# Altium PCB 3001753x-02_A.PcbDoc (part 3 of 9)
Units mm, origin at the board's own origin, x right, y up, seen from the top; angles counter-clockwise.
Board outline 210 x 130 mm, 8 copper layers (1-TOP, 2-GND, 3-INTOP, 4-PWR, 5-PWR, 6-INBOT, 7-GND, 8-BOTTOM), stack 1.646 mm thick; 651 components, 607 nets, 2780 pads, 1706 vias.

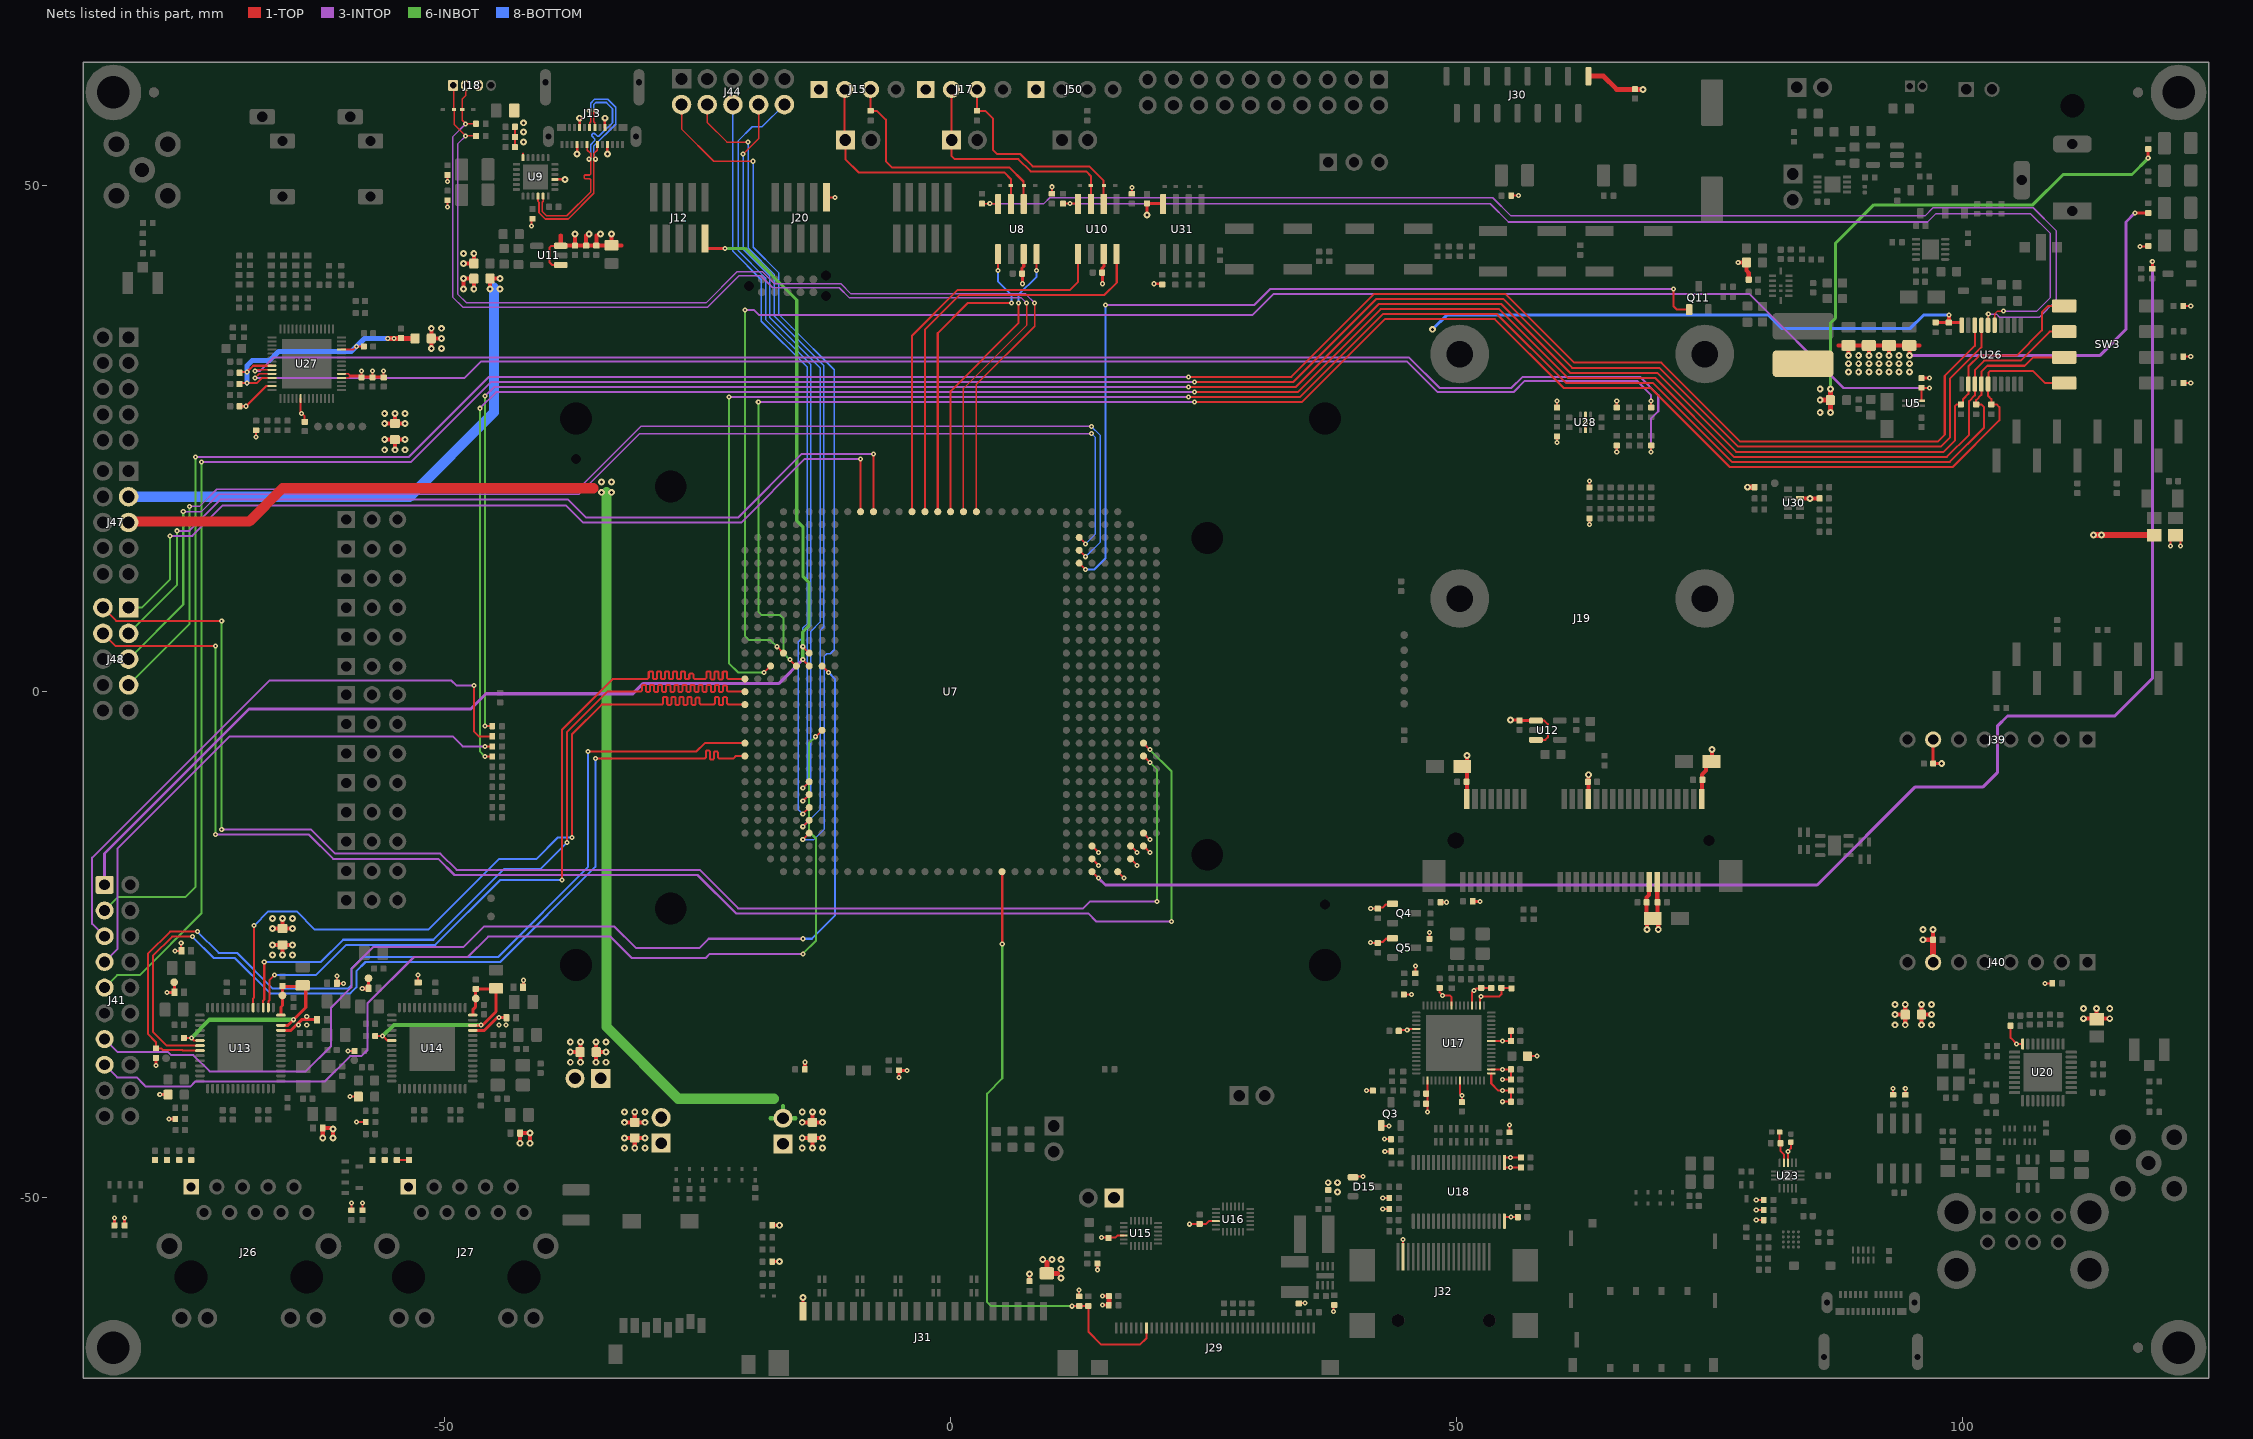
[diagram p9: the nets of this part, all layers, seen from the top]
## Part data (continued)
L17 L22 L23 L24 L25 L28 L38 L39: library part 1001174, "FERRITE BEAD 220 OHM 2.0A 0805", Manufacturer="Wurth Electronics Inc", Manufacturer_Part_Number=742792022, Package_Type=0805
L26 L27: library part 1001173, "CHOKE COM MODE 120 OHM .37A", Manufacturer="Wurth Electronics Inc", Package_Type=SMT
L32 L33 L34 L35 L36 L37: library part 1002041, "FERRITE BEAD 1.8 KOHM 0402 1LN", Manufacturer=Murata, Manufacturer_Part_Number=BLM15HD182SN1D, Package_Type=0402
L42: library part 1002050, "FIXED IND 22UH 590MA 432 MOHM", Manufacturer="Taiyo Yuden", Manufacturer_Part_Number=NR4018T220M, Package_Type=SMT
Q1 Q3 Q4 Q5 Q6: library part 1002855, "MOSFET N-CH 20V 3.4A SOT23-3", Manufacturer="Diodes, Inc.", Manufacturer_Part_Number=ZXMN2A14F, Package_Type=SOT23
Q2 Q11: library part 1000306, "MOSFET N-CH 30V 500MA SOT-23", Manufacturer="On Semiconductor", Package_Type=SOT23
Q7 Q8 Q9 Q10 Q12: library part 1000715, "MOSFET N-CH 60V 115MA SOT-523F", Manufacturer="Fairchild Semiconductor", Package_Type=SOT523F
R1 R127 R144 R146 R147 R148 R149: library part 1001155, "RES 47.0K OHM 1/16W 1% 0402 SMD", Manufacturer="Vishay Dale", Manufacturer_Part_Number=CRCW040247K0FKED, Package_Type=0402, Tolerance=1%
R2 R4 R5 R6 R9 R11 R13 R18 R26 R36 R37 R39 R40 R41 R42 R45 R46 R47 R48 R49 R52 R53 R54 R55 R56 R57 R58 R59 R60 R61 R62 R63 R64 R65 R68 R69 R75 R81 R84 R85 R87 R88 R94 R95 R96 R104 R113 R119 R121 R125 R132 R135 R138 R161 R162 R163 R164 R166 R167 R168 R169 R176 R177 R178 R179 R182 R183 R184 R185 R186 R187 R188 R189 R190 R191 R193 R194 R196 R197 R200 R212 R213 R216 R219 R220 R221 R222 R223 R226 R227 R228 R230 R231 R233 R234 R235: library part 1000076, "RES 0.0 OHM 1/10W 0402 SMD", Manufacturer="Panasonic - ECG", Manufacturer_Part_Number=ERJ-2GE0R00X, Package_Type=0402, Power=10
R3 R8 R14 R25 R29 R30 R82 R91 R157 R158 R159 R202 R203 R204: library part 1000480, "RES 100K OHM 1/10W 1% 0402 SMD", Manufacturer="Panasonic - ECG", Manufacturer_Part_Number=ERJ-2RKF1003X, Package_Type=0402, Power=100, Tolerance=1%
R7 R10 R50 R51 R72 R80 R90 R92 R115 R117 R118 R122 R139 R140 R143 R151 R160 R192 R198 R214 R215 R218 R224 R225 R229 R232: library part 1000537, "RES 10.0K OHM 1/10W 1% 0402 SMD", Manufacturer="Panasonic - ECG", Manufacturer_Part_Number=ERJ-2RKF1002X, Package_Type=0402, Power=100, Tolerance=1%
R12 R15 R154 R195: library part 1001154, "RES 220 OHM 1/16W 1% 0402 SMD", Manufacturer=Yageo, Manufacturer_Part_Number=RC0402FR-07220RL, Package_Type=0402, Tolerance=1%
R16 R17 R23 R24 R33 R34 R35 R38 R43 R44 R73 R74 R101 R102 R105 R110 R111 R116 R141 R170 R171 R205: library part 1000208, "RES 0.0 OHM 1/10W 0603", Manufacturer="Panasonic - ECG", Manufacturer_Part_Number=ERJ-3GEY0R00V, Package_Type=0603, Voltage=75V
R19 R32 R76 R145: library part 1001200, "RES 12.0K OHM 1/10W 1% 0603 SMD", Manufacturer=Yageo, Manufacturer_Part_Number=RC0603FR-0712KL, Package_Type=0603, Power=100, Tolerance=1
R20 R131 R134 R137 R165 R173 R175 R180 R181: library part 1001156, "RES 2.20K OHM 1/16W 1% 0402 SMD", Manufacturer=Yageo, Manufacturer_Part_Number=RC0402FR-072K2L, Package_Type=0402, Tolerance=1%
R21 R79 R83: library part 1000142, "RES 20K OHM 1/10W 5% 0603 SMD", Manufacturer="Panasonic - ECG", Manufacturer_Part_Number=ERJ-3GEYJ203V, Package_Type=0603, Power=100, Tolerance=5
R22: library part 1000980, "RES 2.2M OHM 1/20W 5% 0201 SMD", Manufacturer=Rohm, Manufacturer_Alt_1="Panasonic - ECG", Manufacturer_Alt_1_Part_Number=ERJ-1GEJ225C, Manufacturer_Part_Number=MCR006YZPJ225, Package_Type=0201, Power=50, Tolerance=5
R27 R31: library part 1000701, "RES 470K OHM 1/10W 1% 0402 SMD", Manufacturer="Panasonic - ECG", Manufacturer_Part_Number=ERJ-2RKF4703X, Package_Type=0402, Power=100, Tolerance=1%
R28: library part 1001518, "RES 53.6K OHM 1/10W 1% 0603 SMD", Manufacturer="Panasonic - ECG", Manufacturer_Part_Number=ERJ-3EKF5362V, Package_Type=0603
R66 R70 R71 R77 R97 R98 R107 R108 R206 R207 R208 R209 R236: library part 1001158, "RES 120 OHM 1/16W 1% 0402 SMD", Manufacturer=Yageo, Manufacturer_Part_Number=RC0402FR-07120RL, Package_Type=0402, Tolerance=1%
R67 R78 R130 R133 R136 R172 R174 R199: library part 1000079, "RES 1.00K OHM 1/10W 1% 0402 SMD", Manufacturer="Panasonic - ECG", Manufacturer_Part_Number=ERJ-2RKF1001X, Package_Type=0402, Power=10
R86 R89 R93: library part 1000601, "RES 22.0 OHM 1/10W 1% 0402 SMD", Manufacturer="Panasonic - ECG", Manufacturer_Part_Number=ERJ-2RKF22R0X, Package_Type=0402, Power=100, Tolerance=1%
R99 R106 R109 R114: library part 1000474, "RES 4.99K OHM 1/10W 1% 0402 SMD", Manufacturer="Panasonic - ECG", Manufacturer_Part_Number=ERJ-2RKF4991X, Package_Type=0402, Power=100, Tolerance=1%
R100: library part 1000229, "RES 0.0 OHM 1/2W 1210 SMD", Manufacturer="Vishay Dale", Manufacturer_Part_Number=CRCW12100000Z0EA, Package_Type=1210
R103 R112: library part 1000537, "RES 10.0K OHM 1/10W 1% 0402 SMD"
R120: library part 1001153, "RES 27.0K OHM 1/16W 1% 0402 SMD", Manufacturer=Yageo, Manufacturer_Part_Number=RC0402FR-0727KL, Package_Type=0402, Tolerance=1%
R123 R142: library part 1000971, "RES 1.00M OHM 1/16W 1% 0402 SMD", Manufacturer=Yageo, Manufacturer_Part_Number=RC0402FR-071ML, Package_Type=0402, Power=63, Tolerance=1
R124: library part 1002748, "RES 5.97K OHM 0.1% 1/10W 0402", Manufacturer="Vishay Dale", Manufacturer_Part_Number=TNPW04025K97BEED, Package_Type=0402
R126: library part 1000174, "RES 15.0K OHM 1/10W 1% 0402 SMD", Manufacturer="Panasonic - ECG", Manufacturer_Part_Number=ERJ-2RKF1502X, Package_Type=0402, Power=10, Tolerance=1%
R128 R129 R153 R155 R156: library part 1000038, "RES 4.7K OHM 1/10W 5% 0402 SMD", Manufacturer="Panasonic - ECG", Manufacturer_Part_Number=ERJ-2GEJ472X, Package_Type=0402, Power=100, Tolerance=5
R150: library part 1000170, "RES 52.3K OHM 1/10W 1% 0402 SMD", Manufacturer="Panasonic - ECG", Manufacturer_Part_Number=ERJ-2RKF5232X, Package_Type=0402, Power=10, Tolerance=1%
R152: library part 1001150, "RES 316K OHM 1/10W 1% 0603 SMD", Manufacturer=Yageo, Manufacturer_Part_Number=RC0603FR-07316KL, Package_Type=0603, Power=100, Tolerance=1%
R201: library part 1001149, "RES 22.1K OHM 1/16W 1% 0402 SMD", Manufacturer="Vishay Dale", Manufacturer_Part_Number=CRCW040222K1FKED, Package_Type=0402, Power=0,063, Tolerance=±100ppm/°C
R217: library part 1000711, "RES 10.0 OHM 1/10W 1% 0402 SMD", Manufacturer="Panasonic - ECG", Manufacturer_Part_Number=ERJ-2RKF10R0X, Package_Type=0402, Power=100, Tolerance=1%
SW1 SW2 SW4 SW5: library part 1001124, "SWITCH TACTILE SPST-NO 0.05A 32V", Manufacturer=ITT, Package_Type=SMT
SW3: library part 1002122, "SWITCH SLIDE DIP SPST 100MA 20V", Manufacturer=CTS, Package_Type=SOIC
SWD1: library part CAD0066, "CBL PLUG-OF-NAILS 10-PIN", Package_Type=SMT
TP1 TP2 TP3 TP4 TP5 TP7 TP8 TP9 TP10 TP11 TP12 TP13 TP14 TP15 TP16 TP17 TP18 TP19 TP20: library part CAD0011, "TEST POINT 30MIL PAD SMT", Package_Type=TP
TP6: library part CAD0011, "TEST POINT 30mil PAD SMT", Package_Type=TP
U1: library part 1002744, "IC ELECTRONIC FUSE 10VFDFPN", Manufacturer=STMicroelectronics, Package_Type=SON
U2: library part 1001163, "MOSFET P-CH 20V 3.7A SOT23-3", Manufacturer="Vishay Siliconix", Package_Type=SMT
U3 U11 U12: library part 1001979, "IC REG LDO ADJ 0.15A SOT25", Manufacturer="Diodes, Inc.", Manufacturer_Part_Number=AP2202K-ADJTRG1, Package_Type=SOT23-5
U4: library part 1000217, "IC OPAMP DUAL 1.6V 9KHZ 8TDFN", Manufacturer=Microchip, Package_Type=DFN
U5: library part 1001857, "IC SW W/CTRL SLEW RATE 4TDFN", Manufacturer="Vishay Siliconix", Manufacturer_Part_Number=SIP32401ADNP-T1GE4, Package_Type=SON
U6: library part 1001907, "IC REG BUCK ADJ 3A SYNC", Manufacturer="Linear Technology", Manufacturer_Part_Number=MP2316GD, Package_Type=QFN
U7: library part 1002856, "ConnectCore for i.MX93 module", Manufacturer=DIGI, Manufacturer_Part_Number=55002169-01, Package_Type=LGA
U8 U10: library part 1002681, "IC CAN TRANSEIVER HS 8SOIC", Manufacturer="Texas Instruments", Package_Type=SOIC
U9: library part 1002827, "IC USB TO SERIAL BRIDGE 24QFN", Manufacturer="Cypress Semiconductor", Package_Type=QFN
U13 U14: library part 1002844, "IC TXRX FULL/HALF 4/4 56QFN", Manufacturer=Marvell, Package_Type=QFN
U15 U16: library part 1002697, "IC SWITCH TPDT DIFF XQFN24", Manufacturer="NXP Semiconductors", Manufacturer_Part_Number=NX3DV642GU, Package_Type=QFN
U17: library part 1002722, "MIPI DSI BRIDGE TO LVDS/HDMI SINGLE CHANNEL", Manufacturer="Lontium Semiconductor", Package_Type=QFN
U18: library part 1001125, "IC HDMI XMITTER PORT P/I 38TSSOP", Manufacturer="On Semiconductor", Package_Type=SOP
U19: library part 1001143, "IC SW DISTRIBUTION 2CHAN 8SOIC", Manufacturer=Micrel, Manufacturer_Part_Number=MIC2026-1YM, Package_Type=SOIC
U20: library part 1001114, "4-PORT USB 2.0 HUB CTRLR 36VQFN", Manufacturer=SMSC, Package_Type=QFN
U21 U22: library part 1002838, "SMIC, COMMON MODE USB2.0/MIPI + ESD, QFN6, -40/+125°C"
U23: library part 1002585, "IC USB PD TCPC PHY HX2QFN16", Manufacturer="NXP Semiconductors", Package_Type=QFN
U24 U25: library part 1001265, "TVS DIODE 5.5VWM 6SON", Manufacturer="Texas Instruments", Package_Type=SMT
U26: library part 1001368, "IC SWITCH BUS 8BIT FET 20-TSSOP", Manufacturer="Texas Instruments", Package_Type=TSSOP
U27: library part 1002001, "IC CODEC AUDIO FLEXSOUND 56TQFN", Manufacturer=Maxim, Manufacturer_Part_Number=MAX98089ETN+T, Package_Type=QFN
U28: library part 1002493, "MOSFET 2N-CH 30V 0.1A ES6", Manufacturer="Diodes, Inc.", Package_Type=SOT523F
U29: library part 1002036, "LED Driver IC 1 Output DC DC Regulator Step-Up (Boost) PWM Dimming 500mA (Switch) 8-DFN (3x2)", Manufacturer="Linear Technology", Manufacturer_Part_Number=LT3591EDDB#TRMPBF, Package_Type=DFN
U30: library part 1002829, "SMIC, RTC, I2C, RV-3028-C7, 45n@3V, DFN-8, -40/+85°C", Manufacturer="Micro Commercial Co", Manufacturer_Name="Micro Crystal AG", Manufacturer_Part_Number="RV-3028-C7 32.768kHz 1ppm TA QC", Package_Type=DFN
U31: library part 1001420, "IC TRANSCEIVER RS485 8-SOIC", Manufacturer="Linear Technology", Package_Type=SOIC
U32: library part 1002586, "IC USB POWER SWITCH 16WLCSP", Manufacturer="NXP Semiconductors", Package_Type=BGA
X1 X2 X3: library part 1001497, "SMCRY,25MHZ 50PPM 20PF RH100 EXT", Manufacturer=Raltron, Package_Type=SMT
X4: library part 1001134, "CRYSTAL 24MHZ 18PF SMD", Manufacturer=Aker, Manufacturer_Part_Number=C3E-24.000-18-3030-X-R, Package_Type=SMT

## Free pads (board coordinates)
  round 0 / inner round 0 / far side round 6 hole 3.15 unplated: MH-1(-27.65,-21.4) MH-2(25.35,-16.1) MH-3(25.35,15.2) MH-4(-27.65,20.275)
  round 5.5 hole 3.2: TOOL1(-82.7,59.2) TOOL2(-82.7,-64.8) TOOL3(121.3,-64.8) TOOL4(121.3,59.2)

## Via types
v1: diameter 0.5, hole 0.2, 1-TOP to 8-BOTTOM, 1453 vias
v2: diameter 0.68, hole 0.3, 1-TOP to 8-BOTTOM, 253 vias

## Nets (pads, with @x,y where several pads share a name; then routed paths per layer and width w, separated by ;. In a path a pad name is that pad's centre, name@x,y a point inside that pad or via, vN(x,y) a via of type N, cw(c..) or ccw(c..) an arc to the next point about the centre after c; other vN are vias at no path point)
1V0_PHY_1: C77.2 C78.2 C79.2 TP9.1 U13.6 U13.40 U13.42 | length 23.1
  1-TOP w0.2: C77.2@-75.74,-34.2 v1(-75,-34.2) -74.75,-34.45 U13.6@-74.15,-34.45 ; C79.2@-64,-29 -63.9,-29.1 C79.2@-63.75,-29.25
  1-TOP w0.3: U13.40@-66.15,-32.95 -65.45,-32.95 v1(-64.9,-32.4) -63.7,-31.2 -63.7,-29.3 C79.2@-63.75,-29.25 ; U13.42@-66.15,-31.95 -66.15,-31.15 -66,-31 TP9.1@-66,-30 C78.2@-66,-29.1 ; C78.2@-66,-29.06 C78.2@-66,-29.1 ; C79.2@-63.9,-29.1 C78.2@-66,-29.1
  6-INBOT w0.4: v1(-75,-34.2) -73.2,-32.4 v1(-64.9,-32.4)
1V0_PHY_2: C104.2 C105.2 C106.2 TP12.1 U14.6 U14.40 U14.42 | length 21.7
  1-TOP w0.2: C104.2@-56.84,-34 v1(-56.1,-34) -55.65,-34.45 U14.6@-55.2,-34.45
  1-TOP w0.3: U14.40@-47.2,-32.95 v1@-46.4,-32.95 ; U14.42@-47.2,-31.95 -47.2,-31.4 -46.91,-31.11 C105.2@-46.91,-29.36 ; C105.2@-46.9,-29.36 -44.96,-29.36 C106.2@-44.9,-29.3 -44.9,-31.6 v1@-46.25,-32.95
  6-INBOT w0.4: v1(-56.1,-34) -55,-32.9 v1(-46.4,-32.9)
1V8: J8.2 J47.5 R44.1 R45.1 R203.1 U7.AH1 U7.AH2 U7.AH3 | length 287.1
  1-TOP w0.2: U7.AH1@13.97,-17.78 v1(14.605,-18.415) ; U7.AH2@13.97,-16.51 v1(14.605,-17.145) ; U7.AH3@13.97,-15.24 v1(14.605,-15.875)
  1-TOP w0.3: R203.1@118.7,41.78 v1(118.7,42.5)
  1-TOP w0.4: v2(-14.654,-42.53) R44.1@-13.654,-42.53 ; R45.1@-14.4,-37.3 v1(-14.4,-36.6) ; v2(-13.654,-41.53) R44.1@-13.654,-42.53 ; v2(-12.654,-42.53) R44.1@-13.654,-42.53
  1-TOP w1: J47.5@-81.2,16.72 -81.12,16.8 -69.29,16.8 -65.99,20.1 -35.3,20.1
  3-INTOP w0.3: v1(14.605,-18.415) 15.29,-19.1 85.6,-19.1 95.3,-9.4 102,-9.4 103.4,-8 103.4,-3.4 104.4,-2.4 115,-2.4 118.7,1.3 v1(118.7,42.5)
  6-INBOT w0.4: -17.8,-42.13 J8.2@-16.554,-42.13 J8.2@-16.543,-42.13 ; J8.2@-16.543,-42.134 J8.2@-16.543,-42.13 ; -16.543,-40.9 J8.2@-16.543,-42.13 ; -15.308,-42.13 J8.2@-16.543,-42.13
  6-INBOT w1: -34,19.7 -34,-33.1 -26.9,-40.2 -17.47,-40.2
  other v2: -14.654,-41.53 -12.654,-41.53 -34.5,19.7 -33.5,19.7 -34.5,20.7 -33.5,20.7
1V8_CODEC: C175.2 C176.1 C177.1 C178.1 R171.2 U27.25 U27.50 U27.53 | length 29.2
  1-TOP w0.2: C178.1@-70.2,30.5 -68.5,30.5 -68,31 U27.53@-67.03,31 ; C177.1@-70.2,31.6 v1(-69.5,31.6) -68.9,32.2 U27.50@-67.03,32.2 ; U27.25@-60.17,33.8 -59,33.8 v1(-58.7,34.1) C176.1@-57.96,34.1
  1-TOP w0.5: v1(-55.6,34.9) v1(-55,34.9) -54.34,34.9 C175.2@-54.3,34.94 ; C175.2@-54.3,34.9 R171.2@-52.9,34.9
  8-BOTTOM w0.5: v1(-69.5,30.5) v1(-69.5,31.6) -69.5,32.2 -69,32.7 -67.3,32.7 -66.4,33.6 -59.2,33.6 v1(-58.7,34.1) -57.9,34.9 v1(-55.6,34.9) v1(-55,34.9)
1V8_PHY_1: L4.2 L5.2 L6.2 R99.1 R101.1 R103.2 TP8.1 U13.39 | length 9.3
  1-TOP w0.2: v1(-76.62,-25.6) L4.2@-75.98,-25.6 -76,-25.58 v1(-76,-24.8)
  1-TOP w0.3: v1(-78.5,-36.9) R99.1@-78.5,-36.18 ; v1(-78.12,-39.8) R101.1@-77.4,-39.8 ; v1(-77.4,-29.7) -76.8,-29.7 -76.74,-29.76 L6.2@-76.68,-29.7 -76.68,-28.72 TP8.1@-76.7,-28.7 ; v1(-77.2,-42.2) R103.2@-76.58,-42.2 ; U13.39@-66.15,-33.45 -65.15,-33.45 -64.1,-32.4 L5.2@-62.58,-32.4
  other v1: -64.4,-32.9 -63.6,-32.9 -63.6,-32.1
1V8_PHY_2: L9.2 L10.2 L11.2 R109.1 R110.1 R112.2 TP11.1 U14.39 | length 8.4
  1-TOP w0.2: v1(-59.54,-35.5) R109.1@-58.9,-35.5 ; v1(-59.34,-40) R110.1@-58.7,-40 ; v1(-58.7,-42.5) R112.2@-57.78,-42.5 ; L9.2@-52.6,-28.72 v1(-52.6,-27.98)
  1-TOP w0.3: TP11.1@-57.5,-28.3 -57.48,-28.32 L11.2@-57.48,-29.3 ; U14.39@-47.2,-33.45 -46.05,-33.45 -44.8,-32.2 v1(-44.6,-32.2) L10.2@-43.88,-32.2
  1-TOP w0.4: v1(-58.12,-29.3) L11.2@-57.48,-29.3
  other v1: -44.6,-32.9 -43.9,-32.9
1V8_SOM_EXT: C117.2 C120.2 C121.2 C122.2 C123.2 C125.2 C126.2 C127.2 C128.2 C129.2 C130.2 C131.2 C132.2 C133.2 C134.2 C135.2 C136.2 J8.1 J20.1 Q3.G Q4.G Q5.G R44.2 R119.2 R122.1 R127.1 R130.2 R133.2 R136.2 R171.1 R172.2 R174.2 U17.5 U17.18 U17.26 U17.33 U17.34 U17.41 U17.50 U17.52 U17.57 U28.2 U28.5 | length 48.9
  1-TOP w0.15: R136.2@42.18,-24.8 R136.2@42.2,-24.82
  1-TOP w0.2: J20.1@-12.26,47.796 J20.1@-12.26,47.94 ; J20.1@-12.26,48.832 -12.228,48.8 v1(-11.4,48.8) ; v1(41.48,-24.78) 41.5,-24.8 R136.2@42.18,-24.8 ; v1(41.5,-21.4) 42.18,-21.4 R133.2@42.2,-21.42 ; R136.2@42.305,-24.72 42.685,-24.72 43.005,-24.4 Q5.G@43.605,-24.4 ; R133.2@42.305,-21.32 42.685,-21.32 43.005,-21 Q4.G@43.605,-21 ; Q3.G@42.5,-43.1 42.7,-42.9 v1(43.3,-42.9) ; v1(42.865,-44.2) R130.2@43.5,-44.2 ; v1(42.885,-45.4) R127.1@43.52,-45.4 ; C126.2@44.465,-33.5 44.565,-33.4 v1(45.105,-33.4) 45.205,-33.3 U17.5@45.995,-33.3 ; C125.2@44.765,-29.9 v1(45.505,-29.9) ; R122.1@45.9,-27.82 v1(45.9,-27.1) ; v1(47.1,-41.5) U17.18@47.1,-38.405 ; C123.2@48.305,-29.26 48.305,-29.7 v1(48.605,-30) 49.305,-30 49.5,-30.195 U17.57@49.5,-30.995 ; U17.26@50.3,-38.405 50.3,-39.695 v1(50.505,-39.9) C128.2@50.505,-40.54 ; U17.52@51.5,-30.995 51.5,-29.705 v1(51.703,-29.502) 51.905,-29.3 52.405,-29.3 52.445,-29.26 C135.2@53.405,-29.26 ; U17.50@52.3,-30.995 52.3,-30.205 v1(52.405,-30.1) 54.205,-30.1 54.405,-29.9 C134.2@54.405,-29.26 55.365,-29.26 C133.2@55.405,-29.3 ; U17.33@53.405,-37.7 53.405,-38.7 54.105,-39.4 v1(54.505,-39.4) C127.2@55.345,-39.4 C122.2@55.345,-40.5 ; U17.34@53.405,-37.3 C130.2@55.345,-37.3 C129.2@55.345,-38.3 v1(54.505,-38.3) ; U17.41@53.405,-34.5 C131.2@55.345,-34.5 C132.2@55.345,-33.5 ; v1(54.505,-40.5) C122.2@55.405,-40.5 ; R119.2@55.2,-43.52 v1(55.2,-42.8) ; C117.2@57.058,-36 v1(57.905,-36) ; U28.2@62.7,25.82 U28.5@62.7,27.38 ; v1(65.8,23.7) R172.2@65.8,24.32 ; R174.2@65.8,28.08 v1(65.8,28.7)
  1-TOP w0.4: v2(-51.3,33.9) R171.1@-51.3,34.9 ; v2(-51.3,35.9) R171.1@-51.3,34.9 ; v2(-50.3,34.9) R171.1@-51.3,34.9 ; v2(-14.654,-44.07) R44.2@-13.654,-44.07 ; v2(-13.654,-45.07) R44.2@-13.654,-44.07 ; v2(-12.654,-44.07) R44.2@-13.654,-44.07
  other v1: 54.505,-37.3 54.505,-34.5 62.7,26.6
  other v2: -14.654,-45.07 -12.654,-45.07 -50.3,33.9 -50.3,35.9
3V3: C157.2 J7.2 J18.3 J47.3 R40.1 R43.1 R73.1 R151.2 U7.AK1 U7.AL2 U7.AL3 U7.AM3 U7.AM4 U26.20 | length 118.9
  1-TOP w0.2: R40.1@-5,-37.38 R40.1@-4.98,-37.4 ; U7.AK1@16.51,-17.78 v1(17.145,-18.415) ; U7.AL2@17.78,-16.51 v1(18.415,-17.145) ; U7.AL3@17.78,-15.24 v1(18.415,-15.875) ; U7.AM3@19.05,-15.24 v1(19.685,-15.875) ; U7.AM4@19.05,-13.97 v1(19.685,-14.605)
  1-TOP w0.3: v1(-5.1,-38.1) -5.1,-37.48 R40.1@-5,-37.38 ; R40.1@-4.98,-37.4 v1(-4.3,-37.4) ; R151.2@97.3,36.48 98.6,36.48 U26.20@99.9,36.48
  1-TOP w0.4: v2(-45.5,39.8) R73.1@-45.5,40.8 v2(-44.5,40.8) ; v2(-32.2,-42.53) R43.1@-31.2,-42.53 ; v2(-31.2,-41.53) R43.1@-31.2,-42.53 ; v2(-30.2,-42.53) R43.1@-31.2,-42.53 ; C157.2@98.6,36.46 98.6,36.48 v1(98.6,37.2)
  8-BOTTOM w0.3: v2(47.6,35.8) 49,37.2 80.8,37.2 82.1,35.9 94.8,35.9 96.1,37.2 v1(98.6,37.2)
  8-BOTTOM w1: J47.3@-81.2,19.26 -69.84,19.26 -53.44,19.26 -45.1,27.6 -45.1,39.943
  other v2: -32.2,-41.53 -30.2,-41.53 -44.5,39.8
3V3_BOARD: C17.2 C18.2 C19.2 C20.2 C23.2 C39.1 C40.1 C41.1 C42.1 C43.2 C44.2 C45.2 C46.2 C47.2 J19.2 J19.24 J19.39 J19.41 J19.52 L1.2 L39.1 R15.2 R28.2 R80.2 U12.1 U12.3 | length 86.3
  1-TOP w0.2: U12.3@57.82,-4.75 58.75,-4.75 59,-4.5 59,-3.2 58.65,-2.85 U12.1@57.82,-2.85
  1-TOP w0.3: R80.2@51.58,-20.7 v1(52.3,-20.7) ; v2(55.3,-2.8) 56.16,-2.8 C39.1@56.2,-2.84 ; C39.1@56.2,-2.85 U12.1@57.82,-2.85 ; v1(117,47.3) R15.2@118.3,47.3
  1-TOP w0.4: J19.2@51,-10.6 v2(51,-6.3) ; J19.24@63,-10.6 v2(63,-8.2) ; v2(68.8,-23.5) C42.1@68.8,-22.95 ; J19.39@69,-18.8 69,-20.1 68.76,-20.34 C46.2@68.76,-20.8 68.76,-21.81 C42.1@69.35,-22.4 ; C43.2@69.8,-20.96 J19.41@69.8,-18.8 ; C43.2@69.84,-20.8 69.84,-21.91 C42.1@69.35,-22.4 ; v2(69.9,-23.5) 69.9,-22.95 C42.1@69.35,-22.4 ; J19.52@74.2,-10.6 74.2,-8.2 74.6,-7.8 C41.1@74.6,-7.1 ; C41.1@75.2,-6.4 v2(75.2,-5.7) ; v1(77.8,42.4) R28.2@78.6,42.4 78.6,41.6 78.84,41.36 C23.2@78.84,40.7 ; 87.7,34.2 C20.2@88.7,34.2 ; v2(88.7,33.2) C20.2@88.7,34.2 ; v2(90.7,33.2) C19.2@90.7,34.2 91.7,34.2 ; v2(92.7,33.2) C18.2@92.7,34.2 ; v2(94.7,33.2) C17.2@94.7,34.2 95.7,34.2 ; C17.2@94.8,34.2 C18.2@92.7,34.2 ; L39.1@118.95,15.5 L39.1@119,15.45 ; C20.2@88.7,34.2 C18.2@92.7,34.2
  1-TOP w0.6: v2(113.7,15.5) v2(112.9,15.5) L39.1@118.95,15.5
  3-INTOP w0.3: v2(94.7,33.2) 113.5,33.2 116.1,35.8 116.1,46.4 v1(117,47.3)
  other v2: 88.7,31.6 89.7,31.6 90.7,31.6 91.7,31.6 92.7,31.6 93.7,31.6 94.7,31.6 88.7,32.4 89.7,32.4 90.7,32.4 91.7,32.4 92.7,32.4 93.7,32.4 94.7,32.4 89.7,33.2 91.7,33.2 93.7,33.2
3V3_BOARD_EN: Q11.G U7.AG25 | length 88.5
  1-TOP w0.2: U7.AG25@12.7,12.7 v1(13.335,12.065) ; v1(71.4,39.8) 71.4,38.1 71.75,37.75 Q11.G@72.95,37.75
  3-INTOP w0.2: v1(15.3,38.2) 30,38.2 31.6,39.8 v1(71.4,39.8)
  8-BOTTOM w0.2: v1(13.335,12.065) 14.165,12.065 15.3,13.2 v1(15.3,38.2)
3V3_CODEC: C171.2 C173.2 C182.2 C183.1 C184.1 R170.2 U27.6 U27.18 U27.19 U27.55 | length 16.6
  1-TOP w0.15: U27.18@-60.17,31 -59.5,31 -59.3,31.2 -59.5,31.4 U27.19@-60.17,31.4
  1-TOP w0.2: C173.2@-70.24,28.2 v1(-69.6,28.2) -67.6,30.2 U27.55@-67.03,30.2 ; U27.6@-64.2,28.97 -64.2,27.6 v1(-64.1,27.5) -63.8,27.2 C171.2@-63.8,26.66 ; C184.1@-58.2,31.06 -58.2,31.1 v1(-58.2,31.7) ; C183.1@-57.1,31.06 -57.1,31.1 v1(-57.1,31.7) ; C182.2@-56,31.06 -56,31.1 v1(-56,31.7)
  1-TOP w0.3: -59.3,31.2 C184.1@-58.2,31.2 ; C184.1@-58.2,31.1 -57.1,31.1 C182.2@-56,31.1
  1-TOP w0.4: v2(-55.9,26.5) R170.2@-54.9,26.5 ; v2(-54.9,27.5) R170.2@-54.9,26.5 ; v2(-53.9,26.5) R170.2@-54.9,26.5
  other v2: -55.9,27.5 -53.9,27.5
3V3_DBG: C30.2 C35.2 C36.2 C37.2 R70.1 R71.1 R72.2 R73.2 R74.2 U9.24 | length 9.5
  1-TOP w0.2: v1(-49.7,47.9) R71.1@-49.7,48.54 ; v1(-49.7,50.4) R70.1@-49.7,51.04 ; C30.2@-43.04,53.8 C37.2@-43.04,54.8 C36.2@-43.04,55.9 ; U9.24@-42.25,52.75 -42.25,53.15 ; v1(-41.4,46) -41.4,46.62 R72.2@-41.3,46.72
  1-TOP w0.4: v2(-48.1,39.8) v2(-48.1,40.8) R73.2@-47.1,40.8 v2(-47.1,39.8) ; v2(-48.1,42.3) R74.2@-47.1,42.3 v2(-47.1,43.3)
  other v2: -48.1,43.3 -42.2,54.3 -42.2,55.3 -42.2,56.2
3V3_ETH1: L2.2 L3.2 R97.1 R98.1 R105.2 | length 8.7
  1-TOP w0.2: L2.2@-60.62,-28.8 v1(-59.98,-28.8) ; L2.2@-60.6,-28.7 v1(-60.6,-28.06)
  1-TOP w0.3: R97.1@-82.6,-52.72 v1(-82.6,-52) ; R98.1@-81.6,-52.72 v1(-81.6,-52)
  1-TOP w0.4: v2(-67,-25) R105.2@-66,-25 ; v2(-66,-26) R105.2@-66,-25 ; v2(-65,-25) R105.2@-66,-25 ; v2(-62.02,-44.1) L3.2@-62.02,-43.1 -61.1,-43.1 v2(-61,-43.2) -61,-44.08 v2(-61.02,-44.1)
  other v2: -67,-26 -65,-26
3V3_ETH2: J34.2 L7.2 L8.2 R107.1 R108.1 R205.2 | length 8.1
  1-TOP w0.2: R107.1@-59.2,-51.22 v1(-59.2,-50.5) ; R108.1@-58.1,-51.22 v1(-58.1,-50.5)
  1-TOP w0.3: L7.2@-42.22,-29.2 -42.2,-29.18 v1(-42.2,-28.5)
  1-TOP w0.4: v2(-42.54,-44.6) -42.54,-43.6 v2(-41.54,-43.6) v2(-41.54,-44.6) ; v2(-37.57,-35.6) R205.2@-36.57,-35.6 ; v2(-36.57,-36.6) R205.2@-36.57,-35.6 ; v2(-36.57,-34.6) R205.2@-36.57,-35.6
  other v2: -37.57,-36.6 -37.57,-34.6
3V3_RF: J12.2 J41.1 U7.F17 U7.F18 | length 130.2
  1-TOP w0.2: v1(-14.605,3.175) U7.F17@-13.97,2.54 ; v1(-14.605,4.445) U7.F18@-13.97,3.81
  1-TOP w0.3: J12.2@-24.26,44.768 -24.26,43.8 v1(-22.3,43.8)
  3-INTOP w0.3: J41.1@-83.57,-19.07 -83.57,-15.97 -69.3,-1.7 -47.4,-1.7 -45.9,-0.2 -31.4,-0.2 -30.4,0.8 -16.98,0.8 v1(-14.605,3.175)
  6-INBOT w0.3: v1(-22.3,43.8) -20.3,43.8 -15.2,38.7 -15.2,16.9 -14.6,16.3 -14.6,11.4 -14,10.8 -14,6.5 -14.605,5.895 v1(-14.605,4.445) v1(-14.605,3.175)
3V3_SOM_EXT: C108.1 C109.1 C110.2 C145.2 C191.2 C193.2 C194.2 C195.2 D15.A J7.1 J28.1 J30.1 J31.1 J34.1 J39.7 J50.1 L38.1 R12.2 R29.2 R43.2 R50.2 R51.1 R65.2 R75.2 R87.2 R88.2 R105.1 R115.1 R118.1 R131.2 R134.2 R137.2 R141.1 R149.1 R153.2 R155.2 R156.2 R160.1 R170.1 R173.2 R175.2 R180.2 R181.2 R192.1 R205.1 R207.2 R213.2 R214.1 R215.1 R219.2 R224.2 R232.2 U15.10 U16.10 U23.3 U30.7 U31.8 | length 61.1
  1-TOP w0.2: v1(-68.6,25.18) R160.1@-68.6,25.82 ; R65.2@10,49.18 v1(10,49.88) ; R214.1@12.7,-59.72 v1(12.7,-59.1) ; v1(14.9,-53.9) 16.3,-53.9 16.5,-53.7 U15.10@17.105,-53.7 ; R219.2@15.62,-60.6 R219.2@15.64,-60.58 ; R75.2@17.9,49.18 v1(17.9,49.8) ; v1(20.1,40.3) 20.82,40.3 R232.2@20.9,40.22 ; U31.8@20.915,48.24 U31.8@20.985,48.17 ; v1(23.6,-52.6) 25.2,-52.6 25.5,-52.3 U16.10@26.205,-52.3 ; R213.2@34.4,-60.42 34.42,-60.4 v1(35,-60.4) ; R215.1@37.78,-60.7 37.8,-60.72 v1(37.8,-61.2) ; D15.A@40.1,-47.9 v1(40.735,-47.9) ; v1(41.085,-39.4) R131.2@41.72,-39.4 ; v1(47.3,-23.8) 47.3,-24.415 R137.2@47.305,-24.42 ; R134.2@48.385,-20.795 v1(49,-20.795) ; R207.2@55.393,49 v1(56.1,49) ; v1(59.9,24.6) R175.2@59.9,25.22 ; R173.2@59.9,28.08 v1(59.9,28.7) ; v1(63.1,16.5) R181.2@63.1,17.12 ; R180.2@63.1,20.18 v1(63.1,20.8) ; v1(79.58,-52.2) R149.1@80.32,-52.2 ; v1(79.58,-51.2) R192.1@80.32,-51.2 ; v1(79.58,-50.2) R51.1@80.32,-50.2 ; U23.3@82.7,-46.55 v1(82.7,-45.4) 83,-45.1 C195.2@83,-44.5 ; v1(108.1,-28.8) R50.2@108.82,-28.8 ; v1(117.5,44) 118.28,44 R12.2@118.3,44.02 ; v1(120.5,14.4) L38.1@120.5,14.9 ; v1(121.5,14.4) L38.1@121.5,14.9 ; R155.2@121.76,33.1 v1(122.5,33.1) ; R153.2@121.76,38.1 v1(122.5,38.1) ; R156.2@121.78,30.5 v1(122.5,30.5)
  1-TOP w0.3: R88.2@-17.62,-56.3 v2(-16.9,-56.3) ; R87.2@-17.62,-52.7 v2(-16.9,-52.7) ; J31.1@-14.575,-61.2 v2(-14.575,-59.85) ; R118.1@7.8,-58.22 v2(7.8,-57.5) ; v1(14.5,-57.1) R115.1@14.5,-56.48 ; v1(15,-60.6) R219.2@15.62,-60.6 ; v1(15,-59.7) C191.2@15.64,-59.7 ; v2(19.4,47.1) C194.2@19.4,48.24 U31.8@20.915,48.24 ; R29.2@95.8,31 v1(96.7,31) ; J39.7@97.06,-4.725 C145.2@97.06,-7.1 v2(97.9,-7.1)
  1-TOP w0.4: v2(-67,-23.4) R105.1@-66,-23.4 ; v2(-66,-22.4) R105.1@-66,-23.4 ; v2(-65,-23.4) R105.1@-66,-23.4 ; v2(-55.9,24.9) R170.1@-54.9,24.9 ; v2(-54.9,23.9) R170.1@-54.9,24.9 ; v2(-53.9,24.9) R170.1@-54.9,24.9 ; v2(-35.03,-36.6) R205.1@-35.03,-35.6 ; v2(-35.03,-34.6) R205.1@-35.03,-35.6 ; v2(-34.03,-35.6) R205.1@-35,-35.6 R205.1@-35.03,-35.6 ; v2(-32.2,-44.07) R43.2@-31.2,-44.07 ; v2(-31.2,-45.07) R43.2@-31.2,-44.07 ; v2(-30.2,-44.07) R43.2@-31.2,-44.07 ; U30.7@83.9,19.1 C193.2@85.84,19.1 ; v2(93.3,-31.9) R141.1@94.3,-31.9 ; v2(94.3,-32.9) R141.1@94.3,-31.9 ; v2(94.3,-30.9) R141.1@94.3,-31.9
  1-TOP w0.5: R219.2@15.64,-60.58 C191.2@15.64,-59.7 ; J30.1@63,60.8 64.5,60.8 65.8,59.5 v2(68.4,59.5) ; v2(78.7,20.2) R224.2@79.42,20.2
  other v2: -32.2,-45.07 -30.2,-45.07 -34.03,-36.6 -34.03,-34.6 93.3,-32.9 93.3,-30.9 -67,-22.4 -65,-22.4 84.9,19.1 -55.9,23.9 -53.9,23.9
3V3_USB: L28.2 R139.2 R140.2 R141.2 R143.2 U20.27 | length 10.3
  1-TOP w0.2: R140.2@93.1,-39.82 v1(93.1,-39.2) ; R139.2@94.3,-39.82 v1(94.3,-39.2) ; R143.2@104.7,-33.1 104.7,-34.2 v1(105.3,-34.8) U20.27@105.9,-34.8
  1-TOP w0.4: v2(95.9,-32.9) R141.2@95.9,-31.9 ; v2(95.9,-30.9) R141.2@95.9,-31.9 ; v2(96.9,-31.9) R141.2@95.9,-31.9 ; v2(111.9,-32.3) L28.2@113.15,-32.3 ; L28.2@113.2,-32.35 v2(113.2,-31.3) ; L28.2@113.25,-32.3 v2(114.5,-32.3)
  other v2: 96.9,-32.9 111.9,-31.3 114.5,-31.3 96.9,-30.9
5V: C29.1 C32.1 C111.2 C112.2 C146.1 J15.1 J17.1 J40.7 L17.1 R24.2 R195.2 R216.1 U8.3 U10.3 U18.1 | length 69.7
  1-TOP w0.2: 10.55,-57.45 10.6,-57.4 ; v2@10.65,-56.1 v2(10.9,-56.1) ; C111.2@56.1,-46 v1(55.3,-46) 54.7,-46 U18.1@54.7,-46.5 54.7,-47 v1(55.3,-47) C112.2@56.14,-47
  1-TOP w0.3: v1(7.1,40.3) 7.1,41.26 C29.1@7.06,41.3 7.06,41.86 7.225,42.025 U8.3@7.225,43.23 ; v1(15,40.3) 15,41.215 15.015,41.23 14.975,41.27 14.975,41.83 15.14,41.995 U10.3@15.14,43.2 ; v1(118.3,52.7) R195.2@118.3,53.62
  1-TOP w0.4: v2(96.04,-24.5) C146.1@97.04,-24.5 v2(97.04,-23.5)
  1-TOP w0.5: 9.5,-56.4 L17.1@9.5,-57.45 10.55,-57.45 ; v2(85.9,28.8) R24.2@86.9,28.8 ; v2(86.9,27.6) R24.2@86.9,28.8 ; v2(86.9,29.9) R24.2@86.9,28.8
  1-TOP w0.6: C146.1@97.04,-24.5 97.04,-26.705 J40.7@97.06,-26.725
  6-INBOT w0.3: v2(86.9,29.9) 86.9,36.4 87.4,36.9 87.4,44.3 91.2,48.1 106.9,48.1 109.9,51.1 116.7,51.1 v1(118.3,52.7)
  other v2: 10.9,-57.9 10.9,-57 9.1,-56.1 10,-56.1 38.2,-49.4 37.3,-48.5 38.2,-48.5 96.04,-23.5 85.9,27.6 85.9,29.9
5V_DBG: C26.2 C27.2 C28.2 C34.1 J13.A4 J13.A9 J13.B4 J13.B9 U9.15 U11.1 U11.3 | length 19.5
  1-TOP w0.2: U11.1@-38.52,42.15 -39.35,42.15 -39.6,42.4 -39.6,43.9 -39.45,44.05 U11.3@-38.52,44.05 U11.3@-38.51,44.06 ; C26.2@-33.54,44.06 C26.2@-33.5,44.1
  1-TOP w0.25: U9.15@-39.1,50.6 v2(-38.1,50.6) ; v2(-36.9,53.12) J13.A9@-36.9,54.035 ; J13.B4@-36.65,55.735 v2(-36.65,56.65) ; J13.B9@-34.15,55.735 v2(-34.15,56.65) ; v2(-33.9,53.12) J13.A4@-33.9,54.035
  1-TOP w0.4: -38.51,45.06 -38.51,44.06 C34.1@-37.1,44.06 ; v2@-37.1,45.06 C34.1@-37.1,44.06 ; v2@-36,45.06 C27.2@-36,44.06 ; -35,45.06 C28.2@-35,44.06 ; C26.2@-33.54,44.06 C28.2@-35,44.06 ; C26.2@-33.5,44 C26.2@-33.5,44.1 ; v2@-33.5,45 C26.2@-33.5,44.1 ; -32.5,44.1 C26.2@-33.5,44.1 ; C34.1@-37.1,44.06 C27.2@-36,44.06 ; C27.2@-36,44.06 C28.2@-35,44.06
  other v2: -37.1,45.2 -35.7,45.2 -34.6,45.2 -33.5,45.2
5V_DVK_PWR_ON: R29.1 U5.4 U7.D18 | length 160.7
  1-TOP w0.2: v1(-17.145,4.445) U7.D18@-16.51,3.81 ; R29.1@95.9,30 R29.1@95.91,30 ; R29.1@95.9,30.02 R29.1@95.91,30.01 ; U5.4@95.91,28.75 R29.1@95.91,30 ; v1(96.7,30) R29.1@95.92,30 ; R29.1@95.91,30 R29.1@95.92,30 ; R29.1@95.91,30 R29.1@95.91,30.01 ; R29.1@95.91,30.01 R29.1@95.92,30
  3-INTOP w0.2: v1(-20.3,37.7) -19.4,37.7 -18.9,37.2 29.8,37.2 31.9,39.3 78.9,39.3 88.2,30 v1(96.7,30)
  6-INBOT w0.2: v1(-20.3,37.7) -20.3,5.5 -19.9,5.1 -17.8,5.1 v1(-17.145,4.445)
5V_OUT_HDMI: C124.2 J32.18 R128.1 R129.1 U18.38 | length 4.3
  1-TOP w0.2: v1(42.685,-51.1) R129.1@43.32,-51.1 ; v1(42.685,-50) R128.1@43.32,-50 ; J32.18@44.7,-55.8 v1(44.7,-54.1) ; U18.38@54.7,-51.9 C124.2@56.04,-51.9
  other v1: 55.37,-51.9
15.4_SPI_CLK: J44.10 U7.F8 | length 74.2
  1-TOP w0.2: v1(-14.605,-9.525) U7.F8@-13.97,-8.89
  8-BOTTOM w0.15: J44.10@-16.42,58 -18.62,55.8 -19.6,55.8 -21,54.4 -21,43.6 -18.276,40.876 -18.276,36.776 -13.8,32.3 -13.8,6.575 -14.15,6.225 -14.15,-9.07 v1(-14.605,-9.525)
15.4_SPI_FRM: J44.2 U7.F4 | length 84.1
  1-TOP w0.15: J44.2@-26.58,58 -26.58,55.58 -23.4,52.4 v1(-19.5,52.4)
  1-TOP w0.2: v1(-14.605,-14.605) U7.F4@-13.97,-13.97
  8-BOTTOM w0.15: v1@-19.5,52.38 -19.5,43.904 -17,41.404 -17,37.3 -15.728,36.028 -11.5,31.8 -11.5,4.15 -11.9,3.75 -12.225,3.75 -12.5,3.475 -12.5,-13.6 -13.505,-14.605 v1(-14.605,-14.605)
15.4_SPI_INT: J44.4 U7.F5 | length 79.1
  1-TOP w0.15: J44.4@-24.04,58 -24.04,56.24 -22.1,54.3 v1(-20,54.3)
  1-TOP w0.2: v1(-14.605,-13.335) U7.F5@-13.97,-12.7
  8-BOTTOM w0.15: v1(-20,54.3) -20,43.8 -17.427,41.227 -17.427,37.127 -12.525,32.225 -12.525,6.425 -12.9,6.05 -12.9,-11.63 v1(-14.605,-13.335)
15.4_SPI_RXD: J44.6 U7.F6 | length 74.6
  1-TOP w0.2: v1(-14.605,-12.065) U7.F6@-13.97,-11.43
  8-BOTTOM w0.15: J44.6@-21.5,58 -21.5,43.5 -18.7,40.7 -18.7,36.6 -14.15,32.05 -14.15,6.75 -14.6,6.3 -14.6,5.35 -15.05,4.9 -15.05,-11.62 v1(-14.605,-12.065)
15.4_SPI_TXD: J44.8 U7.F7 | length 74.2
  1-TOP w0.15: v1@-20.499,53.101 -18.96,54.64 J44.8@-18.96,58
  1-TOP w0.2: v1(-14.605,-10.795) U7.F7@-13.97,-10.16
  8-BOTTOM w0.15: v1(-20.5,53.1) -20.5,43.7 -17.851,41.051 -17.851,36.951 -12.9,32 -12.9,6.875 -13.8,5.975 -13.8,-9.99 v1(-14.605,-10.795)
ADC_IN0: J48.1 U7.K29 | length 87.5
  1-TOP w0.2: v1(-8.9,23) -8.9,17.79 U7.K29@-8.89,17.78
  3-INTOP w0.2: v1(-77.1,15.4) -74.9,15.4 -71.9,18.4 -38,18.4 -36.3,16.7 -20.7,16.7 -14.4,23 v1(-8.9,23)
  6-INBOT w0.2: J48.1@-81.2,8.3 -79.9,8.3 -77.1,11.1 v1(-77.1,15.4)
ADC_IN1: J48.3 U7.L29 | length 91.3
  1-TOP w0.2: U7.L29@-7.62,17.78 -7.6,17.8 v1(-7.6,23.5)
  3-INTOP w0.2: v1(-76.4,15.9) -75.2,15.9 -72.1,19 -38.107,19 -37.8,19 -36,17.2 -21,17.2 -14.7,23.5 v1(-7.6,23.5)
  6-INBOT w0.2: J48.3@-81.2,5.76 -76.4,10.56 v1(-76.4,15.9)
ADC_IN2: J48.5 U7.AG27 | length 122.1
  1-TOP w0.2: U7.AG27@12.7,15.24 v1(13.335,14.605)
  3-INTOP w0.15: v1(-75.8,17.8) -74,17.8 -72.3,19.5 -50.8,19.5 -36.7,19.5 -30.7,25.5 -15,25.5 v1(13.9,25.5)
  6-INBOT w0.2: J48.5@-81.2,3.22 -75.8,8.62 v1(-75.8,17.8)
  8-BOTTOM w0.15: v1(13.335,14.605) 14.3,15.57 14.3,25.1 v1(13.9,25.5)
ADC_IN3: J48.7 U7.AG26 | length 127.2
  1-TOP w0.2: U7.AG26@12.7,13.97 v1(13.335,13.335)
  3-INTOP w0.15: v1(-75.2,18.3) -74.2,18.3 -72.5,20 -36.8,20 -30.6,26.2 v1(13.9,26.2)
  6-INBOT w0.2: J48.7@-81.2,0.68 -75.2,6.68 v1(-75.2,18.3)
  8-BOTTOM w0.15: v1(13.335,13.335) 14.8,14.8 14.8,25.3 v1(13.9,26.2)
AUD_I2C_SCL: R179.2 U27.51 | length 149.8
  1-TOP w0.15: v1(-68.7,31.7) -68.6,31.8 U27.51@-67.03,31.8
  1-TOP w0.2: v1(69.2,23.7) R179.2@69.2,24.32
  3-INTOP w0.2: v1(-68.7,31.7) -68.2,31.7 -66.9,33 -46.7,33 45.3,33 48.3,30 55.4,30 56.5,31.1 68.1,31.1 69.9,29.3 69.9,27.7 69.2,27 v1(69.2,23.7)
AUD_I2C_SDA: R183.2 U27.52 | length 143.9
  1-TOP w0.15: v1(-68.7,31) -68.3,31.4 U27.52@-67.03,31.4
  1-TOP w0.2: R183.2@69.2,28.08 v1(69.2,28.7)
  3-INTOP w0.2: v1(-68.7,31) -68.334,31 -48,31 -46.4,32.6 45.1,32.6 48.1,29.6 55.6,29.6 56.7,30.7 67.8,30.7 69.2,29.3 v1(69.2,28.7)
BT_DEV_WAKE: J41.15 U7.G12 | length 103.2
  1-TOP w0.2: v1(-13.335,-4.445) U7.G12@-12.7,-3.81
  3-INTOP w0.2: J41.15@-83.57,-36.85 -82.32,-38.1 -80.4,-38.1 -79.7,-38.8 -79.5,-39 -75.1,-39 -74.6,-38.5 -61.807,-38.5 -59.307,-36 -58.207,-36 -57.6,-35.393 -57.6,-30.793 -53.007,-26.2 -47.693,-26.2 -45.693,-24.2 -33.6,-24.2 -31.5,-26.3 -24.2,-26.3 -23.8,-25.9 v1(-14.6,-25.9)
  6-INBOT w0.2: v1(-14.6,-25.9) -13.3,-24.6 -13.3,-14.5 -14,-13.8 -14,-5.11 v1(-13.335,-4.445)
BT_HOST_WAKE: J41.13 U7.G17 | length 110.1
  1-TOP w0.2: U7.G17@-12.7,2.54 v1(-12.065,1.905)
  3-INTOP w0.2: J41.13@-83.57,-34.31 -82.28,-35.6 -77.3,-35.6 -77,-35.9 -74.8,-35.9 -73.2,-37.5 -63.707,-37.5 -61.2,-34.993 -61.2,-31.193 -59.2,-29.193 -59.2,-27.393 -57.007,-25.2 -48.107,-25.2 -46.107,-23.2 -33.2,-23.2 -31.1,-25.3 -24.8,-25.3 -23.9,-24.4 v1(-14.6,-24.4)
  8-BOTTOM w0.2: v1(-14.6,-24.4) -13.7,-24.4 -11.4,-22.1 -11.4,1.24 v1(-12.065,1.905)
BT_UART1_CTS: J41.7 R63.2 | length 53.7
  1-TOP w0.2: v1(-46,-5.4) R63.2@-45.28,-5.4
  3-INTOP w0.2: J41.7@-83.57,-26.69 -82.3,-25.42 -82.3,-15.5 -71.2,-4.4 -49.2,-4.4 -48.2,-5.4 v1(-46,-5.4)
BT_UART1_RTS: R64.2 SW3.2 U26.3 | length 210.5
  1-TOP w0.2: v1(-46,-6.4) R64.2@-45.28,-6.4 ; v1(24.1,29.6) 34.286,29.6 42.486,37.8 54.179,37.8 60.979,31 69.579,31 77.379,23.2 98.4,23.2 100.6,25.4 100.6,28.7 101.175,29.275 U26.3@101.175,30.4 101.175,31.775 102.1,32.7 105.7,32.7 108.57,35.57 SW3.2@110,35.57
  3-INTOP w0.2: v1(-46.5,28) -44.9,29.6 v1(24.1,29.6)
  6-INBOT w0.2: v1(-46.5,28) -46.5,-5.9 v1(-46,-6.4)
BT_UART1_RTS_PROT: J41.9 U26.17 | length 255.4
  1-TOP w0.2: v1(24.1,30.6) 33.872,30.6 42.072,38.8 54.593,38.8 61.393,32 69.993,32 77.793,24.2 97.8,24.2 98.7,25.1 98.7,30.9 101.825,34.025 U26.17@101.825,36.2
  3-INTOP w0.2: v1(-74,22.7) -53.293,22.7 -45.393,30.6 -29.2,30.6 v1(24.1,30.6)
  6-INBOT w0.2: J41.9@-83.57,-29.23 -82.34,-28 -80.1,-28 -74,-21.9 v1(-74,22.7)
BT_UART1_RX: J41.5 R62.2 | length 59.9
  1-TOP w0.2: v1(-47.1,0.6) -47.1,-3.9 -46.6,-4.4 R62.2@-45.28,-4.4
  3-INTOP w0.2: J41.5@-83.57,-24.15 -84.8,-22.92 -84.8,-16.4 -67.3,1.1 -49.3,1.1 -48.8,0.6 v1(-47.1,0.6)
BT_UART1_TX: R61.2 R159.2 SW3.1 U26.2 | length 209.8
  1-TOP w0.2: v1(-46,-3.4) R61.2@-45.28,-3.4 ; v1(23.5,30.1) 34.079,30.1 42.279,38.3 54.386,38.3 61.186,31.5 69.786,31.5 77.586,23.7 98.1,23.7 99.2,24.8 99.2,28.2 99.38,28.38 R159.2@99.8,28.38 ; R159.2@100,28.4 100,28.9 100.525,29.425 U26.2@100.525,30.4 100.525,32.125 101.6,33.2 105.3,33.2 107.8,35.7 107.8,37.5 108.41,38.11 SW3.1@110,38.11
  3-INTOP w0.2: v1(-46,29.2) -45.1,30.1 -29.4,30.1 v1(23.5,30.1)
  6-INBOT w0.2: v1(-46,-3.4) v1(-46,29.2)
BT_UART1_TX_PROT: J41.3 U26.18 | length 250.3
  1-TOP w0.2: v1(23.5,31.1) 33.664,31.1 41.864,39.3 54.8,39.3 61.6,32.5 70.2,32.5 78,24.7 97.5,24.7 98.2,25.4 98.2,31.2 101.175,34.175 U26.18@101.175,36.2
  3-INTOP w0.2: v1(-74.6,23.2) -53.5,23.2 -45.6,31.1 -29,31.1 v1(23.5,31.1)
  6-INBOT w0.2: J41.3@-83.57,-21.61 -82.26,-20.3 -75.6,-20.3 -74.6,-19.3 v1(-74.6,23.2)
BYPASS: C196.2 R193.2 U23.4 | length 3.2
  1-TOP w0.2: C196.2@81.9,-43.5 81.9,-44.52 R193.2@81.98,-44.6 81.98,-45.38 82.3,-45.7 U23.4@82.3,-46.55
CAN1_H: D4.2 J14.1 J15.2 U8.7 | length 27.3
  1-TOP w0.2: J14.1@-10.46,53.76 J15.2@-10.46,59.5 ; J14.1@-10.4,54.56 -10.4,52.6 -9.1,51.3 5.3,51.3 5.955,50.645 5.955,50 U8.7@5.955,48.17
CAN1_L: D3.2 J15.3 R66.1 U8.6 | length 24.8
  1-TOP w0.2: J15.3@-7.92,59.5 -7.9,59.48 R66.1@-7.9,57.38 -7.28,57.38 -6.4,56.5 -6.4,52.4 -5.8,51.8 5.8,51.8 7.2,50.4 7.2,48.195 U8.6@7.225,48.17
CAN1_RX: U7.U29 U8.4 | length 29
  1-TOP w0.2: U7.U29@0,17.78 0,29.7 6.7,36.4 v1(6.7,38.4) ; v1(8.495,41.615) U8.4@8.495,43.23
  8-BOTTOM w0.2: v1(6.7,38.4) 6.7,39.2 8.495,40.995 v1(8.495,41.615)
CAN1_STB: R158.2 SW3.3 U7.C17 U26.4 | length 181
  1-TOP w0.2: v1(-18.415,1.905) U7.C17@-17.78,2.54 ; v1(23.5,29.1) 34.493,29.1 42.693,37.3 53.972,37.3 60.772,30.5 69.372,30.5 77.172,22.7 98.7,22.7 102.1,26.1 102.1,28.1 101.82,28.38 R158.2@101.3,28.38 101.3,28.8 101.825,29.325 U26.4@101.825,30.4 101.825,31.625 102.4,32.2 106.1,32.2 106.93,33.03 SW3.3@110,33.03
  3-INTOP w0.2: v1(-21.9,29.1) v1(23.5,29.1)
  6-INBOT w0.2: v1(-21.9,29.1) -21.9,2.8 -21.005,1.905 v1(-18.415,1.905)
CAN1_STB_PROT: R67.2 U8.8 U26.16 | length 124.7
  1-TOP w0.15: R67.2@3.1,48.22 v1(3.868,48.22) 4.635,48.22 U8.8@4.685,48.17 ; U26.16@102.475,36.2 102.5,36.225 v1(102.5,37.3)
  3-INTOP w0.15: v1(3.868,48.22) 9.22,48.22 9.8,48.8 53.549,48.8 55.349,47 96.251,47 97.051,47.8 106.949,47.8 109.2,45.549 109.2,38.651 107.549,37 103.6,37 103.3,37.3 v1(102.5,37.3)
CAN1_TX: U7.T29 U8.1 | length 31.5
  1-TOP w0.2: U7.T29@-1.27,17.78 -1.27,35.43 1.7,38.4 v1(6,38.4) ; U8.1@4.685,43.23 4.7,43.215 v1(4.7,41.6)
  8-BOTTOM w0.2: v1(4.7,41.6) 4.7,40.5 6,39.2 v1(6,38.4)
CAN2_H: D8.2 J16.1 J17.2 U10.7 | length 24
  1-TOP w0.2: J17.2@0.08,59.5 0.1,59.48 0.1,54.2 0.1,52.9 0.4,52.6 6.7,52.6 7.9,51.4 13.4,51.4 13.87,50.93 13.87,50 U10.7@13.87,48.14
CAN2_L: D7.2 J17.3 R77.1 U10.6 | length 21.6
  1-TOP w0.2: R77.1@2.6,57.38 3.42,57.38 4.2,56.6 4.2,53.5 4.6,53.1 6.9,53.1 8.1,51.9 13.7,51.9 15.125,50.475 U10.6@15.125,48.17 ; R77.1@2.6,57.4 2.6,59.48 J17.3@2.62,59.5
CAN2_RX: U7.R29 U10.4 | length 41.6
  1-TOP w0.2: U7.R29@-2.54,17.78 -2.54,35.76 0.9,39.2 15.2,39.2 16.41,40.41 U10.4@16.41,43.2
CAN2_STB: R157.2 SW3.4 U7.E17 U26.5 | length 176.2
  1-TOP w0.2: v1(-15.875,3.175) U7.E17@-15.24,2.54 ; v1(24.1,28.6) 34.7,28.6 42.9,36.8 53.764,36.8 60.564,30 69.164,30 76.964,22.2 99,22.2 103.6,26.8 103.6,28.1 103.32,28.38 R157.2@102.8,28.38 102.8,28.9 102.475,29.225 U26.5@102.475,30.4 102.5,30.425 102.5,31.5 102.7,31.7 106.9,31.7 108.11,30.49 SW3.4@110,30.49
  3-INTOP w0.2: v1(-19,28.6) v1(24.1,28.6)
  6-INBOT w0.2: v1(-19,28.6) -19,7.9 -18.7,7.6 -16.9,7.6 -16.5,7.2 -16.5,3.8 v1(-15.875,3.175)
CAN2_STB_PROT: R78.2 U10.8 U26.15 | length 113.9
  1-TOP w0.15: U26.15@103.125,36.2 103.125,37.325 103.4,37.6 v1(104,37.6)
  1-TOP w0.2: R78.2@11.08,48.2 R78.2@11.1,48.22 v1(11.81,48.22) 12.52,48.22 U10.8@12.6,48.14
  3-INTOP w0.15: v1@11.81,48.2 53.3,48.2 55.1,46.4 96.5,46.4 97.3,47.2 106.7,47.2 108.6,45.3 108.6,38.9 107.3,37.6 v1(104,37.6)
CAN2_TX: U7.P29 U10.1 | length 38.7
  1-TOP w0.2: U7.P29@-3.81,17.78 -3.81,35.19 0.7,39.7 11.8,39.7 12.6,40.5 U10.1@12.6,43.2
CLKIN1: J48.2 U7.AM10 | length 143.7
  1-TOP w0.2: J48.2@-83.74,8.32 -82.42,7 v1(-72,7) ; U7.AM10@19.05,-6.35 v1(19.685,-6.985)
  3-INTOP w0.2: v1(-72,-13.6) -63.193,-13.6 -60.793,-16 -50.4,-16 -48.8,-17.6 -24.793,-17.6 -20.993,-21.4 13.1,-21.4 13.8,-20.7 v1(20.4,-20.7)
  6-INBOT w0.2: v1(-72,-13.6) v1(-72,7) ; v1(19.685,-6.985) 20.4,-7.7 v1(20.4,-20.7)
CLKIN2: J48.4 U7.AM11 | length 147
  1-TOP w0.2: J48.4@-83.74,5.78 -82.46,4.5 v1(-72.6,4.5) ; U7.AM11@19.05,-5.08 v1(19.685,-5.715)
  3-INTOP w0.2: v1(-72.6,-14.1) -63.4,-14.1 -61,-16.5 -50.607,-16.5 -49.007,-18.1 -25,-18.1 -21.2,-21.9 13.6,-21.9 14.4,-22.7 v1(21.8,-22.7)
  6-INBOT w0.2: v1(-72.6,-14.1) v1(-72.6,4.5) ; v1(19.685,-5.715) 21.8,-7.83 v1(21.8,-22.7)
CONSOLE_RX: D9.2 J18.2 R68.1 U7.V29 | length 105.5
  1-TOP w0.15: v1@-48,56.1 v1(-47.9,56.1) R68.1@-46.88,56.1 ; v1@-47.95,56.15 -48.25,56.45 D9.2@-48.25,57.5 -48.25,58.55 -47.9,58.9 J18.2@-47.9,59.9 ; U7.V29@1.27,17.78 1.27,29.955 7.5,36.185 v1(7.5,38.4)
  3-INTOP w0.15: v1(-47.9,56.1) -49.2,54.8 -49.2,39 -48.2,38 -24,38 -20.9,41.1 -18.766,41.1 -17.566,39.9 -11,39.9 -10,38.9 7,38.9 v1(7.5,38.4)
CONSOLE_TX: D10.2 J18.1 R69.1 U7.W29 | length 105.4
  1-TOP w0.15: J18.1@-49.15,59.9 -49.1,59.85 -49.1,57.55 D10.2@-49.05,57.5 -49.05,56.05 v1(-47.9,54.9) R69.1@-46.88,54.9 ; U7.W29@2.54,17.78 2.54,30.34 8.3,36.1 v1(8.3,38.4)
  3-INTOP w0.15: v1(-47.9,54.9) -48.7,54.1 -48.7,39.3 -47.8,38.4 -24.166,38.4 -21.066,41.5 -18.6,41.5 -17.4,40.3 -10.834,40.3 -9.834,39.3 7.4,39.3 v1(8.3,38.4)
CONSOLE_USB_N: J13.A7 J13.B7 U9.11 | length 25
  1-TOP w0.168: U9.11@-40.25,48.95 -40.25,48.45 -40.341,48.359 -40.341,47.441 -39.918,47.018 -37.907,47.018 -35.559,49.366 -35.559,50.175 -35.559,50.583 -35.657,50.682 -36.111,50.682 -36.184,50.755 -36.184,50.976 -36.111,51.05 -35.657,51.05 -35.559,51.148 -35.559,51.6 -35.559,52.459 v1(-35.7,52.6) -35.559,52.741 -35.559,53.159 -35.9,53.5 J13.A7@-35.9,54.035 ; J13.B7@-35.15,55.735 -35.15,56.209 -35.241,56.3 -35.241,57.259 v1(-35.1,57.4)
  8-BOTTOM w0.168: v1(-35.7,52.6) -35.559,52.741 -35.559,54.041 -35.2,54.4 -35.141,54.459 -35.141,54.599 -35.462,54.92 -35.462,55.024 -35.306,55.18 -35.202,55.18 -34.88,54.859 -34.741,54.859 -34.247,55.353 -33.4,56.2 -33.4,57.6 -34,58.2 -35.041,58.2 -35.241,58 -35.241,57.541 v1(-35.1,57.4)
CONSOLE_USB_P: J13.A6 J13.B6 U9.10 | length 25.1
  1-TOP w0.168: U9.10@-40.75,48.95 -40.75,48.45 -40.659,48.359 -40.659,47.309 -40.05,46.7 -37.775,46.7 -35.241,49.234 -35.241,52.459 v1(-35.1,52.6) -35.241,52.741 -35.241,53.159 -34.9,53.5 J13.A6@-34.9,54.035 ; v1(-35.7,57.4) -35.559,57.259 -35.559,56.3 -35.65,56.209 J13.B6@-35.65,55.735
  8-BOTTOM w0.168: v1(-35.7,57.4) -35.559,57.541 -35.559,58.132 -35.173,58.518 -33.868,58.518 -33.082,57.732 -33.082,56.068 -35.241,53.909 -35.241,52.741 v1(-35.1,52.6)
CT1: C54.2 C55.2 C56.2 C57.2 J26.1
CT2: C81.2 C82.2 C83.2 C84.2 J27.1 | length 1.1
  1-TOP w0.2: C82.2@-54.7,-46.26 C81.2@-53.6,-46.26
DISP_RESET: J29.7 R214.2 R218.1 U7.AA1 | length 63.5
  1-TOP w0.2: U7.AA1@5.08,-17.78 5.1,-17.8 v1(5.1,-24.9) ; v1(12,-60.7) 12.68,-60.7 R214.2@12.7,-60.68 12.99,-60.68 13.01,-60.7 13.58,-60.7 R218.1@13.6,-60.68 13.6,-63.2 14.9,-64.5 18.7,-64.5 19.35,-63.85 J29.7@19.35,-62.737
  6-INBOT w0.2: v1(5.1,-24.9) 5.1,-38.2 3.6,-39.7 3.6,-60.3 4,-60.7 v1(12,-60.7)
ENET1_MDC: U7.A10 U13.7 | length 93.9
  1-TOP w0.2: v1@-74.9,-24.195 -76.895,-24.195 -78.8,-26.1 -78.8,-33.6 -77.45,-34.95 U13.7@-74.15,-34.95 ; v1(-35.1,-6.6) -24.4,-6.6 -24.3,-6.6 -24.183,-6.483 -24.183,-5.894 -24.103,-5.814 -23.863,-5.814 -23.783,-5.894 -23.783,-6.612 -23.703,-6.692 -23.463,-6.692 -23.383,-6.612 -23.383,-5.987 -23.303,-5.907 -23.063,-5.907 -22.983,-5.987 -22.983,-6.483 -22.866,-6.6 -22.1,-6.6 -21.475,-6.6 -21.225,-6.35 U7.A10@-20.32,-6.35
  8-BOTTOM w0.2: v1(-74.9,-24.2) -72.8,-26.3 -70.7,-26.3 -67.2,-29.8 -59.293,-29.8 -58.7,-29.207 -58.7,-27.6 -57.8,-26.7 -44.493,-26.7 -35.1,-17.307 v1(-35.1,-6.6)
ENET1_MDIO: R99.2 U7.A11 U13.8 | length 94
  1-TOP w0.2: v1(-74.4,-23.7) -77.1,-23.7 -79.295,-25.895 -79.295,-33.805 -78.5,-34.6 R99.2@-78.5,-35.22 -77.98,-35.22 -77.8,-35.4 -75.9,-35.4 -75.85,-35.45 U13.8@-74.15,-35.45 ; v1(-35.8,-5.9) -25.1,-5.9 -24.28,-5.08 U7.A11@-20.32,-5.08
  8-BOTTOM w0.2: v1(-74.4,-23.7) -72.3,-25.8 -70.493,-25.8 -66.993,-29.3 -59.5,-29.3 -59.2,-29 -59.2,-27.393 -58.007,-26.2 -44.7,-26.2 -35.8,-17.3 v1(-35.8,-5.9)
ENET1_RD0: U7.A16 U13.44 | length 82.4
  1-TOP w0.2: U13.44@-67.4,-31.2 -67.4,-30.6 -67.3,-30.5 -67.3,-28.5 v1(-66.8,-28) ; v1(-38.4,-18.6) -38.4,-3.779 -33.351,1.27 -30.036,1.27 -29.936,1.27 -29.819,1.387 -29.819,1.927 -29.739,2.007 -29.499,2.007 -29.419,1.927 -29.419,1.315 -29.339,1.235 -29.099,1.235 -29.019,1.315 -29.019,1.927 -28.939,2.007 -28.699,2.007 -28.619,1.927 -28.619,1.315 -28.539,1.235 -28.299,1.235 -28.219,1.315 -28.219,1.927 -28.139,2.007 -27.899,2.007 -27.819,1.927 -27.819,1.315 -27.739,1.235 -27.499,1.235 -27.419,1.315 -27.419,1.927 -27.339,2.007 -27.099,2.007 -27.019,1.927 -27.019,1.315 -26.939,1.235 -26.699,1.235 -26.619,1.315 -26.619,1.927 -26.539,2.007 -26.299,2.007 -26.219,1.927 -26.219,1.315 -26.139,1.235 -25.899,1.235 -25.819,1.315 -25.819,1.711 -25.739,1.791 -25.499,1.791 -25.419,1.711 -25.419,1.387 -25.301,1.27 -24.8,1.27 -24.325,1.27 -24.225,1.27 -24.108,1.387 -24.108,1.937 -24.028,2.017 -23.788,2.017 -23.708,1.937 -23.708,1.301 -23.628,1.221 -23.388,1.221 -23.308,1.301 -23.308,1.937 -23.228,2.017 -22.988,2.017 -22.908,1.937 -22.908,1.301 -22.828,1.221 -22.588,1.221 -22.508,1.301 -22.508,1.937 -22.428,2.017 -22.188,2.017 -22.108,1.937 -22.108,1.387 -21.991,1.27 -21.375,1.27 U7.A16@-20.32,1.27
  8-BOTTOM w0.2: v1(-66.8,-28) -62.7,-28 -59.7,-25 -50.9,-25 -44.5,-18.6 v1(-38.4,-18.6)
ENET1_RD1: U7.A15 U13.45 | length 82.4
  1-TOP w0.2: U13.45@-67.9,-31.2 -67.9,-30.5 -67.8,-30.4 v1(-67.8,-26.7) ; v1(-37.9,-14.9) -37.9,-3.986 -33.914,0 -30.708,0 -30.608,0 -30.491,0.117 -30.491,0.588 -30.411,0.668 -30.171,0.668 -30.091,0.588 -30.091,0.057 -30.011,-0.023 -29.771,-0.023 -29.691,0.057 -29.691,0.588 -29.611,0.668 -29.371,0.668 -29.291,0.588 -29.291,0.057 -29.211,-0.023 -28.971,-0.023 -28.891,0.057 -28.891,0.588 -28.811,0.668 -28.571,0.668 -28.491,0.588 -28.491,0.057 -28.411,-0.023 -28.171,-0.023 -28.091,0.057 -28.091,0.588 -28.011,0.668 -27.771,0.668 -27.691,0.588 -27.691,0.057 -27.611,-0.023 -27.371,-0.023 -27.291,0.057 -27.291,0.588 -27.211,0.668 -26.971,0.668 -26.891,0.588 -26.891,0.057 -26.811,-0.023 -26.571,-0.023 -26.491,0.057 -26.491,0.588 -26.411,0.668 -26.171,0.668 -26.091,0.588 -26.091,0.057 -26.011,-0.023 -25.771,-0.023 -25.691,0.057 -25.691,0.588 -25.611,0.668 -25.371,0.668 -25.291,0.588 -25.291,0.057 -25.211,-0.023 -24.971,-0.023 -24.891,0.057 -24.891,0.588 -24.811,0.668 -24.571,0.668 -24.491,0.588 -24.491,0.057 -24.411,-0.023 -24.171,-0.023 -24.091,0.057 -24.091,0.588 -24.011,0.668 -23.771,0.668 -23.691,0.588 -23.691,0.057 -23.611,-0.023 -23.371,-0.023 -23.291,0.057 -23.291,0.588 -23.211,0.668 -22.971,0.668 -22.891,0.588 -22.891,0.057 -22.811,-0.023 -22.571,-0.023 -22.491,0.057 -22.491,0.527 -22.411,0.607 -22.171,0.607 -22.091,0.527 -22.091,0.117 -21.974,0 -21.638,0 U7.A15@-20.32,0
  8-BOTTOM w0.2: v1(-67.8,-26.7) -62.2,-26.7 -60,-24.5 -51.1,-24.5 -44.1,-17.5 -40.5,-17.5 v1(-37.9,-14.9)
ENET1_RD2: U7.A14 U13.47 | length 82.4
  1-TOP w0.2: U13.47@-68.9,-31.2 -68.9,-30.3 -68.8,-30.2 v1(-68.8,-23.1) ; v1(-37.4,-14.4) -37.4,-4.193 -34.477,-1.27 -28.609,-1.27 -28.509,-1.27 -28.392,-1.153 -28.392,-0.59 -28.312,-0.51 -28.072,-0.51 -27.992,-0.59 -27.992,-1.212 -27.912,-1.292 -27.672,-1.292 -27.592,-1.212 -27.592,-0.59 -27.512,-0.51 -27.272,-0.51 -27.192,-0.59 -27.192,-1.212 -27.112,-1.292 -26.872,-1.292 -26.792,-1.212 -26.792,-0.59 -26.712,-0.51 -26.472,-0.51 -26.392,-0.59 -26.392,-1.212 -26.312,-1.292 -26.072,-1.292 -25.992,-1.212 -25.992,-0.59 -25.912,-0.51 -25.672,-0.51 -25.592,-0.59 -25.592,-1.212 -25.512,-1.292 -25.272,-1.292 -25.192,-1.212 -25.192,-0.67 -25.112,-0.59 -24.872,-0.59 -24.792,-0.67 -24.792,-1.153 -24.674,-1.27 -24.176,-1.27 -23.506,-1.27 -23.406,-1.27 -23.289,-1.153 -23.289,-0.612 -23.209,-0.532 -22.969,-0.532 -22.889,-0.612 -22.889,-1.238 -22.809,-1.318 -22.569,-1.318 -22.489,-1.238 -22.489,-0.612 -22.409,-0.532 -22.169,-0.532 -22.089,-0.612 -22.089,-1.153 -21.971,-1.27 -21.325,-1.27 U7.A14@-20.32,-1.27
  8-BOTTOM w0.2: v1(-68.8,-23.1) -67.4,-21.7 -64.6,-21.7 -62.8,-23.5 -51.6,-23.5 -44.6,-16.5 -40.9,-16.5 -38.8,-14.4 v1(-37.4,-14.4)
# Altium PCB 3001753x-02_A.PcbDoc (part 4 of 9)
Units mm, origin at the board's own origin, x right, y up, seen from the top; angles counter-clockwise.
Board outline 210 x 130 mm, 8 copper layers (1-TOP, 2-GND, 3-INTOP, 4-PWR, 5-PWR, 6-INBOT, 7-GND, 8-BOTTOM), stack 1.646 mm thick; 651 components, 607 nets, 2780 pads, 1706 vias.

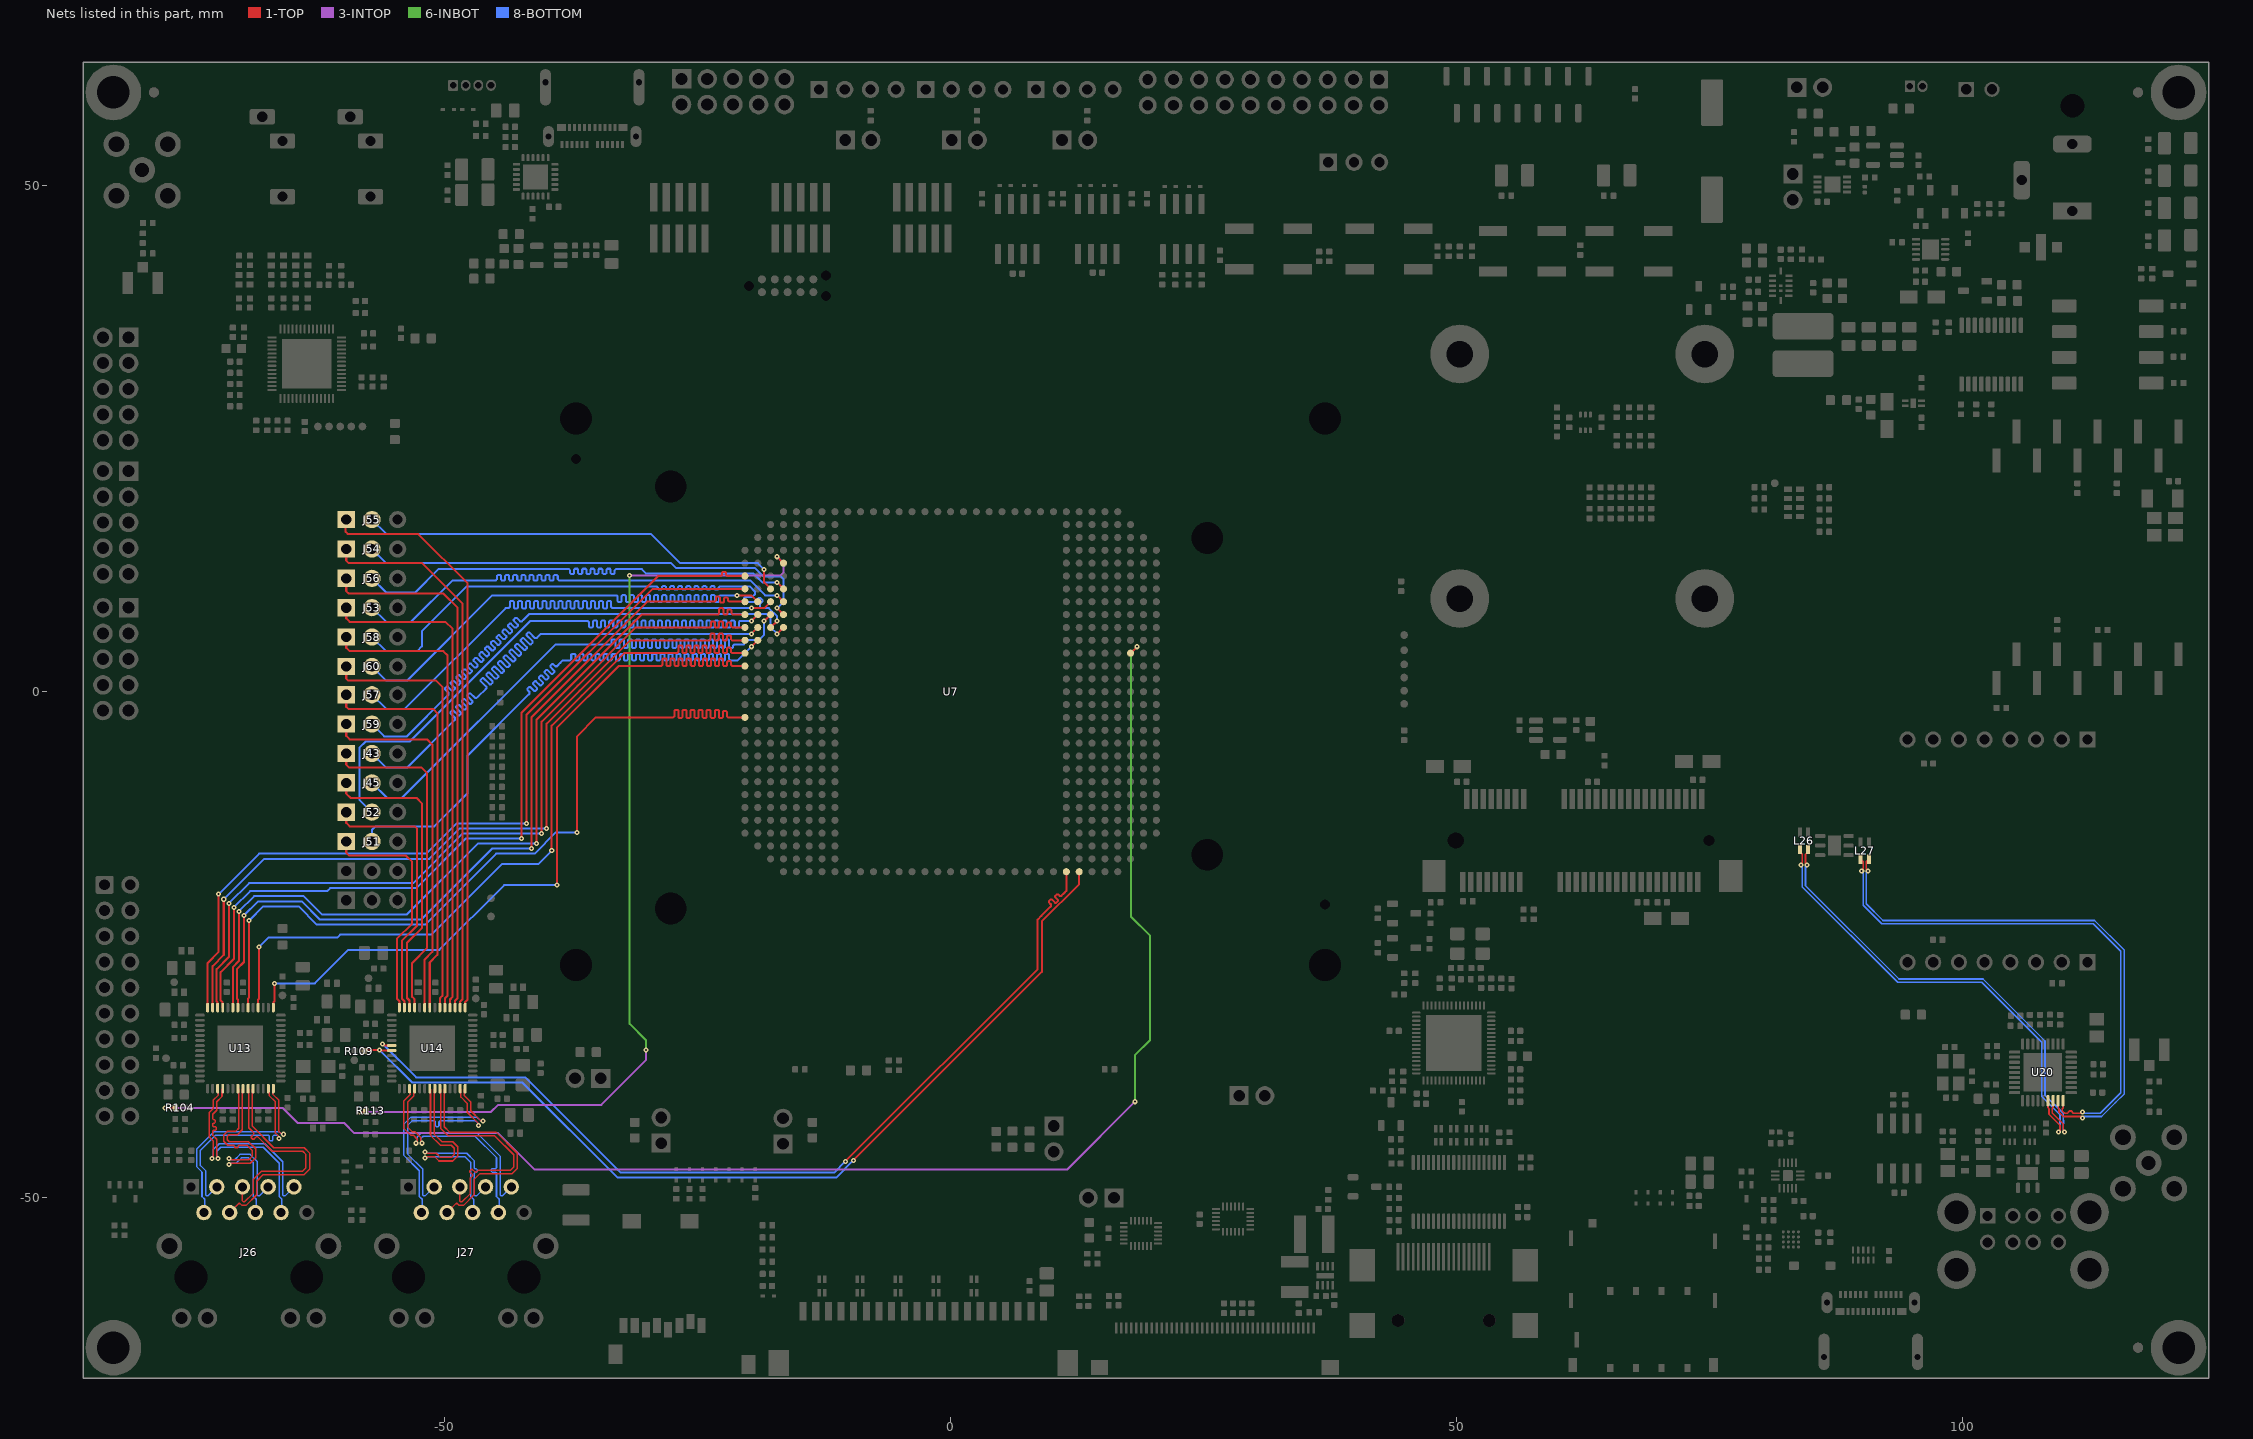
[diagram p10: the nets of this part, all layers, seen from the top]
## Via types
v1: diameter 0.5, hole 0.2, 1-TOP to 8-BOTTOM, 1453 vias
v2: diameter 0.68, hole 0.3, 1-TOP to 8-BOTTOM, 253 vias

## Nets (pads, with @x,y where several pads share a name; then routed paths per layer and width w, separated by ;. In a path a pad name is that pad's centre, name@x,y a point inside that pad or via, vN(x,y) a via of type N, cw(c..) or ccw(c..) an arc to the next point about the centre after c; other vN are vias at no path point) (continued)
ENET1_RD3: U7.A13 U13.48 | length 82.4
  1-TOP w0.2: U13.48@-69.4,-31.2 -69.4,-30.3 -69.3,-30.2 v1(-69.3,-22.6) ; v1(-36.9,-13.9) -36.9,-4.4 -35.04,-2.54 -27.513,-2.54 -27.413,-2.54 -27.296,-2.423 -27.296,-1.868 -27.216,-1.788 -26.976,-1.788 -26.896,-1.868 -26.896,-2.501 -26.816,-2.581 -26.576,-2.581 -26.496,-2.501 -26.496,-1.868 -26.416,-1.788 -26.176,-1.788 -26.096,-1.868 -26.096,-2.501 -26.016,-2.581 -25.776,-2.581 -25.696,-2.501 -25.696,-1.868 -25.616,-1.788 -25.376,-1.788 -25.296,-1.868 -25.296,-2.501 -25.216,-2.581 -24.976,-2.581 -24.896,-2.501 -24.896,-1.868 -24.816,-1.788 -24.576,-1.788 -24.496,-1.868 -24.496,-2.501 -24.416,-2.581 -24.176,-2.581 -24.096,-2.501 -24.096,-1.868 -24.016,-1.788 -23.776,-1.788 -23.696,-1.868 -23.696,-2.501 -23.616,-2.581 -23.376,-2.581 -23.296,-2.501 -23.296,-1.868 -23.216,-1.788 -22.976,-1.788 -22.896,-1.868 -22.896,-2.501 -22.816,-2.581 -22.576,-2.581 -22.496,-2.501 -22.496,-1.998 -22.416,-1.918 -22.176,-1.918 -22.096,-1.998 -22.096,-2.423 -21.979,-2.54 -21.55,-2.54 U7.A13@-20.32,-2.54
  8-BOTTOM w0.2: v1(-69.3,-22.6) -67.9,-21.2 -64.4,-21.2 -62.6,-23 -51.9,-23 -44.9,-16 -41.1,-16 -39,-13.9 v1(-36.9,-13.9)
ENET1_RST: R104.1 U7.AL18 | length 149.6
  1-TOP w0.2: v1(-77.6,-41.1) R104.1@-76.58,-41.1 ; U7.AL18@17.78,3.81 v1(18.415,4.445)
  3-INTOP w0.2: v1(-77.6,-41.1) -66,-41.1 -64.5,-42.6 -59.9,-42.6 -58.9,-43.6 -44.7,-43.6 -41.1,-47.2 11.5,-47.2 v1(18.2,-40.5)
  6-INBOT w0.2: v1(18.2,-40.5) 18.2,-35.9 19.7,-34.4 19.7,-24.1 17.8,-22.2 17.8,3.83 v1(18.415,4.445)
ENET1_RX_CTL: U7.A17 U13.43 | length 82.4
  1-TOP w0.2: U13.43@-66.9,-31.2 -66.9,-30.7 -66.8,-30.6 v1(-66.8,-28.8) ; v1(-38.9,-19.1) -38.9,-3.572 -32.788,2.54 -28.688,2.54 -28.588,2.54 -28.47,2.657 -28.47,3.217 -28.39,3.297 -28.15,3.297 -28.07,3.217 -28.07,2.617 -27.99,2.537 -27.75,2.537 -27.67,2.617 -27.67,3.217 -27.59,3.297 -27.35,3.297 -27.27,3.217 -27.27,2.617 -27.19,2.537 -26.95,2.537 -26.87,2.617 -26.87,3.217 -26.79,3.297 -26.55,3.297 -26.47,3.217 -26.47,2.617 -26.39,2.537 -26.15,2.537 -26.07,2.617 -26.07,3.217 -25.99,3.297 -25.75,3.297 -25.67,3.217 -25.67,2.617 -25.59,2.537 -25.35,2.537 -25.27,2.617 -25.27,3.217 -25.19,3.297 -24.95,3.297 -24.87,3.217 -24.87,2.617 -24.79,2.537 -24.55,2.537 -24.47,2.617 -24.47,3.217 -24.39,3.297 -24.15,3.297 -24.07,3.217 -24.07,2.617 -23.99,2.537 -23.75,2.537 -23.67,2.617 -23.67,3.217 -23.59,3.297 -23.35,3.297 -23.27,3.217 -23.27,2.617 -23.19,2.537 -22.95,2.537 -22.87,2.617 -22.87,3.217 -22.79,3.297 -22.55,3.297 -22.47,3.217 -22.47,2.617 -22.39,2.537 -22.15,2.537 -22.07,2.617 -22.07,2.94 -21.99,3.02 -21.75,3.02 -21.67,2.94 -21.67,2.657 -21.553,2.54 -20.972,2.54 U7.A17@-20.32,2.54
  8-BOTTOM w0.2: v1(-66.8,-28.8) -62.8,-28.8 -59.5,-25.5 -50.5,-25.5 -44.1,-19.1 v1(-38.9,-19.1)
ENET1_RXC: U7.A18 U13.46 | length 82.4
  1-TOP w0.2: U13.46@-68.4,-31.2 -68.4,-30.4 -68.3,-30.3 v1(-68.3,-25.2) ; v1@-39.41,-15.7 -39.41,-3.36 -36.44,-0.39 -32.24,3.81 -27.117,3.81 -27.017,3.81 -26.9,3.927 -26.9,4.504 -26.82,4.584 -26.58,4.584 -26.5,4.504 -26.5,3.885 -26.42,3.805 -26.18,3.805 -26.1,3.885 -26.1,4.504 -26.02,4.584 -25.78,4.584 -25.7,4.504 -25.7,3.885 -25.62,3.805 -25.38,3.805 -25.3,3.885 -25.3,4.504 -25.22,4.584 -24.98,4.584 -24.9,4.504 -24.9,3.885 -24.82,3.805 -24.58,3.805 -24.5,3.885 -24.5,4.504 -24.42,4.584 -24.18,4.584 -24.1,4.504 -24.1,3.885 -24.02,3.805 -23.78,3.805 -23.7,3.885 -23.7,4.504 -23.62,4.584 -23.38,4.584 -23.3,4.504 -23.3,3.885 -23.22,3.805 -22.98,3.805 -22.9,3.885 -22.9,4.504 -22.82,4.584 -22.58,4.584 -22.5,4.504 -22.5,3.885 -22.42,3.805 -22.18,3.805 -22.1,3.885 -22.1,4.287 -22.02,4.367 -21.78,4.367 -21.7,4.287 -21.7,3.927 -21.583,3.81 -21.2,3.81 -21.1,3.81 U7.A18@-20.32,3.81
  8-BOTTOM w0.2: v1(-68.3,-25.2) -67.4,-24.3 -60.6,-24.3 -60.3,-24 -51.3,-24 -44.3,-17 -40.7,-17 v1(-39.4,-15.7)
ENET1_TD0: U7.A22 U13.50 | length 82.4
  1-TOP w0.2: U13.50@-70.4,-31.2 -70.4,-30.4 -70.5,-30.3 -70.5,-27.4 -69.8,-26.7 v1(-69.8,-22.1) ; v1(-41.4,-15.5) -41.4,-2.536 -29.974,8.89 -23.406,8.89 -23.306,8.89 -23.189,9.007 -23.189,9.31 -23.109,9.39 -22.869,9.39 -22.789,9.31 -22.789,8.878 -22.709,8.798 -22.469,8.798 -22.389,8.878 -22.389,9.209 -22.309,9.289 -22.069,9.289 -21.989,9.209 -21.989,9.007 -21.871,8.89 -21.7,8.89 U7.A22@-20.32,8.89
  8-BOTTOM w0.2: v1(-69.8,-22.1) -68.4,-20.7 -64.1,-20.7 -62.3,-22.5 -52.3,-22.5 -45.3,-15.5 v1(-41.4,-15.5)
ENET1_TD1: U7.A21 U13.51 | length 82.4
  1-TOP w0.2: U13.51@-70.9,-31.2 -70.9,-27.2 -70.3,-26.6 v1(-70.3,-21.7) ; v1(-40.9,-15) -40.9,-2.743 -37.057,1.1 -30.537,7.62 -23.075,7.62 -22.975,7.62 -22.858,7.737 -22.858,8.173 -22.778,8.253 -22.538,8.253 -22.458,8.173 -22.458,7.69 -22.378,7.61 -22.138,7.61 -22.058,7.69 -22.058,8.032 -21.978,8.112 -21.738,8.112 -21.658,8.032 -21.658,7.737 -21.541,7.62 -21.375,7.62 U7.A21@-20.32,7.62
  8-BOTTOM w0.2: v1(-70.3,-21.7) -68.8,-20.2 -63.9,-20.2 -62.1,-22 -53.7,-22 -46.7,-15 v1(-40.9,-15)
ENET1_TD2: U7.A20 U13.54 | length 82.4
  1-TOP w0.2: U13.54@-72.4,-31.2 -72.4,-30.7 -72.5,-30.6 -72.5,-27.4 -71.3,-26.2 v1(-71.3,-20.9) ; v1(-40.4,-14) -40.4,-2.95 -36.85,0.6 -31.1,6.35 -23.888,6.35 -23.788,6.35 -23.671,6.467 -23.671,6.862 -23.591,6.942 -23.351,6.942 -23.271,6.862 -23.271,6.407 -23.191,6.327 -22.951,6.327 -22.871,6.407 -22.871,6.862 -22.791,6.942 -22.551,6.942 -22.471,6.862 -22.471,6.407 -22.391,6.327 -22.151,6.327 -22.071,6.407 -22.071,6.752 -21.991,6.832 -21.751,6.832 -21.671,6.752 -21.671,6.467 -21.554,6.35 -21.375,6.35 U7.A20@-20.32,6.35
  8-BOTTOM w0.2: v1(-71.3,-20.9) -69.3,-18.9 -53.1,-18.9 -48.2,-14 v1(-40.4,-14)
ENET1_TD3: U7.A19 U13.55 | length 82.4
  1-TOP w0.2: U13.55@-72.9,-31.2 -72.9,-30.6 -72.9,-27.1 -71.8,-26 v1(-71.8,-20.5) ; v1(-39.9,-13.5) -39.9,-3.157 -36.643,0.1 -31.663,5.08 -23.921,5.08 -23.821,5.08 -23.704,5.197 -23.704,5.668 -23.624,5.748 -23.384,5.748 -23.304,5.668 -23.304,5.141 -23.224,5.061 -22.984,5.061 -22.904,5.141 -22.904,5.668 -22.824,5.748 -22.584,5.748 -22.504,5.668 -22.504,5.141 -22.424,5.061 -22.184,5.061 -22.104,5.141 -22.104,5.482 -22.024,5.562 -21.784,5.562 -21.704,5.482 -21.704,5.197 -21.587,5.08 -21.293,5.08 U7.A19@-20.32,5.08
  8-BOTTOM w0.2: v1(-71.8,-20.5) -67.8,-16.5 -51.5,-16.5 -48.5,-13.5 v1(-39.9,-13.5)
ENET1_TX_CTL: U7.A23 U13.56 | length 82.4
  1-TOP w0.2: U13.56@-73.4,-31.2 -73.4,-26.8 -72.3,-25.7 v1(-72.3,-20) ; v1(-41.9,-13) -41.9,-2.3 -29.44,10.16 U7.A23@-20.32,10.16
  8-BOTTOM w0.2: v1(-72.3,-20) -68.3,-16 -51.8,-16 -48.8,-13 v1(-41.9,-13)
ENET1_TXC: U7.A24 U13.53 | length 82.4
  1-TOP w0.2: U13.53@-71.9,-31.2 -71.9,-30.7 -72.1,-30.5 -72.1,-27.7 -70.8,-26.4 v1(-70.8,-21.3) ; v1(-42.4,-14.5) -42.4,-2.1 -28.87,11.43 -22.8,11.43 -22.7,11.43 -22.583,11.547 -22.583,11.752 -22.503,11.832 -22.263,11.832 -22.183,11.752 -22.183,11.547 -22.066,11.43 -21.559,11.43 -20.809,11.43 U7.A24@-20.32,11.43
  8-BOTTOM w0.2: v1(-70.8,-21.3) -69.2,-19.7 -61.6,-19.7 -61.3,-19.4 -52.8,-19.4 -47.9,-14.5 v1(-42.4,-14.5)
ENET2_MDC: U7.AF1 U14.7 | length 91.7
  1-TOP w0.2: v1(-56.1,-34.8) -55.95,-34.95 U14.7@-55.2,-34.95 ; v1(-10.4,-46.4) 8.595,-27.405 8.595,-25.1 8.595,-22.505 8.964,-22.136 9.849,-21.251 9.919,-21.181 9.919,-21.015 9.705,-20.801 9.705,-20.688 9.875,-20.518 9.988,-20.518 10.316,-20.846 10.429,-20.846 10.599,-20.677 10.599,-20.563 10.331,-20.295 10.331,-20.182 10.501,-20.012 10.614,-20.012 10.768,-20.166 10.934,-20.166 11.2,-19.9 11.43,-19.67 U7.AF1@11.43,-17.78
  8-BOTTOM w0.2: v1(-56.1,-34.8) -52.8,-38.1 -42,-38.1 -32.6,-47.5 -11.5,-47.5 v1(-10.4,-46.4)
ENET2_MDIO: R109.2 U7.AG1 U14.8 | length 93.3
  1-TOP w0.2: R109.2@-57.92,-35.5 -57.82,-35.4 v1(-56.4,-35.4) -56.35,-35.45 U14.8@-55.2,-35.45 ; v1(-9.6,-46.3) 9.019,-27.681 9.019,-22.681 12.7,-19 U7.AG1@12.7,-17.78
  8-BOTTOM w0.2: v1(-56.4,-35.4) -53.2,-38.6 -42.3,-38.6 -32.9,-48 -11.3,-48 v1(-9.6,-46.3)
ENET2_RD0: J54.1 U14.44 | length 54.4
  1-TOP w0.2: J54.1@-59.7,14.1 -59.7,12.94 -59.46,12.7 -52.2,12.7 -48.2,8.7 -48.2,-30.35 -48.45,-30.6 U14.44@-48.45,-31.2
ENET2_RD0/UART4_RX: J54.2 U7.D21 | length 45.9
  1-TOP w0.2: v1(-17.145,8.255) U7.D21@-16.51,7.62
  8-BOTTOM w0.2: J54.2@-57.16,14.1 -55.76,12.7 -52.875,12.7 -27.6,12.7 -27.1,12.2 -19.3,12.2 -18.5,11.4 -16.8,11.4 -16.5,11.1 -16.5,8.9 v1(-17.145,8.255)
ENET2_RD1: J56.1 U14.45 | length 52.5
  1-TOP w0.2: J56.1@-59.7,11.2 -59.7,9.94 -59.46,9.7 -50.1,9.7 -48.7,8.3 -48.7,-30.25 -48.95,-30.5 U14.45@-48.95,-31.2
ENET2_RD1/GPIO4_IO25: J56.2 U7.D23 | length 47.8
  1-TOP w0.2: v1(-17.145,10.795) U7.D23@-16.51,10.16
  8-BOTTOM w0.2: J56.2@-57.16,11.2 -55.76,9.8 -52.9,9.8 -50.6,12.1 -38.205,12.1 -37.705,12.1 -37.588,11.983 -37.588,11.721 -37.508,11.641 -37.268,11.641 -37.188,11.721 -37.188,12.067 -37.108,12.147 -36.868,12.147 -36.788,12.067 -36.788,11.721 -36.708,11.641 -36.468,11.641 -36.388,11.721 -36.388,12.067 -36.308,12.147 -36.068,12.147 -35.988,12.067 -35.988,11.721 -35.908,11.641 -35.668,11.641 -35.588,11.721 -35.588,12.067 -35.508,12.147 -35.268,12.147 -35.188,12.067 -35.188,11.721 -35.108,11.641 -34.868,11.641 -34.788,11.721 -34.788,12.067 -34.708,12.147 -34.468,12.147 -34.388,12.067 -34.388,11.721 -34.308,11.641 -34.068,11.641 -33.988,11.721 -33.988,12.067 -33.908,12.147 -33.668,12.147 -33.588,12.067 -33.588,11.721 -33.508,11.641 -33.268,11.641 -33.188,11.721 -33.188,11.983 -33.071,12.1 -32.449,12.1 -30.5,12.1 -30.1,11.7 -19.5,11.7 -18.595,10.795 v1(-17.145,10.795)
ENET2_RD2: J58.1 U14.47 | length 46.3
  1-TOP w0.2: J58.1@-59.7,5.4 -59.7,4.34 -59.36,4 -50.1,4 -49.7,3.6 -49.7,-30.05 -49.95,-30.3 U14.47@-49.95,-31.2
ENET2_RD2/UART4_CTS: J58.2 U7.C20 | length 54.1
  1-TOP w0.2: U7.C20@-17.78,6.35 v1(-17.145,6.985)
  8-BOTTOM w0.2: J58.2@-57.16,5.4 -55.76,4 -52.7,4 -52.225,4.475 -52.225,5.975 -47.8,10.4 -29.53,10.4 -29.03,10.4 -28.913,10.283 -28.913,10.172 -28.833,10.092 -28.593,10.092 -28.513,10.172 -28.513,10.35 -28.433,10.43 -28.193,10.43 -28.113,10.35 -28.113,10.172 -28.033,10.092 -27.793,10.092 -27.713,10.172 -27.713,10.35 -27.633,10.43 -27.393,10.43 -27.313,10.35 -27.313,10.172 -27.233,10.092 -26.993,10.092 -26.913,10.172 -26.913,10.35 -26.833,10.43 -26.593,10.43 -26.513,10.35 -26.513,10.172 -26.433,10.092 -26.193,10.092 -26.113,10.172 -26.113,10.35 -26.033,10.43 -25.793,10.43 -25.713,10.35 -25.713,10.172 -25.633,10.092 -25.393,10.092 -25.313,10.172 -25.313,10.35 -25.233,10.43 -24.993,10.43 -24.913,10.35 -24.913,10.172 -24.833,10.092 -24.593,10.092 -24.513,10.172 -24.513,10.35 -24.433,10.43 -24.193,10.43 -24.113,10.35 -24.113,10.172 -24.033,10.092 -23.793,10.092 -23.713,10.172 -23.713,10.35 -23.633,10.43 -23.393,10.43 -23.313,10.35 -23.313,10.172 -23.233,10.092 -22.993,10.092 -22.913,10.172 -22.913,10.283 -22.796,10.4 -21.975,10.4 -19.85,10.4 -19.325,9.875 -19.325,9.625 -19.575,9.375 -20.3,9.375 -20.425,9.25 -20.425,9.025 -20.275,8.875 -19.375,8.875 -19,9.25 -18.775,9.25 -18.6,9.075 -18.6,8.9 -18.85,8.65 -18.85,8.375 -18.725,8.25 -17.95,8.25 -17.145,7.445 v1(-17.145,6.985)
ENET2_RD3: J60.1 U14.48 | length 42.8
  1-TOP w0.2: J60.1@-59.7,2.5 -59.7,1.3 -59.5,1.1 -50.825,1.1 -50.2,0.475 -50.2,-30.05 -50.45,-30.3 U14.48@-50.45,-31.2
ENET2_RD3/GPIO4_IO27: J60.2 U7.B22 | length 57.5
  1-TOP w0.2: v1(-21.1,9.525) -19.685,9.525 U7.B22@-19.05,8.89
  8-BOTTOM w0.2: J60.2@-57.16,2.5 -55.76,1.1 -53.7,1.1 -45.275,9.525 -33.504,9.525 -33.004,9.525 -32.887,9.408 -32.887,8.94 -32.807,8.86 -32.567,8.86 -32.487,8.94 -32.487,9.456 -32.407,9.536 -32.167,9.536 -32.087,9.456 -32.087,8.94 -32.007,8.86 -31.767,8.86 -31.687,8.94 -31.687,9.456 -31.607,9.536 -31.367,9.536 -31.287,9.456 -31.287,8.94 -31.207,8.86 -30.967,8.86 -30.887,8.94 -30.887,9.456 -30.807,9.536 -30.567,9.536 -30.487,9.456 -30.487,8.94 -30.407,8.86 -30.167,8.86 -30.087,8.94 -30.087,9.456 -30.007,9.536 -29.767,9.536 -29.687,9.456 -29.687,8.94 -29.607,8.86 -29.367,8.86 -29.287,8.94 -29.287,9.456 -29.207,9.536 -28.967,9.536 -28.887,9.456 -28.887,8.94 -28.807,8.86 -28.567,8.86 -28.487,8.94 -28.487,9.456 -28.407,9.536 -28.167,9.536 -28.087,9.456 -28.087,8.94 -28.007,8.86 -27.767,8.86 -27.687,8.94 -27.687,9.456 -27.607,9.536 -27.367,9.536 -27.287,9.456 -27.287,8.94 -27.207,8.86 -26.967,8.86 -26.887,8.94 -26.887,9.456 -26.807,9.536 -26.567,9.536 -26.487,9.456 -26.487,8.94 -26.407,8.86 -26.167,8.86 -26.087,8.94 -26.087,9.456 -26.007,9.536 -25.767,9.536 -25.687,9.456 -25.687,8.94 -25.607,8.86 -25.367,8.86 -25.287,8.94 -25.287,9.456 -25.207,9.536 -24.967,9.536 -24.887,9.456 -24.887,8.94 -24.807,8.86 -24.567,8.86 -24.487,8.94 -24.487,9.456 -24.407,9.536 -24.167,9.536 -24.087,9.456 -24.087,8.94 -24.007,8.86 -23.767,8.86 -23.687,8.94 -23.687,9.456 -23.607,9.536 -23.367,9.536 -23.287,9.456 -23.287,8.94 -23.207,8.86 -22.967,8.86 -22.887,8.94 -22.887,9.408 -22.77,9.525 -22.364,9.525 v1(-21.1,9.525)
ENET2_RST: R113.1 U7.D25 | length 97.7
  1-TOP w0.2: v1(-58.4,-41.5) -57.88,-41.5 R113.1@-57.78,-41.4 ; v1(-17.145,13.335) U7.D25@-16.51,12.7
  3-INTOP w0.2: v1(-58.4,-41.5) -45.4,-41.5 -44.7,-40.8 -34.5,-40.8 -30.1,-36.4 v1(-30.1,-35.4) ; v1(-31.7,11.5) -16.8,11.5 -16.5,11.8 -16.5,12.69 v1(-17.145,13.335)
  6-INBOT w0.2: v1(-31.7,11.5) -31.7,-32.8 -30.1,-34.4 v1(-30.1,-35.4)
ENET2_RX_CTL: J55.1 U14.43 | length 57.4
  1-TOP w0.2: J55.1@-59.7,17 -59.76,16.94 -59.76,15.8 -59.56,15.6 -52.6,15.6 ; -52.568,15.568 -47.7,10.7 -47.7,-30.4 -47.95,-30.65 U14.43@-47.95,-31.2
ENET2_RX_CTL/GPIO4_IO22: J55.2 U7.C23 | length 43
  1-TOP w0.2: v1(-18.415,12.065) -18.415,10.795 U7.C23@-17.78,10.16
  8-BOTTOM w0.2: J55.2@-57.16,17 -55.76,15.6 -29.6,15.6 -26.7,12.7 -19.05,12.7 v1(-18.415,12.065)
ENET2_RXC: J53.1 U14.46 | length 49.5
  1-TOP w0.2: J53.1@-59.7,8.3 -59.7,7.24 -59.36,6.9 -49.9,6.9 -49.2,6.2 -49.2,-30.15 -49.45,-30.4 U14.46@-49.45,-31.2
ENET2_RXC/GPIO4_IO23: J53.2 U7.D22 | length 50.8
  1-TOP w0.2: v1(-17.145,9.525) U7.D22@-16.51,8.89
  8-BOTTOM w0.2: J53.2@-57.16,8.3 -55.76,6.9 -53.3,6.9 -49.2,11 -45.025,11 -44.925,11 -44.808,11.117 -44.808,11.444 -44.728,11.524 -44.488,11.524 -44.408,11.444 -44.408,11.066 -44.328,10.986 -44.088,10.986 -44.008,11.066 -44.008,11.444 -43.928,11.524 -43.688,11.524 -43.608,11.444 -43.608,11.066 -43.528,10.986 -43.288,10.986 -43.208,11.066 -43.208,11.444 -43.128,11.524 -42.888,11.524 -42.808,11.444 -42.808,11.066 -42.728,10.986 -42.488,10.986 -42.408,11.066 -42.408,11.444 -42.328,11.524 -42.088,11.524 -42.008,11.444 -42.008,11.066 -41.928,10.986 -41.688,10.986 -41.608,11.066 -41.608,11.444 -41.528,11.524 -41.288,11.524 -41.208,11.444 -41.208,11.066 -41.128,10.986 -40.888,10.986 -40.808,11.066 -40.808,11.444 -40.728,11.524 -40.488,11.524 -40.408,11.444 -40.408,11.066 -40.328,10.986 -40.088,10.986 -40.008,11.066 -40.008,11.444 -39.928,11.524 -39.688,11.524 -39.608,11.444 -39.608,11.066 -39.528,10.986 -39.288,10.986 -39.208,11.066 -39.208,11.444 -39.128,11.524 -38.888,11.524 -38.808,11.444 -38.808,11.117 -38.691,11 -38.05,11 -19.8,11 -18.325,9.525 v1(-17.145,9.525)
ENET2_TD0: J57.1 U14.50 | length 39.8
  1-TOP w0.2: J57.1@-59.7,-0.3 -59.7,-1.5 -59.5,-1.7 -51.125,-1.7 -50.7,-2.125 -50.7,-26 -51.45,-26.75 U14.50@-51.45,-31.2
ENET2_TD0/UART4_TX: J57.2 U7.C22 | length 60.5
  1-TOP w0.2: v1(-19.685,8.255) -18.415,8.255 U7.C22@-17.78,8.89
  8-BOTTOM w0.2: J57.2@-57.16,-0.3 -55.76,-1.7 -53.9,-1.7 -43.945,8.255 -43.753,8.255 -43.653,8.255 -43.535,8.372 -43.535,8.869 -43.455,8.949 -43.215,8.949 -43.135,8.869 -43.135,8.311 -43.055,8.231 -42.815,8.231 -42.735,8.311 -42.735,8.869 -42.655,8.949 -42.415,8.949 -42.335,8.869 -42.335,8.311 -42.255,8.231 -42.015,8.231 -41.935,8.311 -41.935,8.869 -41.855,8.949 -41.615,8.949 -41.535,8.869 -41.535,8.311 -41.455,8.231 -41.215,8.231 -41.135,8.311 -41.135,8.869 -41.055,8.949 -40.815,8.949 -40.735,8.869 -40.735,8.311 -40.655,8.231 -40.415,8.231 -40.335,8.311 -40.335,8.869 -40.255,8.949 -40.015,8.949 -39.935,8.869 -39.935,8.311 -39.855,8.231 -39.615,8.231 -39.535,8.311 -39.535,8.869 -39.455,8.949 -39.215,8.949 -39.135,8.869 -39.135,8.311 -39.055,8.231 -38.815,8.231 -38.735,8.311 -38.735,8.869 -38.655,8.949 -38.415,8.949 -38.335,8.869 -38.335,8.311 -38.255,8.231 -38.015,8.231 -37.935,8.311 -37.935,8.869 -37.855,8.949 -37.615,8.949 -37.535,8.869 -37.535,8.311 -37.455,8.231 -37.215,8.231 -37.135,8.311 -37.135,8.869 -37.055,8.949 -36.815,8.949 -36.735,8.869 -36.735,8.311 -36.655,8.231 -36.415,8.231 -36.335,8.311 -36.335,8.869 -36.255,8.949 -36.015,8.949 -35.935,8.869 -35.935,8.311 -35.855,8.231 -35.615,8.231 -35.535,8.311 -35.535,8.869 -35.455,8.949 -35.215,8.949 -35.135,8.869 -35.135,8.311 -35.055,8.231 -34.815,8.231 -34.735,8.311 -34.735,8.869 -34.655,8.949 -34.415,8.949 -34.335,8.869 -34.335,8.311 -34.255,8.231 -34.015,8.231 -33.935,8.311 -33.935,8.869 -33.855,8.949 -33.615,8.949 -33.535,8.869 -33.535,8.372 -33.418,8.255 -33.099,8.255 v1(-19.685,8.255)
ENET2_TD1: J59.1 U14.51 | length 36.3
  1-TOP w0.2: J59.1@-59.7,-3.2 -59.7,-4.36 -59.36,-4.7 -51.725,-4.7 -51.2,-5.225 -51.2,-25.7 -51.95,-26.45 U14.51@-51.95,-31.2
ENET2_TD1/UART4_RTS: J59.2 U7.D20 | length 64
  1-TOP w0.2: v1(-17.145,5.715) U7.D20@-16.51,6.35
  8-BOTTOM w0.2: J59.2@-57.16,-3.2 -55.96,-4.4 -53.7,-4.4 -49.662,-0.362 -49.592,-0.292 -49.592,-0.126 -49.942,0.224 -49.942,0.338 -49.773,0.507 -49.66,0.507 -49.262,0.11 -49.149,0.11 -48.979,0.28 -48.979,0.393 -49.377,0.79 -49.377,0.903 -49.207,1.073 -49.094,1.073 -48.696,0.676 -48.583,0.676 -48.414,0.845 -48.414,0.958 -48.811,1.356 -48.811,1.469 -48.641,1.639 -48.528,1.639 -48.131,1.241 -48.018,1.241 -47.848,1.411 -47.848,1.524 -48.245,1.922 -48.245,2.035 -48.076,2.204 -47.962,2.204 -47.565,1.807 -47.452,1.807 -47.282,1.977 -47.282,2.09 -47.68,2.487 -47.68,2.6 -47.51,2.77 -47.397,2.77 -46.999,2.373 -46.886,2.373 -46.716,2.542 -46.716,2.655 -47.114,3.053 -47.114,3.166 -46.944,3.336 -46.831,3.336 -46.434,2.938 -46.32,2.938 -46.151,3.108 -46.151,3.221 -46.548,3.619 -46.548,3.732 -46.379,3.901 -46.265,3.901 -45.868,3.504 -45.755,3.504 -45.585,3.674 -45.585,3.787 -45.983,4.184 -45.983,4.297 -45.813,4.467 -45.7,4.467 -45.302,4.07 -45.189,4.07 -45.019,4.239 -45.019,4.352 -45.417,4.75 -45.417,4.863 -45.247,5.033 -45.134,5.033 -44.737,4.635 -44.623,4.635 -44.454,4.805 -44.454,4.918 -44.851,5.316 -44.851,5.429 -44.682,5.598 -44.568,5.598 -44.171,5.201 -44.058,5.201 -43.888,5.371 -43.888,5.484 -44.286,5.881 -44.286,5.994 -44.116,6.164 -44.003,6.164 -43.605,5.767 -43.492,5.767 -43.322,5.936 -43.322,6.05 -43.72,6.447 -43.72,6.56 -43.55,6.73 -43.437,6.73 -43.04,6.332 -42.926,6.332 -42.757,6.502 -42.757,6.615 -43.154,7.013 -43.154,7.126 -42.984,7.296 -42.871,7.296 -42.521,6.945 -42.355,6.945 -42.163,7.137 -41.6,7.7 -18.2,7.7 -17.8,7.3 -17.8,6.37 v1(-17.145,5.715)
ENET2_TD2: J45.1 U14.54 | length 29.8
  1-TOP w0.2: J45.1@-59.7,-9 -59.7,-10.06 -59.26,-10.5 -52.75,-10.5 -52.2,-11.05 -52.2,-23.3 -53.7,-24.8 -53.7,-30.25 -53.45,-30.5 U14.54@-53.45,-31.2
ENET2_TD2/GPIO4_IO14: J45.2 U7.C21 | length 70.5
  1-TOP w0.2: v1(-18.415,6.985) U7.C21@-17.78,7.62
  8-BOTTOM w0.2: J45.2@-57.16,-9 -55.66,-10.5 -54.2,-10.5 -39.025,4.675 -33.703,4.675 -33.602,4.675 -33.485,4.792 -33.485,5.095 -33.405,5.175 -33.165,5.175 -33.085,5.095 -33.085,4.417 -33.005,4.337 -32.765,4.337 -32.685,4.417 -32.685,5.095 -32.605,5.175 -32.365,5.175 -32.285,5.095 -32.285,4.417 -32.205,4.337 -31.965,4.337 -31.885,4.417 -31.885,5.095 -31.805,5.175 -31.565,5.175 -31.485,5.095 -31.485,4.417 -31.405,4.337 -31.165,4.337 -31.085,4.417 -31.085,5.095 -31.005,5.175 -30.765,5.175 -30.685,5.095 -30.685,4.417 -30.605,4.337 -30.365,4.337 -30.285,4.417 -30.285,5.095 -30.205,5.175 -29.965,5.175 -29.885,5.095 -29.885,4.417 -29.805,4.337 -29.565,4.337 -29.485,4.417 -29.485,5.095 -29.405,5.175 -29.165,5.175 -29.085,5.095 -29.085,4.417 -29.005,4.337 -28.765,4.337 -28.685,4.417 -28.685,5.095 -28.605,5.175 -28.365,5.175 -28.285,5.095 -28.285,4.417 -28.205,4.337 -27.965,4.337 -27.885,4.417 -27.885,5.095 -27.805,5.175 -27.565,5.175 -27.485,5.095 -27.485,4.417 -27.405,4.337 -27.165,4.337 -27.085,4.417 -27.085,5.095 -27.005,5.175 -26.765,5.175 -26.685,5.095 -26.685,4.417 -26.605,4.337 -26.365,4.337 -26.285,4.417 -26.285,5.095 -26.205,5.175 -25.965,5.175 -25.885,5.095 -25.885,4.417 -25.805,4.337 -25.565,4.337 -25.485,4.417 -25.485,5.095 -25.405,5.175 -25.165,5.175 -25.085,5.095 -25.085,4.417 -25.005,4.337 -24.765,4.337 -24.685,4.417 -24.685,5.095 -24.605,5.175 -24.365,5.175 -24.285,5.095 -24.285,4.417 -24.205,4.337 -23.965,4.337 -23.885,4.417 -23.885,5.095 -23.805,5.175 -23.565,5.175 -23.485,5.095 -23.485,4.417 -23.405,4.337 -23.165,4.337 -23.085,4.417 -23.085,5.095 -23.005,5.175 -22.765,5.175 -22.685,5.095 -22.685,4.417 -22.605,4.337 -22.365,4.337 -22.285,4.417 -22.285,5.095 -22.205,5.175 -21.965,5.175 -21.885,5.095 -21.885,4.417 -21.805,4.337 -21.565,4.337 -21.485,4.417 -21.485,4.558 -21.368,4.675 -21.068,4.675 -20.425,4.675 -20,5.1 -18.95,5.1 -18.415,5.635 v1(-18.415,6.985)
ENET2_TD3: J52.1 U14.55 | length 26.7
  1-TOP w0.2: J52.1@-59.7,-11.9 -59.7,-12.96 -59.36,-13.3 -54.2,-13.3 -52.925,-13.3 -52.7,-13.525 -52.7,-23.093 -54.2,-24.593 -54.2,-30.3 -53.95,-30.55 U14.55@-53.95,-31.2
ENET2_TD3/GPIO4_IO16: J52.2 U7.B21 | length 73.6
  1-TOP w0.2: v1(-19.685,6.985) U7.B21@-19.05,7.62
  8-BOTTOM w0.2: J52.2@-57.16,-11.9 -58.4,-10.66 -58.4,-5.55 -57.75,-4.9 -53.4,-4.9 -41.515,6.985 -36.341,6.985 -35.841,6.985 -35.724,6.868 -35.724,6.428 -35.644,6.348 -35.404,6.348 -35.324,6.428 -35.324,6.944 -35.244,7.024 -35.004,7.024 -34.924,6.944 -34.924,6.428 -34.844,6.348 -34.604,6.348 -34.524,6.428 -34.524,6.944 -34.444,7.024 -34.204,7.024 -34.124,6.944 -34.124,6.428 -34.044,6.348 -33.804,6.348 -33.724,6.428 -33.724,6.944 -33.644,7.024 -33.404,7.024 -33.324,6.944 -33.324,6.428 -33.244,6.348 -33.004,6.348 -32.924,6.428 -32.924,6.944 -32.844,7.024 -32.604,7.024 -32.524,6.944 -32.524,6.428 -32.444,6.348 -32.204,6.348 -32.124,6.428 -32.124,6.944 -32.044,7.024 -31.804,7.024 -31.724,6.944 -31.724,6.428 -31.644,6.348 -31.404,6.348 -31.324,6.428 -31.324,6.944 -31.244,7.024 -31.004,7.024 -30.924,6.944 -30.924,6.428 -30.844,6.348 -30.604,6.348 -30.524,6.428 -30.524,6.944 -30.444,7.024 -30.204,7.024 -30.124,6.944 -30.124,6.428 -30.044,6.348 -29.804,6.348 -29.724,6.428 -29.724,6.944 -29.644,7.024 -29.404,7.024 -29.324,6.944 -29.324,6.428 -29.244,6.348 -29.004,6.348 -28.924,6.428 -28.924,6.944 -28.844,7.024 -28.604,7.024 -28.524,6.944 -28.524,6.428 -28.444,6.348 -28.204,6.348 -28.124,6.428 -28.124,6.944 -28.044,7.024 -27.804,7.024 -27.724,6.944 -27.724,6.428 -27.644,6.348 -27.404,6.348 -27.324,6.428 -27.324,6.944 -27.244,7.024 -27.004,7.024 -26.924,6.944 -26.924,6.428 -26.844,6.348 -26.604,6.348 -26.524,6.428 -26.524,6.944 -26.444,7.024 -26.204,7.024 -26.124,6.944 -26.124,6.428 -26.044,6.348 -25.804,6.348 -25.724,6.428 -25.724,6.944 -25.644,7.024 -25.404,7.024 -25.324,6.944 -25.324,6.428 -25.244,6.348 -25.004,6.348 -24.924,6.428 -24.924,6.944 -24.844,7.024 -24.604,7.024 -24.524,6.944 -24.524,6.428 -24.444,6.348 -24.204,6.348 -24.124,6.428 -24.124,6.944 -24.044,7.024 -23.804,7.024 -23.724,6.944 -23.724,6.428 -23.644,6.348 -23.404,6.348 -23.324,6.428 -23.324,6.944 -23.244,7.024 -23.004,7.024 -22.924,6.944 -22.924,6.428 -22.844,6.348 -22.604,6.348 -22.524,6.428 -22.524,6.944 -22.444,7.024 -22.204,7.024 -22.124,6.944 -22.124,6.428 -22.044,6.348 -21.804,6.348 -21.724,6.428 -21.724,6.944 -21.644,7.024 -21.404,7.024 -21.324,6.944 -21.324,6.428 -21.244,6.348 -21.004,6.348 -20.924,6.428 -20.924,6.868 -20.807,6.985 -20.4,6.985 v1(-19.685,6.985)
ENET2_TX_CTL: J51.1 U14.56 | length 23.1
  1-TOP w0.2: J51.1@-59.7,-14.8 -59.7,-15.9 -59.4,-16.2 -53.8,-16.2 -53.2,-16.8 -53.2,-22.9 -54.7,-24.4 -54.7,-30.3 -54.45,-30.55 U14.56@-54.45,-31.2
ENET2_TX_CTL/GPIO4_IO20: J51.2 U7.B19 | length 77.2
  1-TOP w0.2: v1(-19.685,4.445) U7.B19@-19.05,5.08
  8-BOTTOM w0.2: J51.2@-57.16,-14.8 -57.16,-13.66 -56.8,-13.3 -51,-13.3 -47.7,-10 -47.7,-6.3 -41.665,-0.265 -41.594,-0.194 -41.594,-0.029 -41.808,0.186 -41.808,0.299 -41.639,0.468 -41.526,0.468 -41.126,0.069 -41.013,0.069 -40.843,0.239 -40.843,0.352 -41.243,0.751 -41.243,0.864 -41.073,1.034 -40.96,1.034 -40.56,0.635 -40.447,0.635 -40.277,0.804 -40.277,0.917 -40.677,1.317 -40.677,1.43 -40.507,1.6 -40.394,1.6 -39.995,1.2 -39.881,1.2 -39.712,1.37 -39.712,1.483 -40.111,1.883 -40.111,1.996 -39.942,2.166 -39.828,2.166 -39.429,1.766 -39.316,1.766 -39.146,1.936 -39.146,2.049 -39.546,2.448 -39.546,2.561 -39.376,2.731 -39.263,2.731 -39.049,2.517 -38.883,2.517 -38.55,2.85 -38.3,3.1 -37.69,3.1 -37.59,3.1 -37.473,3.217 -37.473,3.665 -37.393,3.745 -37.153,3.745 -37.073,3.665 -37.073,3.174 -36.993,3.094 -36.753,3.094 -36.673,3.174 -36.673,3.665 -36.593,3.745 -36.353,3.745 -36.273,3.665 -36.273,3.174 -36.193,3.094 -35.953,3.094 -35.873,3.174 -35.873,3.665 -35.793,3.745 -35.553,3.745 -35.473,3.665 -35.473,3.174 -35.393,3.094 -35.153,3.094 -35.073,3.174 -35.073,3.665 -34.993,3.745 -34.753,3.745 -34.673,3.665 -34.673,3.174 -34.593,3.094 -34.353,3.094 -34.273,3.174 -34.273,3.665 -34.193,3.745 -33.953,3.745 -33.873,3.665 -33.873,3.174 -33.793,3.094 -33.553,3.094 -33.473,3.174 -33.473,3.665 -33.393,3.745 -33.153,3.745 -33.073,3.665 -33.073,3.174 -32.993,3.094 -32.753,3.094 -32.673,3.174 -32.673,3.665 -32.593,3.745 -32.353,3.745 -32.273,3.665 -32.273,3.174 -32.193,3.094 -31.953,3.094 -31.873,3.174 -31.873,3.665 -31.793,3.745 -31.553,3.745 -31.473,3.665 -31.473,3.174 -31.393,3.094 -31.153,3.094 -31.073,3.174 -31.073,3.665 -30.993,3.745 -30.753,3.745 -30.673,3.665 -30.673,3.174 -30.593,3.094 -30.353,3.094 -30.273,3.174 -30.273,3.665 -30.193,3.745 -29.953,3.745 -29.873,3.665 -29.873,3.174 -29.793,3.094 -29.553,3.094 -29.473,3.174 -29.473,3.665 -29.393,3.745 -29.153,3.745 -29.073,3.665 -29.073,3.174 -28.993,3.094 -28.753,3.094 -28.673,3.174 -28.673,3.665 -28.593,3.745 -28.353,3.745 -28.273,3.665 -28.273,3.174 -28.193,3.094 -27.953,3.094 -27.873,3.174 -27.873,3.665 -27.793,3.745 -27.553,3.745 -27.473,3.665 -27.473,3.174 -27.393,3.094 -27.153,3.094 -27.073,3.174 -27.073,3.665 -26.993,3.745 -26.753,3.745 -26.673,3.665 -26.673,3.174 -26.593,3.094 -26.353,3.094 -26.273,3.174 -26.273,3.665 -26.193,3.745 -25.953,3.745 -25.873,3.665 -25.873,3.174 -25.793,3.094 -25.553,3.094 -25.473,3.174 -25.473,3.665 -25.393,3.745 -25.153,3.745 -25.073,3.665 -25.073,3.174 -24.993,3.094 -24.753,3.094 -24.673,3.174 -24.673,3.665 -24.593,3.745 -24.353,3.745 -24.273,3.665 -24.273,3.174 -24.193,3.094 -23.953,3.094 -23.873,3.174 -23.873,3.665 -23.793,3.745 -23.553,3.745 -23.473,3.665 -23.473,3.174 -23.393,3.094 -23.153,3.094 -23.073,3.174 -23.073,3.665 -22.993,3.745 -22.753,3.745 -22.673,3.665 -22.673,3.174 -22.593,3.094 -22.353,3.094 -22.273,3.174 -22.273,3.665 -22.193,3.745 -21.953,3.745 -21.873,3.665 -21.873,3.217 -21.756,3.1 -21.65,3.1 -21.03,3.1 v1(-19.685,4.445)
ENET2_TXC: J43.1 U14.53 | length 33.3
  1-TOP w0.2: J43.1@-59.7,-6.1 -59.7,-7.2 -59.4,-7.5 -52.25,-7.5 -51.7,-8.05 -51.7,-25.3 -53.2,-26.8 -53.2,-30.15 -52.95,-30.4 U14.53@-52.95,-31.2
ENET2_TXC/GPIO4_IO21: J43.2 U7.B20 | length 67
  1-TOP w0.2: v1(-19.685,5.715) U7.B20@-19.05,6.35
  8-BOTTOM w0.2: J43.2@-57.16,-6.1 -55.76,-7.5 -53.7,-7.5 -49.029,-2.829 -48.959,-2.759 -48.959,-2.593 -49.412,-2.14 -49.412,-2.027 -49.242,-1.857 -49.129,-1.857 -48.644,-2.342 -48.531,-2.342 -48.361,-2.172 -48.361,-2.059 -48.846,-1.574 -48.846,-1.461 -48.676,-1.291 -48.563,-1.291 -48.079,-1.776 -47.965,-1.776 -47.796,-1.606 -47.796,-1.493 -48.28,-1.009 -48.28,-0.895 -48.111,-0.726 -47.997,-0.726 -47.513,-1.21 -47.4,-1.21 -47.23,-1.04 -47.23,-0.927 -47.715,-0.443 -47.715,-0.33 -47.545,-0.16 -47.432,-0.16 -46.979,-0.613 -46.813,-0.613 -46.657,-0.457 -45.938,0.262 -45.867,0.333 -45.867,0.499 -46.422,1.054 -46.422,1.167 -46.253,1.337 -46.139,1.337 -45.528,0.726 -45.415,0.726 -45.245,0.895 -45.245,1.008 -45.857,1.62 -45.857,1.733 -45.687,1.902 -45.574,1.902 -44.963,1.291 -44.849,1.291 -44.68,1.461 -44.68,1.574 -45.291,2.185 -45.291,2.298 -45.121,2.468 -45.008,2.468 -44.397,1.857 -44.284,1.857 -44.114,2.027 -44.114,2.14 -44.725,2.751 -44.725,2.864 -44.556,3.034 -44.442,3.034 -43.831,2.423 -43.718,2.423 -43.548,2.592 -43.548,2.705 -44.16,3.317 -44.16,3.43 -43.99,3.599 -43.877,3.599 -43.265,2.988 -43.152,2.988 -42.983,3.158 -42.983,3.271 -43.594,3.882 -43.594,3.995 -43.424,4.165 -43.311,4.165 -42.7,3.554 -42.587,3.554 -42.417,3.724 -42.417,3.837 -43.028,4.448 -43.028,4.561 -42.858,4.731 -42.745,4.731 -42.134,4.12 -42.021,4.12 -41.851,4.289 -41.851,4.402 -42.462,5.014 -42.462,5.127 -42.293,5.297 -42.18,5.297 -41.568,4.685 -41.455,4.685 -41.286,4.855 -41.286,4.968 -41.897,5.579 -41.897,5.693 -41.727,5.862 -41.614,5.862 -41.059,5.307 -40.893,5.307 -40.621,5.579 -40.485,5.715 v1(-19.685,5.715)
ETH1_TXRXA_N: J26.3 U13.27 | length 21.1
  1-TOP w0.15: U13.27@-67.4,-39.2 -67.327,-39.273 -67.327,-39.874 -66.7,-40.501 -66.7,-43.6 -66.3,-44 -66.3,-44.1 v1(-66.337,-44.137)
  8-BOTTOM w0.15: J26.3@-72.49,-48.91 -73.382,-49.802 -73.506,-49.802 -73.594,-49.714 -73.594,-47.305 -74.1,-46.799 -74.1,-45.301 -72.599,-43.8 -67.8,-43.8 -67.375,-43.8 -67.287,-43.888 -67.287,-44.289 -67.217,-44.359 -67.007,-44.359 -66.937,-44.289 -66.937,-43.888 -66.849,-43.8 -66.6,-43.8 -66.5,-43.8 -66.337,-43.963 v1(-66.337,-44.137)
ETH1_TXRXA_P: J26.2 U13.28 | length 21
  1-TOP w0.15: U13.28@-66.9,-39.2 -66.973,-39.273 -66.973,-39.727 -66.346,-40.354 -66.346,-43.453 -66.05,-43.75 -65.95,-43.75 v1(-65.913,-43.713)
  8-BOTTOM w0.15: J26.2@-73.671,-51.361 -73.671,-50.138 -73.948,-49.861 -73.948,-47.452 -74.454,-46.946 -74.454,-45.154 -72.746,-43.446 -67.447,-43.446 -66.353,-43.446 -66.087,-43.713 v1(-65.913,-43.713)
ETH1_TXRXB_N: J26.5 U13.23 | length 22.7
  1-TOP w0.15: J26.5@-69.95,-48.91 -69.95,-50.302 -69.862,-50.39 -69.738,-50.39 -68.9,-49.552 -68.9,-48.199 -68.047,-47.346 -63.997,-47.346 -63.679,-47.028 -63.679,-45.715 -63.994,-45.4 -67.001,-45.4 -67.975,-44.425 -68.453,-43.948 -68.577,-43.948 -68.84,-44.211 -68.939,-44.211 -69.088,-44.062 -69.088,-43.963 -68.825,-43.7 -68.825,-43.576 -69.125,-43.275 -69.327,-43.074 -69.327,-39.273 U13.23@-69.4,-39.2
ETH1_TXRXB_P: J26.4 U13.24 | length 22.7
  1-TOP w0.15: J26.4@-71.22,-51.45 -70.323,-50.553 -70.199,-50.553 -70.009,-50.744 -69.591,-50.744 -68.546,-49.698 -68.546,-48.346 -67.9,-47.7 -63.85,-47.7 -63.325,-47.175 -63.325,-45.568 -63.847,-45.046 -66.854,-45.046 -68.973,-42.927 -68.973,-39.273 U13.24@-68.9,-39.2
ETH1_TXRXC_N: J26.7 U13.21 | length 21.1
  1-TOP w0.15: v1(-71.3,-46.1) -71.177,-46.223 -69.323,-46.223 -69,-45.9 -69,-45.3 -69.5,-44.8 -70.219,-44.8 -70.294,-44.8 -70.382,-44.888 -70.382,-44.996 -70.452,-45.066 -70.662,-45.066 -70.732,-44.996 -70.732,-44.888 -70.82,-44.8 -71.1,-44.8 -71.4,-44.8 -71.8,-44.4 -71.8,-43.799 -71.401,-43.4 -70.6,-43.4 -70.327,-43.127 -70.327,-39.273 U13.21@-70.4,-39.2
  8-BOTTOM w0.15: v1(-71.3,-46.1) -71.177,-46.223 -70.724,-46.223 -70.201,-45.7 -69.199,-45.7 -68.514,-46.385 -68.514,-47.815 -68.514,-49.714 -68.426,-49.802 -68.302,-49.802 J26.7@-67.41,-48.91
ETH1_TXRXC_P: J26.6 U13.22 | length 21.1
  1-TOP w0.15: v1(-71.3,-46.7) -71.177,-46.577 -70.33,-46.577 ; -70.477,-46.577 -69.176,-46.577 -68.646,-46.047 -68.646,-45.153 -69.353,-44.446 -71.253,-44.446 -71.446,-44.253 -71.446,-43.946 -71.254,-43.754 -70.453,-43.754 -69.973,-43.274 -69.973,-39.273 U13.22@-69.9,-39.2
  8-BOTTOM w0.15: v1(-71.3,-46.7) -71.177,-46.577 -70.577,-46.577 -70.054,-46.054 -69.346,-46.054 -68.868,-46.532 -68.868,-47.668 -68.868,-49.861 -68.591,-50.138 J26.6@-68.591,-51.361
ETH1_TXRXD_N: J26.9 U13.17 | length 21.1
  1-TOP w0.15: v1(-72.977,-46.1) -72.854,-45.977 -72.854,-44.346 -73.25,-43.95 -73.25,-41.599 -72.854,-41.203 -72.854,-40.353 -72.327,-39.826 -72.327,-39.273 U13.17@-72.4,-39.2
  8-BOTTOM w0.15: v1(-72.977,-46.1) -72.854,-45.977 -72.854,-45.253 -72.247,-44.646 -67.754,-44.646 -65.974,-46.426 -65.974,-49.714 -65.886,-49.802 -65.762,-49.802 J26.9@-64.87,-48.91
ETH1_TXRXD_P: J26.8 U13.18 | length 21
  1-TOP w0.15: v1(-72.377,-46.1) -72.5,-45.977 -72.5,-44.2 -72.871,-43.828 -72.896,-43.803 -72.896,-43.403 -72.808,-43.315 -72.621,-43.315 -72.551,-43.245 -72.551,-43.035 -72.621,-42.965 -72.826,-42.965 -72.896,-42.895 -72.896,-42.685 -72.826,-42.615 -72.724,-42.615 -72.654,-42.545 -72.654,-42.335 -72.724,-42.265 -72.808,-42.265 -72.896,-42.178 -72.896,-41.857 -72.896,-41.746 -72.5,-41.35 -72.5,-40.5 -71.973,-39.973 -71.973,-39.273 U13.18@-71.9,-39.2
  8-BOTTOM w0.15: v1(-72.377,-46.1) -72.5,-45.977 -72.5,-45.4 -72.1,-45 -67.901,-45 -66.328,-46.573 -66.328,-49.861 -66.051,-50.138 J26.8@-66.051,-51.361
ETH2_TXRXA_N: J27.3 U14.27 | length 21.8
  1-TOP w0.15: U14.27@-48.45,-39.2 -48.377,-39.273 -48.377,-40.047 -47.754,-40.67 -47.754,-41.546 -46.637,-42.663 v1(-46.637,-42.837)
  8-BOTTOM w0.15: J27.3@-51.02,-48.91 -51.912,-49.802 -52.036,-49.802 -52.124,-49.714 -52.124,-47.175 -53.646,-45.653 -53.646,-42.847 -53.199,-42.4 -51.4,-42.4 -50.975,-42.4 -50.887,-42.488 -50.887,-42.88 -50.817,-42.95 -50.607,-42.95 -50.537,-42.88 -50.537,-42.488 -50.449,-42.4 -50.1,-42.4 -47.4,-42.4 -46.9,-42.4 -46.637,-42.663 v1(-46.637,-42.837)
ETH2_TXRXA_P: J27.2 U14.28 | length 21.7
  1-TOP w0.15: U14.28@-47.95,-39.2 -48.023,-39.273 -48.023,-39.9 -47.4,-40.523 -47.4,-41.399 -46.45,-42.35 -46.387,-42.413 v1(-46.213,-42.413)
  8-BOTTOM w0.15: J27.2@-52.201,-51.361 -52.201,-50.138 -52.478,-49.861 -52.478,-47.322 -54,-45.8 -54,-42.7 -53.346,-42.046 -46.753,-42.046 -46.387,-42.413 v1(-46.213,-42.413)
ETH2_TXRXB_N: J27.5 U14.23 | length 23.4
  1-TOP w0.15: U14.23@-50.45,-39.2 -50.377,-39.273 -50.377,-43.123 -49.646,-43.854 -45.047,-43.854 -43.154,-45.747 -43.154,-46.953 -43.447,-47.246 -46.285,-47.246 -46.647,-47.246 -46.854,-47.454 -46.979,-47.454 -47.242,-47.19 -47.341,-47.19 -47.49,-47.339 -47.49,-47.438 -47.226,-47.701 -47.226,-47.825 -47.325,-47.924 -47.43,-48.029 -47.43,-49.552 -48.268,-50.39 -48.392,-50.39 -48.48,-50.302 J27.5@-48.48,-48.91
ETH2_TXRXB_P: J27.4 U14.24 | length 23.4
  1-TOP w0.15: U14.24@-49.95,-39.2 -50.023,-39.273 -50.023,-42.976 -49.499,-43.5 -44.9,-43.5 -42.8,-45.6 -42.8,-47.1 -43.3,-47.6 -46.5,-47.6 -47.076,-48.176 -47.076,-49.698 -48.121,-50.744 -48.539,-50.744 -48.729,-50.553 -48.853,-50.553 J27.4@-49.75,-51.45
ETH2_TXRXC_N: J27.7 U14.21 | length 21.8
  1-TOP w0.15: v1(-51.9,-45.477) -51.777,-45.6 -50.9,-45.6 -50.799,-45.6 -50.399,-46 -49.327,-46 -49.029,-45.702 -49.029,-45.102 -49.331,-44.8 -50.4,-44.8 -51.377,-43.823 -51.377,-39.273 U14.21@-51.45,-39.2
  8-BOTTOM w0.15: v1(-51.9,-45.477) -51.9,-45.5 -51.8,-45.6 -47.8,-45.6 -47.044,-46.356 -47.044,-46.675 -47.044,-47.047 -46.956,-47.135 -46.847,-47.135 -46.777,-47.205 -46.777,-47.415 -46.847,-47.485 -46.956,-47.485 -47.044,-47.573 -47.044,-47.998 -47.044,-49.714 -46.956,-49.802 -46.832,-49.802 J27.7@-45.94,-48.91
ETH2_TXRXC_P: J27.6 U14.22 | length 21.7
  1-TOP w0.15: v1(-51.9,-46.077) -51.777,-45.954 -50.946,-45.954 -50.546,-46.354 -49.18,-46.354 -48.675,-45.849 -48.675,-44.955 -49.184,-44.446 -50.253,-44.446 -51.023,-43.676 -51.023,-39.273 U14.22@-50.95,-39.2
  8-BOTTOM w0.15: v1(-51.9,-46.077) -51.9,-46.054 -51.8,-45.954 -47.947,-45.954 -47.398,-46.503 -47.398,-49.861 -47.121,-50.138 J27.6@-47.121,-51.361
ETH2_TXRXD_N: J27.9 U14.17 | length 21.8
  1-TOP w0.15: U14.17@-53.45,-39.2 -53.377,-39.273 -53.377,-39.777 -54,-40.4 -54,-43.147 -53.347,-43.8 -53.077,-43.8 -52.677,-44.2 -52.677,-44.477 v1(-52.8,-44.6)
  8-BOTTOM w0.15: v1(-52.8,-44.6) -52.677,-44.477 -52.677,-43.976 -52.247,-43.546 -46.829,-43.546 -44.504,-45.871 -44.504,-49.714 -44.416,-49.802 -44.292,-49.802 J27.9@-43.4,-48.91
ETH2_TXRXD_P: J27.8 U14.18 | length 21.7
  1-TOP w0.15: U14.18@-52.95,-39.2 -53.023,-39.273 -53.023,-39.924 -53.646,-40.547 -53.646,-43 -53.2,-43.446 -52.93,-43.446 -52.323,-44.053 -52.323,-44.477 v1(-52.2,-44.6)
  8-BOTTOM w0.15: v1(-52.2,-44.6) -52.323,-44.477 -52.323,-44.123 -52.1,-43.9 -46.976,-43.9 -44.858,-46.018 -44.858,-46.588 -44.858,-47.013 -44.946,-47.101 -45.294,-47.101 -45.364,-47.171 -45.364,-47.381 -45.294,-47.451 -44.946,-47.451 -44.858,-47.539 -44.858,-47.713 -44.858,-49.861 -44.581,-50.138 J27.8@-44.581,-51.361
FAA_N: L27.1 U20.8 | length 55
  1-TOP w0.168: v1(90.6,-17.7) 90.459,-17.559 90.459,-16.791 L27.1@90.7,-16.55 ; U20.8@109.4,-40.4 109.4,-41.1 109.491,-41.191 109.491,-41.541 109.775,-41.825 109.909,-41.959 111.659,-41.959 v1(111.8,-42.1)
  8-BOTTOM w0.168: v1(90.6,-17.7) 90.459,-17.841 90.459,-20.959 92.1,-22.6 113,-22.6 115.918,-25.518 115.918,-39.732 115.073,-40.576 113.691,-41.959 111.941,-41.959 v1(111.8,-42.1)
FAA_P: L27.4 U20.9 | length 54.2
  1-TOP w0.168: L27.4@89.9,-16.55 90.141,-16.791 90.141,-17.559 v1(90,-17.7) ; U20.9@109.9,-40.4 109.9,-41.1 109.809,-41.191 109.809,-41.409 110.041,-41.641 110.333,-41.641 110.432,-41.543 110.432,-41.483 110.505,-41.41 110.726,-41.41 110.8,-41.483 110.8,-41.543 110.898,-41.641 111.659,-41.641 v1(111.8,-41.5)
  8-BOTTOM w0.168: v1(90,-17.7) 90.141,-17.841 90.141,-21.091 91.968,-22.918 112.868,-22.918 115.6,-25.65 115.6,-39.6 113.559,-41.641 111.941,-41.641 v1(111.8,-41.5)
G_N: L26.4 U20.6 | length 47
  1-TOP w0.168: L26.4@83.892,-15.84 84.008,-15.956 84.035,-15.956 84.133,-16.054 84.133,-16.467 84.133,-16.959 v1(83.992,-17.1) ; U20.6@108.4,-40.4 108.4,-41.1 108.491,-41.191 108.491,-41.741 109.582,-42.832 109.582,-43.359 v1(109.441,-43.5)
  8-BOTTOM w0.168: v1(83.992,-17.1) 84.133,-17.241 84.133,-18.202 84.133,-18.333 84.133,-19.283 93.55,-28.7 101.85,-28.7 107.782,-34.632 107.782,-39.982 109.582,-41.782 109.582,-43.359 v1(109.441,-43.5)
G_P: L26.1 U20.7 | length 47
  1-TOP w0.168: v1(84.592,-17.1) 84.451,-16.959 84.451,-16.9 84.451,-16.054 84.55,-15.956 84.576,-15.956 L26.1@84.692,-15.84 ; U20.7@108.9,-40.4 108.9,-41.1 108.809,-41.191 108.809,-41.609 109.9,-42.7 109.9,-43.359 v1(110.041,-43.5)
  8-BOTTOM w0.168: v1(84.592,-17.1) 84.451,-17.241 84.451,-19.151 93.682,-28.382 101.982,-28.382 108.1,-34.5 108.1,-34.8 108.1,-35.9 108.1,-39.85 109.9,-41.65 109.9,-42.325 109.925,-42.35 109.925,-42.675 109.9,-42.7 109.9,-43.359 v1(110.041,-43.5)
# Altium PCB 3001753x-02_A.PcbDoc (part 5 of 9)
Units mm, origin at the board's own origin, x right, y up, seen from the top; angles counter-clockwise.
Board outline 210 x 130 mm, 8 copper layers (1-TOP, 2-GND, 3-INTOP, 4-PWR, 5-PWR, 6-INBOT, 7-GND, 8-BOTTOM), stack 1.646 mm thick; 651 components, 607 nets, 2780 pads, 1706 vias.

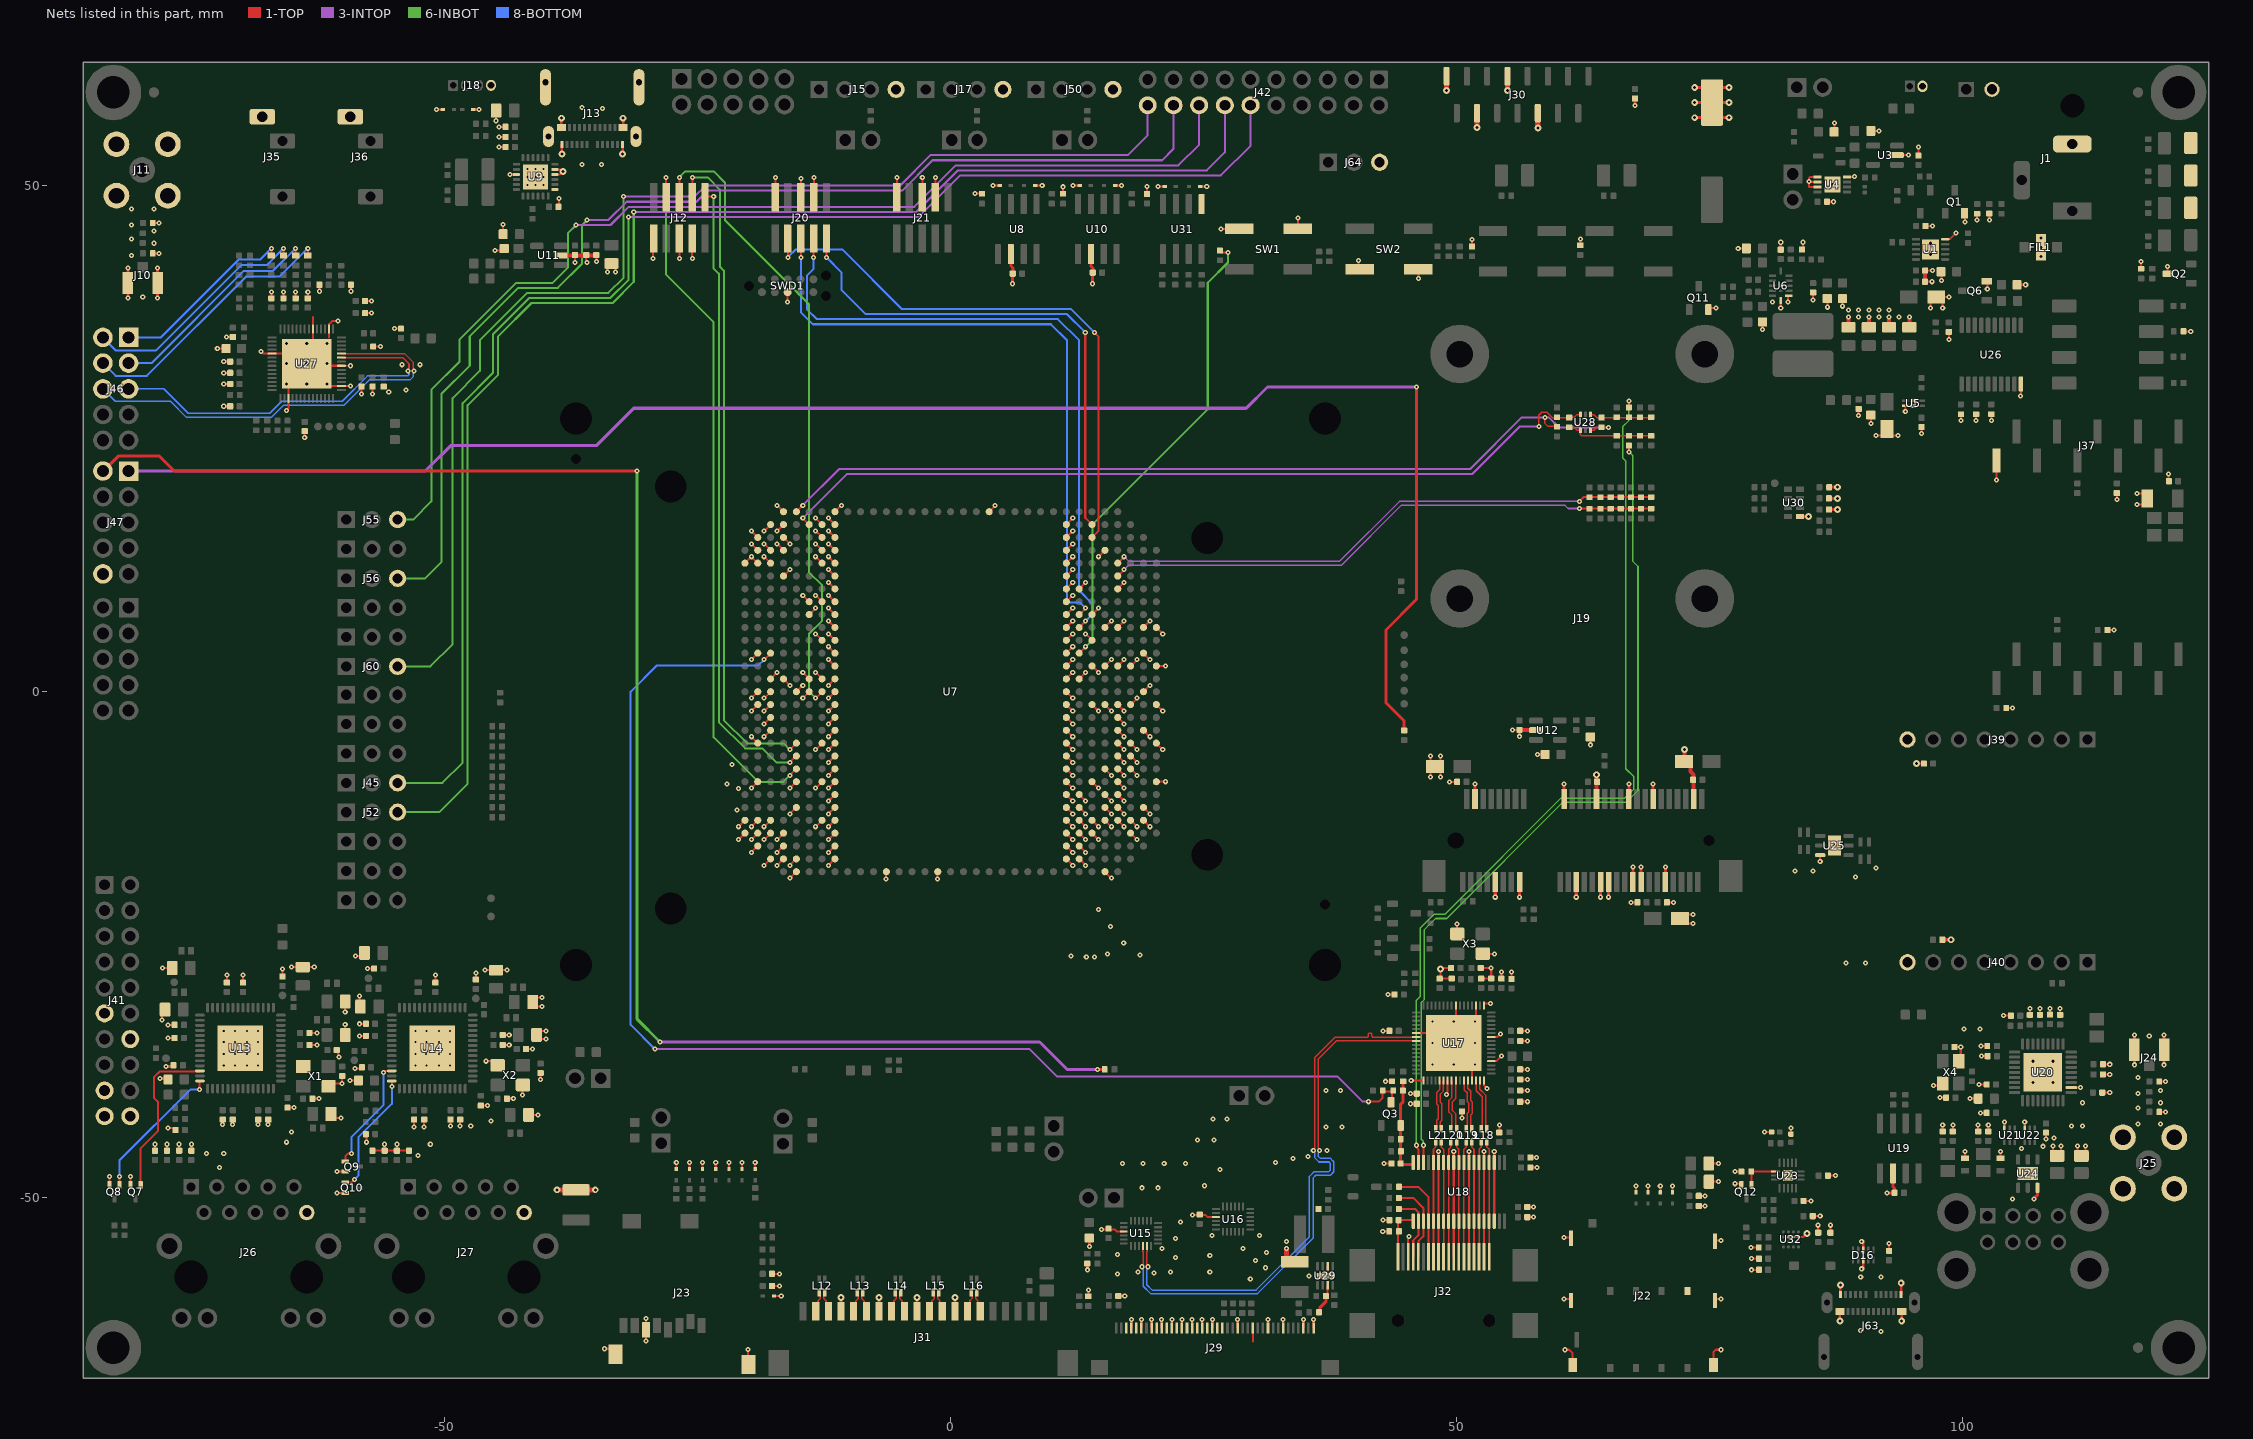
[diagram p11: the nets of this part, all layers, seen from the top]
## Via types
v1: diameter 0.5, hole 0.2, 1-TOP to 8-BOTTOM, 1453 vias
v2: diameter 0.68, hole 0.3, 1-TOP to 8-BOTTOM, 253 vias

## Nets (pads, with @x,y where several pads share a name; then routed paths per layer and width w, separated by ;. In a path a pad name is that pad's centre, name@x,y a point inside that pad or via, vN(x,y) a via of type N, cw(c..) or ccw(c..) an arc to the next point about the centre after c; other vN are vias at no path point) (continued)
GND: C1.1 C2.2 C3.1 C4.1 C5.1 C6.2 C7.1 C8.1 C9.2 C10.2 C12.1 C13.1 C14.1 C15.1 C16.2 C17.1 C18.1 C19.1 C20.1 C21.1 C22.1 C24.1 C25.1 C26.1 C27.1 C28.1 C29.2 C30.1 C31.2 C32.2 C33.1 C34.2 C35.1 C36.1 C37.1 C38.1 C39.2 C40.2 C41.2 C42.2 C43.1 C44.1 C45.1 C46.1 C47.1 C48.1 C49.1 C50.1 C51.1 C52.1 C53.1 C54.1 C55.1 C56.1 C57.1 C58.1 C59.1 C60.1 C61.1 C62.1 C63.1 C64.1 C65.1 C66.1 C67.2 C68.1 C69.1 C70.1 C71.1 C72.1 C73.1 C74.1 C75.1 C76.1 C77.1 C78.1 C79.1 C81.1 C82.1 C83.1 C84.1 C85.1 C86.1 C87.1 C88.1 C89.1 C90.1 C91.1 C92.1 C93.1 C94.2 C95.1 C96.1 C97.1 C98.1 C99.1 C100.1 C101.1 C102.1 C103.1 C104.1 C105.1 C106.1 C108.2 C109.2 C110.1 C111.1 C112.1 C113.1 C114.1 C115.1 C116.1 C118.1 C119.1 C120.1 C121.1 C122.1 C123.1 C124.1 C125.1 C126.1 C127.1 C128.1 C129.1 C130.1 C131.1 C132.1 C133.1 C134.1 C135.1 C136.1 C137.2 C138.2 C139.2 C140.1 C141.1 C142.1 C143.1 C144.1 C145.1 C146.2 C147.1 C148.1 C149.1 C150.1 C151.1 C152.1 C153.1 C154.1 C155.1 C156.1 C157.1 C158.2 C161.2 C164.2 C165.2 C166.2 C168.2 C170.2 C171.1 C173.1 C174.1 C175.1 C176.2 C177.2 C178.2 C179.1 C180.1 C181.1 C182.1 C183.2 C184.2 C185.1 C186.1 C187.1 C188.1 C189.1 C190.1 C191.1 C192.1 C193.1 C194.1 C195.1 C196.1 C197.1 C198.1 C199.1 C200.1 C201.1 D1.2 D3.1 D4.1 D7.1 D8.1 D9.1 D10.1 D11.1 D12.1 D13.1 D14.1 D16.3 D16.8 D19.1 D20.1 D22.1 D23.1 D24.2 D25.2 D26.2 D27.2 D28.2 D29.2 D30.2 D32.K D33.K D34.K FIL1.2 J1.2 J2.2 J4.2 J10.2 J10.3 J11.2 J11.3 J11.4 J11.5 J12.4 J12.6 J12.10 J13.A1 J13.A12 J13.B1 J13.B12 J13.MT1 J13.MT2 J13.MT3 J13.MT4 J15.4 J17.4 J18.4 J19.4 J19.9 J19.15 J19.18 J19.21 J19.26 J19.27 J19.29 J19.34 J19.35 J19.37 J19.40 J19.43 J19.50 J20.3 J20.5 J20.9 J21.3 J21.5 J21.9 J22.5 J22.11 J22.12 J22.13 J22.14 J22.15 J22.16 J23.6 J23.11 J23.12 J24.2 J24.3 J25.2 J25.3 J25.4 J25.5 J26.10 J27.10 J29.3 J29.4 J29.5 J29.6 J29.8 J29.9 J29.10 J29.11 J29.12 J29.13 J29.14 J29.15 J29.16 J29.17 J29.18 J29.19 J29.20 J29.21 J29.22 J29.25 J29.28 J29.31 J29.34 J29.38 J29.40 J30.6 J30.9 J30.12 J30.15 J31.4 J31.7 J31.10 J31.13 J32.2 J32.5 J32.8 J32.11 J32.17 J35.1 J36.1 J37.10 J39.8 J40.8 J41.11 J41.14 J41.17 J41.19 J41.20 J47.10 J50.4 J63.A1 J63.A12 J63.B1 J63.B12 J64.3 L24.1 L25.1 Q1.S Q2.D Q6.S Q7.S Q8.S Q9.S Q10.S Q11.S Q12.S R11.2 R14.2 R21.1 R31.1 R32.1 R59.1 R60.1 R67.1 R78.1 R79.1 R83.1 R95.1 R96.1 R100.1 R102.1 R106.1 R111.1 R114.1 R116.1 R117.2 R124.2 R125.1 R126.1 R144.2 R145.1 R146.1 R147.1 R148.1 R150.1 R157.1 R158.1 R159.1 R194.1 R198.1 R200.2 R202.1 R204.2 R208.1 R209.1 R218.2 R229.1 SW1.1 SW1.2 SW2.1 SW2.2 SWD1.3 U1.5 U1.11 U3.2 U4.4 U4.5 U4.6 U4.7 U4.9 U5.2 U5.5 U6.1 U6.12 U7.A4 U7.A5 U7.A25 U7.AF2 U7.AF3 U7.AF4 U7.AF5 U7.AF6 U7.AF7 U7.AF8 U7.AF9 U7.AF10 U7.AF11 U7.AF12 U7.AF13 U7.AF14 U7.AF15 U7.AF16 U7.AF17 U7.AF18 U7.AF19 U7.AF20 U7.AF21 U7.AF22 U7.AF23 U7.AF24 U7.AF25 U7.AF26 U7.AF27 U7.AF28 U7.AG2 U7.AG3 U7.AG4 U7.AG5 U7.AG6 U7.AG7 U7.AG16 U7.AG23 U7.AH4 U7.AH5 U7.AH8 U7.AH14 U7.AH17 U7.AH19 U7.AH21 U7.AJ1 U7.AJ5 U7.AJ6 U7.AJ7 U7.AJ9 U7.AJ14 U7.AJ17 U7.AJ20 U7.AJ26 U7.AK5 U7.AK6 U7.AK7 U7.AK8 U7.AK9 U7.AK10 U7.AK11 U7.AK12 U7.AK13 U7.AK14 U7.AK17 U7.AK20 U7.AK23 U7.AL4 U7.AL5 U7.AL9 U7.AL10 U7.AL11 U7.AL14 U7.AL17 U7.AM5 U7.AM6 U7.AM12 U7.AM15 U7.AM18 U7.AM20 U7.AN8 U7.AN11 U7.AN14 U7.AN17 U7.AN20 U7.B3 U7.B4 U7.B5 U7.B8 U7.B11 U7.B14 U7.B15 U7.B18 U7.B25 U7.B26 U7.B27 U7.C2 U7.C4 U7.C5 U7.C12 U7.C13 U7.C14 U7.C15 U7.C16 U7.C25 U7.C26 U7.C28 U7.D2 U7.D3 U7.D4 U7.D16 U7.D24 U7.D26 U7.D27 U7.D28 U7.D29 U7.E1 U7.E2 U7.E6 U7.E8 U7.E15 U7.F15 U7.F16 U7.F21 U7.F22 U7.G5 U7.G8 U7.G11 U7.G16 U7.G19 U7.G22 U7.G25 U7.G26 U7.G27 U7.G28 U7.H2 U7.H3 U7.H4 U7.H5 U7.H6 U7.H7 U7.H8 U7.H9 U7.H10 U7.H11 U7.H12 U7.H13 U7.H14 U7.H15 U7.H16 U7.H17 U7.H18 U7.H19 U7.H20 U7.H21 U7.H22 U7.H23 U7.H24 U7.H25 U7.H26 U7.H27 U7.H28 U7.H29 U7.M1 U7.T1 U7.Y29 U8.2 U9.3 U9.13 U9.16 U9.17 U9.25 U10.2 U11.2 U12.2 U13.57 U14.57 U15.9 U16.9 U17.6 U17.17 U17.23 U17.29 U17.32 U17.36 U17.42 U17.49 U17.51 U17.56 U17.65 U18.3 U18.5 U18.8 U18.11 U18.14 U18.25 U18.28 U18.31 U18.34 U18.36 U19.6 U20.11 U20.37 U21.3 U22.3 U23.17 U24.3 U24.7 U25.3 U25.7 U26.10 U27.3 U27.16 U27.21 U27.30 U27.34 U27.47 U27.57 U29.2 U29.9 U30.5 U31.5 U32.B3 U32.C3 U32.D3 X1.2 X1.4 X2.2 X2.4 X3.2 X3.4 X4.2 X4.4 | length 595.8
  1-TOP w0.15: U27.16@-60.17,30.2 v1(-59.3,30.2) ; U27.21@-60.17,32.2 v1(-59.3,32.2)
  1-TOP w0.168: U21.3@104.1,-43.15 v1(104.1,-42.5) ; U22.3@106.1,-43.15 v1(106.1,-42.5)
  1-TOP w0.2: Q8.S@-83.1,-48.71 v1(-83.1,-47.9) ; Q7.S@-81,-48.71 v1(-81,-47.9) ; R59.1@-78.82,43.3 v1(-78.2,43.3) ; R60.1@-78.82,46.3 v1(-78.2,46.3) ; C57.1@-78.6,-45.34 v1(-78.6,-44.7) ; v1(-77.9,-32.44) C76.1@-77.9,-31.8 ; v1(-77.84,-27.3) C66.1@-77.2,-27.3 ; C56.1@-77.4,-45.34 v1(-77.4,-44.7) ; v1(-77.3,-43.1) -76.76,-43.1 C67.2@-76.56,-43.3 ; v1(-77.3,-34.2) C77.1@-76.66,-34.2 ; v1(-77.3,-32.9) C72.1@-76.66,-32.9 ; C55.1@-76.2,-45.34 v1(-76.2,-44.7) ; C54.1@-75,-45.34 v1(-75,-44.7) ; v1(-72.44,33.9) C180.1@-71.8,33.9 ; v1(-71.92,-42.74) -71.9,-42.72 C73.1@-71.9,-42.26 ; v1(-71.8,28.2) C173.1@-71.16,28.2 ; v1(-71.8,30.4) C178.2@-71.16,30.4 ; v1(-71.8,31.5) C177.2@-71.16,31.5 ; v1(-71.8,32.6) C181.1@-71.16,32.6 ; v1(-71.54,35.04) C158.2@-70.9,35.04 ; C65.1@-71.5,-28.74 v1(-71.5,-28) ; U13.57@-71.4,-36.45 U13.57@-70.15,-35.2 ; v1(-70.92,-42.74) -70.9,-42.72 C61.1@-70.9,-42.26 ; C64.1@-69.9,-28.74 v1(-69.9,-28) ; v1(-68.42,-42.74) -68.4,-42.72 C60.1@-68.4,-42.26 ; v1(-68.1,33.6) -67.9,33.4 U27.47@-67.03,33.4 -66.1,33.4 ; v1(-67.42,-42.74) -67.4,-42.72 C74.1@-67.4,-42.26 ; C161.2@-67.1,38.86 v1(-67.1,39.5) ; C78.1@-66,-28.14 v1(-66,-27.4) ; C165.2@-65.9,38.86 v1(-65.9,39.5) ; v1(-65.6,27.8) -65.4,28 U27.3@-65.4,28.97 -65.4,29.9 ; R106.1@-65.5,-41.08 v1(-64.86,-41.08) ; v1(-65.1,-27.2) -64.3,-27.2 C79.1@-64,-26.9 ; C166.2@-64.7,38.86 v1(-64.7,39.5) ; v1(-63.8,25.1) C171.1@-63.8,25.74 ; C79.1@-63.6,-27.2 v1(-62.86,-27.2) ; v2(-63.6,32.4) -61.4,30.2 U27.16@-60.17,30.2 ; C170.2@-63.5,38.86 v1(-63.5,39.5) ; C58.1@-63.34,-34.9 v1(-62.6,-34.9) ; C75.1@-63.34,-33.7 v1(-62.6,-33.7) ; C71.1@-63.04,-40.2 v1(-62.4,-40.2) ; -63,34.9 U27.34@-63,35.83 -63,37 ; v1(-62.36,39.56) C164.2@-62.36,40.2 ; X1.4@-61.45,-38.975 -61.175,-38.7 v1(-60.1,-38.7) C68.1@-60.1,-37.96 ; -61.4,35 U27.30@-61.4,35.83 -61.4,36.3 -61.1,36.6 v1(-60.5,36.6) ; C62.1@-61.2,-41.7 -61.2,-42.1 v1(-60.2,-42.1) ; -61.1,32.2 U27.21@-60.17,32.2 ; C69.1@-60.64,-35.4 -60.5,-35.54 -60.5,-36 v1(-60.4,-36.1) ; v1(-60.6,-49.5) Q10.S@-59.79,-49.5 ; v1(-60.6,-47.4) Q9.S@-59.79,-47.4 ; C70.1@-59.8,-33.5 v1(-59.8,-32.86) ; v1(-59.8,-31.64) C59.1@-59.8,-31 ; v1(-59.34,-38.4) R111.1@-58.7,-38.4 ; v1(-59.24,39.56) C168.2@-59.24,40.2 ; v1(-58.84,-37.2) C90.1@-58.2,-37.2 ; v1(-58.8,-26.1) -58.2,-26.1 C93.1@-57.9,-25.8 ; v1(-58.4,-34) C104.1@-57.76,-34 C104.1@-57.56,-34 ; v1(-58.4,-32.8) C99.1@-57.76,-32.8 C99.1@-57.56,-32.8 ; C103.1@-58.4,-30.7 v1(-58.4,-30.06) ; v1(-58.2,29.4) C184.2@-58.2,30.14 ; C179.1@-57.84,37.4 v1(-57.2,37.4) ; C174.1@-57.84,38.6 v1(-57.2,38.6) ; C94.2@-57.76,-43.7 -57.7,-43.76 v1(-57.7,-44.5) ; v1(-57.59,-27.35) C91.1@-56.95,-27.35 ; C84.1@-57.1,-45.34 C83.1@-55.9,-45.34 ; v1(-57.1,29.4) C183.2@-57.1,30.14 ; C176.2@-57.04,34.1 v1(-56.3,34.1) ; v1(-55.9,-44.7) C83.1@-55.9,-45.34 ; v1(-55.5,29.6) v1@-55.5,29.64 ; v1(-54.94,35.86) C175.1@-54.3,35.86 ; v1(-54.7,-44.7) C82.1@-54.7,-45.34 ; C81.1@-53.5,-45.34 C82.1@-54.7,-45.34 ; v1(-53,-43) C100.1@-53,-42.26 ; U14.57@-52.45,-36.45 v1(-51.8,-35.8) U14.57@-51.2,-35.2 ; v1(-52,-43) C88.1@-52,-42.26 ; C92.1@-50.9,-28.74 v1(-50.9,-28) ; v1(-50.79,57.5) D10.1@-50.15,57.5 ; v1(-49.4,-42.9) C87.1@-49.4,-42.26 ; v1(-48.45,-42.9) C101.1@-48.45,-42.26 ; D9.1@-47.25,57.5 v1(-46.6,57.5) ; C105.1@-46.9,-28.44 v1(-46.9,-27.8) ; R114.1@-46.4,-40.88 v1(-45.76,-40.88) ; v1(-46,-27.5) -45.1,-27.5 C106.1@-44.9,-27.3 ; v1(-45.9,-36.5) -45.15,-36.5 X2.2@-44.75,-36.9 ; v1(-45,43.6) -44.27,43.6 C33.1@-44.1,43.77 ; v1(-44.9,56.4) C35.1@-44.9,56.9 ; v1(-44.6,53.8) C30.1@-43.96,53.8 ; v1(-44.6,54.8) -44.06,54.8 C37.1@-43.96,54.9 ; v1(-44.6,55.8) C36.1@-43.96,55.8 ; C106.1@-44.4,-27.5 v1(-43.8,-27.5) ; C85.1@-44.24,-34.9 v1(-43.6,-34.9) ; C102.1@-44.24,-33.9 v1(-43.6,-33.9) ; R79.1@-44.2,45.5 v1(-44.2,46.14) ; C98.1@-43.84,-40.2 v1(-43.2,-40.2) ; v1(-43.54,51.1) U9.3@-42.9,51.1 ; v1(-42.3,-39.84) X2.4@-42.3,-39.1 ; C96.1@-41.94,-35.3 v1(-41.3,-35.3) ; C89.1@-41.4,-41.8 v1(-40.76,-41.8) ; C86.1@-41.1,-31.1 v1(-40.36,-31.1) ; C86.1@-41.1,-30.2 v1(-40.36,-30.2) ; C97.1@-40.7,-34.3 v1(-39.96,-34.3) ; C97.1@-40.7,-33.5 v1(-39.96,-33.5) ; v1(-40.5,-38.3) C95.1@-40.5,-37.66 ; U9.16@-39.1,51.1 -38.6,51.1 v2(-38.3,51.4) -38.5,51.6 U9.17@-39.1,51.6 ; C31.2@-38.74,47.9 -38.7,47.94 v1(-38.7,48.7) ; v1(-37.1,42.4) -37.1,43.1 C34.2@-37.1,43.14 ; C27.1@-36,43.14 -36,43.1 -36,42.5 v1(-35.9,42.4) ; C28.1@-35.04,43.1 C28.1@-35,43.14 v1(-35,42.5) ; v1(-34.2,-64.9) -33.65,-64.9 J23.11@-33.1,-65.45 ; v1(-33.9,41.46) C26.1@-33.9,42.1 ; v1(-33.1,41.46) C26.1@-33.1,42.1 ; v1(-30.1,-64.125) J23.6@-30.1,-63.025 v1(-30.1,-61.925) ; v1(-29.4,42.8) -29.4,44.708 J12.10@-29.34,44.768 ; D28.2@-27.1,-47.15 v1(-27.1,-46.5) ; v1(-26.8,42.8) J12.6@-26.8,43.768 ; D24.2@-25.8,-47.15 v1(-25.8,-46.5) ; J12.4@-25.53,43.768 -25.53,42.83 v1(-25.5,42.8) ; D25.2@-24.5,-47.15 v1(-24.5,-46.5) ; D27.2@-23.2,-47.15 v1(-23.2,-46.5) ; D29.2@-21.9,-47.15 v1(-21.9,-46.5) ; v1(-20.955,-14.605) U7.A4@-20.32,-13.97 ; v1(-20.955,-13.335) U7.A5@-20.32,-12.7 ; D26.2@-20.6,-47.15 v1(-20.6,-46.5) ; U7.A25@-20.32,12.7 v1(-19.685,13.335) U7.B25@-19.05,12.7 ; J23.12@-20,-65.7 v1(-20,-64.96) ; v1(-19.685,-15.875) U7.B3@-19.05,-15.24 ; v1(-19.685,-14.605) U7.B4@-19.05,-13.97 ; v1(-19.685,-13.335) U7.B5@-19.05,-12.7 ; v1(-19.685,-9.525) U7.B8@-19.05,-8.89 ; v1(-19.685,-4.445) U7.B11@-19.05,-5.08 ; v1(-19.685,-1.905) U7.B14@-19.05,-1.27 ; v1(-19.685,-0.635) U7.B15@-19.05,0 ; v1(-19.685,3.175) U7.B18@-19.05,3.81 ; v1(-19.685,14.605) U7.B26@-19.05,13.97 ; v1(-19.685,15.875) U7.B27@-19.05,15.24 ; D30.2@-19.3,-47.15 v1(-19.3,-46.5) ; v1(-18.415,-17.145) U7.C2@-17.78,-16.51 ; v1(-18.415,-14.605) U7.C4@-17.78,-13.97 ; v1(-18.415,-13.335) U7.C5@-17.78,-12.7 ; v1(-18.415,-4.445) U7.C12@-17.78,-3.81 ; v1(-18.415,-3.175) U7.C13@-17.78,-2.54 ; v1(-18.415,-1.905) U7.C14@-17.78,-1.27 ; v1(-18.415,-0.635) U7.C15@-17.78,0 ; v1(-18.415,13.335) U7.C25@-17.78,12.7 ; v1(-18.415,14.605) U7.C26@-17.78,13.97 ; v1(-18.415,15.875) U7.C28@-17.78,16.51 ; U7.C16@-17.78,1.27 v1(-17.145,1.905) ; C48.1@-17.64,-58.7 v1(-16.92,-58.7) ; C49.1@-17.64,-57.5 v1(-16.92,-57.5) ; D1.2@-17.45,-59.7 v1(-16.73,-59.7) ; J20.9@-17.34,48.832 -17.3,48.872 v1(-17.3,50.8) ; v1(-17.145,-17.145) U7.D2@-16.51,-16.51 ; v1(-17.145,-15.875) U7.D3@-16.51,-15.24 ; v1(-17.145,-14.605) U7.D4@-16.51,-13.97 ; v1(-17.145,14.605) U7.D26@-16.51,13.97 ; v1(-17.145,15.875) U7.D28@-16.51,16.51 ; v1(-17.145,18.415) U7.D29@-16.51,17.78 ; U7.D16@-16.51,1.27 v1(-15.875,0.635) ; U7.D24@-16.51,11.43 v1(-15.875,12.065) ; U7.D27@-16.51,15.24 v1(-15.875,14.605) ; v1(-16.1,38.5) SWD1.3@-16.1,39.465 ; v1(-15.875,-18.415) U7.E1@-15.24,-17.78 ; v1(-15.875,-17.145) U7.E2@-15.24,-16.51 ; v1(-15.875,-12.065) U7.E6@-15.24,-11.43 ; v1(-15.875,-9.525) U7.E8@-15.24,-8.89 ; U7.E15@-15.24,0 v1(-14.605,0.635) ; J20.5@-14.8,47.796 J20.5@-14.8,48.832 v1(-14.8,50.7) ; v1(-14.605,-0.635) U7.F15@-13.97,0 ; v1(-14.605,1.905) U7.F16@-13.97,1.27 ; v1(-14.605,9.525) U7.F22@-13.97,8.89 ; U7.F21@-13.97,7.62 v1(-13.335,8.255) ; J20.3@-13.53,48.832 -13.5,48.862 v1(-13.5,50.8) ; v1(-13.335,-13.335) U7.G5@-12.7,-12.7 ; v1(-13.335,-9.525) U7.G8@-12.7,-8.89 ; v1(-13.335,-5.715) U7.G11@-12.7,-5.08 ; v1(-13.335,1.905) U7.G16@-12.7,1.27 ; v1(-13.335,5.715) U7.G19@-12.7,5.08 ; v1(-13.335,9.525) U7.G22@-12.7,8.89 ; v1(-13.335,13.335) U7.G25@-12.7,12.7 ; v1(-13.335,14.605) U7.G26@-12.7,13.97 ; v1(-13.335,15.875) U7.G27@-12.7,15.24 ; v1(-13.335,17.145) U7.G28@-12.7,16.51 ; v1(-12.065,-17.145) U7.H2@-11.43,-16.51 ; v1(-12.065,-15.875) U7.H3@-11.43,-15.24 ; v1(-12.065,-14.605) U7.H4@-11.43,-13.97 ; v1(-12.065,-13.335) U7.H5@-11.43,-12.7 ; v1(-12.065,-12.065) U7.H6@-11.43,-11.43 ; v1(-12.065,-10.795) U7.H7@-11.43,-10.16 ; v1(-12.065,-9.525) U7.H8@-11.43,-8.89 ; v1(-12.065,-8.255) U7.H9@-11.43,-7.62 ; v1(-12.065,-6.985) U7.H10@-11.43,-6.35 ; v1(-12.065,-5.715) U7.H11@-11.43,-5.08 ; v1(-12.065,-4.445) U7.H12@-11.43,-3.81 ; v1(-12.065,-3.175) U7.H13@-11.43,-2.54 ; v1(-12.065,-1.905) U7.H14@-11.43,-1.27 ; v1(-12.065,-0.635) U7.H15@-11.43,0 ; v1(-12.065,0.635) U7.H16@-11.43,1.27 ; v1(-12.065,3.175) U7.H17@-11.43,2.54 ; v1(-12.065,4.445) U7.H18@-11.43,3.81 ; v1(-12.065,5.715) U7.H19@-11.43,5.08 ; v1(-12.065,6.985) U7.H20@-11.43,6.35 ; v1(-12.065,8.255) U7.H21@-11.43,7.62 ; v1(-12.065,9.525) U7.H22@-11.43,8.89 ; v1(-12.065,10.795) U7.H23@-11.43,10.16 ; v1(-12.065,12.065) U7.H24@-11.43,11.43 ; v1(-12.065,13.335) U7.H25@-11.43,12.7 ; v1(-12.065,14.605) U7.H26@-11.43,13.97 ; v1(-12.065,15.875) U7.H27@-11.43,15.24 ; v1(-12.065,17.145) U7.H28@-11.43,16.51 ; U7.H29@-11.43,17.78 v1(-10.795,18.415) ; v1(-6.4,-18.5) -6.4,-17.83 U7.M1@-6.35,-17.78 ; J21.9@-5.34,48.832 -5.3,48.872 v1(-5.3,50.8) ; J21.5@-2.8,47.832 J21.5@-2.8,48.832 v1(-2.8,50.8) ; J21.3@-1.53,48.832 -1.5,48.862 v1(-1.5,50.8) ; v1(-1.3,-18.5) -1.3,-17.81 U7.T1@-1.27,-17.78 ; v1(2.4,49.2) R67.1@3.1,49.2 ; U7.Y29@3.81,17.78 4.4,18.37 v1(4.4,18.4) ; v1(4.2,50) D4.1@4.9,50 ; D3.1@8.35,50 v1(9.05,50) ; R78.1@11.1,49.18 v1(11.1,49.88) ; U7.AF2@11.43,-16.51 v1(12.065,-17.145) ; U7.AF3@11.43,-15.24 v1(12.065,-15.875) ; U7.AF4@11.43,-13.97 v1(12.065,-14.605) ; U7.AF5@11.43,-12.7 v1(12.065,-13.335) ; U7.AF6@11.43,-11.43 v1(12.065,-12.065) ; U7.AF7@11.43,-10.16 v1(12.065,-10.795) ; U7.AF8@11.43,-8.89 v1(12.065,-9.525) ; U7.AF9@11.43,-7.62 v1(12.065,-8.255) ; U7.AF10@11.43,-6.35 v1(12.065,-6.985) ; U7.AF11@11.43,-5.08 v1(12.065,-5.715) ; U7.AF12@11.43,-3.81 v1(12.065,-4.445) ; U7.AF13@11.43,-2.54 v1(12.065,-3.175) ; U7.AF14@11.43,-1.27 v1(12.065,-1.905) ; U7.AF15@11.43,0 v1(12.065,-0.635) ; U7.AF16@11.43,1.27 v1(12.065,1.905) ; U7.AF17@11.43,2.54 v1(12.065,3.175) ; U7.AF18@11.43,3.81 v1(12.065,4.445) ; U7.AF19@11.43,5.08 v1(12.065,5.715) ; U7.AF20@11.43,6.35 v1(12.065,6.985) ; U7.AF21@11.43,7.62 v1(12.065,8.255) ; U7.AF22@11.43,8.89 v1(12.065,9.525) ; U7.AF23@11.43,10.16 v1(12.065,10.795) ; U7.AF24@11.43,11.43 v1(12.065,12.065) ; U7.AF25@11.43,12.7 v1(12.065,13.335) ; U7.AF26@11.43,13.97 v1(12.065,14.605) ; U7.AF27@11.43,15.24 v1(12.065,15.875) ; U7.AF28@11.43,16.51 v1(12.065,17.145) ; v1(12.1,50) D8.1@12.786,50 ; U7.AG2@12.7,-16.51 v1(13.335,-17.145) ; U7.AG3@12.7,-15.24 v1(13.335,-15.875) ; U7.AG4@12.7,-13.97 v1(13.335,-14.605) ; U7.AG5@12.7,-12.7 v1(13.335,-13.335) ; U7.AG6@12.7,-11.43 v1(13.335,-12.065) ; U7.AG7@12.7,-10.16 v1(13.335,-10.795) ; U7.AG16@12.7,1.27 v1(13.335,1.905) ; U7.AG23@12.7,10.16 v1(13.335,10.795) ; v1(13.335,5.715) U7.AH19@13.97,5.08 ; R218.2@13.6,-59.72 v1(13.6,-59.1) ; U7.AH4@13.97,-13.97 v1(14.605,-14.605) ; U7.AH5@13.97,-12.7 v1(14.605,-13.335) ; U7.AH8@13.97,-8.89 v1(14.605,-9.525) ; U7.AH14@13.97,-1.27 v1(14.605,-1.905) ; U7.AH17@13.97,2.54 v1(14.605,1.905) ; U7.AH21@13.97,7.62 v1(14.605,8.255) ; v1(14.605,13.335) U7.AJ26@15.24,13.97 ; v1(14.9,-53.1) 16.2,-53.1 16.4,-53.3 U15.9@17.105,-53.3 ; U7.AJ1@15.24,-17.78 v1(15.875,-18.415) ; U7.AJ5@15.24,-12.7 v1(15.875,-13.335) ; U7.AJ6@15.24,-11.43 v1(15.875,-12.065) ; U7.AJ7@15.24,-10.16 v1(15.875,-10.795) ; U7.AJ9@15.24,-7.62 v1(15.875,-8.255) ; U7.AJ14@15.24,-1.27 v1(15.875,-1.905) ; U7.AJ17@15.24,2.54 v1(15.875,3.175) ; U7.AJ20@15.24,6.35 v1(15.875,6.985) ; D7.1@16.173,50 v1(16.9,50) ; U7.AK5@16.51,-12.7 v1(17.145,-13.335) ; U7.AK6@16.51,-11.43 v1(17.145,-12.065) ; U7.AK7@16.51,-10.16 v1(17.145,-10.795) ; U7.AK8@16.51,-8.89 v1(17.145,-9.525) ; U7.AK9@16.51,-7.62 v1(17.145,-8.255) ; U7.AK10@16.51,-6.35 v1(17.145,-6.985) ; U7.AK11@16.51,-5.08 v1(17.145,-5.715) ; U7.AK12@16.51,-3.81 v1(17.145,-4.445) ; U7.AK13@16.51,-2.54 v1(17.145,-3.175) ; U7.AK14@16.51,-1.27 v1(17.145,-1.905) ; U7.AK17@16.51,2.54 v1(17.145,3.175) ; U7.AK20@16.51,6.35 v1(17.145,6.985) ; U7.AK23@16.51,10.16 v1(17.145,10.795) ; U7.AL4@17.78,-13.97 v1(18.415,-14.605) ; U7.AL5@17.78,-12.7 v1(18.415,-13.335) ; U7.AL9@17.78,-7.62 v1(18.415,-8.255) ; U7.AL10@17.78,-6.35 v1(18.415,-6.985) ; U7.AL11@17.78,-5.08 v1(18.415,-5.715) ; U7.AL14@17.78,-1.27 v1(18.415,-0.635) ; U7.AL17@17.78,2.54 v1(18.415,3.175) ; J29.4@17.85,-62.85 v1(17.85,-62) ; J29.6@18.85,-62.85 v1(18.85,-62) ; U7.AM5@19.05,-12.7 v1(19.685,-13.335) ; U7.AM6@19.05,-11.43 v1(19.685,-12.065) ; U7.AM12@19.05,-3.81 v1(19.685,-4.445) ; U7.AM15@19.05,0 v1(19.685,0.635) ; U7.AM18@19.05,3.81 v1(19.685,3.175) ; U7.AM20@19.05,6.35 v1(19.685,6.985) ; C194.1@19.4,49.16 v1(19.4,49.9) ; J29.8@19.85,-62.85 v1(19.85,-62) ; U7.AN8@20.32,-8.89 v1(21.218,-8.89) ; U7.AN11@20.32,-5.08 v1(20.955,-5.715) ; U7.AN14@20.32,-1.27 v1(20.955,-1.905) ; U7.AN17@20.32,2.54 v1(21.218,2.54) ; U7.AN20@20.32,6.35 v1(20.955,5.715) ; v1(20.5,49.9) D20.1@21.05,49.9 ; J29.10@20.85,-62.85 v1(20.85,-62) ; J29.12@21.85,-62.85 v1(21.85,-62) ; J29.14@22.85,-62.85 v1(22.85,-62) ; J29.16@23.85,-62.85 v1(23.85,-62) ; v1(23.9,-51.7) 24.54,-51.7 C109.2@24.6,-51.64 24.66,-51.7 25.2,-51.7 25.4,-51.9 U16.9@26.205,-51.9 ; D19.1@24.75,49.9 v1(25.3,49.9) ; J29.18@24.85,-62.85 v1(24.85,-62) ; J29.20@25.85,-62.85 v1(25.85,-62) ; v1(26.7,45.7) SW1.1@27.4,45.7 ; J29.25@28.35,-62.85 v1(28.35,-62) ; 29.85,-64.2 J29.28@29.85,-62.85 ; J29.31@31.35,-62.85 v1(31.35,-62) ; J29.34@32.85,-62.85 v1(32.85,-62) ; C190.1@33.2,-56.3 C190.1@34,-56.3 ; SW1.2@33.2,45.7 SW1.2@33.7,45.7 ; SW1.2@34.3,45.727 34.427,45.6 34.7,45.6 34.3,46 v1(34.3,46.8) ; J29.38@34.85,-62.85 v1(34.85,-62) ; J29.40@35.85,-62.85 v1(35.85,-62) ; U29.9@37.2,-57.7 37.25,-57.65 U29.2@37.25,-56.765 ; SW2.2@40.3,41.9 v1(40.3,42.6) ; v1(42.685,-53.3) R126.1@43.32,-53.3 ; v1(42.7,-33.5) C126.1@43.345,-33.5 ; v1(42.705,-52.2) C119.1@43.34,-52.2 ; v1(42.8,-46.6) C115.1@43.54,-46.6 ; v1(42.97,-38.48) R124.2@43.605,-38.48 ; v1(43.2,-29.9) C125.1@43.845,-29.9 ; J32.17@45.2,-55.8 v1@45.2,-53.8 ; v1(45.41,-40.7) C120.1@46.045,-40.7 ; v1(45.41,-39.7) C121.1@46.045,-39.7 ; v1(45.5,-38.4) 45.505,-38.405 U17.17@46.7,-38.405 ; U17.6@45.995,-33.7 48.7,-33.7 v1(49.7,-34.7) 49.9,-34.5 U17.56@49.9,-30.995 ; v1(46.2,40.8) SW2.1@46.2,41.709 ; v1(47.4,-8.43) C40.2@47.4,-7.6 ; C40.2@47.4,-7.2 v1(47.4,-6.37) ; J32.11@48.2,-55.8 U18.25@48.2,-52.3 U18.14@48.2,-46.5 v1(48.2,-45.4) ; C123.1@48.305,-28.34 C123.1@48.325,-28.32 ; v1(48.4,-8.43) C40.2@48.4,-7.6 ; C40.2@48.4,-7.2 v1(48.4,-6.37) ; v1(49,-39.8) 49.1,-39.7 U17.23@49.1,-38.405 ; v1(49.3,-8.9) C44.1@50.04,-8.9 ; C116.1@49.445,-27.3 48.5,-27.3 v2(48.4,-27.4) 48.4,-28.245 C123.1@48.325,-28.32 ; R125.1@49.505,-28.32 C123.1@48.325,-28.32 ; J32.8@49.7,-55.8 U18.11@49.7,-46.5 v1(49.7,-45.4) ; X3.2@50,-23.6 v1(50,-22.965) ; v1(50.505,-42.095) C128.1@50.505,-41.46 ; J32.5@51.2,-55.8 U18.8@51.2,-46.5 v1(51.2,-45.4) ; U17.29@51.5,-38.405 51.5,-37.5 ; R209.1@51.5,43.98 v1(51.5,44.68) ; U17.65@51.9,-32.3 U17.51@51.9,-30.995 ; C114.1@52.365,-27.3 v1(53.4,-27.3) 53.405,-27.305 C135.1@53.405,-28.34 C136.1@52.405,-28.34 ; J32.2@52.7,-55.8 U18.5@52.7,-46.5 v1(52.7,-45.4) ; U17.32@52.7,-38.405 52.7,-38.9 v1(53,-39.2) ; U17.49@52.7,-30.8 v1(53.335,-30.8) ; X3.4@53.1,-25.9 v1(53.735,-25.9) ; U17.36@53.405,-36.5 53.9,-36.5 v1(54.4,-36) ; U17.42@53.405,-34.1 54,-34.1 v1(54.3,-33.8) ; U18.36@53.7,-52.3 U18.3@53.7,-46.5 v1(53.7,-45.4) ; C113.1@54.2,-43.54 v1(54.2,-42.8) ; C134.1@54.405,-28.34 v1(54.405,-27.705) ; v1(55.4,-27.7) 55.405,-27.705 C133.1@55.405,-28.38 ; v1(55.5,-3.8) 55.52,-3.78 C39.2@56.2,-3.78 ; v1(56.2,-4.4) C39.2@56.2,-3.78 ; C39.2@56.24,-3.8 C39.2@56.22,-3.78 ; C122.1@56.265,-40.5 v1(56.985,-40.5) ; C127.1@56.265,-39.4 v1(56.985,-39.4) ; C129.1@56.265,-38.3 v1(56.985,-38.3) ; C130.1@56.265,-37.3 v1(56.985,-37.3) ; C131.1@56.265,-34.5 v1(57,-34.5) ; C132.1@56.265,-33.5 56.9,-33.5 v1(57,-33.5) ; C124.1@56.96,-51.9 v1(57.595,-51.9) ; C118.1@56.96,-50.9 v1(57.595,-50.9) ; C111.1@57.26,-46 v1(57.895,-46) ; C112.1@57.266,-46.98 v1(57.901,-46.98) ; v1(57.99,-6.2) R83.1@58.73,-6.2 ; v1(60.6,-60) 61.27,-60 J22.15@61.29,-60.02 ; v1(60.6,-53.9) 61.25,-53.9 J22.14@61.29,-53.86 ; v1(60.7,-65) 61.1,-65 61.45,-65.35 J22.16@61.45,-66.37 ; R208.1@62.2,44.1 v1(62.2,44.7) ; v1(63.2,-5.24) C38.1@63.2,-4.6 ; v1(67.2,-20.8) C46.1@67.84,-20.8 ; D14.1@67.7,-49.45 v1(67.7,-48.815) ; D13.1@68.9,-49.45 v1(68.9,-48.815) ; D11.1@70.1,-49.45 v1(70.1,-48.815) ; C43.1@70.76,-20.8 v1(71.4,-20.8) ; D12.1@71.3,-49.45 v1(71.3,-48.815) ; C42.2@72.7,-22.9 v1(73.335,-22.9) ; C42.2@72.7,-22 v1(73.335,-22) ; C53.1@73.9,-50.8 v1(74.535,-50.8) ; C52.1@73.9,-49.8 v1(74.535,-49.8) ; Q11.S@74.85,37.75 75,37.9 v1(75.6,37.9) ; C51.1@75.2,-48.4 v1(75.835,-48.4) ; C50.1@75.2,-46.6 v1(75.835,-46.6) ; J22.11@75.35,-66.37 75.35,-65.25 75.6,-65 v1(76.1,-65) ; J22.12@75.51,-60 v1(76.1,-60) ; J22.13@75.51,-54.16 75.55,-54.2 76.015,-54.2 76.029,-54.186 76.043,-54.2 v1(76.1,-54.2) ; v1(77.5,-48.6) 77.99,-48.6 Q12.S@78.1,-48.71 ; v1(77.5,-47.4) R202.1@78.12,-47.4 ; v1(77.8,43.8) R32.1@78.6,43.8 ; v1(79.08,-54.9) R150.1@79.82,-54.9 ; v1(79.1,-57.1) C198.1@79.84,-57.1 ; v1(79.1,-56) C197.1@79.84,-56 ; v1(80.2,35.78) C24.1@80.2,36.4 ; v1(80.4,-43.5) C196.1@81.1,-43.5 ; v1(82,37.9) 82,38 U6.12@82,38.65 ; C25.1@82,43.66 v1(82,44.4) ; v1(82.7,38.5) 82.7,39 U6.1@82.8,39.1 ; U32.B3@82.75,-53.85 U32.C3@83.25,-53.85 U32.D3@83.75,-53.85 84.25,-53.85 v2(84.6,-53.5) ; C195.1@83,-43.7 v1(83,-43.08) ; R31.1@84.1,43.68 84.2,43.78 v1(84.2,44.4) ; C187.1@84.26,-50.3 v1(85,-50.3) ; C201.1@85.16,-51.8 v1(85.9,-51.8) ; v1(85.2,38.68) C15.1@85.2,39.3 ; U4.6@85.35,50.35 84.85,50.35 v1(84.8,50.4) ; U4.7@85.65,49.85 84.8,49.85 v1(84.8,50.4) ; U4.5@85.65,50.85 84.9,50.85 84.8,50.75 v1(84.8,50.4) ; C199.1@85.7,-53.44 v1(85.7,-52.7) ; v1(85.9,-16.77) U25.3@85.9,-16.15 ; C10.2@86.56,48.4 v1(87.2,48.4) ; v1(86.6,37.98) C14.1@86.6,38.6 ; C188.1@86.66,-47.8 v1(87.4,-47.8) ; C200.1@86.9,-53.44 v1(86.9,-52.7) ; C7.1@87.27,55.3 87.3,55.33 v1(87.3,56.2) ; v1(88.1,38.08) C13.1@88.1,38.7 ; U4.4@88.55,50.85 89.25,50.85 v1(89.3,50.9) ; v1(89.7,27.3) C22.1@89.7,27.945 ; v1(90,-57) 90.15,-56.85 D16.8@90.15,-56.15 ; v1(90,-54.3) 90.15,-54.45 D16.3@90.15,-55.15 ; v1(90.9,26.5) C21.1@90.9,27.33 ; R21.1@91,55.4 v1(91.7,55.4) ; v1(91.4,25.3) C16.2@92,25.3 ; C147.1@92.7,-55.24 v1(92.7,-54.5) ; C16.2@93,25.3 v1(93.6,25.3) ; U3.2@93.8,53 v1(94.6,53) v1@94.64,52.96 ; U5.2@94.29,28.25 94.3,28.24 v1(94.3,27.7) ; v2(95.4,-7.1) C145.1@96.14,-7.1 ; C8.1@95.6,52.96 v1(95.6,53.8) ; v1(95.9,25.5) C12.1@95.9,26.14 ; C3.1@96.26,40.5 v1(96.96,40.5) ; C4.1@96.26,41.6 v1(97,41.6) ; C5.1@96.3,46 v1(97,46) ; v1(96.8,37.9) C2.2@96.8,38.5 ; v1(97.08,-38.9) X4.4@97.7,-38.9 ; v1(97.72,-40.1) C138.2@98.34,-40.1 ; C2.2@97.9,39 v1(98.6,39) ; v1(97.9,40.6) C1.1@97.9,41.3 ; C143.1@98,-43.44 v1(98,-42.82) ; v1(98,37.9) C2.2@98,38.5 ; U1.5@98.24,44.7 98.7,44.7 v1(99.3,45.3) ; v1(98.6,34.8) C157.1@98.6,35.54 ; C140.1@99,-43.44 v1(99,-42.82) ; C137.2@99.16,-35.1 v1(99.78,-35.1) 99.78,-36.32 X4.2@99.6,-36.5 ; v1(99.8,26.8) R159.1@99.8,27.42 ; D22.1@100.2,-46.076 100.2,-45.7 ; 100.2,-45.7 100.2,-45.6 v1(100.2,-45.4) ; v1(100.2,46.4) Q1.S@100.2,47.1 ; v1(100.68,-40.2) R145.1@101.3,-40.2 ; v1(101.3,26.8) R158.1@101.3,27.42 ; v1(101.4,46.6) R14.2@101.4,47.22 ; C142.1@101.5,-43.44 v1(101.5,-42.82) ; v1(101.6,-38.8) C155.1@102.34,-38.8 ; v1(101.72,-41.6) C148.1@102.34,-41.6 ; v1(101.78,-35) R144.2@102.4,-35 ; v1(101.82,-36) C153.1@102.44,-36 ; v1(102.4,39.8) Q6.S@102.4,40.7 ; C141.1@102.5,-43.44 v1(102.5,-42.82) ; v1(102.6,46.6) C6.2@102.6,47.24 ; v1(102.8,26.8) R157.1@102.8,27.42 ; v1(103.3,20.9) J37.10@103.3,22.85 ; D23.1@103.7,-46 v1(103.7,-45.4) ; v1(104,-32) C144.1@104.74,-32 ; R200.2@104.28,-1.6 v1(104.9,-1.6) ; C156.1@105.3,40.2 C156.1@105.34,40.2 v1(106.2,40.2) ; v1(105.7,29.2) 105.725,29.225 U26.10@105.725,30.4 ; R148.1@106.6,-31.92 v1(106.6,-31.3) ; R147.1@107.6,-31.92 v1(107.6,-31.3) ; v1(108.2,-44.18) C149.1@108.2,-43.56 ; C152.1@108.6,-31.9 v1(108.6,-31.28) ; L24.1@108.9,-45.5 v1(108.9,-44.88) ; R146.1@109.6,-31.92 v1(109.6,-31.3) ; L24.1@109.7,-45.5 v1(109.7,-44.88) ; U20.11@110.7,-39.1 v1(111.6,-39.1) ; L25.1@111.3,-45.5 v1(111.3,-44.88) ; L25.1@112.1,-45.5 v1(112.1,-44.88) ; C150.1@113.76,-39.6 v1(114.5,-39.6) ; C154.1@113.82,-37.8 v1(114.5,-37.8) ; C151.1@113.82,-36.8 v1(114.5,-36.8) ; R198.1@114.28,6.1 v1(114.9,6.1) ; v1(115.2,19) R194.1@115.2,19.62 ; v1(117.2,18.5) 118.2,18.5 C185.1@118.2,19.1 117.7,19.6 v1(117.2,19.6) ; R204.2@117.6,41.78 v1(117.6,42.5) ; R96.1@119.38,-41.5 v1(120,-41.5) ; R95.1@119.38,-38.5 v1(120,-38.5) ; v1(120.2,42) 120.2,41.35 Q2.D@120.25,41.3 ; C186.1@120.3,20.6 v1(120.3,21.5) ; R11.2@121.78,35.6 v1(122.5,35.6) ; C83.1@-55.9,-45.34 C82.1@-54.7,-45.34 ; C39.2@56.2,-3.78 C39.2@56.22,-3.78 ; C39.2@56.2,-3.78 C39.2@56.2,-3.76 C39.2@56.22,-3.78
  1-TOP w0.25: J13.B1@-38.45,55.735 v2(-38.45,56.65) ; v2(-38.4,53.12) J13.A12@-38.4,54.035 ; v2(-32.4,53.12) J13.A1@-32.4,54.035 ; J13.B12@-32.35,55.735 v2(-32.35,56.65) ; v2(87.85,-62.15) J63.B12@87.85,-61.235 ; J63.A1@87.9,-59.535 v2(87.9,-58.62) ; J63.A12@93.9,-59.535 v2(93.9,-58.4) ; v2(93.95,-62.15) J63.B1@93.95,-61.235
  1-TOP w0.3: v1(-81.275,38.9) J10.3@-81.275,40.375 v1(-81.275,41.85) ; v1(-78.325,38.9) J10.2@-78.325,40.375 v1(-78.325,41.85) ; v1(-78.1,-38.2) -77.4,-38.2 R102.1@-77.3,-38.3 ; v1(-77.52,-37) C63.1@-76.8,-37 ; J31.4@-10.825,-61.2 v2(-10.825,-59.85) ; J31.7@-7.075,-61.2 v2(-7.075,-59.85) ; J31.10@-3.325,-61.2 v2(-3.325,-59.85) ; J31.13@0.425,-61.2 v2(0.425,-59.85) ; U8.2@5.955,43.23 5.955,42.045 6.14,41.86 C29.2@6.14,41.3 6.1,41.26 v1@6.1,40.4 ; v1(13.5,-57.1) R117.2@13.5,-56.48 ; R116.1@13.6,-54 13.7,-54.1 v1(13.7,-54.8) ; U10.2@13.87,43.2 13.87,42.015 14.055,41.83 14.055,41.27 14.015,41.23 14.015,40.315 v1(14,40.3) ; C191.1@16.56,-59.7 v1(17.2,-59.7) ; J19.4@51.8,-10.6 v1(51.8,-9.1) ; v1(53.8,-20.3) J19.9@53.8,-18.8 ; v1(56.2,-20.3) J19.15@56.2,-18.8 ; J19.18@60.6,-10.6 v1(60.6,-9.1) ; v1(61.8,-20.3) J19.21@61.8,-18.8 ; v1(64.2,-20.3) J19.27@64.2,-18.8 ; v1(65,-20.3) J19.29@65,-18.8 ; J19.34@67,-10.6 v1(67,-9.1) ; J19.35@67.4,-18.8 v1(67.4,-17.3) ; v1(67.6,57.9) C110.1@67.6,58.6 ; J19.37@68.2,-18.8 v1(68.2,-17.3) ; J19.40@69.4,-10.6 v1(69.4,-9.1) ; J19.43@70.6,-18.8 v1(70.6,-17.3) ; v2(73.5,56.7) v2(76.9,56.7) C9.2@75.2,56.7 ; v2(73.5,58.2) C9.2@75.2,58.2 v2(76.9,58.2) ; v2(73.5,59.7) v2(76.9,59.7) C9.2@75.2,59.7 ; U30.5@83.9,17.3 v2(84.74,17.3) ; C192.1@86.76,18 v2(87.6,18) ; C193.1@86.76,19.1 v2(87.6,19.1) ; R229.1@86.78,20.2 v2(87.62,20.2) ; v1(92.5,-49.5) C139.2@93.24,-49.5 93.24,-49.04 93.075,-48.875 U19.6@93.075,-47.57 ; C146.2@97.96,-24.5 v2(98.8,-24.5) ; v1(107,-50.1) 107.35,-49.75 U24.3@107.35,-49 ; v1(116.925,-36.85) J24.2@116.925,-35.375 v1(116.925,-33.9) ; v1(119.875,-36.85) J24.3@119.875,-35.375 v1(119.875,-33.9)
  1-TOP w0.4: U11.2@-38.52,43.1 -37.1,43.1 -36,43.1 C28.1@-35.04,43.1 ; C39.2@56.24,-3.8 U12.2@57.82,-3.8 ; J19.26@63.8,-10.6 v2(63.8,-8.2) ; C41.2@72.5,-6.4 v2(72.5,-5.7) ; C41.2@73.1,-7.3 73.1,-7.9 73.4,-8.2 J19.50@73.4,-10.6 ; C20.1@88.7,36 v1(88.7,37) ; C19.1@90.7,36 v1(90.7,37) ; C18.1@92.7,36 v1(92.7,37) ; C17.1@94.7,36 v1(94.7,37) ; C3.1@96.26,40.5 C4.1@96.26,41.6
  1-TOP w0.5: v2(-38.9,-49.2) -37.9,-49.2 R100.1@-37.8,-49.3 ; R100.1@-36.2,-49.2 v2(-35.1,-49.2) ; C190.1@33.2,-56.3 v1(33.2,-55) ; v2(49,59.4) J30.15@49,60.8 ; v2(52,55.725) J30.12@52,57.15 ; v2(55,59.4) J30.9@55,60.8 ; J30.6@58,57.15 58,55.725 v2(58.025,55.7)
  other v1: 91.9,-63.2 89.9,-63.1 29.6,-58 89.9,-57.8 91.9,-57.8 35.4,-57.7 36.5,-57.7 37.6,-57.7 16.5,-57.5 20.1,-57.4 18.5,-57.3 21.7,-57.3 25.6,-57.3 31.1,-56.9 30.1,-56.2 22.2,-55.9 25.6,-55.7 16.5,-55.6 31.2,-55.4 20.9,-55 28.9,-55 33.2,-54.3 22.2,-54 45.3,-53.8 25.8,-53.7 30.5,-53.7 22.7,-52.4 104.9,-50.1 18.9,-49 20.5,-49 25.1,-48.8 82.7,-47.8 106.37,-47.64 26.6,-47.2 -72.2,-47 17,-46.6 19,-46.6 21.1,-46.6 23.2,-46.6 32.1,-46.5 33.8,-46.1 35.3,-45.9 -52.6,-45.8 -73.5,-45.6 -71.8,-45.6 37.2,-45.3 105.8,-45.1 107.9,-44.9 -51.4,-44.7 -65.6,-44.5 24.4,-44.3 26,-44.3 108.98,-44.1 -65.1,-43.5 37.1,-43 38.654,-43 -47.4,-42.9 110.7,-42.9 111.8,-42.9 117.3,-42.7 119.5,-42.7 -45.4,-42.4 25.9,-42.2 27.3,-42.2 117.3,-41.1 111.8,-40.6 119.5,-40.6 117.3,-39.7 37.1,-39.4 38.5,-39.4 119.5,-39.4 117.3,-38.1 -71.8,-36.9 -70.7,-36.9 -69.5,-36.9 -68.4,-36.9 -52.85,-36.9 -51.75,-36.9 -50.55,-36.9 -49.45,-36.9 47.595,-36.805 49.7,-36.805 51.805,-36.805 -71.8,-35.8 -70.7,-35.8 -69.5,-35.8 -68.4,-35.8 -52.85,-35.8 -50.55,-35.8 -49.45,-35.8 47.595,-34.7 51.805,-34.7 -71.8,-34.6 -70.7,-34.6 -69.5,-34.6 -68.4,-34.6 -52.85,-34.6 -51.75,-34.6 -50.55,-34.6 -49.45,-34.6 118.4,-34 -71.8,-33.5 -70.7,-33.5 -69.5,-33.5 -68.4,-33.5 -52.85,-33.5 -51.75,-33.5 -50.55,-33.5 -49.45,-33.5 100.1,-33.3 101.7,-33.3 47.595,-32.595 49.7,-32.595 51.805,-32.595 88.459,-26.8 90.359,-26.8 13.4,-26.2 14.2,-26.2 11.9,-26.1 18.7,-26 15.5,-25.9 17.1,-24.8 15.8,-23.2 14.6,-21.5 89.4,-18.3 83.4,-17.7 85.2,-17.7 91.4,-17.4 87.3,-15.2 -21.1,-11.7 -20.95,-9.575 -22.1,-9.1 -21.6,-7.2 95.1,28.5 -53.8,29.8 -54.2,32.3 -52.4,32.3 89.7,37 91.7,37 93.7,37 88.7,37.7 89.7,37.7 90.7,37.7 91.7,37.7 92.7,37.7 81.2,38.5 -79.8,39 6.1,40.3 -80.9,43.1 -78.7,44.3 -80.9,44.7 -78.7,45.5 -80.9,46.1 -80.9,47.7 -78.7,47.7 -41.8,50.05 -41,50.05 -40.2,50.05 -41.8,50.85 -41,50.85 -40.2,50.85 -41.8,51.65 -41,51.65 -40.2,51.65 -36.4,52.1 -34.5,52.1 -34.4,57.6 -36.4,57.7
  other v2: 106.9,-38.6 108.9,-38.6 106.9,-36.5 108.9,-36.5 -65.6,30.4 -63.6,30.4 -61.6,30.4 -65.6,32.4 -61.6,32.4 -65.6,34.4 -63.6,34.4 -61.6,34.4 107.7,43 96.8,43.2 107.7,43.9 96.8,44.3 107.7,44.8 87.1,50.1
GPIO4_IO14: J42.12 J45.3 | length 141
  3-INTOP w0.2: v1@-31.8,46.9 -3.16,46.9 0.94,51 26.7,51 29.63,53.93 J42.12@29.63,57.93
  6-INBOT w0.2: J45.3@-54.62,-9 -50.2,-9 -48.2,-7 -48.2,28.507 -45.2,31.507 -45.2,35.3 -41.6,38.9 -33.6,38.9 -31.8,40.7 v1(-31.8,46.89)
GPIO4_IO16: J42.14 J52.3 | length 141.5
  3-INTOP w0.2: v1(-31.3,47.4) -3.367,47.4 0.733,51.5 25.3,51.5 27.09,53.29 J42.14@27.09,57.93
  6-INBOT w0.2: J52.3@-54.62,-11.9 -50.5,-11.9 -47.7,-9.1 -47.7,28.3 -44.7,31.3 -44.7,35.1 -41.4,38.4 -33.393,38.4 -31.3,40.493 v1(-31.3,47.4)
GPIO4_IO22: J42.16 J55.3 | length 108.1
  3-INTOP w0.2: v1(-37,46.1) -33.6,46.1 -31.8,47.9 -3.574,47.9 0.526,52 22.5,52 24.55,54.05 J42.16@24.55,57.93
  6-INBOT w0.2: J55.3@-54.62,17 -53.1,17 -51.3,18.8 -51.3,29.821 -48.5,32.621 -48.5,34.8 -42.905,40.395 -39.305,40.395 -37.8,41.9 -37.8,45.3 v1(-37,46.1)
GPIO4_IO25: J42.18 J56.3 | length 112.2
  3-INTOP w0.2: v1(-35.9,46.6) -33.807,46.6 -32.007,48.4 -25.1,48.4 -24,49.5 -4.793,49.5 -1.793,52.5 20.9,52.5 22.01,53.61 J42.18@22.01,57.93
  6-INBOT w0.2: J56.3@-54.62,11.2 -51.9,11.2 -50.3,12.8 -50.3,29.407 -47.5,32.207 -47.5,35.1 -42.7,39.9 -38.8,39.9 -36.4,42.3 -36.4,46.1 v1(-35.9,46.6)
GPIO4_IO27: J42.20 J60.3 | length 119.5
  3-INTOP w0.2: v1(-32.3,48.9) -25.307,48.9 -24.207,50 -5,50 -2,53 17.5,53 19.47,54.97 J42.20@19.47,57.93
  6-INBOT w0.2: J60.3@-54.62,2.5 -51.4,2.5 -49.2,4.7 -49.2,29.007 -46.5,31.707 -46.5,34.7 -41.8,39.4 -33.8,39.4 -32.3,40.9 v1(-32.3,48.9)
HDMI_CLK_N: L21.1 U17.21 | length 5
  1-TOP w0.15: L21.1@47.925,-43.15 48.025,-43.05 48.025,-42.328 48.175,-42.178 48.175,-40.875 48.028,-40.728 48.028,-39.577 48.323,-39.282 48.323,-38.428 U17.21@48.3,-38.405
HDMI_CLK_P: L21.4 U17.22 | length 5
  1-TOP w0.15: 48.377,-39.724 48.377,-40.556 48.525,-40.704 48.525,-42.325 48.377,-42.473 48.377,-43.052 L21.4@48.475,-43.15 ; 48.382,-39.724 48.677,-39.429 48.677,-38.428 U17.22@48.7,-38.405
HDMI_D0_N: L20.1 U17.24 | length 5
  1-TOP w0.15: L20.1@49.425,-43.15 49.523,-43.052 49.523,-41.82 49.225,-41.522 49.225,-40.375 49.523,-40.077 U17.24@49.523,-38.433 ; U17.24@49.5,-38.405 U17.24@49.528,-38.433
HDMI_D0_P: L20.4 U17.25 | length 5
  1-TOP w0.15: U17.25@49.877,-38.433 49.877,-40.198 49.575,-40.5 49.575,-41.371 49.877,-41.673 49.877,-43.052 L20.4@49.975,-43.15 ; U17.25@49.882,-38.423 U17.25@49.9,-38.405
HDMI_D1_N: L19.1 U17.27 | length 5
  1-TOP w0.15: U17.27@50.7,-38.405 50.723,-38.428 50.723,-39.318 51.023,-39.618 51.023,-40.476 51.175,-40.628 51.173,-40.63 51.173,-41.527 51.023,-41.677 51.023,-43.052 L19.1@50.925,-43.15
HDMI_D1_P: L19.4 U17.28 | length 5
  1-TOP w0.15: U17.28@51.1,-38.405 51.077,-38.428 51.077,-39.171 51.377,-39.471 51.377,-40.367 51.527,-40.517 51.527,-41.674 51.377,-41.824 51.377,-43.052 L19.4@51.475,-43.15
HDMI_D2_N: L18.1 U17.30 | length 5
  1-TOP w0.15: U17.30@51.9,-38.405 51.923,-38.428 51.923,-38.619 51.923,-39.419 52.523,-40.019 52.523,-43.052 L18.1@52.425,-43.15
HDMI_D2_P: L18.4 U17.31 | length 5
  1-TOP w0.15: U17.31@52.3,-38.405 52.277,-38.428 52.277,-39.272 52.877,-39.872 52.877,-43.052 L18.4@52.975,-43.15
HDMI_FIL_CLK_N: J32.12 L21.2 U18.15 U18.24 | length 11.3
  1-TOP w0.15: J32.12@47.7,-55.8 U18.15@47.7,-46.5 47.7,-45.2 47.925,-44.975 L21.2@47.925,-44.55
HDMI_FIL_CLK_P: J32.10 L21.3 U18.13 U18.26 | length 11.4
  1-TOP w0.15: L21.3@48.475,-44.45 48.475,-44.975 48.7,-45.2 U18.13@48.7,-46.5 J32.10@48.7,-55.8
HDMI_FIL_D0_N: J32.9 L20.2 U18.12 U18.27 | length 11.4
  1-TOP w0.15: J32.9@49.2,-55.8 U18.12@49.2,-46.5 49.2,-45.2 49.425,-44.975 L20.2@49.425,-44.45
HDMI_FIL_D0_P: J32.7 L20.3 U18.10 U18.29 | length 11.4
  1-TOP w0.15: L20.3@49.975,-44.45 49.975,-44.975 50.2,-45.2 U18.10@50.2,-46.5 J32.7@50.2,-55.8
HDMI_FIL_D1_N: J32.6 L19.2 U18.9 U18.30 | length 11.4
  1-TOP w0.15: J32.6@50.7,-55.8 U18.9@50.7,-46.5 50.7,-45.2 50.925,-44.975 L19.2@50.925,-44.45
HDMI_FIL_D1_P: J32.4 L19.3 U18.7 U18.32 | length 11.4
  1-TOP w0.15: L19.3@51.475,-44.45 51.475,-44.975 51.7,-45.2 U18.7@51.7,-46.5 U18.32@51.7,-52.3 J32.4@51.7,-55.8
HDMI_FIL_D2_N: J32.3 L18.2 U18.6 U18.33 | length 11.4
  1-TOP w0.15: J32.3@52.2,-55.8 U18.33@52.2,-52.3 U18.6@52.2,-46.5 52.2,-45.2 52.425,-44.975 L18.2@52.425,-44.45
HDMI_FIL_D2_P: J32.1 L18.3 U18.4 U18.35 | length 11.4
  1-TOP w0.15: L18.3@52.975,-44.45 52.975,-44.975 53.2,-45.2 U18.4@53.2,-46.5 J32.1@53.2,-55.8
HDMI_FIL_SCL: J32.15 R128.2 U18.22 | length 7.8
  1-TOP w0.2: R128.2@44.28,-50 45.7,-50 46.7,-51 U18.22@46.7,-52.3 46.7,-53.8 46.2,-54.3 J32.15@46.2,-55.8
HDMI_FIL_SDA: J32.16 R129.2 U18.21 | length 6.7
  1-TOP w0.2: R129.2@44.28,-51.1 45.9,-51.1 46.2,-51.4 U18.21@46.2,-52.3 46.2,-53.7 45.7,-54.2 J32.16@45.7,-55.8
HDMI_HPD_1V8: C115.2 Q3.S R121.1 R127.2 R130.1 R132.1 U18.19 | length 9.6
  1-TOP w0.3: R132.1@44.68,-39.4 44.7,-39.42 44.7,-40.5 44.46,-40.74 44.46,-42.85 R130.1@44.46,-44.2 C115.2@44.46,-46.6 44.46,-46.7 U18.19@45.7,-46.7 ; R132.1@44.7,-39.4 R121.1@44.7,-38.4
HDMI_HPD_3V3_CPU: Q3.D R131.1 R132.2 U7.C18 | length 128.7
  1-TOP w0.2: v1(-18.415,3.175) U7.C18@-17.78,3.81 ; v1(41.3,-40.5) 42.3,-40.5 42.68,-40.12 R131.1@42.68,-39.5 ; R131.1@42.68,-39.4 R131.1@42.68,-39.5 ; Q3.D@43.5,-40.65 43.62,-40.53 43.62,-39.5 R131.1@42.68,-39.5
  3-INTOP w0.2: v1(-29.2,-35.3) 7.8,-35.3 10.5,-38 38.2,-38 40.7,-40.5 v1(41.3,-40.5)
  8-BOTTOM w0.2: v1(-29.2,-35.3) -31.6,-32.9 -31.6,0 -29,2.6 -18.99,2.6 v1(-18.415,3.175)
HDMI_SCL_1V8: R185.2 U18.17 | length 84.5
  1-TOP w0.2: U18.17@46.7,-46.5 v1(46.7,-44.8) ; v1(67,23.7) R185.2@67,24.32
  6-INBOT w0.15: v1(46.7,-44.8) 46.7,-44.4 46.5,-44.2 46.5,-30.7 46.8,-30.4 46.8,-23.5 47.9,-22.4 49,-22.4 60.5,-10.9 66.766,-10.9 67.9,-9.766 67.9,12.373 67.4,12.873 67.4,23.3 v1(67,23.7)
HDMI_SDA_1V8: R187.2 U18.18 | length 89.8
  1-TOP w0.2: v1(46,-44.8) 46,-45 46.2,-45.2 U18.18@46.2,-46.5 ; R187.2@67,28.08 v1(67,28.7)
  6-INBOT w0.15: v1(46,-44.8) 46,-30.5 46.4,-30.1 46.4,-23.334 47.734,-22 48.8,-22 60.3,-10.5 66.6,-10.5 67.5,-9.6 67.5,-8.4 66.7,-7.6 66.7,22.8 66.4,23.1 66.4,24.3 66.4,26.2 67,26.8 v1(67,28.7)
HDMICEC: J32.13 R120.2 U18.23 | length 9.2
  1-TOP w0.2: R120.2@44.28,-48.9 46.2,-48.9 47.2,-49.9 U18.23@47.2,-52.3 J32.13@47.2,-55.8
HDMIHPD: C119.2 J32.19 R126.2 U18.20 | length 5.1
  1-TOP w0.2: J32.19@44.2,-55.8 44.2,-52.26 C119.2@44.26,-52.2 45.6,-52.2 U18.20@45.7,-52.3
I2C3_SCL: R46.1 R48.1 R178.1 R180.1 R184.1 R188.1 R230.1 U7.AK25 | length 55.8
  1-TOP w0.2: U7.AK25@16.51,12.7 v1(17.145,13.335) ; v1(62.1,18.8) 62.52,19.22 R180.1@63.1,19.22 R184.1@64.2,19.22 R178.1@65.2,19.22 R188.1@66.2,19.22 R46.1@67.2,19.22 R48.1@68.2,19.22 R230.1@69.2,19.22
  3-INTOP w0.15: v1(17.145,13.335) 17.58,12.9 38.434,12.9 44.334,18.8 v1(62.1,18.8)
I2C3_SDA: R47.1 R49.1 R181.1 R182.1 R186.1 R190.1 R231.1 U7.AK24 | length 55.7
  1-TOP w0.2: U7.AK24@16.51,11.43 v1(17.145,12.065) ; v1(62.1,18.1) 62.12,18.08 R181.1@63.1,18.08 R186.1@64.2,18.08 64.22,18.1 65.18,18.1 R182.1@65.2,18.08 65.22,18.1 67.2,18.1 R231.1@69.2,18.1
  3-INTOP w0.15: v1(17.145,12.065) 17.58,12.5 38.6,12.5 44.5,18.4 60.7,18.4 61,18.1 v1(62.1,18.1)
I2C4_SCL: R173.1 R176.2 U7.F28 U28.6 | length 83
  1-TOP w0.15: v1(58.1,26.2) 58.1,27.3 58.4,27.6 58.9,27.6 59.42,27.08 R176.2@61.1,27.08 61.12,27.1 61.6,27.1 61.88,27.38 U28.6@62.2,27.38
  1-TOP w0.2: v1(-14.605,17.145) U7.F28@-13.97,16.51
  3-INTOP w0.2: v1(-14.605,17.145) -10.25,21.5 51.5,21.5 56.2,26.2 v1(58.1,26.2)
I2C4_SCL_1V8: R172.1 R176.1 R179.1 R185.1 R189.1 U28.1 | length 8.7
  1-TOP w0.15: R176.1@61.1,26.12 61.12,26.1 61.6,26.1 61.88,25.82 U28.1@62.2,25.82 62.2,25.4 62.32,25.28 R172.1@65.8,25.28 R185.1@67,25.28 R189.1@68.1,25.28 R179.1@69.2,25.28
I2C4_SDA: R175.1 R177.2 U7.E29 U28.3 | length 88.4
  1-TOP w0.15: v1(58.7,27.1) 58.7,26.5 59,26.2 R175.1@59.9,26.2 ; U28.3@63.2,25.82 63.52,25.82 63.82,26.12 R177.2@64.3,26.12
  1-TOP w0.2: U7.E29@-15.24,17.78 v1(-14.605,18.415) ; R177.2@64.3,26.12 64.32,26.1 v1(65,26.1)
  3-INTOP w0.2: v1(-14.605,18.415) -11.02,22 51.327,22 56.427,27.1 v1(58.7,27.1) 59.1,27.1 60.1,26.1 v1(65,26.1)
I2C4_SDA_1V8: R174.1 R177.1 R183.1 R187.1 R191.1 U28.4 | length 6.1
  1-TOP w0.15: U28.4@63.2,27.38 63.52,27.38 63.82,27.08 R177.1@64.3,27.08 65.8,27.08 67,27.08 68.1,27.08 R183.1@69.2,27.08
ILIM_5V_VBUS: Q12.G R202.2 U23.6 | length 3.7
  1-TOP w0.2: Q12.G@79.1,-48.71 79.1,-47.42 R202.2@79.08,-47.4 U23.6@81.45,-47.4
IMX9_ON_OFF: R4.2 U7.AG18 | length 46.6
  1-TOP w0.2: U7.AG18@12.7,3.81 v1(13.335,4.445) ; R4.2@26.6,43.58 26.78,43.4 v1(27.4,43.4)
  6-INBOT w0.2: v1(13.335,4.445) 14,5.11 14,16.5 25.4,27.9 25.4,40.4 27.4,42.4 v1(27.4,43.4)
IW612_JTAG_TCK: J12.3 U7.E11 | length 66.4
  1-TOP w0.2: J12.3@-25.53,48.832 -25.5,48.862 v1(-25.5,50.8) ; v1(-15.875,-5.715) U7.E11@-15.24,-5.08
  6-INBOT w0.2: v1(-25.5,50.8) -24,50.8 -22.8,49.6 -22.8,42 -22.4,41.6 -22.4,-2.8 -20.1,-5.1 -16.49,-5.1 v1(-15.875,-5.715)
IW612_JTAG_TDI: J12.7 U7.E9 | length 69.8
  1-TOP w0.2: v1(-28.1,50.8) -28.1,48.862 J12.7@-28.07,48.832 ; v1(-15.875,-8.255) U7.E9@-15.24,-7.62
  6-INBOT w0.2: v1@-28.1,50.9 -28.1,41.2 -23.4,36.5 -23.4,-4.5 -19,-8.9 -16.52,-8.9 v1(-15.875,-8.255)
IW612_JTAG_TDO: J12.5 U7.G15 | length 63.8
  1-TOP w0.2: J12.5@-26.8,48.832 v1(-26.8,50.8) ; v1(-13.335,-0.635) U7.G15@-12.7,0
  6-INBOT w0.2: v1(-26.8,50.8) -26.2,51.4 -23.4,51.4 -22.3,50.3 -22.3,46.6 -14,38.3 -14,11.8 -12.7,10.5 -12.7,7 -14,5.7 -14,0.03 v1(-13.335,-0.635)
IW612_JTAG_TMS: J12.1 U7.E10 | length 62.6
  1-TOP w0.2: J12.1@-24.26,48.832 -24.26,48.9 v1(-23.4,48.9) ; v1(-15.875,-6.985) U7.E10@-15.24,-6.35
  6-INBOT w0.2: v1(-23.4,48.9) -23.4,46.6 -23.4,41.8 -22.9,41.3 -22.9,-3 -20.3,-5.6 -18.6,-5.6 -17.215,-6.985 v1(-15.875,-6.985)
JTAG_TCK: J20.4 U7.AG20 | length 64.9
  1-TOP w0.2: v1(-13.53,42.9) J20.4@-13.53,44.768 ; U7.AG20@12.7,6.35 v1(13.335,6.985)
  8-BOTTOM w0.2: v1(-13.53,42.9) -13.53,41.77 -14.2,41.1 -14.2,37.8 -13.2,36.8 10.6,36.8 12.7,34.7 12.7,10 14,8.7 14,7.65 v1(13.335,6.985)
JTAG_TDI: J20.8 U7.AH27 | length 56.6
  1-TOP w0.2: v1(-16.07,42.9) J20.8@-16.07,44.768 ; U7.AH27@13.97,15.24 14.6,15.87 14.6,35.1 v1(14.2,35.5)
  8-BOTTOM w0.2: v1(-16.07,42.9) -15.27,43.7 -10.7,43.7 -4.8,37.8 11.9,37.8 v1(14.2,35.5)
JTAG_TDO: J20.6 U7.AG21 | length 63.4
  1-TOP w0.2: v1(-14.8,42.9) J20.6@-14.8,44.768 ; U7.AG21@12.7,7.62 v1(13.335,8.255)
  8-BOTTOM w0.2: v1(-14.8,42.9) -14.8,41.5 -14.8,37.5 -13.6,36.3 9.9,36.3 11.5,34.7 11.5,9.1 11.8,8.8 12.79,8.8 v1(13.335,8.255)
JTAG_TMS: J20.2 U7.AH28 | length 50.8
  1-TOP w0.2: v1(-12.26,42.9) J20.2@-12.26,44.768 ; v1(13.3,35.5) 13.3,17.18 U7.AH28@13.97,16.51
  8-BOTTOM w0.2: v1(-12.26,42.9) -10.76,41.4 -10.76,39.66 -8.4,37.3 11.5,37.3 v1(13.3,35.5)
L_CLK_N: J31.11 L15.2 | length 2
  1-TOP w0.15: J31.11@-1.85,-61.25 -1.85,-60.15 -1.627,-59.927 -1.627,-59.498 L15.2@-1.725,-59.4
L_CLK_P: J31.12 L15.3 | length 2
  1-TOP w0.15: L15.3@-1.175,-59.4 -1.273,-59.498 -1.273,-59.927 -1.05,-60.15 J31.12@-1.05,-61.25
L_D0_N: J31.2 L12.2 | length 2
  1-TOP w0.15: J31.2@-13.1,-61.25 -13.1,-60.15 -12.877,-59.927 -12.877,-59.498 L12.2@-12.975,-59.4
L_D0_P: J31.3 L12.3 | length 2
  1-TOP w0.15: L12.3@-12.425,-59.4 -12.523,-59.498 -12.523,-59.927 -12.3,-60.15 J31.3@-12.3,-61.25
L_D1_N: J31.5 L13.2 | length 2
  1-TOP w0.15: J31.5@-9.35,-61.25 -9.35,-60.15 -9.127,-59.927 -9.127,-59.498 L13.2@-9.225,-59.4
L_D1_P: J31.6 L13.3 | length 2
  1-TOP w0.15: L13.3@-8.675,-59.4 -8.773,-59.498 -8.773,-59.927 -8.55,-60.15 J31.6@-8.55,-61.25
L_D2_N: J31.8 L14.2 | length 2
  1-TOP w0.15: J31.8@-5.6,-61.25 -5.6,-60.15 -5.377,-59.927 -5.377,-59.498 L14.2@-5.475,-59.4
L_D2_P: J31.9 L14.3 | length 2
  1-TOP w0.15: L14.3@-4.925,-59.4 -5.023,-59.498 -5.023,-59.927 -4.8,-60.15 J31.9@-4.8,-61.25
L_D3_N: J31.14 L16.2 | length 2
  1-TOP w0.15: J31.14@1.9,-61.25 1.9,-60.15 2.123,-59.927 2.123,-59.498 L16.2@2.025,-59.4
L_D3_P: J31.15 L16.3 | length 2
  1-TOP w0.15: L16.3@2.575,-59.4 2.477,-59.498 2.477,-59.927 2.7,-60.15 J31.15@2.7,-61.25
LDO2: J47.1 R36.1 | length 166.4
  1-TOP w0.3: R36.1@44.8,-3.82 44.8,-2.9 43,-1.1 43,6.1 46,9.1 v1(46,30.1)
  3-INTOP w0.3: J47.1@-81.1,21.82 -51.87,21.82 -49.39,24.3 -35,24.3 -31.3,28 29.2,28 31.3,30.1 v1(46,30.1)
LDO3: J47.2 R37.1 | length 156.3
  1-TOP w0.3: J47.2@-83.64,21.82 -82.16,23.3 -78.2,23.3 -76.7,21.8 v1(-31,21.8) ; v1(14.5,-37.3) R37.1@15.22,-37.3
  3-INTOP w0.3: v1(-28.7,-34.6) 8.8,-34.6 11.5,-37.3 v1(14.5,-37.3)
  6-INBOT w0.3: v1(-31,21.8) -31,-32.3 v1(-28.7,-34.6)
LED: R212.2 R217.1 U29.7 | length 3.1
  1-TOP w0.2: R212.2@36.28,-61.4 36.28,-61.32 R212.2@36.5,-61.1 ; R217.1@37.18,-59.7 37.25,-59.63 U29.7@37.25,-58.635
  1-TOP w0.3: R212.2@36.5,-61.1 36.5,-60.8 37.1,-60.2 R217.1@37.1,-59.7
LED_1_1000: Q7.G U13.12 | length 16.3
  1-TOP w0.2: Q7.G@-80,-48.71 -80,-45.1 -78.3,-43.4 -78.3,-40.5 -78.7,-40.1 -78.7,-38.1 -78.1,-37.5 -74.2,-37.5 U13.12@-74.15,-37.45
LED_1_ACT: Q8.G U13.14 | length 14.1
  1-TOP w0.2: Q8.G@-82.1,-48.71 v1(-82.1,-47.9) ; v1(-74.2,-39.3) -74.2,-38.5 U13.14@-74.15,-38.45
  8-BOTTOM w0.2: v1(-82.1,-47.9) -82.1,-46.3 -75.1,-39.3 v1(-74.2,-39.3)
LED_2_1000: Q9.G U14.12 | length 11.4
  1-TOP w0.2: Q9.G@-59.79,-46.4 -59.79,-45.89 -59.5,-45.6 v1(-59.2,-45.6) ; v1(-56,-37.6) -55.85,-37.45 U14.12@-55.2,-37.45
  8-BOTTOM w0.2: v1(-59.2,-45.6) -59.2,-44 -56,-40.8 v1(-56,-37.6)
LED_2_ACT: Q10.G U14.14 | length 12.3
  1-TOP w0.2: Q10.G@-59.79,-48.5 -59.2,-48.5 v1(-58.9,-48.2) ; v1(-55.2,-39) U14.14@-55.2,-38.45
  8-BOTTOM w0.2: v1(-58.9,-48.2) -58.5,-47.8 -58.5,-44 -55.2,-40.7 v1(-55.2,-39)
LINE1_IN_L: J46.2 L35.1 | length 23.3
  1-TOP w0.2: L35.1@-65.9,43.08 v1(-65.9,43.8)
  8-BOTTOM w0.2: J46.2@-83.74,35 -82.44,33.7 -78.5,33.7 -70.069,42.131 -67.569,42.131 v1(-65.9,43.8)
LINE1_IN_R: J46.1 L34.1 | length 18.5
  1-TOP w0.2: L34.1@-67.1,43.08 v1(-67.1,43.8)
  8-BOTTOM w0.2: J46.1@-81.2,35 -78,35 -70.303,42.697 -68.203,42.697 v1(-67.1,43.8)
LINE2_IN_L: J46.4 L37.1 | length 26.7
  1-TOP w0.2: L37.1@-63.5,43.08 v1(-63.5,43.8)
  8-BOTTOM w0.2: J46.4@-83.74,32.46 -82.48,31.2 -79.4,31.2 -69.6,41 -66.3,41 v1(-63.5,43.8)
LINE2_IN_R: J46.3 L36.1 | length 21.9
  1-TOP w0.2: L36.1@-64.7,43.08 v1(-64.7,43.8)
  8-BOTTOM w0.2: J46.3@-81.2,32.46 -78.94,32.46 -69.834,41.566 -66.934,41.566 v1(-64.7,43.8)
LINE_OUT_L: J46.6 U27.24 | length 42.4
  1-TOP w0.15: U27.24@-60.17,33.4 -59,33.4 -53.934,33.4 -53.1,32.566 -53.1,31.8 v1(-53,31.7)
  8-BOTTOM w0.15: J46.6@-83.74,29.92 -82.52,28.7 -77.066,28.7 -75.466,27.1 -67.1,27.1 -65.9,28.3 -59.934,28.3 -57.434,30.8 -53.4,30.8 -53.1,31.1 -53.1,31.6 v1(-53,31.7)
LINE_OUT_R: J46.5 U27.23 | length 38.4
  1-TOP w0.15: U27.23@-60.17,33 -54.1,33 -53.5,32.4 -53.5,31.8 v1(-53.6,31.7)
  8-BOTTOM w0.15: J46.5@-81.2,29.92 -77.72,29.92 -75.3,27.5 -67.266,27.5 -66.066,28.7 -60.1,28.7 -57.6,31.2 -53.6,31.2 -53.5,31.3 -53.5,31.6 v1(-53.6,31.7)
LT8912B_CLK_N: U15.16 U17.8 | length 54.6
  1-TOP w0.15: v1(18.9,-56.8) 19.023,-56.677 19.023,-55.323 19,-55.3 U15.16@19,-54.745 ; v1(36.423,-45.3) 36.3,-45.177 36.3,-36.301 38.124,-34.477 45.972,-34.477 U17.8@45.995,-34.5
  8-BOTTOM w0.15: v1(18.9,-56.8) 19.023,-56.923 19.023,-58.723 19.754,-59.454 ; 19.78,-59.454 30.322,-59.454 35.8,-53.976 35.8,-48.026 36.072,-47.754 37.512,-47.754 37.85,-47.416 37.85,-46.422 37.528,-46.1 36.525,-46.1 36.3,-45.875 36.3,-45.423 v1(36.423,-45.3)
LT8912B_CLK_P: U15.17 U17.7 | length 54.6
  1-TOP w0.15: U15.17@19.4,-54.745 19.4,-55.3 19.377,-55.323 19.377,-56.677 v1(19.5,-56.8) ; v1(35.823,-45.3) 35.946,-45.177 35.946,-36.154 37.977,-34.123 41.1,-34.123 41.175,-34.123 41.263,-34.035 41.263,-33.807 41.333,-33.737 41.543,-33.737 41.613,-33.807 41.613,-34.035 41.701,-34.123 41.8,-34.123 43.6,-34.123 45.972,-34.123 U17.7@45.995,-34.1
  8-BOTTOM w0.15: v1(19.5,-56.8) 19.377,-56.923 19.377,-58.576 19.901,-59.1 ; 19.926,-59.1 30.175,-59.1 35.446,-53.829 35.446,-47.879 35.925,-47.4 37.365,-47.4 37.496,-47.269 37.496,-46.569 37.381,-46.454 36.378,-46.454 35.946,-46.022 35.946,-45.423 v1(35.823,-45.3)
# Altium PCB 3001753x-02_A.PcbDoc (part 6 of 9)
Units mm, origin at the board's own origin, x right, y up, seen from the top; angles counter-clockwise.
Board outline 210 x 130 mm, 8 copper layers (1-TOP, 2-GND, 3-INTOP, 4-PWR, 5-PWR, 6-INBOT, 7-GND, 8-BOTTOM), stack 1.646 mm thick; 651 components, 607 nets, 2780 pads, 1706 vias.

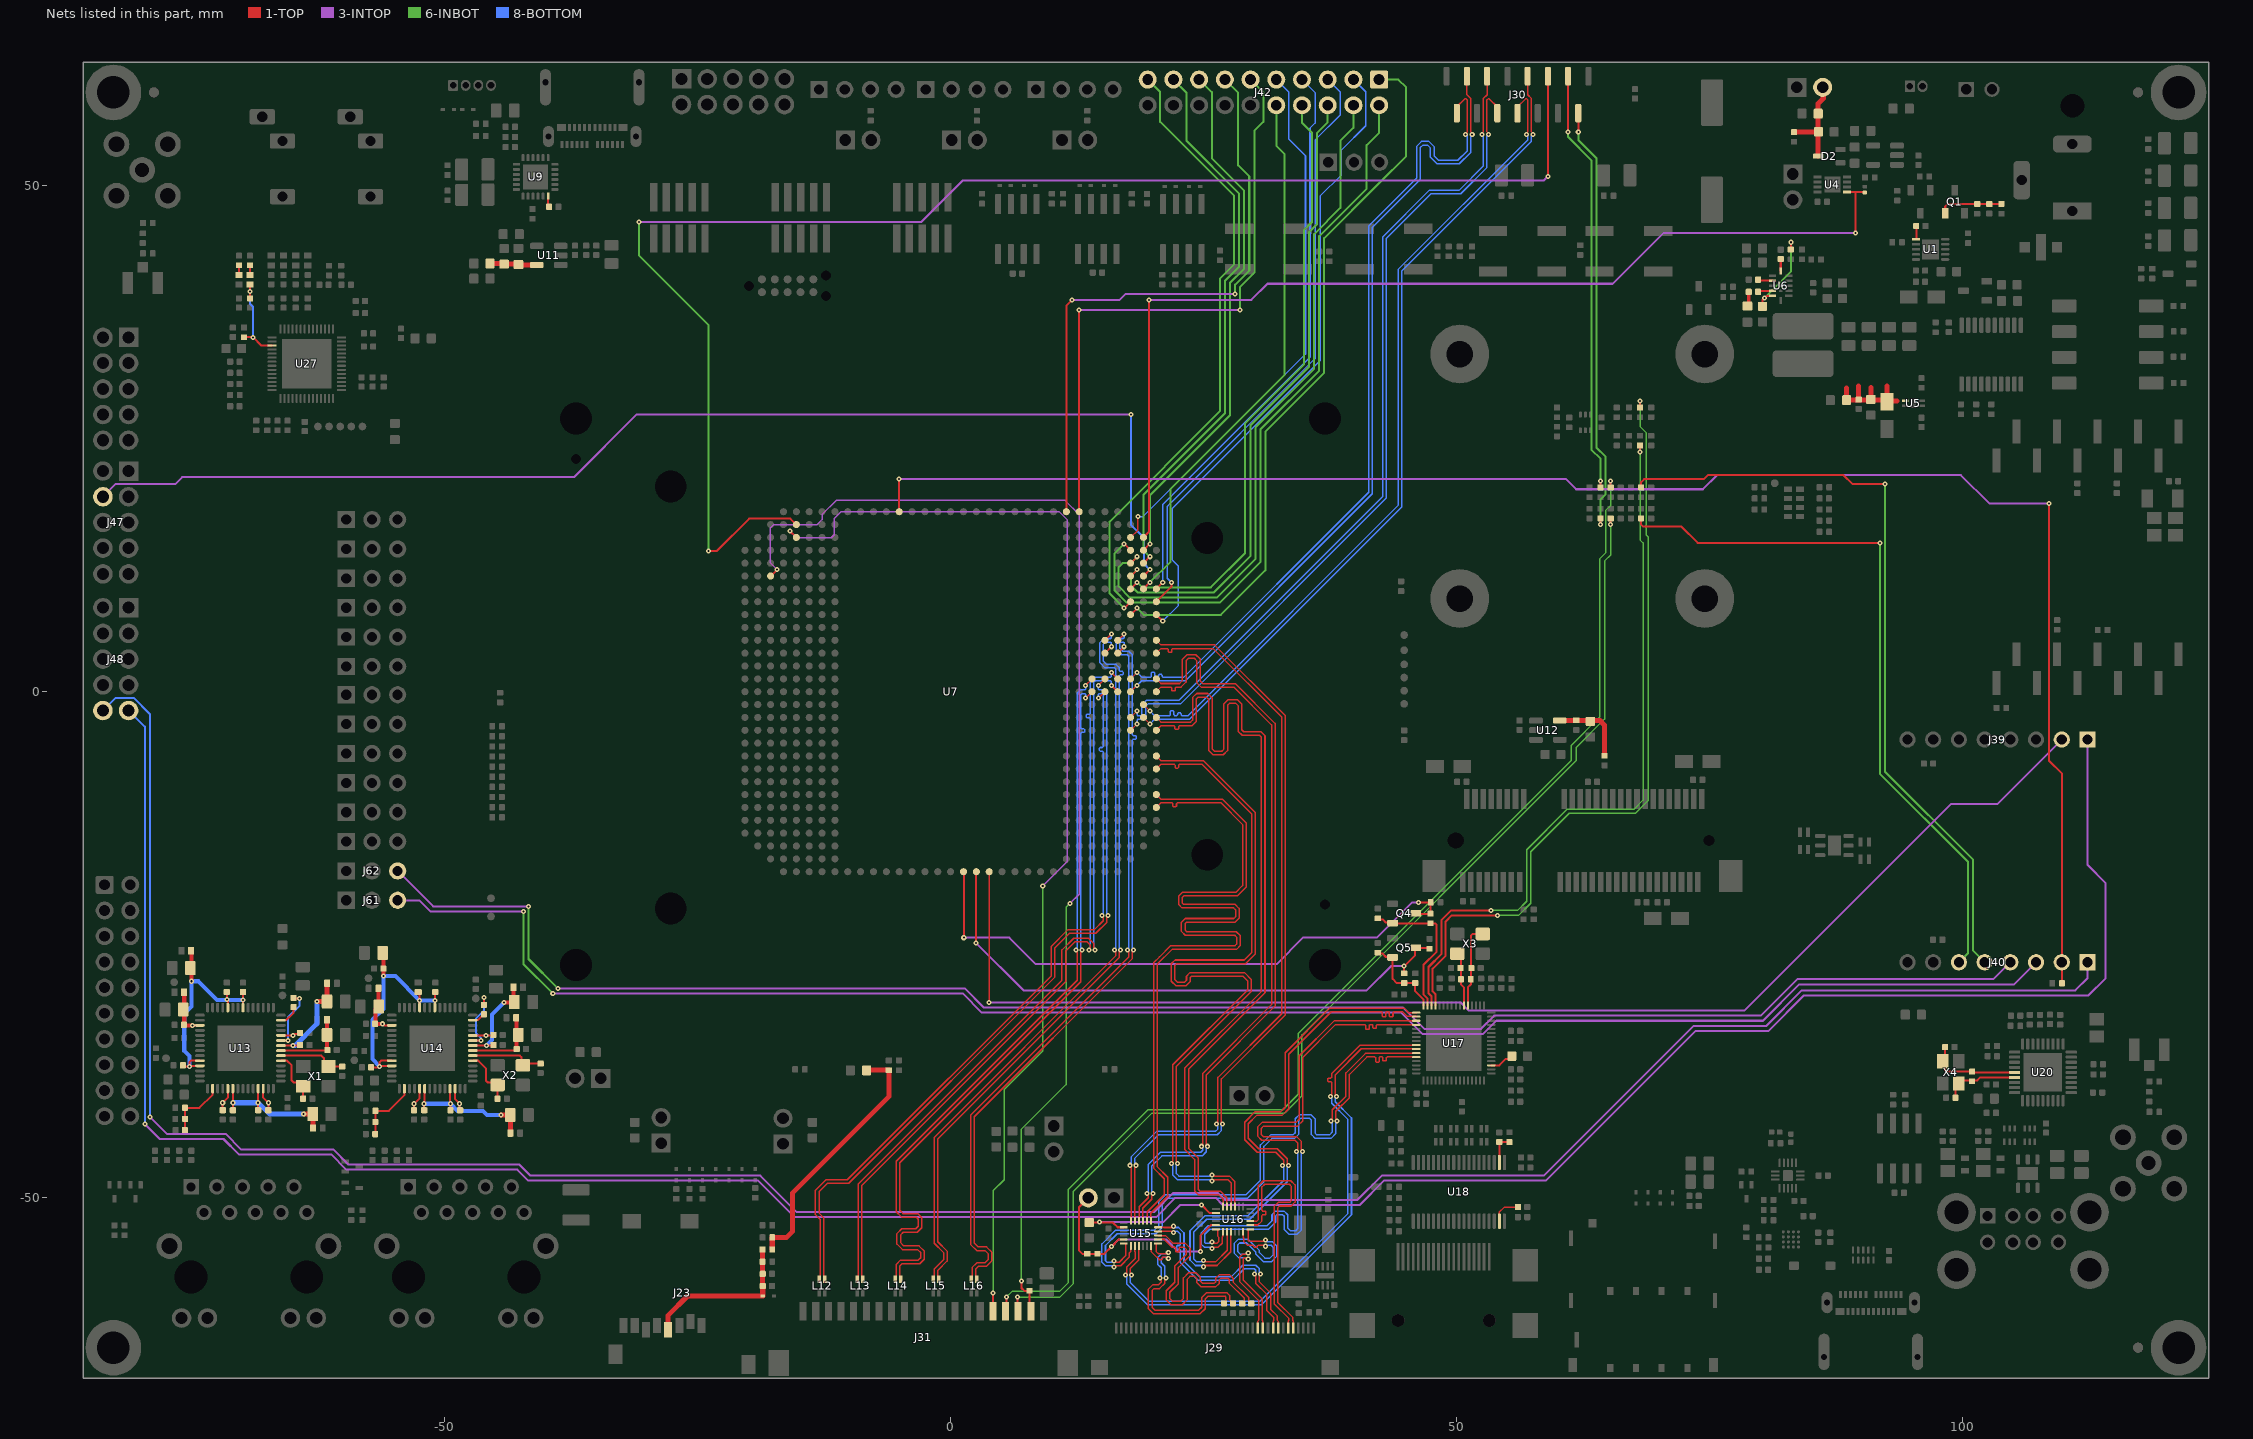
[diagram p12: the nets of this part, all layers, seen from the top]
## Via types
v1: diameter 0.5, hole 0.2, 1-TOP to 8-BOTTOM, 1453 vias
v2: diameter 0.68, hole 0.3, 1-TOP to 8-BOTTOM, 253 vias

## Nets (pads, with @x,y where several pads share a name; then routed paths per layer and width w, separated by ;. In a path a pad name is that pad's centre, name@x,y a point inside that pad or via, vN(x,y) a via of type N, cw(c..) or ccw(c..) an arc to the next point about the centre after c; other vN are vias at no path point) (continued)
LT8912B_D0_N: U16.14 U17.2 | length 54.6
  1-TOP w0.15: v1(25,-56.2) 25.123,-56.323 26.176,-56.323 27.323,-55.176 27.323,-53.827 27.321,-53.825 27.321,-53.366 U16.14@27.3,-53.345 ; v1(33.377,-46.8) 33.254,-46.677 33.254,-46.129 32.271,-45.146 30.446,-45.146 29.4,-44.1 29.4,-42.676 30.222,-41.854 32.746,-41.854 33.4,-41.2 33.4,-35.801 37.597,-31.604 42.136,-31.604 42.561,-31.604 42.649,-31.692 42.649,-32.074 42.701,-32.126 42.946,-32.126 42.999,-32.074 42.999,-31.657 43.051,-31.604 43.296,-31.604 43.349,-31.657 43.349,-32.056 43.401,-32.109 43.646,-32.109 43.699,-32.056 43.699,-31.692 43.787,-31.604 44.25,-31.604 44.63,-31.604 45.103,-32.077 45.972,-32.077 U17.2@45.995,-32.1
  8-BOTTOM w0.15: v1(25,-56.2) 24.877,-56.323 24.323,-56.323 24,-56 24,-53.4 25.3,-52.1 29.55,-52.1 33.254,-48.396 33.254,-46.923 v1(33.377,-46.8)
LT8912B_D0_P: U16.15 U17.1 | length 54.6
  1-TOP w0.15: v1(25,-56.8) 25.123,-56.677 26.323,-56.677 27.677,-55.323 27.677,-53.368 U16.15@27.7,-53.345 ; v1(32.777,-46.8) 32.9,-46.677 32.9,-46.276 32.124,-45.5 30.299,-45.5 29.046,-44.247 29.046,-42.529 30.075,-41.5 32.599,-41.5 33.046,-41.053 33.046,-35.654 37.45,-31.25 44.777,-31.25 45.25,-31.723 45.972,-31.723 U17.1@45.995,-31.7
  8-BOTTOM w0.15: v1(25,-56.8) 24.877,-56.677 24.176,-56.677 23.646,-56.147 23.646,-53.253 25.153,-51.746 29.403,-51.746 32.9,-48.249 32.9,-46.923 v1(32.777,-46.8)
LT8912B_D1_N: U16.12 U17.4 | length 54.5
  1-TOP w0.15: v1(25.8,-54.377) 25.8,-54.4 25.9,-54.5 26.299,-54.5 26.473,-54.326 26.473,-53.873 26.4,-53.8 U16.12@26.4,-53.1 ; v1(34.777,-45.4) 34.654,-45.277 34.654,-44.429 34.171,-43.946 30.878,-43.946 30.675,-43.743 30.675,-43.136 30.911,-42.9 34.275,-42.9 34.8,-42.375 34.8,-36.101 38.024,-32.877 40.5,-32.877 40.925,-32.877 41.013,-32.965 41.013,-33.292 41.065,-33.345 41.31,-33.345 41.363,-33.292 41.363,-32.929 41.415,-32.877 41.66,-32.877 41.713,-32.929 41.713,-33.197 41.765,-33.249 42.01,-33.249 42.063,-33.197 42.063,-32.965 42.151,-32.877 42.25,-32.877 43.8,-32.877 45.972,-32.877 U17.4@45.995,-32.9
  8-BOTTOM w0.15: v1(25.8,-54.377) 25.677,-54.5 25.2,-54.5 25.1,-54.4 25.1,-53.601 25.601,-53.1 29.5,-53.1 31.401,-53.1 32.1,-52.401 32.1,-51.801 32.247,-51.654 32.79,-51.654 32.946,-51.81 32.946,-53.119 33.427,-53.6 34.229,-53.6 34.654,-53.175 34.654,-51.947 34.654,-45.523 v1(34.777,-45.4)
LT8912B_D1_P: U16.13 U17.3 | length 54.6
  1-TOP w0.15: v1(25.8,-54.977) 25.8,-54.954 25.9,-54.854 26.173,-54.854 26.446,-54.854 26.827,-54.473 26.827,-53.873 26.9,-53.8 U16.13@26.9,-53.345 ; v1(34.177,-45.4) 34.3,-45.277 34.3,-44.576 34.024,-44.3 30.731,-44.3 30.321,-43.89 30.321,-42.989 30.764,-42.546 34.128,-42.546 34.446,-42.228 34.446,-35.954 37.877,-32.523 45.972,-32.523 U17.3@45.995,-32.5
  8-BOTTOM w0.15: v1(25.8,-54.977) 25.677,-54.854 25.053,-54.854 24.746,-54.547 24.746,-53.454 25.454,-52.746 31.254,-52.746 31.746,-52.254 31.746,-51.654 32.1,-51.3 32.937,-51.3 33.3,-51.663 33.3,-52.972 33.574,-53.246 34.082,-53.246 34.3,-53.028 34.3,-45.523 v1(34.177,-45.4)
LT8912B_D2_N: U15.14 U17.10 | length 54.6
  1-TOP w0.15: v1(17.277,-57.6) 17.4,-57.477 17.4,-56.823 18.223,-56 18.223,-55.323 18.2,-55.3 U15.14@18.2,-54.745 ; v1(38.123,-40) 38,-39.877 38,-37.85 40.573,-35.277 43.6,-35.277 45.972,-35.277 U17.10@45.995,-35.3
  8-BOTTOM w0.15: v1(17.277,-57.6) 17.4,-57.723 17.4,-58.501 19.453,-60.554 ; 19.479,-60.554 30.721,-60.554 39.6,-51.675 39.6,-42.099 38,-40.499 38,-40.123 v1(38.123,-40)
LT8912B_D2_P: U15.15 U17.9 | length 54.6
  1-TOP w0.15: v1(17.877,-57.6) 17.754,-57.477 17.754,-56.97 18.577,-56.147 18.577,-55.323 18.6,-55.3 U15.15@18.6,-54.745 ; v1(37.523,-40) 37.646,-39.877 37.646,-38.605 37.558,-38.517 37.33,-38.517 37.26,-38.447 37.26,-38.237 37.33,-38.167 37.558,-38.167 37.646,-38.079 37.646,-37.9 37.646,-37.703 40.426,-34.923 45.972,-34.923 U17.9@45.995,-34.9
  8-BOTTOM w0.15: v1(17.877,-57.6) 17.754,-57.723 17.754,-58.354 19.6,-60.2 ; 19.626,-60.2 30.574,-60.2 39.246,-51.528 39.246,-42.246 37.646,-40.646 37.646,-40.123 v1(37.523,-40)
LT8912B_D3_N: U15.12 U17.12 | length 54.5
  1-TOP w0.15: v1(16.154,-56.223) 16.154,-56.246 16.254,-56.346 16.654,-56.346 17.3,-55.7 U15.12@17.3,-54.5 ; v1(38.177,-42.423) 38.054,-42.3 38.054,-41.447 39.4,-40.101 39.4,-37.8 41.123,-36.077 41.475,-36.077 41.8,-36.077 41.9,-36.077 41.988,-36.165 41.988,-36.524 42.04,-36.577 42.285,-36.577 42.338,-36.524 42.338,-36.129 42.39,-36.077 42.635,-36.077 42.688,-36.129 42.688,-36.396 42.74,-36.449 42.985,-36.449 43.038,-36.396 43.038,-36.165 43.126,-36.077 43.175,-36.077 43.25,-36.077 44.022,-36.077 45.972,-36.077 U17.12@45.995,-36.1
  8-BOTTOM w0.15: v1(16.154,-56.223) 16.031,-56.346 15.446,-56.346 15.3,-56.2 15.3,-54.7 16.466,-53.534 20.291,-53.534 20.904,-52.921 20.904,-50.497 21.347,-50.054 29.296,-50.054 30.954,-48.396 30.954,-44.922 31.747,-44.129 33.972,-44.129 34.4,-43.701 34.4,-42.32 34.566,-42.154 35.466,-42.154 35.646,-42.334 35.646,-43.747 36.028,-44.129 37.572,-44.129 38.054,-43.647 38.054,-42.546 v1(38.177,-42.423)
LT8912B_D3_P: U15.13 U17.11 | length 54.6
  1-TOP w0.15: v1(16.154,-56.823) 16.154,-56.8 16.254,-56.7 16.801,-56.7 17.654,-55.847 17.654,-55.446 17.8,-55.3 U15.13@17.8,-54.745 ; v1(37.577,-42.423) 37.7,-42.3 37.7,-41.3 39.046,-39.954 39.046,-37.653 40.976,-35.723 45.972,-35.723 U17.11@45.995,-35.7
  8-BOTTOM w0.15: v1(16.154,-56.823) 16.031,-56.7 15.299,-56.7 14.946,-56.347 14.946,-54.553 16.319,-53.18 20.144,-53.18 20.55,-52.774 20.55,-50.35 21.2,-49.7 29.149,-49.7 30.6,-48.249 30.6,-44.775 31.6,-43.775 33.825,-43.775 34.046,-43.554 34.046,-42.174 34.42,-41.8 35.613,-41.8 36,-42.187 36,-43.6 36.175,-43.775 37.425,-43.775 37.7,-43.5 37.7,-42.546 v1(37.577,-42.423)
LT8912B_INT_1V8: Q4.S R133.1 R135.1 U17.63 | length 14.5
  1-TOP w0.15: Q4.S@43.655,-22.85 Q4.S@43.685,-22.88
  1-TOP w0.2: R133.1@42.305,-22.48 42.685,-22.48 43.005,-22.8 Q4.S@43.605,-22.8 ; Q4.S@43.685,-22.88 R135.1@47.405,-22.88 47.88,-22.88 48,-23 48,-25.7 46.705,-26.995 46.705,-29.9 47.1,-30.295 U17.63@47.1,-30.995
LT8912B_INT_3V3: Q4.D R134.1 R135.2 U7.V1 | length 59.1
  1-TOP w0.2: U7.V1@1.27,-17.78 1.3,-17.81 v1(1.3,-24.3) ; Q4.D@45.735,-21.68 Q4.D@45.955,-21.9 ; Q4.D@46.005,-21.95 R135.2@47.375,-21.95 ; v1(46.2,-20.8) R134.1@47.42,-20.8 R135.2@47.42,-21.905
  1-TOP w0.3: R135.2@47.375,-21.95 R135.2@47.405,-21.92 R135.2@47.42,-21.905
  3-INTOP w0.2: v1(1.3,-24.3) 5.8,-24.3 8.4,-26.9 32.2,-26.9 34.8,-24.3 42.1,-24.3 45.6,-20.8 v1(46.2,-20.8)
LT8912B_RST_1V8: Q5.S R122.2 R136.1 R138.1 U17.64 | length 8.5
  1-TOP w0.2: R136.1@42.305,-25.88 42.685,-25.88 43.005,-26.2 Q5.S@43.605,-26.2 ; Q5.S@43.655,-26.25 43.655,-28.355 44.08,-28.78 R138.1@44.8,-28.78 R122.2@45.9,-28.78 ; R122.2@45.885,-28.8 45.885,-29.58 46.7,-30.395 U17.64@46.7,-30.995
LT8912B_RST_3V3: Q5.D R137.1 R138.2 U7.W1 | length 56.8
  1-TOP w0.2: v1(2.5,-24.8) 2.5,-17.82 U7.W1@2.54,-17.78 ; v1@44.7,-27.2 v1(44.8,-27.1) ; R138.2@44.8,-27.82 v1(44.8,-27.1) ; R137.1@47.305,-25.38 47.225,-25.3 Q5.D@45.955,-25.3 45.885,-25.37 45.885,-26.015 v1(44.8,-27.1)
  3-INTOP w0.2: v1(2.5,-24.8) 7.2,-29.5 41.1,-29.5 43.5,-27.1 v1(44.8,-27.1)
LT8912B_SCL: R189.2 U17.62 | length 72.1
  1-TOP w0.2: U17.62@47.5,-30.995 47.5,-30.095 47.205,-29.8 47.205,-27.195 48.5,-25.9 48.5,-22.534 49.434,-21.6 v1(53.4,-21.6) ; v1(68.1,23.7) R189.2@68.1,24.32
  6-INBOT w0.15: v1(53.4,-21.6) 56,-21.6 56.9,-20.7 56.9,-15.6 60.9,-11.6 67.5,-11.6 68.4,-10.7 68.4,14.7 68.1,15 v1(68.1,23.7)
LT8912B_SDA: R191.2 U17.61 | length 77.3
  1-TOP w0.2: U17.61@47.9,-30.995 47.9,-29.895 47.605,-29.6 47.605,-27.361 48.9,-26.066 48.9,-22.7 49.5,-22.1 v1(54,-22.1) ; R191.2@68.1,28.08 v1(68.1,28.7)
  6-INBOT w0.15: v1(54,-22.1) 56.1,-22.1 57.3,-20.9 57.3,-15.8 61.1,-12 67.666,-12 68.9,-10.766 68.9,12.1 68.9,15.3 68.7,15.5 68.7,25.6 68.1,26.2 v1(68.1,28.7)
LVDS_CLK_N: L15.1 U7.AJ19 | length 75
  1-TOP w0.15: L15.1@-1.725,-58.05 -1.627,-57.952 -1.627,-57.027 -0.7,-56.1 -0.7,-55.4 -1.627,-54.473 -1.627,-44.026 16.3,-26.099 16.3,-25.623 v1(16.177,-25.5) ; U7.AJ19@15.24,5.08 v1(15.875,5.715)
  8-BOTTOM w0.15: v1(15.875,5.715) 15.875,5.332 15.8,5.257 15.153,5.257 14.746,4.85 14.746,2.853 15.253,2.346 16.2,2.346 16.3,2.246 16.3,-25.377 v1(16.177,-25.5)
LVDS_CLK_P: L15.4 U7.AJ18 | length 75
  1-TOP w0.15: L15.4@-1.175,-58.05 -1.273,-57.952 -1.273,-57.174 -0.346,-56.247 -0.346,-55.253 -1.273,-54.326 -1.273,-44.173 16.654,-26.246 16.654,-25.623 v1(16.777,-25.5) ; U7.AJ18@15.24,3.81 v1(15.875,4.445)
  8-BOTTOM w0.15: v1(15.875,4.445) 15.875,4.828 15.8,4.903 15.3,4.903 15.1,4.703 15.1,3 15.4,2.7 16.347,2.7 16.654,2.393 16.654,2.1 16.742,2.012 16.972,2.012 17.042,1.942 17.042,1.732 16.972,1.662 16.742,1.662 16.654,1.574 16.654,-25.377 v1(16.777,-25.5)
LVDS_D0_N: L12.1 U7.AJ15 | length 75
  1-TOP w0.15: L12.1@-12.975,-58.05 -12.877,-57.952 -12.877,-52.123 -13.354,-51.646 -13.354,-49.254 -12.3,-48.2 -10.201,-48.2 9.954,-28.045 9.954,-25.146 11.6,-23.5 14.2,-23.5 15.08,-22.62 15.08,-22.246 v1(14.957,-22.123) ; v1(14.605,-0.635) U7.AJ15@15.24,0
  8-BOTTOM w0.15: v1(14.605,-0.635) 14.605,-0.252 14.68,-0.177 14.957,-0.177 15.08,-0.3 15.08,-5.421 14.992,-5.509 14.764,-5.509 14.694,-5.579 14.694,-5.789 14.764,-5.859 14.992,-5.859 15.08,-5.947 15.08,-22 v1(14.957,-22.123)
LVDS_D0_P: L12.4 U7.AJ16 | length 75
  1-TOP w0.15: L12.4@-12.425,-58.05 -12.523,-57.952 -12.523,-51.976 -13,-51.499 -13,-49.401 -12.153,-48.554 -10.054,-48.554 10.308,-28.192 10.308,-25.293 11.747,-23.854 14.347,-23.854 15.434,-22.767 15.434,-22.246 v1(15.557,-22.123) ; v1(14.605,0.635) U7.AJ16@15.24,1.27
  8-BOTTOM w0.15: v1(14.605,0.635) 14.605,0.252 14.68,0.177 15.104,0.177 15.434,-0.153 15.434,-22 v1(15.557,-22.123)
LVDS_D1_N: L13.1 U7.AK15 | length 74.9
  1-TOP w0.15: L13.1@-9.225,-57.95 -9.127,-57.852 -9.127,-48.626 11,-28.499 11,-25.499 12.153,-24.346 13.618,-24.346 14.125,-24.853 14.125,-25.377 v1(14.248,-25.5) ; v1(15.875,0.635) U7.AK15@16.51,0
  8-BOTTOM w0.15: v1(14.248,-25.5) 14.125,-25.377 14.125,0.925 14.293,1.093 15.8,1.093 15.875,1.018 v1(15.875,0.635)
LVDS_D1_P: L13.4 U7.AK16 | length 74.9
  1-TOP w0.15: L13.4@-8.675,-57.95 -8.773,-57.852 -8.773,-48.773 11.354,-28.646 11.354,-25.646 12.3,-24.7 13.471,-24.7 13.771,-25 13.771,-25.377 v1(13.648,-25.5) ; v1(15.875,1.905) U7.AK16@16.51,1.27
  8-BOTTOM w0.15: v1(13.648,-25.5) 13.771,-25.377 13.771,-2.643 13.701,-2.573 13.465,-2.573 13.395,-2.503 13.395,-2.293 13.465,-2.223 13.701,-2.223 13.771,-2.153 13.771,1.072 14.146,1.447 15.8,1.447 15.875,1.522 v1(15.875,1.905)
LVDS_D2_N: L14.1 U7.AH16 | length 75
  1-TOP w0.15: L14.1@-5.475,-58.05 -5.377,-57.952 -5.377,-56.576 -4.947,-56.146 -3.195,-56.146 -2.954,-55.905 -2.954,-55.405 -3.259,-55.1 -4.766,-55.1 -5.3,-54.566 -5.3,-53.518 -4.828,-53.046 -3.446,-53.046 -3.2,-52.8 -3.2,-52.1 -3.4,-51.9 -4.851,-51.9 -5.377,-51.374 -5.377,-47.477 -5.377,-46.376 12.506,-28.493 12.506,-25.623 v1(12.383,-25.5) ; v1(13.335,0.635) U7.AH16@13.97,1.27
  8-BOTTOM w0.15: v1(12.383,-25.5) 12.506,-25.377 12.506,-0.153 12.836,0.177 13.26,0.177 13.335,0.252 v1(13.335,0.635)
LVDS_D2_P: L14.4 U7.AH15 | length 75
  1-TOP w0.15: L14.4@-4.925,-58.05 -5.023,-57.952 -5.023,-56.723 -4.8,-56.5 -3.048,-56.5 -2.6,-56.052 -2.6,-55.258 -3.112,-54.746 -4.619,-54.746 -4.946,-54.419 -4.946,-53.665 -4.681,-53.4 -3.299,-53.4 -2.846,-52.947 -2.846,-51.953 -3.253,-51.546 -4.704,-51.546 -5.023,-51.227 -5.023,-46.523 12.86,-28.64 12.86,-25.623 v1(12.983,-25.5) ; v1(13.335,-0.635) U7.AH15@13.97,0
  8-BOTTOM w0.15: v1(12.983,-25.5) 12.86,-25.377 12.86,-4.108 12.948,-4.02 13.173,-4.02 13.243,-3.95 13.243,-3.74 13.173,-3.67 12.93,-3.67 12.86,-3.6 12.86,-0.3 12.983,-0.177 13.26,-0.177 13.335,-0.252 v1(13.335,-0.635)
LVDS_D3_N: L16.1 U7.AK19 | length 75
  1-TOP w0.15: L16.1@2.025,-58.05 2.123,-57.952 2.123,-56.876 2.599,-56.4 3.4,-56.4 3.7,-56.1 3.7,-55.5 3.4,-55.2 2.575,-55.2 1.971,-54.596 1.971,-41.828 17.6,-26.199 v1@17.6,-25.623 ; U7.AK19@16.51,5.08 v1(17.145,5.715) ; v1(17.477,-25.5) 17.5,-25.5 v1@17.6,-25.6
  8-BOTTOM w0.15: v1(17.145,5.715) 17.145,5.332 17.07,5.257 16.653,5.257 16.346,4.95 16.346,4.153 16.853,3.646 17.454,3.646 17.6,3.5 17.6,-25.377 v1(17.477,-25.5)
LVDS_D3_P: L16.4 U7.AK18 | length 75
  1-TOP w0.15: L16.4@2.575,-58.05 2.477,-57.952 2.477,-57.023 2.746,-56.754 3.547,-56.754 4.054,-56.247 4.054,-55.353 3.547,-54.846 2.722,-54.846 2.325,-54.449 2.325,-41.975 17.954,-26.346 v1@17.954,-25.623 ; U7.AK18@16.51,3.81 v1(17.145,4.445) ; v1@17.954,-25.6 18.054,-25.5 v1(18.077,-25.5)
  8-BOTTOM w0.15: v1(17.145,4.445) 17.145,4.828 17.07,4.903 16.8,4.903 16.7,4.803 16.7,4.3 17,4 17.601,4 17.954,3.647 17.954,-4.249 18.042,-4.337 18.269,-4.337 18.339,-4.407 18.339,-4.617 18.269,-4.687 18.042,-4.687 17.954,-4.775 17.954,-25.377 v1(18.077,-25.5)
LVDS_I2C_SCL: J31.17 R178.2 | length 117.9
  1-TOP w0.2: J31.17@5.425,-61.2 5.5,-61.125 v1(5.5,-59.8) ; R178.2@65.2,20.18 v1(65.2,20.8)
  6-INBOT w0.15: v1(5.5,-59.8) 6.1,-59.2 10.8,-59.2 11.6,-58.4 11.6,-49.2 19.5,-41.3 32.8,-41.3 34.346,-39.754 34.346,-33.754 61.3,-6.8 61.3,-5.3 64.1,-2.5 64.1,13.107 64.7,13.707 64.7,17.9 65.2,18.4 v1(65.2,20.8)
LVDS_I2C_SDA: J31.18 R182.2 | length 112.8
  1-TOP w0.2: v1(6.6,-59.8) 6.6,-61.125 J31.18@6.675,-61.2 ; v1(65.2,16.5) R182.2@65.2,17.12
  6-INBOT w0.15: v1(6.6,-59.8) 10.8,-59.8 12.1,-58.5 12.1,-49.4 19.846,-41.654 32.946,-41.654 34.7,-39.9 34.7,-33.9 61.8,-6.8 61.8,-5.5 64.6,-2.7 64.6,12.9 65.2,13.5 v1(65.2,16.5)
LVDS_IRQ_N: J31.19 R118.2 U7.C24 | length 119.5
  1-TOP w0.2: U7.C24@-17.78,11.43 v1(-17.145,12.065) ; v1(7,-58.2) 7,-58.9 7.28,-59.18 R118.2@7.8,-59.18 7.8,-61.075 J31.19@7.925,-61.2
  3-INTOP w0.15: v1(-17.145,12.065) -17.8,12.72 -17.8,16.2 -17.5,16.5 -13.2,16.5 -12.7,17 -12.7,17.5 -11.3,18.9 11.3,18.9 12.7,17.5 12.7,-19.9 12.7,-20 v1(11.8,-20.9)
  6-INBOT w0.15: v1(7,-58.2) 7,-43.2 11.4,-38.8 11.4,-21.3 v1(11.8,-20.9)
LVDS_PWM_OUT: J31.16 U7.E27 | length 112.1
  1-TOP w0.2: v1(-15.875,15.875) U7.E27@-15.24,15.24 ; J31.16@4.175,-61.2 4.2,-61.175 v1(4.2,-59.4)
  3-INTOP w0.15: v1(-15.875,15.875) -15.2,15.2 -11.8,15.2 -11.5,15.5 -11.5,17.1 -10.8,17.8 10.7,17.8 11.5,17 11.5,-16.8 v1(9.1,-19.2)
  6-INBOT w0.15: v1(4.2,-59.4) 4.2,-49.3 5.3,-48.2 5.3,-39.3 9.1,-35.5 v1(9.1,-19.2)
MCA_CLKOUT32K: J42.1 U7.AL21 | length 72.1
  1-TOP w0.2: U7.AL21@17.78,7.62 v1(18.415,8.255)
  6-INBOT w0.2: v1(18.415,8.255) 19.07,7.6 26.7,7.6 31.1,12 31.1,25.7 36.9,31.5 36.9,44.8 42.35,50.25 45,52.9 45,59.7 44.23,60.47 J42.1@42.33,60.47
MCA_IO9: J42.11 U7.AG29 | length 60.1
  1-TOP w0.2: U7.AG29@12.7,17.78 v1(12.7,37.7)
  3-INTOP w0.2: v1(12.7,37.7) v1(28.6,37.7)
  6-INBOT w0.2: v1(28.6,37.7) 28.6,40 30,41.4 30,55.4 30.9,56.3 30.9,59.2 J42.11@29.63,60.47
MCA_IO10: J42.13 U7.AF29 | length 60.3
  1-TOP w0.2: U7.AF29@11.43,17.78 11.43,38.13 v1(12,38.7)
  3-INTOP w0.2: v1(12,38.7) 16.7,38.7 17.3,39.3 v1(28.1,39.3)
  6-INBOT w0.2: J42.13@27.09,60.47 28.4,59.16 28.4,52 29.5,50.9 29.5,41.6 28.1,40.2 v1(28.1,39.3)
MCA_IO11: J42.15 U7.AM26 | length 52.5
  1-TOP w0.2: U7.AM26@19.05,13.97 v1(19.685,14.605)
  6-INBOT w0.2: v1(19.685,14.605) 19.685,19.385 27.6,27.3 27.6,40.4 29,41.8 29,49.5 25.8,52.7 25.8,59.22 J42.15@24.55,60.47
MCA_IO12: J42.17 U7.AM25 | length 54.9
  1-TOP w0.2: U7.AM25@19.05,12.7 v1(19.685,13.335)
  6-INBOT w0.2: v1(19.685,13.335) 19.05,13.97 19.05,19.45 27.1,27.5 27.1,40.6 28.5,42 28.5,49.207 23.3,54.407 23.3,59.18 J42.17@22.01,60.47
MCA_IO13: J42.19 U7.AL22 | length 62.3
  1-TOP w0.2: v1(17.145,8.255) U7.AL22@17.78,8.89
  6-INBOT w0.2: v1(17.145,8.255) 15.7,9.7 15.7,16.807 26.6,27.707 26.6,40.807 28,42.207 28,49 20.7,56.3 20.7,59.24 J42.19@19.47,60.47
MCA_IO14: J42.2 U7.AL26 | length 72.4
  1-TOP w0.2: v1(17.145,14.605) U7.AL26@17.78,13.97
  6-INBOT w0.2: v1(17.145,14.605) 16.2,13.66 16.2,10 17.4,8.8 26.6,8.8 30.6,12.8 30.6,25.9 36.395,31.695 36.395,44.995 41.1,49.7 41.1,54 42.33,55.23 J42.2@42.33,57.93
MCA_IO15: J42.4 U7.AL25 | length 69.4
  1-TOP w0.2: U7.AL25@17.78,12.7 v1(18.415,13.335)
  6-INBOT w0.2: v1(18.415,13.335) 17.78,12.7 17,12.7 16.6,12.3 16.6,10.4 17.7,9.3 26.3,9.3 30.1,13.1 30.1,26.1 35.9,31.9 35.9,45.2 38.5,47.8 38.5,54.41 39.79,55.7 J42.4@39.79,57.93
MCA_IO16: J42.6 U7.AL24 | length 64
  1-TOP w0.2: U7.AL24@17.78,11.43 v1(18.415,12.065)
  6-INBOT w0.2: v1(18.415,12.065) 17.8,11.45 17.8,10.5 18.5,9.8 26,9.8 29.6,13.4 29.6,26.3 35.4,32.1 35.4,45.4 36.2,46.2 36.2,55.2 37.25,56.25 J42.6@37.25,57.93
MCA_IO17: J42.8 U7.AL23 | length 60.6
  1-TOP w0.2: U7.AL23@17.78,10.16 v1(18.415,10.795)
  6-INBOT w0.2: v1(18.415,10.795) 18.91,10.3 25.7,10.3 29.1,13.7 29.1,26.5 34.9,32.3 34.9,45.6 35.7,46.4 35.7,55.2 34.71,56.19 J42.8@34.71,57.93
MCA_IO18: J42.10 U7.AM23 | length 53.9
  1-TOP w0.2: U7.AM23@19.05,10.16 v1(19.685,10.795)
  6-INBOT w0.2: v1(19.685,10.795) 21.7,12.81 21.7,20 33,31.3 33,53.1 32.17,53.93 J42.10@32.17,57.93
MCA_UART_CTS: J42.7 U7.AN23 | length 57.3
  1-TOP w0.2: U7.AN23@20.32,10.16 v1(20.955,10.795)
  8-BOTTOM w0.15: v1(20.955,10.795) 20.955,18.491 35.5,33.036 35.5,55.672 36,56.172 36,59.18 J42.7@34.71,60.47
MCA_UART_RTS: J42.9 U7.AL27 | length 53.9
  1-TOP w0.15: U7.AL27@17.78,15.24 18.5,15.96 v1(18.5,17.3)
  8-BOTTOM w0.15: v1(18.5,17.3) 19,17.3 35.055,33.355 35.055,52.945 33.4,54.6 33.4,59.24 J42.9@32.17,60.47
MCA_UART_RX: J42.5 U7.AN22 | length 60
  1-TOP w0.2: U7.AN22@20.32,8.89 21.8,10.37 v1(21.8,10.8)
  8-BOTTOM w0.15: v1(21.8,10.8) 21.4,11.2 21.4,18.307 36,32.907 36,54.5 38.5,57 38.5,59.22 J42.5@37.25,60.47
MCA_UART_TX: J42.3 U7.AN21 | length 63.7
  1-TOP w0.2: U7.AN21@20.32,7.62 v1(20.955,6.985)
  8-BOTTOM w0.15: v1(20.955,6.985) 22.5,8.53 22.5,12.4 21.9,13 21.9,18.1 36.5,32.7 36.5,48.955 38.6,51.055 38.6,53.5 41.004,55.904 41.004,59.256 J42.3@39.79,60.47
MCA_VIN_DET: R22.2 U4.1 U7.AM27 | length 101.9
  1-TOP w0.2: U7.AM27@19.05,15.24 19.6,15.79 v1(19.6,38.7) ; U4.1@88.55,49.35 R22.2@90.235,49.35 ; v1(89.4,45.3) 89.4,49.315
  3-INTOP w0.2: v1(19.6,38.7) 29.7,38.7 31.3,40.3 65.4,40.3 70.4,45.3 v1(89.4,45.3)
MCA_VREF_OUT: J47.4 U7.AM24 | length 121.9
  1-TOP w0.2: U7.AM24@19.05,11.43 v1(19.685,12.065)
  3-INTOP w0.2: J47.4@-83.74,19.26 -82.5,20.5 -76.6,20.5 -75.9,21.2 -37.2,21.2 -31,27.4 v1(17.8,27.4)
  8-BOTTOM w0.2: v1(17.8,27.4) 17.8,16.5 19.1,15.2 19.1,12.65 v1(19.685,12.065)
MIC_BIAS: C159.2 L32.2 R165.1 U27.45 | length 9.1
  1-TOP w0.2: R165.1@-69.8,35.02 -68.92,35.02 v1(-68.9,35) -68.1,34.2 U27.45@-67.03,34.2 ; C159.2@-69.2,38.86 v1(-69.2,39.54) L32.2@-69.2,40.22
  8-BOTTOM w0.2: v1(-69.2,39.54) -69.2,38.3 -68.9,38 v1(-68.9,35)
MIC_N: L33.1 R167.1 | length 0.9
  1-TOP w0.2: L33.1@-70.3,41.18 R167.1@-70.3,42.12
MIC_P: L32.1 R166.1 | length 0.9
  1-TOP w0.2: L32.1@-69.2,41.18 R166.1@-69.2,42.12
MIKROBUS_ADC: J39.1 J48.9 | length 273.7
  3-INTOP w0.2: v1@-79.603,-42.697 -78.12,-44.18 -71.827,-44.18 -70.307,-45.7 -61.2,-45.7 -59.7,-47.2 -42.807,-47.2 -41.707,-48.3 -19.007,-48.3 -15.407,-51.9 20.3,-51.9 22.2,-50 26.193,-50 26.893,-50.7 40.4,-50.7 42.8,-48.3 58.8,-48.3 73.6,-33.5 80.8,-33.5 84.3,-30 112.4,-30 114.1,-28.3 114.1,-18.9 112.3,-17.1 J39.1@112.3,-4.725
  8-BOTTOM w0.2: J48.9@-81.2,-1.86 -79.6,-3.46 v1(-79.6,-42.7)
MIKROBUS_I2C_SCL: J40.5 R48.2 | length 76.6
  1-TOP w0.2: R48.2@68.2,20.18 68.2,20.7 68.5,21 74.4,21 74.8,21.4 88.2,21.4 89.1,20.5 v1(92.3,20.5)
  6-INBOT w0.2: v1(92.3,20.5) 92.3,-7.893 101,-16.593 101,-25.585 J40.5@102.14,-26.725
MIKROBUS_I2C_SDA: J40.6 R49.2 | length 70.4
  1-TOP w0.2: R49.2@68.2,17.12 68.2,16.5 68.4,16.3 72.2,16.3 73.8,14.7 v1(91.8,14.7)
  6-INBOT w0.2: v1(91.8,14.7) 91.8,-8.1 100.5,-16.8 100.5,-25.825 J40.6@99.6,-26.725
MIKROBUS_INT: J40.2 R50.1 U7.N29 | length 166.9
  1-TOP w0.2: v1(-5.1,21) -5.1,17.8 U7.N29@-5.08,17.78 ; v1(108.5,18.6) 108.5,-6.8 109.76,-8.06 J40.2@109.76,-26.725 109.76,-28.78 R50.1@109.78,-28.8
  3-INTOP w0.2: v1(-5.1,21) 60.8,21 61.8,20 74.3,20 75.7,21.4 99.8,21.4 102.6,18.6 v1(108.5,18.6)
MIKROBUS_PWM: J40.1 J48.10 | length 252.6
  3-INTOP w0.2: v1(-79.1,-42) -77.42,-43.68 -71.62,-43.68 -70.1,-45.2 -60.993,-45.2 -59.493,-46.7 -42.6,-46.7 -41.5,-47.8 -18.8,-47.8 -15.2,-51.4 20.093,-51.4 21.993,-49.5 26.4,-49.5 27.1,-50.2 40.193,-50.2 42.593,-47.8 58.593,-47.8 73.393,-33 80.593,-33 84.093,-29.5 111.1,-29.5 112.3,-28.3 J40.1@112.3,-26.725
  8-BOTTOM w0.2: J48.10@-83.74,-1.86 -82.48,-0.6 -80.7,-0.6 -79.1,-2.2 v1(-79.1,-42)
MIKROBUS_RST: J39.2 U7.Y1 | length 130.3
  1-TOP w0.15: v1(3.8,-30.7) 3.8,-17.79 U7.Y1@3.81,-17.78
  3-INTOP w0.2: v1(3.8,-30.7) 50.4,-30.7 51.2,-31.5 78.4,-31.5 98.8,-11.1 103.385,-11.1 J39.2@109.76,-4.725
MIKROBUS_UART_RX: J40.4 J62.3 | length 171.5
  3-INTOP w0.2: J62.3@-54.62,-17.7 -51.12,-21.2 v1(-41.7,-21.2) ; v1(-38.8,-29.3) 1.4,-29.3 3.3,-31.2 44.7,-31.2 46.8,-33.3 52.393,-33.3 53.693,-32 80.037,-32 83.637,-28.4 103.005,-28.4 J40.4@104.68,-26.725
  6-INBOT w0.2: v1(-41.7,-21.2) -41.7,-26.4 v1(-38.8,-29.3)
MIKROBUS_UART_TX: J40.3 J61.3 | length 173.3
  3-INTOP w0.2: J61.3@-54.62,-20.6 -52.5,-20.6 -51.4,-21.7 v1(-42.189,-21.7) ; v1(-39.3,-29.8) 1.193,-29.8 3.093,-31.7 44.493,-31.7 46.593,-33.8 52.6,-33.8 53.9,-32.5 80.244,-32.5 83.844,-28.9 105.045,-28.9 J40.3@107.22,-26.725
  6-INBOT w0.2: v1(-42.189,-21.7) -42.189,-26.911 v1(-39.3,-29.8)
MIPI_CSI1_CLK_N: J30.8 U7.AM14 | length 82.9
  1-TOP w0.15: U7.AM14@19.05,-1.27 v1(19.685,-1.905) ; J30.8@56,57.15 56,57.775 56.787,58.562 56.912,58.562 57.023,58.451 57.023,55.3 56.875,55.152 v1(56.875,55.057)
  8-BOTTOM w0.15: v1(19.685,-1.905) 20.143,-2.363 21.55,-2.363 21.625,-2.363 21.713,-2.275 21.713,-1.95 21.8,-1.863 21.975,-1.863 22.063,-1.95 22.063,-2.276 22.15,-2.363 22.325,-2.363 22.413,-2.276 22.413,-2.174 22.5,-2.087 22.675,-2.087 22.763,-2.174 22.763,-2.275 22.851,-2.363 23.125,-2.363 23.437,-2.363 44.2,18.4 44.2,41.701 57.023,54.524 57.023,54.909 v1(56.875,55.057)
MIPI_CSI1_CLK_P: J30.7 U7.AM13 | length 82.8
  1-TOP w0.15: U7.AM13@19.05,-2.54 v1(19.685,-3.175) ; J30.7@57,60.8 57,58.973 57.377,58.596 57.377,55.3 57.525,55.152 v1(57.525,55.057)
  8-BOTTOM w0.15: v1(19.685,-3.175) 20.143,-2.717 23.584,-2.717 44.554,18.253 44.554,41.554 57.377,54.377 57.377,54.909 v1(57.525,55.057)
MIPI_CSI1_DATA0_N: J30.14 U7.AL16 | length 82.9
  1-TOP w0.15: U7.AL16@17.78,1.27 v1(18.415,1.905) ; J30.14@50,57.15 50,57.775 50.787,58.562 50.912,58.562 51.023,58.451 51.023,55.3 50.875,55.152 v1(50.875,55.057)
  8-BOTTOM w0.15: v1(18.415,1.905) 18.873,1.447 19.675,1.447 19.75,1.447 19.838,1.535 19.838,1.86 19.925,1.947 20.1,1.947 20.188,1.86 20.188,1.534 20.275,1.447 20.45,1.447 20.538,1.534 20.538,1.635 20.625,1.722 20.8,1.722 20.888,1.635 20.888,1.535 20.976,1.447 21.15,1.447 23.047,1.447 41.3,19.7 41.3,46.001 46.021,50.722 46.021,53.871 46.504,54.354 47.247,54.354 47.754,53.847 47.754,52.946 48.2,52.5 50.1,52.5 51.023,53.423 51.023,54.909 v1(50.875,55.057)
MIPI_CSI1_DATA0_P: J30.13 U7.AL15 | length 82.8
  1-TOP w0.15: U7.AL15@17.78,0 v1(18.415,0.635) ; J30.13@51,60.8 51,58.973 51.377,58.596 51.377,55.3 51.525,55.152 v1(51.525,55.057)
  8-BOTTOM w0.15: v1(18.415,0.635) 18.873,1.093 23.194,1.093 41.654,19.553 41.654,45.854 46.375,50.575 46.375,53.724 46.651,54 47.1,54 47.4,53.7 47.4,52.799 48.053,52.146 50.247,52.146 51.377,53.276 51.377,54.909 v1(51.525,55.057)
MIPI_CSI1_DATA1_N: J30.11 U7.AL13 | length 82.8
  1-TOP w0.15: U7.AL13@17.78,-2.54 v1(18.415,-1.905) ; v1(52.475,55.057) 52.475,55.152 52.623,55.3 52.623,58.596 53,58.973 J30.11@53,60.8
  8-BOTTOM w0.15: v1(18.415,-1.905) 18.415,-2.288 18.49,-2.363 18.8,-2.363 18.9,-2.263 18.9,-1.299 19.353,-0.846 20.704,-0.846 20.725,-0.825 21.25,-0.825 21.271,-0.846 22.554,-0.846 42.7,19.3 42.7,44.951 47.303,49.554 50.254,49.554 52.623,51.923 52.623,54.909 v1(52.475,55.057)
MIPI_CSI1_DATA1_P: J30.10 U7.AL12 | length 82.9
  1-TOP w0.15: U7.AL12@17.78,-3.81 v1(18.415,-3.175) ; v1(53.125,55.057) 53.125,55.152 52.977,55.3 52.977,58.451 53.088,58.562 53.213,58.562 54,57.775 J30.10@54,57.15
  8-BOTTOM w0.15: v1(18.415,-3.175) 18.415,-2.792 18.49,-2.717 18.947,-2.717 19.254,-2.41 19.254,-1.446 19.5,-1.2 22.701,-1.2 43.054,19.153 43.054,44.804 47.45,49.2 48.8,49.2 50.401,49.2 52.977,51.776 52.977,52.277 52.977,52.424 52.977,54.909 v1(53.125,55.057)
MIPI_CSI1_I2C_SCL: J30.3 R184.2 | length 41.9
  1-TOP w0.2: v1(61,55.3) J30.3@61,60.8 ; R184.2@64.2,20.18 v1(64.2,20.8)
  6-INBOT w0.2: v1(61,55.3) 61,54.793 63.3,52.493 63.3,23.9 64.2,23 v1(64.2,20.8)
MIPI_CSI1_I2C_SDA: J30.2 R186.2 | length 42.7
  1-TOP w0.2: v1(62,55.3) J30.2@62,57.15 ; v1(64.2,16.5) R186.2@64.2,17.12
  6-INBOT w0.2: v1(62,55.3) 62,54.5 63.8,52.7 63.8,24.1 64.7,23.2 64.7,19.5 64.2,19 v1@64.2,16.4
MIPI_CSI1_RESET_N: J30.5 U7.E28 | length 147.2
  1-TOP w0.2: v1(-23.9,13.9) -23.1,13.9 -19.9,17.1 -15.83,17.1 U7.E28@-15.24,16.51 ; v1(59,50.9) J30.5@59,60.8
  3-INTOP w0.2: v1(-30.8,46.4) -2.9,46.4 1.2,50.5 58.6,50.5 v1(59,50.9)
  6-INBOT w0.2: v1(-30.8,46.4) -30.8,43.1 -23.9,36.2 v1(-23.9,13.9)
MIPI_DSI1_CLK_N: U7.AN6 U15.2 | length 78.8
  1-TOP w0.15: U15.2@19.4,-52.255 19.423,-52.232 19.423,-51.376 21.1,-49.699 21.1,-48.101 20.046,-47.047 20.046,-26.779 20.623,-26.202 21.725,-25.1 28.079,-25.1 28.246,-24.933 28.246,-24.235 28.065,-24.054 23.182,-24.054 22.8,-23.672 22.8,-22.772 23.172,-22.4 27.98,-22.4 28.146,-22.234 28.146,-21.547 27.953,-21.354 22.853,-21.354 22.546,-21.047 22.546,-20.153 22.899,-19.8 28.2,-19.8 28.846,-19.154 28.846,-13.122 26.696,-10.972 22.475,-10.972 22.4,-10.972 22.312,-11.06 22.312,-11.297 22.26,-11.35 22.015,-11.35 21.962,-11.297 21.962,-11.06 21.874,-10.972 21.325,-10.972 21,-10.972 20.778,-10.972 U7.AN6@20.32,-11.43
MIPI_DSI1_CLK_P: U7.AN7 U15.1 | length 78.8
  1-TOP w0.15: U15.1@19.8,-52.255 19.777,-52.232 19.777,-51.523 21.454,-49.846 21.454,-47.954 20.4,-46.9 20.4,-26.926 21.872,-25.454 28.226,-25.454 28.6,-25.08 28.6,-24.088 28.212,-23.7 23.328,-23.7 23.154,-23.526 23.154,-22.919 23.319,-22.754 28.127,-22.754 28.5,-22.381 28.5,-21.4 28.1,-21 23,-21 22.9,-20.9 22.9,-20.3 23.046,-20.154 28.347,-20.154 29.2,-19.301 29.2,-12.975 26.843,-10.618 20.778,-10.618 U7.AN7@20.32,-10.16
MIPI_DSI1_DATA0_N: U7.AN9 U16.4 | length 75.6
  1-TOP w0.15: U7.AN9@20.32,-7.62 20.778,-7.162 21.657,-7.162 22.082,-7.162 22.17,-7.25 22.17,-7.478 22.24,-7.548 22.45,-7.548 22.52,-7.478 22.52,-7.25 22.608,-7.162 23.282,-7.162 24.836,-7.162 29.746,-12.072 29.746,-25.753 28.999,-26.5 22.175,-26.5 21.8,-26.875 21.8,-28.595 22.259,-29.054 23.252,-29.054 23.654,-28.652 23.654,-28.246 23.8,-28.1 28.885,-28.1 29.346,-28.561 29.346,-29.454 21.946,-36.854 21.946,-46.477 v1(21.823,-46.6) ; v1(25.8,-48.323) 25.923,-48.2 27.399,-48.2 27.723,-48.524 27.723,-50.832 U16.4@27.7,-50.855
  8-BOTTOM w0.15: v1(21.823,-46.6) v1@21.946,-46.723 ; v1@21.946,-46.661 v1@21.946,-46.723 ; v1(25.8,-48.323) 25.677,-48.2 22.399,-48.2 21.946,-47.747 v1@21.946,-46.723
MIPI_DSI1_DATA0_P: U7.AN10 U16.3 | length 75.5
  1-TOP w0.15: U7.AN10@20.32,-6.35 20.778,-6.808 24.983,-6.808 30.1,-11.925 30.1,-25.9 29.146,-26.854 22.322,-26.854 22.154,-27.022 22.154,-28.448 22.406,-28.7 23.105,-28.7 23.3,-28.505 23.3,-28.099 23.653,-27.746 29.031,-27.746 29.7,-28.415 29.7,-29.601 22.3,-37.001 22.3,-46.477 v1(22.423,-46.6) ; v1(25.8,-47.723) 25.923,-47.846 27.546,-47.846 28.077,-48.377 28.077,-50.832 U16.3@28.1,-50.855
  8-BOTTOM w0.15: v1(22.423,-46.6) 22.3,-46.723 22.3,-47.6 22.546,-47.846 25.677,-47.846 v1(25.8,-47.723)
MIPI_DSI1_DATA1_N: U7.AN12 U16.6 | length 78.8
  1-TOP w0.15: U7.AN12@20.32,-3.81 20.778,-3.352 21.575,-3.352 21.65,-3.352 22.075,-3.352 22.163,-3.44 22.163,-3.673 22.215,-3.726 22.46,-3.726 22.513,-3.673 22.513,-3.44 22.601,-3.352 23,-3.352 23.125,-3.352 23.849,-3.352 24.254,-2.947 24.254,-0.727 24.452,-0.529 25.276,-0.529 25.5,-0.753 25.5,-5.814 25.911,-6.225 26.936,-6.225 27.354,-5.807 27.354,-1.338 27.538,-1.154 28.178,-1.154 28.396,-1.372 28.396,-3.897 28.799,-4.3 30.499,-4.3 30.7,-4.501 30.7,-5.7 30.7,-29.599 23.146,-37.153 23.146,-45.246 24.1,-46.2 24.1,-49.3 24.5,-49.7 26.5,-49.7 26.923,-50.123 26.923,-50.832 U16.6@26.9,-50.855
MIPI_DSI1_DATA1_P: U7.AN13 U16.5 | length 78.8
  1-TOP w0.15: U7.AN13@20.32,-2.54 20.778,-2.998 23.702,-2.998 23.9,-2.8 23.9,-0.58 24.305,-0.175 25.422,-0.175 25.854,-0.607 25.854,-5.667 26.058,-5.871 26.789,-5.871 27,-5.66 27,-1.192 27.392,-0.8 28.325,-0.8 28.75,-1.225 28.75,-3.75 28.946,-3.946 30.646,-3.946 31.054,-4.354 31.054,-29.746 23.5,-37.3 23.5,-45.099 24.454,-46.053 24.454,-49.153 24.647,-49.346 26.647,-49.346 27.277,-49.976 27.277,-50.832 U16.5@27.3,-50.855
MIPI_DSI1_DATA2_N: U7.AN15 U15.4 | length 75.5
  1-TOP w0.15: U15.4@18.6,-52.255 18.623,-52.232 18.623,-50.876 19.523,-49.976 19.523,-49.7 v1(19.4,-49.577) ; U7.AN15@20.32,0 20.778,0.458 21.325,0.458 21.75,0.458 21.838,0.37 21.838,0.134 21.89,0.081 22.135,0.081 22.188,0.134 22.188,0.37 22.276,0.458 22.475,0.458 22.759,0.458 23.254,0.953 23.254,3.054 23.5,3.3 24.074,3.3 24.3,3.074 24.3,0.899 24.741,0.458 27.966,0.458 31.7,-3.276 31.7,-30.899 24.9,-37.699 24.9,-44.777 v1(24.777,-44.9)
  8-BOTTOM w0.15: v1(19.4,-49.577) 19.523,-49.454 19.523,-46.701 20.724,-45.5 24.7,-45.5 24.9,-45.3 24.9,-45.023 v1(24.777,-44.9)
MIPI_DSI1_DATA2_P: U7.AN16 U15.3 | length 75.5
  1-TOP w0.15: U15.3@19,-52.255 18.977,-52.232 18.977,-51.023 19.877,-50.123 19.877,-49.7 v1(20,-49.577) ; U7.AN16@20.32,1.27 20.778,0.812 22.612,0.812 22.9,1.1 22.9,3.201 23.353,3.654 24.221,3.654 24.654,3.221 24.654,1.046 24.9,0.8 28.125,0.8 32.054,-3.129 32.054,-31.046 25.254,-37.846 25.254,-44.777 v1(25.377,-44.9)
  8-BOTTOM w0.15: v1(20,-49.577) 19.877,-49.454 19.877,-46.848 20.871,-45.854 24.847,-45.854 25.254,-45.447 25.254,-45.023 v1(25.377,-44.9)
MIPI_DSI1_DATA3_N: U7.AN18 U15.6 | length 75.7
  1-TOP w0.15: v1(17.7,-46.777) 17.823,-46.9 U15.6@17.823,-52.255 ; U7.AN18@20.32,3.81 20.778,4.268 21,4.268 21.425,4.268 21.513,4.18 21.513,3.952 21.583,3.882 21.793,3.882 21.863,3.952 21.863,4.18 21.951,4.268 22.5,4.268 25.932,4.268 32.7,-2.5 32.7,-31.799 26.4,-38.099 26.4,-42.577 v1(26.277,-42.7) v1@26.4,-42.823
  8-BOTTOM w0.15: v1(17.7,-46.777) 17.823,-46.654 17.823,-45.953 20.376,-43.4 26.199,-43.4 26.4,-43.199 26.4,-42.823 v1(26.277,-42.7)
MIPI_DSI1_DATA3_P: U7.AN19 U15.5 | length 75.5
  1-TOP w0.15: U15.5@18.177,-52.255 18.177,-46.9 v1(18.3,-46.777) ; U7.AN19@20.32,5.08 20.778,4.622 26.079,4.622 33.054,-2.353 33.054,-31.946 26.754,-38.246 26.754,-42.577 v1(26.877,-42.7)
  8-BOTTOM w0.15: v1(18.3,-46.777) 18.177,-46.654 18.177,-46.1 20.523,-43.754 26.346,-43.754 26.754,-43.346 26.754,-42.823 v1(26.877,-42.7)
MIPI_EXT_CLK_N: J29.33 U15.23 | length 21.1
  1-TOP w0.15: U15.23@20.495,-52.9 21.05,-52.9 21.073,-52.923 21.877,-52.923 v1(22,-52.8) ; v1(30.623,-57.5) 30.6,-57.5 30.5,-57.6 30.5,-58.3 31.6,-59.4 31.6,-60.999 32.277,-61.676 32.277,-62.09 32.35,-62.163 J29.33@32.35,-62.85
  8-BOTTOM w0.15: v1(22,-52.8) 22.123,-52.923 22.523,-52.923 23.054,-53.454 23.054,-56.254 24.6,-57.8 27.699,-57.8 28.853,-56.646 30.146,-56.646 30.5,-57 30.5,-57.377 v1(30.623,-57.5)
MIPI_EXT_CLK_P: J29.32 U15.22 | length 21.1
  1-TOP w0.15: U15.22@20.495,-53.3 21.05,-53.3 21.073,-53.277 21.877,-53.277 v1(22,-53.4) ; v1(30.023,-57.5) 30.046,-57.5 30.146,-57.6 30.146,-58.447 31.246,-59.547 31.246,-61.146 31.923,-61.823 31.923,-62.09 31.85,-62.163 J29.32@31.85,-62.85
  8-BOTTOM w0.15: v1(22,-53.4) 22.123,-53.277 22.376,-53.277 22.7,-53.601 22.7,-54.19 22.7,-54.615 22.612,-54.703 22.377,-54.703 22.325,-54.755 22.325,-55 22.377,-55.053 22.612,-55.053 22.7,-55.141 22.7,-55.282 22.7,-56.401 24.453,-58.154 27.846,-58.154 29,-57 29.999,-57 30.146,-57.147 30.146,-57.377 v1(30.023,-57.5)
MIPI_EXT_DATA0_N: J29.36 U16.21 | length 24.4
  1-TOP w0.15: U16.21@29.595,-52.3 29.618,-52.323 30.2,-52.323 30.4,-52.123 30.4,-48.775 30.875,-48.3 33.606,-48.3 34.025,-48.719 34.025,-50.412 33.637,-50.8 32.5,-50.8 32.3,-51 32.3,-60.3 33.777,-61.777 33.777,-62.09 33.85,-62.163 J29.36@33.85,-62.85
MIPI_EXT_DATA0_P: J29.35 U16.20 | length 24.4
  1-TOP w0.15: U16.20@29.595,-52.7 29.618,-52.677 30.347,-52.677 30.754,-52.27 30.754,-52.171 30.754,-51.746 30.842,-51.658 31.076,-51.658 31.128,-51.605 31.128,-51.36 31.076,-51.308 30.842,-51.308 30.754,-51.22 30.754,-50.976 30.754,-48.922 31.022,-48.654 33.459,-48.654 33.671,-48.866 33.671,-50.266 33.491,-50.446 32.353,-50.446 31.946,-50.853 31.946,-60.447 33.423,-61.924 33.423,-62.09 33.35,-62.163 J29.35@33.35,-62.85
MIPI_EXT_DATA1_N: J29.30 U16.18 | length 21.1
  1-TOP w0.15: U16.18@28.9,-53.345 28.9,-53.9 28.973,-53.973 28.973,-54.347 29.28,-54.654 29.875,-54.654 29.963,-54.742 29.963,-54.833 30.015,-54.885 30.26,-54.885 30.313,-54.833 30.313,-54.742 30.401,-54.654 30.977,-54.654 v1(31.1,-54.777) ; v1(29.4,-56.023) 29.4,-56 29.3,-55.9 29.001,-55.9 28.9,-56.001 28.9,-56.649 28.9,-57.175 28.9,-58.099 30.777,-59.976 30.777,-62.09 30.85,-62.163 J29.30@30.85,-62.85
  8-BOTTOM w0.15: v1(29.4,-56.023) 29.277,-55.9 28.449,-55.9 28,-55.451 28,-54.5 28.4,-54.1 29.401,-54.1 30.5,-55.199 30.5,-55.399 31.047,-55.946 31.544,-55.946 31.85,-55.64 31.85,-54.876 31.662,-54.688 31.189,-54.688 v1(31.1,-54.777)
MIPI_EXT_DATA1_P: J29.29 U16.19 | length 21
  1-TOP w0.15: v1(29.4,-55.423) 29.4,-55.446 29.3,-55.546 28.854,-55.546 28.546,-55.854 28.546,-58.246 30.423,-60.123 30.423,-61.823 30.423,-62.09 30.35,-62.163 J29.29@30.35,-62.85 ; U16.19@29.4,-53.1 29.4,-54.2 29.5,-54.3 30.977,-54.3 v1(31.1,-54.177)
  8-BOTTOM w0.15: v1(29.4,-55.423) 29.277,-55.546 28.596,-55.546 28.354,-55.304 28.354,-54.647 28.547,-54.454 29.254,-54.454 30.146,-55.346 30.146,-55.546 30.9,-56.3 31.69,-56.3 32.204,-55.786 32.204,-54.729 31.809,-54.334 31.257,-54.334 v1(31.1,-54.177)
MIPI_EXT_DATA2_N: R220.2 U15.21 | length 22.7
  1-TOP w0.15: U15.21@20.495,-53.7 20.518,-53.723 21.224,-53.723 22.001,-54.5 23.2,-54.5 23.65,-54.95 23.65,-55.719 22.5,-56.869 22.5,-58.476 21.654,-59.322 21.654,-59.929 21.925,-60.2 22.725,-60.2 23,-59.925 23,-57.9 23.5,-57.4 24.25,-57.4 24.679,-57.829 24.679,-58.228 24.897,-58.446 26.028,-58.446 26.2,-58.274 26.2,-57.925 26.55,-57.575 27.543,-57.575 27.897,-57.929 27.897,-58.296 29.464,-59.863 29.464,-60.384 R220.2@29.5,-60.42
MIPI_EXT_DATA2_P: R221.2 U15.20 | length 22.6
  1-TOP w0.15: U15.20@20.495,-54.1 20.518,-54.077 21.077,-54.077 21.854,-54.854 22.146,-54.854 22.234,-54.942 22.234,-55.281 22.286,-55.333 22.531,-55.333 22.584,-55.281 22.584,-54.942 22.672,-54.854 23.053,-54.854 23.296,-55.097 23.296,-55.572 22.146,-56.722 22.146,-58.329 21.3,-59.175 21.3,-60.076 21.778,-60.554 22.872,-60.554 23.354,-60.072 23.354,-58.047 23.647,-57.754 24.103,-57.754 24.325,-57.976 24.325,-58.375 24.75,-58.8 26.175,-58.8 26.554,-58.421 26.554,-58.071 26.696,-57.929 27.396,-57.929 27.543,-58.075 27.543,-58.443 29,-59.9 R221.2@29,-60.2
MIPI_EXT_DATA3_N: R222.2 U15.18 | length 19.7
  1-TOP w0.15: U15.18@19.8,-54.745 19.8,-55.3 20.35,-55.85 20.449,-55.85 20.537,-55.938 20.537,-56.051 20.59,-56.103 20.835,-56.103 20.887,-56.051 20.887,-55.938 20.975,-55.85 21.373,-55.85 v1(21.5,-55.977) ; v1(21.277,-57.9) 21.154,-58.023 21.154,-58.447 20.647,-58.954 20.097,-58.954 19.9,-59.151 19.9,-59.649 19.9,-60.175 19.9,-60.799 20.201,-61.1 24.499,-61.1 24.8,-60.799 24.8,-59.85 25.304,-59.346 27.27,-59.346 27.554,-59.63 27.554,-60.074 R222.2@27.9,-60.42
  8-BOTTOM w0.15: v1(21.277,-57.9) 21.154,-57.777 21.154,-56.753 20.8,-56.399 20.8,-56.054 21,-55.854 21.377,-55.854 v1(21.5,-55.977)
MIPI_EXT_DATA3_P: R223.2 U15.19 | length 19.4
  1-TOP w0.15: U15.19@20.3,-54.5 20.3,-55.3 20.5,-55.5 21.377,-55.5 v1(21.5,-55.377) ; v1(20.677,-57.9) 20.8,-58.023 20.8,-58.3 20.5,-58.6 19.95,-58.6 19.546,-59.004 19.546,-60.946 20.054,-61.454 24.646,-61.454 25.154,-60.946 25.154,-59.997 25.451,-59.7 27.123,-59.7 27.2,-59.777 27.2,-60.32 R223.2@27.1,-60.42
  8-BOTTOM w0.15: v1(20.677,-57.9) 20.8,-57.777 20.8,-56.9 20.446,-56.546 20.446,-55.907 20.853,-55.5 21.377,-55.5 v1(21.5,-55.377)
MIPI_SWITCH_OE: R116.2 U15.8 U16.8 | length 16.1
  1-TOP w0.2: R116.2@13.7,-52.43 16.03,-52.43 16.5,-52.9 U15.8@17.105,-52.9 ; v1(24.8,-50.7) 25.6,-51.5 U16.8@26.205,-51.5
  3-INTOP w0.2: v1(14.7,-52.4) 21,-52.4 22.7,-50.7 v1(24.8,-50.7)
MIPI_SWITCH_SEL: J28.2 R115.2 R117.1 U15.11 U16.11 | length 23.8
  1-TOP w0.2: J28.2@13.6,-50 12.7,-50.9 12.7,-55.2 13.02,-55.52 R117.1@13.5,-55.52 R115.2@14.5,-55.52 15.18,-55.52 v1(15.9,-54.8) 16.6,-54.1 U15.11@17.105,-54.1 ; v1(24.7,-55.3) 24.7,-53.7 25.7,-52.7 U16.11@26.205,-52.7
  3-INTOP w0.2: v1(15.9,-54.8) 16.6,-54.1 21.3,-54.1 22.5,-55.3 v1(24.7,-55.3)
MUX_3V3_1V8: R38.1 R39.1 R84.2 R85.2 | length 25.5
  1-TOP w0.5: R85.2@-17.62,-55.1 R84.2@-17.62,-53.9 -16.2,-53.9 -15.6,-53.3 -15.6,-49.5 -6.1,-40 R39.1@-6.1,-37.4 ; R38.1@-8.28,-37.38 R39.1@-6.1,-37.38
NetC5_2: C5.2 U1.6 | length 1.3
  1-TOP w0.2: U1.6@95.4,44.7 95.4,45.76 C5.2@95.54,45.9
NetC6_1: C6.1 Q1.G R13.2 R14.1 | length 6.3
  1-TOP w0.2: Q1.G@98.25,47.25 98.25,47.95 98.48,48.18 R14.1@101.4,48.18 R13.2@103.8,48.18
NetC7_2: C7.2 D2.3 J3.2 R16.1 R18.2 | length 8.9
  1-TOP w0.5: R18.2@83.3,55.28 C7.2@85.71,55.28 ; D2.3@85.7,52.9 C7.2@85.7,55.27 ; R16.1@85.7,56.6 85.7,55.33 C7.2@85.73,55.3 ; R16.1@85.7,57.1 85.7,58.1 86.2,58.6 86.2,59.64 J3.2@86.14,59.7
NetC11_1: C11.1 U6.10 | length 1.4
  1-TOP w0.2: C11.1@79.76,39.6 U6.10@81.2,39.6
NetC11_2: C11.2 R23.1 | length 1.6
  1-TOP w0.3: R23.1@78.7,38.1 78.84,38.24 C11.2@78.84,39.6
NetC16_1: C16.1 C21.2 C22.2 R24.1 U5.1 | length 9.9
  1-TOP w0.2: C16.1@92.35,28.8 C16.1@92.5,28.65
  1-TOP w0.5: 88.5,30 R24.1@88.5,28.8 89.7,28.8 90.9,28.8 C16.1@92.35,28.8 ; C22.2@89.7,29 89.7,30.2 ; C21.2@90.9,28.87 90.9,30.07 ; C16.1@92.425,28.725 93.5,28.725 ; C16.1@92.5,29 92.5,30.2
NetC23_1: C23.1 U6.8 | length 1.5
  1-TOP w0.2: C23.1@79.76,40.7 79.86,40.6 U6.8@81.2,40.6
NetC24_2: C24.2 R30.1 U6.11 | length 9.1
  1-TOP w0.2: C24.2@80.2,38.07 80.2,38.7 v1(80.4,38.9) 80.6,39.1 U6.11@81.2,39.1 ; R30.1@83,43.68 v1(83,44.4)
  6-INBOT w0.2: v1(80.4,38.9) 83,41.5 v1(83,44.4)
NetC25_2: C25.2 U6.6 | length 1.2
  1-TOP w0.2: U6.6@82,41.55 C25.2@82,42.74
NetC31_1: C31.1 U9.12 | length 1.1
  1-TOP w0.2: U9.12@-39.75,48.95 -39.75,47.99 C31.1@-39.66,47.9
NetC33_2: C33.2 R74.1 R76.2 U11.5 | length 4.7
  1-TOP w0.2: C33.2@-44.17,42.3 C33.2@-44.1,42.23 ; R76.2@-42.73,42.23 R76.2@-42.7,42.2
  1-TOP w0.5: R74.1@-45.5,42.3 C33.2@-44.17,42.3 ; C33.2@-44.1,42.23 R76.2@-42.73,42.23 ; R76.2@-42.7,42.15 U11.5@-40.88,42.15
NetC38_2: C38.2 R81.1 R82.2 U12.5 | length 7.6
  1-TOP w0.5: U12.5@60.18,-2.85 61.8,-2.85 63.2,-2.85 64.15,-2.85 64.6,-3.3 R81.1@64.6,-6.32
NetC48_2: C48.2 C49.2 D1.1 J23.4 R85.1 R88.1 | length 16.2
  1-TOP w0.5: J23.4@-27.9,-63.025 -27.9,-61.6 -26,-59.7 -18.56,-59.7 C48.2@-18.56,-58.7 ; C48.2@-18.58,-58.7 -18.58,-57.5 R88.1@-18.58,-56.3 R85.1@-18.58,-55.1
NetC58_2: C58.2 C59.2 L2.1 U13.36 | length 10.3
  1-TOP w0.2: U13.36@-66.15,-34.95 v1(-64.95,-34.95) C58.2@-64.41,-34.95 ; C58.2@-64.5,-34.95 C58.2@-64.41,-34.95 ; C58.2@-64.5,-34.9 -64.36,-34.9 C58.2@-64.41,-34.95
  1-TOP w0.5: v1(-62.6,-30.6) C59.2@-61.6,-30.6 -61.58,-30.58 L2.1@-61.58,-28.8
  8-BOTTOM w0.5: v1(-64.95,-34.95) -64.75,-34.95 -62.6,-32.8 v1(-62.6,-30.6)
NetC60_2: C60.2 C61.2 C62.2 L3.1 U13.20 U13.25 | length 14
  1-TOP w0.2: C61.2@-70.9,-41.34 v1(-70.9,-40.6) U13.20@-70.9,-39.2 ; C60.2@-68.4,-41.34 v1(-68.4,-40.6) U13.25@-68.4,-39.2
  1-TOP w0.5: v1(-63.9,-41.7) C62.2@-63,-41.7 -62.98,-41.72 L3.1@-62.98,-43.1
  8-BOTTOM w0.5: v1(-70.9,-40.6) v1(-68.4,-40.6) -67.3,-41.7 v1(-63.9,-41.7)
NetC63_2: C63.2 C64.2 C65.2 C66.2 L4.1 U13.10 U13.11 U13.49 U13.52 | length 24.3
  1-TOP w0.2: C63.2@-75.84,-36.9 C63.2@-75.74,-36.8 ; C63.2@-75.8,-37 v1(-75.2,-37) ; L4.1@-75.02,-25.6 L4.1@-75,-25.62 ; U13.11@-74.15,-36.95 -75.15,-36.95 v1(-75.2,-37) ; U13.10@-74.15,-36.45 -75.05,-36.45 -75.2,-36.6 v1(-75.2,-37) ; C65.2@-71.5,-29.66 v1(-71.5,-30.4) -71.4,-30.4 U13.52@-71.4,-31.2 ; U13.49@-69.9,-31.2 v1(-69.9,-30.43) C64.2@-69.9,-29.66
  1-TOP w0.4: v1(-75,-28.6) L4.1@-75,-25.62
  8-BOTTOM w0.4: v1(-75.2,-37) -75.2,-36 -75.7,-35.5 -75.7,-31.8 -75,-31.1 v1(-75,-28.6) -74.3,-28.6 -72.47,-30.43 -71.53,-30.43 v1(-71.5,-30.4) -71.47,-30.43 v1(-69.9,-30.43)
NetC67_1: C67.1 R103.1 R104.2 U13.16 | length 6
  1-TOP w0.2: C67.1@-75.64,-43.3 -75.64,-41.12 R104.2@-75.62,-41.1 ; R104.2@-75.6,-41.1 -74.2,-41.1 -72.9,-39.8 U13.16@-72.9,-39.2
NetC68_2: C68.2 U13.34 X1.1 | length 6.3
  1-TOP w0.2: U13.34@-66.15,-35.95 -62.15,-35.95 -61.9,-36.2 X1.1@-61.9,-36.8 ; X1.1@-61.45,-37.025 -61.435,-37.04 C68.2@-60.1,-37.04
NetC69_2: C69.2 C70.2 L5.1 U13.35 | length 7.1
  1-TOP w0.2: U13.35@-66.15,-35.45 C69.2@-61.76,-35.45 ; C69.2@-61.6,-35.36 C69.2@-61.56,-35.4
  1-TOP w0.4: C69.2@-61.6,-35.36 C70.2@-61.6,-33.9 ; C70.2@-61.58,-33.9 L5.1@-61.58,-32.72
NetC71_2: C71.2 U13.33 X1.3 | length 4.6
  1-TOP w0.2: U13.33@-66.15,-36.45 -65.55,-36.45 -65.1,-36.9 -65.1,-38.4 -64.9,-38.6 X1.3@-64.5,-38.6 ; C71.2@-63.96,-40.2 -63.96,-38.985 X1.3@-63.95,-38.975
NetC72_2: C72.2 C73.2 C74.2 C75.2 C76.2 L6.1 U13.3 U13.19 U13.26 U13.38 | length 11.2
  1-TOP w0.2: v1(-74.9,-32.95) U13.3@-74.15,-32.95 ; C73.2@-71.9,-41.34 v1(-71.9,-40.6) -71.4,-40.1 U13.19@-71.4,-39.2 ; U13.26@-67.9,-39.2 -67.9,-40.1 v1(-67.4,-40.6) C74.2@-67.4,-41.34 ; U13.38@-66.15,-33.95 v1(-64.95,-33.95) -64.8,-33.8 C75.2@-64.5,-33.8
  1-TOP w0.4: L6.1@-75.82,-29.7 -75.7,-29.82 -75.7,-32.9 -75.65,-32.95 v1(-74.9,-32.95)
NetC80_1: C80.1 U13.37 | length 6
  1-TOP w0.2: U13.37@-66.15,-34.45 v1(-65.45,-34.45) ; C80.1@-64.9,-30.24 -64.84,-30.3 v1(-64.3,-30.3)
  8-BOTTOM w0.2: v1(-65.45,-34.45) -65.45,-32.15 -64.3,-31 v1(-64.3,-30.3)
NetC80_2: C80.2 U13.41 | length 2.1
  1-TOP w0.2: U13.41@-66.15,-32.45 -65.65,-32.45 -64.9,-31.7 C80.2@-64.9,-31.16
NetC85_2: C85.2 C86.2 L7.1 U14.36 | length 9.4
  1-TOP w0.2: U14.36@-47.2,-34.95 v1(-45.85,-34.95) -45.21,-34.95 C85.2@-45.16,-34.9
  1-TOP w0.4: v1(-44.1,-30.7) C86.2@-43.145,-30.7 ; L7.1@-43.2,-29.27 -43.2,-30.54 C86.2@-43.09,-30.65
  8-BOTTOM w0.4: v1(-45.85,-34.95) -45.3,-34.4 -45.3,-31.9 v1(-44.1,-30.7)
NetC87_2: C87.2 C88.2 C89.2 L8.1 U14.20 U14.25 | length 15.2
  1-TOP w0.2: C88.2@-51.95,-41.29 C88.2@-52,-41.34 v1(-52,-40.7) -51.95,-40.65 U14.20@-51.95,-39.2 ; U14.25@-49.45,-39.2 -49.45,-40.65 v1(-49.4,-40.7) C87.2@-49.4,-41.34
  1-TOP w0.4: C89.2@-43.5,-41.8 C89.2@-43.48,-41.82
  1-TOP w0.5: v1(-44.4,-41.8) C89.2@-43.5,-41.8 ; L8.1@-43.48,-43.6 C89.2@-43.48,-41.82
  8-BOTTOM w0.4: v1(-52,-40.7) v1(-49.4,-40.7) -48.7,-41.4 -46.2,-41.4 -45.8,-41.8 v1(-44.4,-41.8)
NetC90_2: C90.2 C91.2 C92.2 C93.2 L9.1 U14.10 U14.11 U14.49 U14.52 | length 25
  1-TOP w0.2: C90.2@-57.24,-37.1 -56.4,-37.1 v1(-56.4,-37) ; C93.2@-56.1,-25.8 C93.2@-56.03,-25.87 ; U14.11@-55.2,-36.95 -56.35,-36.95 v1(-56.4,-37) ; U14.10@-55.2,-36.45 -56.25,-36.45 -56.4,-36.6 v1(-56.4,-37) ; L9.1@-52.6,-29.68 -52.45,-29.83 v1(-52.45,-30.5) U14.52@-52.45,-31.2 ; U14.49@-50.95,-31.2 v1(-50.95,-30.5) -50.95,-29.71 C92.2@-50.9,-29.66
  1-TOP w0.4: v1(-56.03,-28.1) C91.2@-56.03,-27.35 C93.2@-56.03,-25.87
  8-BOTTOM w0.4: v1(-56.4,-37) -57.1,-36.3 -57.1,-32.4 -56.03,-31.33 v1(-56.03,-28.1) -54.85,-28.1 v1(-52.45,-30.5) v1(-50.95,-30.5)
NetC94_1: C94.1 R112.1 R113.2 U14.16 | length 6.5
  1-TOP w0.2: C94.1@-56.84,-43.7 -56.82,-43.68 R112.1@-56.82,-42.5 R113.2@-56.82,-41.4 -55.5,-41.4 -53.95,-39.85 U14.16@-53.95,-39.2
NetC95_2: C95.2 U14.34 X2.1 | length 7.2
  1-TOP w0.2: U14.34@-47.2,-35.95 -42.55,-35.95 -42.4,-36.1 X2.1@-42.4,-36.6 ; X2.1@-42.25,-36.9 -42.09,-36.74 C95.2@-40.5,-36.74
NetC96_2: C96.2 C97.2 L10.1 U14.35 | length 7.8
  1-TOP w0.2: U14.35@-47.2,-35.45 C96.2@-42.9,-35.45 ; C97.2@-43,-33.6 -42.86,-33.74 C97.2@-42.7,-33.9
  1-TOP w0.4: C96.2@-42.86,-35.3 -42.86,-34.26 -42.86,-33.74 L10.1@-42.86,-32.2
NetC98_2: C98.2 U14.33 X2.3 | length 5.2
  1-TOP w0.2: U14.33@-47.2,-36.45 -46.65,-36.45 -45.9,-37.2 -45.9,-38.4 -45.7,-38.6 X2.3@-45.2,-38.6 ; X2.3@-44.9,-38.4 X2.3@-44.75,-38.55 ; C98.2@-44.76,-40.2 -44.76,-38.86 X2.3@-44.75,-38.85
NetC99_2: C99.2 C100.2 C101.2 C102.2 C103.2 L11.1 U14.3 U14.19 U14.26 U14.38 | length 12.1
  1-TOP w0.2: C103.2@-56.64,-31.24 C103.2@-56.5,-31.1 C103.2@-56.52,-31.08 ; v1(-56.1,-32.8) -55.95,-32.95 U14.3@-55.2,-32.95 ; C100.2@-53,-41.34 v1(-53,-40.7) -52.45,-40.15 U14.19@-52.45,-39.2 ; U14.26@-48.95,-39.2 -48.95,-40.25 v1(-48.5,-40.7) -48.5,-41.29 C101.2@-48.45,-41.34 ; U14.38@-47.2,-33.95 v1(-45.9,-33.95) -45.21,-33.95 C102.2@-45.16,-33.9
  1-TOP w0.4: C99.2@-56.84,-32.8 -56.8,-32.76 -56.8,-31.4 C103.2@-56.5,-31.1 ; C99.2@-56.64,-32.8 v1(-56.1,-32.8) ; C103.2@-56.52,-31.08 L11.1@-56.52,-29.3
NetC107_1: C107.1 U14.37 | length 6.4
  1-TOP w0.2: U14.37@-47.2,-34.45 v1(-46.4,-34.45) v1@-46.35,-34.45 ; C107.1@-46.1,-30.94 v1(-46.1,-30.2)
  8-BOTTOM w0.2: v1(-46.4,-34.45) -46.4,-34.2 -46.9,-33.7 -46.9,-32.3 -46.1,-31.5 v1(-46.1,-30.2)
NetC107_2: C107.2 U14.41 | length 1.3
  1-TOP w0.2: U14.41@-47.2,-32.45 -46.69,-32.45 C107.2@-46.1,-31.86
NetC113_2: C113.2 R119.1 U18.2 | length 3
  1-TOP w0.15: R119.1@55.18,-44.46 R119.1@55.2,-44.48
  1-TOP w0.2: U18.2@54.2,-46.5 C113.2@54.2,-44.46 R119.1@55.18,-44.46
NetC114_2: C114.2 R123.2 U17.53 X3.1 | length 8.2
  1-TOP w0.2: U17.53@51.1,-30.995 51.1,-29.205 51.385,-28.92 R123.2@51.385,-28.4 51.385,-27.3 51.385,-24.12 51.58,-23.925 X3.1@52.555,-23.925
NetC116_2: C116.2 R123.1 U17.54 X3.3 | length 5.4
  1-TOP w0.2: X3.3@50.055,-25.875 50.425,-26.245 50.425,-27.3 R123.1@50.425,-28.4 50.425,-28.926 50.7,-29.201 U17.54@50.7,-30.995
NetC117_1: C117.1 U17.35 | length 2
  1-TOP w0.2: U17.35@53.405,-36.9 54.2,-36.9 54.8,-36.3 C117.1@55.205,-36.3
NetC118_2: C118.2 U18.37 | length 2.9
  1-TOP w0.15: U18.37@54.2,-52.3 54.2,-51.4 54.7,-50.9 C118.2@56.04,-50.9
NetC137_1: C137.1 R142.1 U20.32 X4.3 | length 9.2
  1-TOP w0.2: C137.1@98.24,-35.1 98.24,-36.5 98.24,-37.34 98.42,-37.52 R142.1@100.9,-37.52 100.98,-37.6 U20.32@105.1,-37.6
NetC138_1: C138.1 R142.2 U20.33 X4.1 | length 7
  1-TOP w0.2: C138.1@99.26,-40.1 99.26,-39.04 X4.1@99.6,-38.7 ; X4.1@99.8,-38.38 100.9,-38.38 101.42,-38.38 101.7,-38.1 U20.33@105.1,-38.1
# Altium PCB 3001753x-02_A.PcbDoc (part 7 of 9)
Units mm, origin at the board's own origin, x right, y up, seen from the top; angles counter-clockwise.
Board outline 210 x 130 mm, 8 copper layers (1-TOP, 2-GND, 3-INTOP, 4-PWR, 5-PWR, 6-INBOT, 7-GND, 8-BOTTOM), stack 1.646 mm thick; 651 components, 607 nets, 2780 pads, 1706 vias.

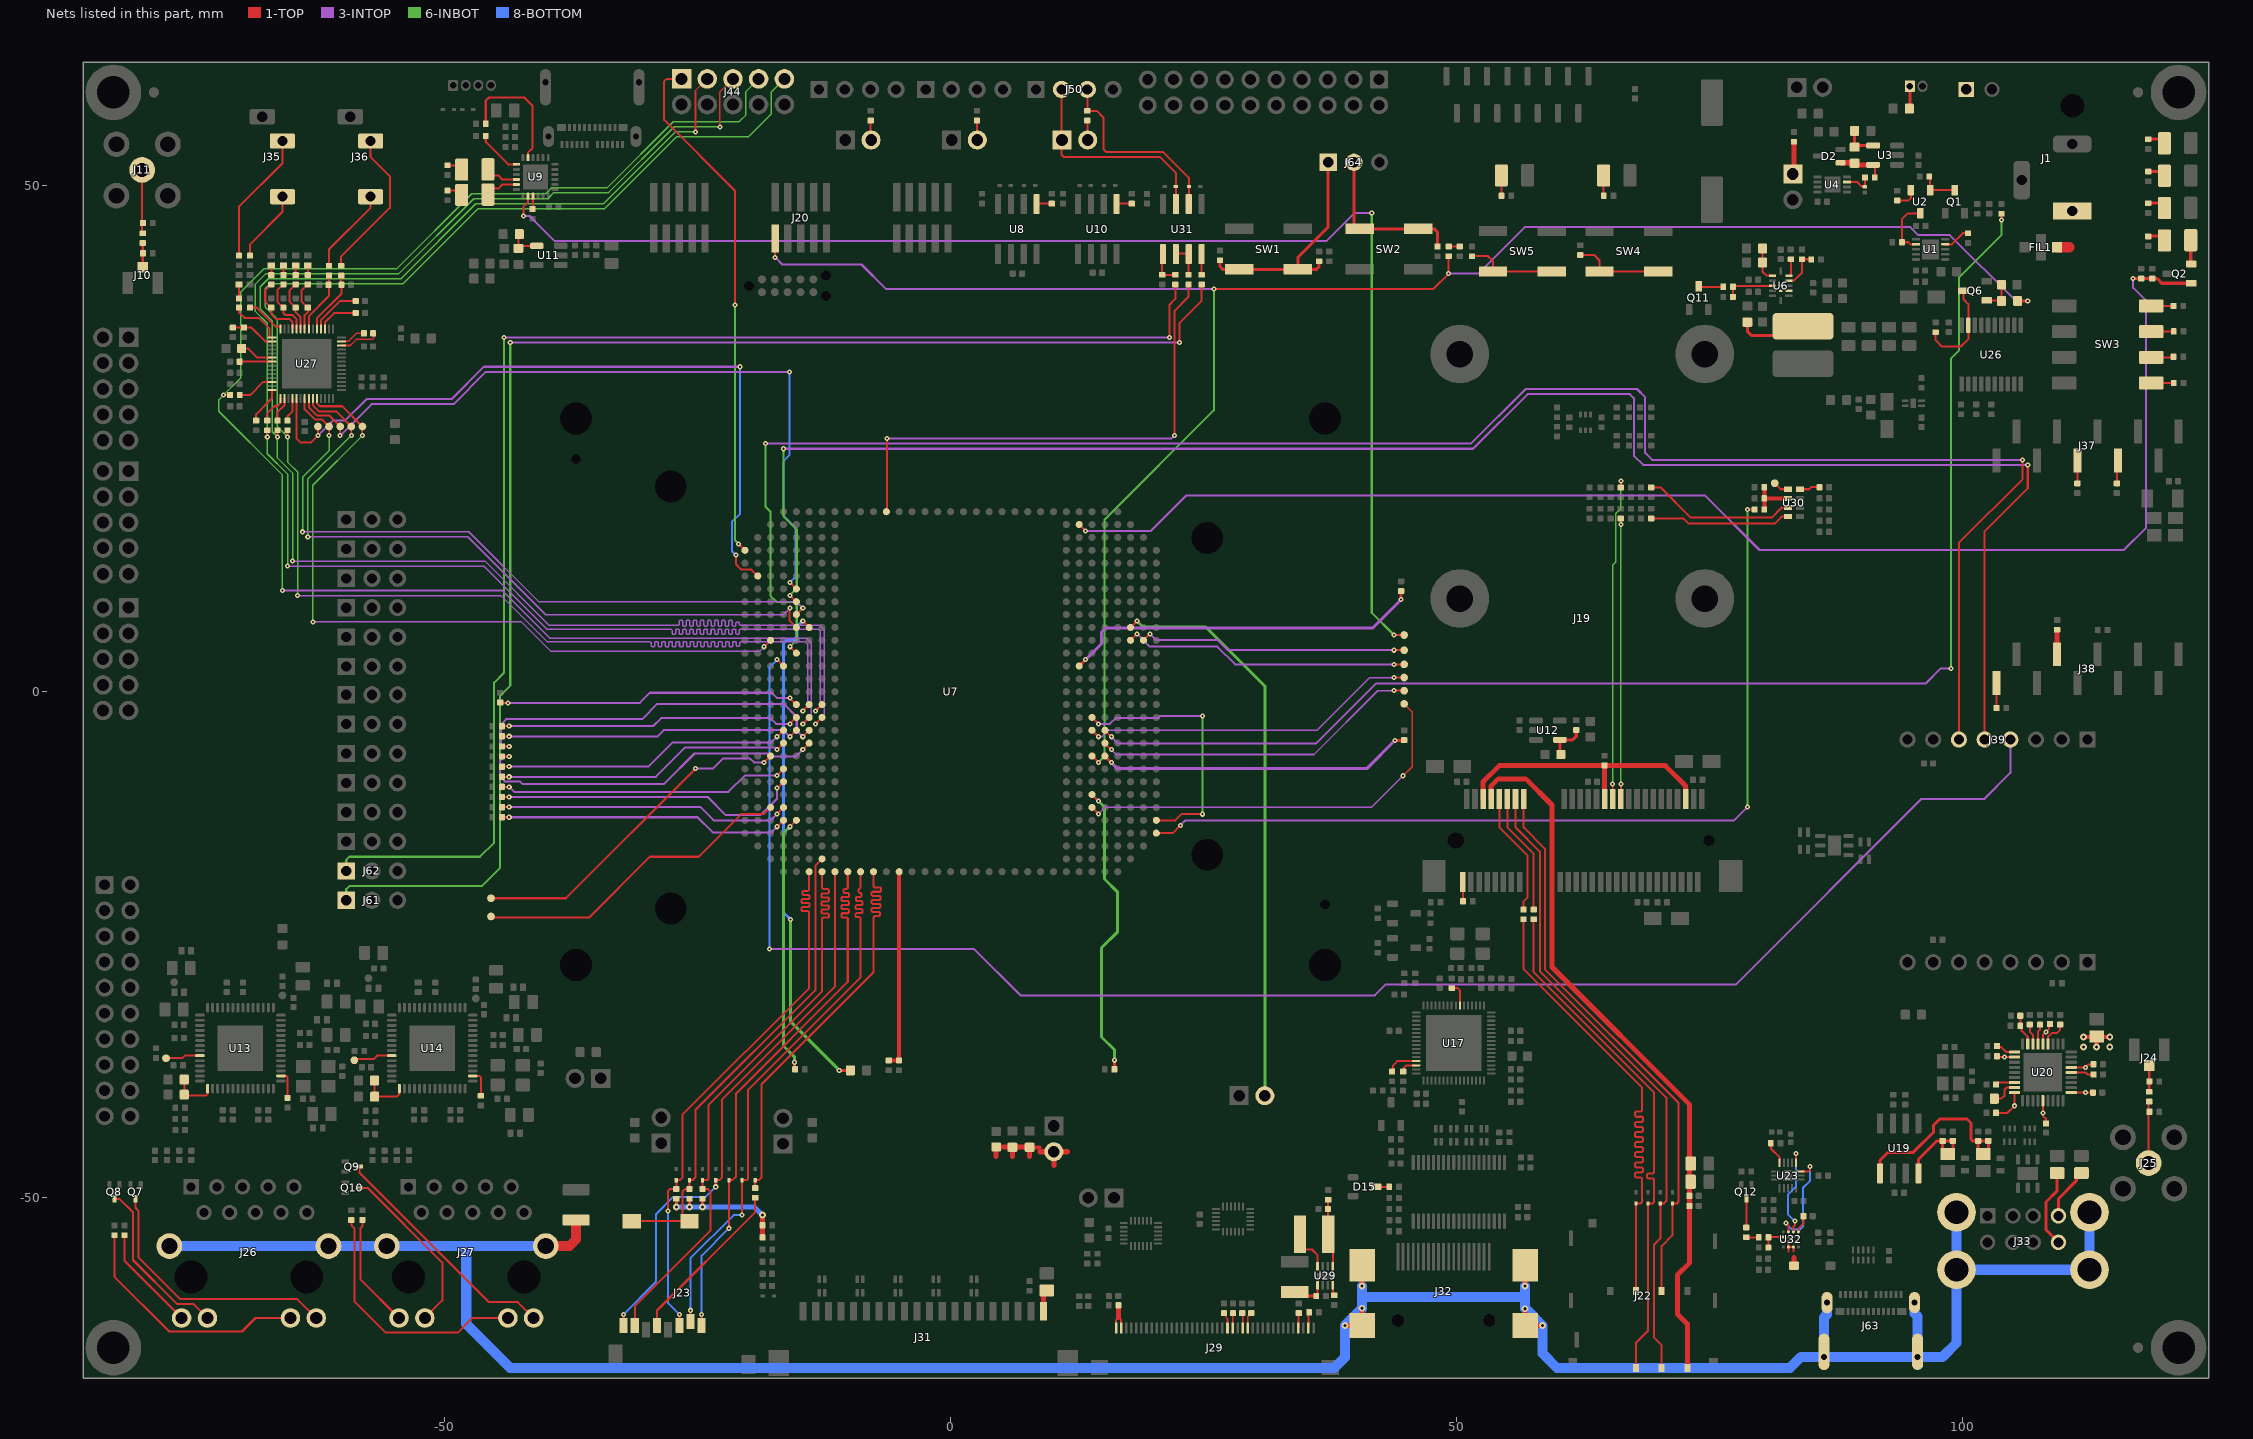
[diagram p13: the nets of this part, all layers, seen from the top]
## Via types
v1: diameter 0.5, hole 0.2, 1-TOP to 8-BOTTOM, 1453 vias
v2: diameter 0.68, hole 0.3, 1-TOP to 8-BOTTOM, 253 vias

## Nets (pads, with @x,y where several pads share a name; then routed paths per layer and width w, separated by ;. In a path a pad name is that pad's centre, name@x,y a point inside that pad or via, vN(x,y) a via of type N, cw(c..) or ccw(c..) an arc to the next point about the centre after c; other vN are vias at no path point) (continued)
NetC140_2: C140.2 C143.2 L23.2 U19.8 | length 8.9
  1-TOP w0.3: U19.8@95.615,-47.57 95.615,-46.185 97.44,-44.36 C143.2@98,-44.36 ; C143.2@98,-44.36 C140.2@99,-44.36 99,-45.35 98.5,-45.85 98,-45.35 C143.2@98,-44.36
NetC141_2: C141.2 C142.2 L22.2 U19.5 | length 18.4
  1-TOP w0.3: U19.5@91.805,-47.57 91.805,-46.295 92.6,-45.5 95.1,-45.5 97.1,-43.5 97.1,-42.8 97.7,-42.2 100.4,-42.2 100.8,-42.6 100.8,-44.2 100.96,-44.36 C142.2@101.5,-44.36 101.5,-45.35 L22.2@102,-45.85 ; C142.2@101.66,-44.36 102.1,-44.36 C141.2@102.5,-44.36 L22.2@102.5,-45.307
NetC144_2: C144.2 R143.1 U20.26 | length 2.9
  1-TOP w0.2: R143.1@105.66,-33 C144.2@105.66,-32 ; R143.1@105.8,-33.1 105.8,-33.5 106.4,-34.1 U20.26@106.4,-34.8
NetC148_2: C148.2 C149.2 C150.2 C151.2 C152.2 C153.2 L28.1 U20.5 U20.10 U20.15 U20.23 U20.29 U20.36 | length 17.6
  1-TOP w0.2: C148.2@103.26,-41.6 104.4,-41.6 v1(105.1,-40.9) U20.36@105.1,-39.6 ; C153.2@103.36,-36 103.46,-36.1 v1(104.1,-36.1) U20.29@105.1,-36.1 ; U20.5@107.9,-40.4 v1(107.9,-41.6) 107.9,-41.9 108.2,-42.2 C149.2@108.2,-42.64 ; U20.23@107.9,-34.8 107.9,-33.9 v1(108.2,-33.6) 108.5,-33.3 C152.2@108.5,-33 ; U20.10@110.7,-39.6 v1(112.1,-39.6) C150.2@112.84,-39.6 ; U20.15@110.7,-37.1 v1(112.1,-37.1) 112.4,-36.8 C151.2@112.9,-36.8
  1-TOP w0.4: v2(111.9,-34.1) L28.1@113.15,-34.1 ; v2(113.2,-35.1) L28.1@113.2,-34.05 ; L28.1@113.25,-34.1 v2(114.5,-34.1)
  other v2: 111.9,-35.1 114.5,-35.1
NetC154_2: C154.2 U20.14 | length 2.3
  1-TOP w0.2: U20.14@110.7,-37.6 112.1,-37.6 112.3,-37.8 C154.2@112.9,-37.8
NetC155_2: C155.2 U20.34 | length 1.9
  1-TOP w0.2: C155.2@103.26,-38.8 103.46,-38.6 U20.34@105.1,-38.6
NetC156_2: C156.2 Q6.G R152.2 | length 3.1
  1-TOP w0.2: Q6.G@102.35,38.65 103.75,38.65 R152.2@103.8,38.6 C156.2@103.8,40.2
NetC158_1: C158.1 R165.2 U27.44 | length 4.4
  1-TOP w0.2: C158.1@-70.9,35.96 -70.88,35.98 R165.2@-69.8,35.98 -69.08,35.98 -67.7,34.6 U27.44@-67.03,34.6
NetC159_1: C159.1 U27.42 | length 3.8
  1-TOP w0.2: C159.1@-69.2,37.94 -68.54,37.94 -66.7,36.1 U27.42@-66.2,36.1
NetC160_1: C160.1 U27.43 | length 5
  1-TOP w0.2: C160.1@-70.3,37.94 -70.3,37.5 -69.7,36.9 -68.3,36.9 -67.3,35.9 U27.43@-67.3,35
NetC160_2: C160.2 L33.2 | length 1.4
  1-TOP w0.2: C160.2@-70.3,38.86 -70.27,38.89 L33.2@-70.27,40.228
NetC161_1: C161.1 C162.1 U27.39 | length 6.5
  1-TOP w0.2: C162.1@-67.1,40.24 -67.7,39.64 -67.7,38.54 C161.1@-67.1,37.94 -67.1,37.3 -66.6,36.8 -65.3,36.8 -65,36.5 U27.39@-65,35.83
NetC162_2: C162.2 L34.2 | length 1
  1-TOP w0.2: C162.2@-67.1,41.16 L34.2@-67.1,42.12
NetC163_1: C163.1 C165.1 U27.38 | length 5.9
  1-TOP w0.2: C163.1@-65.9,40.24 -66.5,39.64 -66.5,38.54 C165.1@-65.9,37.94 -65.9,37.4 -65.7,37.2 -65,37.2 -64.6,36.8 U27.38@-64.6,35.83
NetC163_2: C163.2 L35.2 | length 1
  1-TOP w0.2: C163.2@-65.9,41.16 L35.2@-65.9,42.12
NetC164_1: C164.1 R168.1 U27.35 | length 6.1
  1-TOP w0.2: U27.35@-63.4,35.83 -63.4,37.1 -61.4,39.1 -61.4,40.2 R168.1@-61.4,41.12
NetC166_1: C166.1 C167.1 U27.37 | length 5.1
  1-TOP w0.2: C167.1@-64.7,40.24 -65.3,39.64 -65.3,38.54 C166.1@-64.7,37.94 -64.7,37.5 -64.2,37 U27.37@-64.2,35.83
NetC167_2: C167.2 L36.2 | length 1
  1-TOP w0.2: C167.2@-64.7,41.16 L36.2@-64.7,42.12
NetC168_1: C168.1 R169.1 U27.33 | length 6.3
  1-TOP w0.2: U27.33@-62.6,35.83 -62.6,36.9 -60.16,39.34 C168.1@-60.16,40.2 -60.2,40.24 R169.1@-60.2,41.12
NetC169_1: C169.1 C170.1 U27.36 | length 5
  1-TOP w0.2: U27.36@-63.8,35.83 -63.8,37.2 -63.5,37.5 C170.1@-63.5,37.94 -64.1,38.54 -64.1,39.64 C169.1@-63.5,40.24
NetC169_2: C169.2 L37.2 | length 1
  1-TOP w0.2: C169.2@-63.5,41.16 L37.2@-63.5,42.12
NetC172_1: C172.1 U27.27 | length 2.5
  1-TOP w0.15: U27.27@-60.17,34.6 -59.5,34.6 -58.7,35.4 C172.1@-57.96,35.4
NetC172_2: C172.2 U27.26 | length 4.1
  1-TOP w0.15: U27.26@-60.17,34.2 -59.3,34.2 -58.7,34.8 -57.1,34.8 -57,34.9 C172.2@-57,35.509
NetC174_2: C174.2 U27.32 | length 5.1
  1-TOP w0.2: U27.32@-62.2,35.83 -62.2,36.7 -60.3,38.6 C174.2@-58.796,38.6
NetC179_2: C179.2 U27.31 | length 4.2
  1-TOP w0.2: U27.31@-61.8,35.83 -61.8,36.5 -60.9,37.4 C179.2@-58.691,37.4
NetC180_2: C180.2 U27.48 | length 3.4
  1-TOP w0.2: C180.2@-70.03,33.9 -69.4,33.9 -68.5,33 U27.48@-67.03,33
NetC181_2: C181.2 U27.49 | length 2.9
  1-TOP w0.2: -69.94,32.6 U27.49@-67.03,32.6
NetC189_2: C189.2 L42.1 R216.2 U29.1 | length 6.9
  1-TOP w0.2: L42.1@37.3,-53.327 37.3,-51 R216.2@37.3,-50.107 ; L42.1@37.48,-53.42 L42.1@37.3,-53.6 L42.1@37.65,-53.95 ; U29.1@37.75,-56.765 L42.1@37.75,-53.85
NetC190_2: C190.2 R217.2 U29.5 | length 3.4
  1-TOP w0.2: C190.2@33.7,-59.4 C190.2@34,-59.7 ; R217.2@36.22,-59.7 36.25,-59.67 U29.5@36.25,-58.635
  1-TOP w0.3: C190.2@34,-59.7 R217.2@35.92,-59.7
NetC201_2: C201.2 U32.D4 | length 1.8
  1-TOP w0.2: U32.D4@83.75,-53.35 83.75,-53.05 84.24,-52.56 C201.2@84.24,-51.8
NetD2_1: D2.1 R19.2 R20.2 U3.5 | length 4.6
  1-TOP w0.2: U3.5@91.12,52.05 91.3,51.87 91.3,50.82 R20.2@91.28,50.8
  1-TOP w0.3: R19.2@89.25,52.25 R19.2@89.3,52.2 R19.2@89.45,52.05
  1-TOP w0.5: D2.1@87.9,52.25 R19.2@89.25,52.25 ; R19.2@89.45,52.05 U3.5@91.12,52.05
NetD5_A: D5.A R70.2 | length 1.6
  1-TOP w0.2: R70.2@-49.7,52 -48.725,52 D5.A@-48.3,51.575
NetD5_K: D5.K U9.4 | length 3.2
  1-TOP w0.2: D5.K@-45.7,51.6 -45.1,51 -44.7,51 -44.3,50.6 U9.4@-42.9,50.6
NetD6_A: D6.A R71.2 | length 1.6
  1-TOP w0.2: R71.2@-49.7,49.5 -48.725,49.5 D6.A@-48.3,49.075
NetD6_K: D6.K U9.5 | length 3.2
  1-TOP w0.2: D6.K@-45.7,49.1 -45.1,49.7 -44.7,49.7 -44.3,50.1 U9.5@-42.9,50.1
NetD13_2: D13.2 J22.3 R86.2 | length 51.5
  1-TOP w0.2: R86.2@57.6,-22.48 57.6,-27.7 69.5,-39.6 69.5,-45.485 69.5,-47.455 69.383,-47.572 68.91,-47.572 68.81,-47.672 68.81,-47.972 68.91,-48.072 69.383,-48.072 69.5,-48.189 69.5,-48.289 69.5,-50.4 69.35,-50.55 D13.2@68.9,-50.55 68.9,-63.1 67.7,-64.3 J22.3@67.7,-66.92
NetD14_2: D14.2 J22.7 R89.2 | length 51.3
  1-TOP w0.2: R89.2@56.6,-22.48 56.6,-27.4 68.3,-39.1 68.3,-39.978 68.3,-41.366 68.183,-41.483 67.716,-41.483 67.616,-41.583 67.616,-41.883 67.716,-41.983 68.288,-41.983 68.388,-42.083 68.388,-42.383 68.288,-42.483 67.707,-42.483 67.607,-42.583 67.607,-42.883 67.707,-42.983 68.288,-42.983 68.388,-43.083 68.388,-43.383 68.288,-43.483 67.707,-43.483 67.607,-43.583 67.607,-43.883 67.707,-43.983 68.288,-43.983 68.388,-44.083 68.388,-44.383 68.288,-44.483 67.707,-44.483 67.607,-44.583 67.607,-44.883 67.707,-44.983 68.288,-44.983 68.388,-45.083 68.388,-45.383 68.288,-45.483 67.707,-45.483 67.607,-45.583 67.607,-45.883 67.707,-45.983 68.288,-45.983 68.388,-46.083 68.388,-46.383 68.288,-46.483 67.707,-46.483 67.607,-46.583 67.607,-46.883 67.707,-46.983 68.288,-46.983 68.388,-47.083 68.388,-47.383 68.288,-47.483 67.707,-47.483 67.607,-47.583 67.607,-47.883 67.707,-47.983 68.183,-47.983 68.3,-48.1 68.3,-48.2 68.3,-50.4 68.15,-50.55 D14.2@67.7,-50.55 J22.7@67.7,-59.3
NetD15_K: D15.K R120.1 | length 1.3
  1-TOP w0.2: D15.K@42.05,-48.9 R120.1@43.32,-48.9
NetD17_A: D17.A R206.1 | length 4
  1-TOP w0.2: D17.A@64.498,51.025 64.498,49.022 64.5,49.02 D17.A@64.5,51
NetD18_A: D18.A R207.1 | length 1.7
  1-TOP w0.2: R207.1@54.42,49 D18.A@54.42,50.68
NetD21_A: D21.A U32.B1 U32.B2 U32.C1 | length 2.7
  1-TOP w0.2: 82.75,-55.308 U32.B1@82.75,-54.85 ; U32.B2@82.75,-54.35 U32.B1@82.75,-54.85 ; 83.25,-55.308 U32.C1@83.25,-54.85 U32.B1@82.75,-54.85
  1-TOP w0.5: D21.A@83.3,-56.7 83.3,-55.9
NetD31_A: D31.A R12.1 | length 1.7
  1-TOP w0.3: R12.1@118.3,44.98 118.28,45 D31.A@120,45
NetD31_K: D31.K Q2.S | length 2.4
  1-TOP w0.3: D31.K@122.5,44.6 122.5,42.3 Q2.S@122.55,42.25
NetD32_A: D32.A R15.1 | length 1.8
  1-TOP w0.3: R15.1@118.3,48.26 119.415,48.26 D32.A@119.9,47.775
NetD33_A: D33.A R154.1 | length 1.8
  1-TOP w0.3: R154.1@118.3,51.38 119.495,51.38 D33.A@119.9,50.975
NetD34_A: D34.A R195.1 | length 1.8
  1-TOP w0.3: R195.1@118.3,54.58 119.495,54.58 D34.A@119.9,54.175
NetFIL1_1: FIL1.1 J1.1 J2.1 | length 1.2
  1-TOP w1: FIL1.1@109.3,43.9 110.5,43.9
NetJ4_1: J4.1 R17.1 | length 2.2
  1-TOP w0.3: R17.1@94.75,57.6 J4.1@94.75,59.8
NetJ5_1: J5.1 R18.1 | length 3.2
  1-TOP w0.3: J5.1@83.2,51.14 J5.1@83.3,51.24
  1-TOP w0.5: J5.1@83.3,51.24 R18.1@83.3,54.32
NetJ6_2: J6.2 R33.2 R34.1 R35.1 | length 11.2
  1-TOP w0.4: R33.2@7.8,-45 8.8,-45
  1-TOP w0.5: 4.5,-45.9 R35.1@4.5,-44.97 7.8,-44.97 R33.2@7.8,-45 7.8,-45.9 ; 6.1,-45.93 R34.1@6.1,-45 ; 8.824,-45.443 J6.2@10.184,-45.443 ; J6.2@10.19,-45.443 J6.2@10.2,-45.443 ; 10.2,-46.8 J6.2@10.2,-45.443 ; J6.2@10.2,-45.44 J6.2@10.2,-45.443 ; 11.55,-45.443 J6.2@10.2,-45.443
NetJ9_2: J9.2 U7.AL20 | length 56.6
  1-TOP w0.2: U7.AL20@17.78,6.35 v1(18.415,6.985)
  6-INBOT w0.3: v1(18.415,6.985) 19,6.4 25.2,6.4 31.04,0.56 J9.2@31.04,-39.9
NetJ10_1: J10.1 R58.2 R59.2 | length 2.4
  1-TOP w0.2: J10.1@-79.8,41.925 -79.8,43.3 R58.2@-79.8,44.32
NetJ11_1: J11.1 R58.1 R60.2 | length 6.3
  1-TOP w0.2: J11.1@-79.86,51.54 -79.86,45.34 R58.1@-79.8,45.28
NetJ14_2: J14.2 R66.2 | length 1.7
  1-TOP w0.2: J14.2@-7.9,54.5 R66.2@-7.9,56.22
NetJ16_2: J16.2 R77.2 | length 2.1
  1-TOP w0.2: J16.2@2.6,54.1 R77.2@2.6,56.22
NetJ19_1: J19.1 R80.1 | length 1.9
  1-TOP w0.2: J19.1@50.6,-18.8 50.62,-18.82 R80.1@50.62,-20.7
NetJ23_5: J23.5 R93.2 | length 16.7
  1-TOP w0.2: J23.5@-29,-62.6 -29,-61.125 -19.3,-51.425 R93.2@-19.3,-49.869
NetJ24_1: J24.1 R94.1 R95.2 | length 2.6
  1-TOP w0.2: R94.1@118.4,-39.54 118.4,-38.5 J24.1@118.4,-36.925
NetJ25_1: J25.1 R94.2 R96.2 | length 6.1
  1-TOP w0.2: J25.1@118.34,-46.56 118.34,-41.5 118.34,-40.56 R94.2@118.4,-40.5
NetJ26_D1: J26.D1 R98.2 | length 10.5
  1-TOP w0.2: R98.2@-81.6,-53.68 -81.6,-56.224 J26.D1@-75.96,-61.864
NetJ26_D2: J26.D2 Q8.D | length 16.8
  1-TOP w0.2: Q8.D@-82.6,-50.09 -82.11,-50.09 -80.766,-51.434 -80.766,-56.134 -76.4,-60.5 -74.774,-60.5 J26.D2@-73.41,-61.864
NetJ26_D3: J26.D3 R97.2 | length 24.3
  1-TOP w0.2: R97.2@-82.6,-53.68 -82.6,-57.8 -77.2,-63.2 -70,-63.2 -68.664,-61.864 J26.D3@-65.21,-61.864
NetJ26_D4: J26.D4 Q7.D | length 25.9
  1-TOP w0.2: Q7.D@-80.5,-50.09 -80.5,-51 -80.2,-51.3 -80.2,-55.9 -76.1,-60 -64.524,-60 J26.D4@-62.66,-61.864
NetJ27_D1: J27.D1 R108.2 | length 11.3
  1-TOP w0.2: R108.2@-58.1,-52.18 -58.1,-52.8 -58.3,-53 -58.3,-58.054 J27.D1@-54.49,-61.864
NetJ27_D2: J27.D2 Q10.D | length 17.5
  1-TOP w0.2: Q10.D@-58.41,-49 -57.6,-49 -50.2,-56.4 -50.2,-60.124 J27.D2@-51.94,-61.864
NetJ27_D3: J27.D3 R107.2 | length 25.2
  1-TOP w0.2: R107.2@-59.2,-52.18 -59.2,-52.7 -58.9,-53 -58.9,-60.2 -55.8,-63.3 -48.7,-63.3 -47.264,-61.864 J27.D3@-43.74,-61.864
NetJ27_D4: J27.D4 Q9.D | length 23.8
  1-TOP w0.2: Q9.D@-58.41,-46.9 -58.41,-47.49 -45.6,-60.3 -42.754,-60.3 J27.D4@-41.19,-61.864
NetJ29_1: J29.1 J29.2 R219.1 | length 3.3
  1-TOP w0.2: J29.1@16.35,-62.736 16.35,-62.05 16.6,-61.8 16.85,-62.05 J29.2@16.85,-62.736 ; R219.1@16.58,-60.6 R219.1@16.6,-60.62
  1-TOP w0.5: 16.6,-61.8 R219.1@16.6,-60.62
NetJ29_23: J29.23 R223.1 | length 1.4
  1-TOP w0.15: R223.1@27.2,-61.4 27.2,-61.8 27.35,-61.95 J29.23@27.35,-62.736
NetJ29_24: J29.24 R222.1 | length 1.4
  1-TOP w0.15: J29.24@27.85,-62.736 27.85,-61.43 R222.1@27.9,-61.38
NetJ29_26: J29.26 R221.1 | length 1.4
  1-TOP w0.15: R221.1@28.7,-61.38 28.85,-61.53 J29.26@28.85,-62.736
NetJ29_27: J29.27 R220.1 | length 1.5
  1-TOP w0.15: J29.27@29.35,-62.736 29.35,-61.73 R220.1@29.7,-61.38
NetJ29_37: J29.37 R213.1 | length 1.4
  1-TOP w0.2: J29.37@34.35,-62.85 34.35,-61.53 R213.1@34.4,-61.48
NetJ29_39: J29.39 R212.1 | length 1.3
  1-TOP w0.2: J29.39@35.35,-62.736 35.35,-61.53 R212.1@35.4,-61.48
NetJ31_20: J31.20 L17.2 | length 2.3
  1-TOP w0.2: L17.2@9.175,-59.675 L17.2@9.7,-59.15
  1-TOP w0.5: J31.20@9.175,-61.2 L17.2@9.175,-59.675
NetJ33_A4: J33.A4 L25.2 | length 4.9
  1-TOP w0.3: J33.A4@109.43,-51.77 109.43,-50.07 111.2,-48.3 L25.2@111.2,-47.584
NetJ33_B4: J33.B4 L24.2 | length 8.2
  1-TOP w0.3: L24.2@109.3,-47.201 109.3,-49.3 108.2,-50.4 108.2,-53.16 J33.B4@109.43,-54.39
NetJ35_2: J35.2 R167.2 | length 13.2
  1-TOP w0.2: R167.2@-70.3,42.98 -70.3,47.9 -66,52.2 J35.2@-66,54.4
NetJ35_3: J35.3 R166.2 | length 7.2
  1-TOP w0.2: R166.2@-69.2,42.98 -69.2,44.2 -66,47.4 J35.3@-66,48.9
NetJ36_2: J36.2 R169.2 | length 15.1
  1-TOP w0.2: R169.2@-60.2,42.08 -60.2,43 -55.4,47.8 -55.4,50.9 -57.3,52.8 J36.2@-57.3,54.4
NetJ36_3: J36.3 R168.2 | length 8.5
  1-TOP w0.2: R168.2@-61.4,42.08 -61.4,43.7 -57.3,47.8 J36.3@-57.3,48.9
NetJ37_4: J37.4 R194.2 | length 2.4
  1-TOP w0.2: R194.2@115.2,20.58 115.2,22.4 J37.4@115.6,22.8
NetJ37_6: J37.6 R196.2 | length 2.2
  1-TOP w0.2: R196.2@111.3,20.58 J37.6@111.3,22.8
NetJ38_7: J38.7 R197.1 | length 2.4
  1-TOP w0.5: J38.7@109.3,3.7 R197.1@109.3,6.12
NetJ38_10: J38.10 R200.1 | length 2.5
  1-TOP w0.2: J38.10@103.3,0.85 103.32,0.83 R200.1@103.32,-1.6
NetJ49_2: J49.2 R236.2 | length 1.9
  1-TOP w0.2: J49.2@13.5,54.319 R236.2@13.5,56.22
NetL1_1: L1.1 R23.2 U6.2 U6.13 | length 7.1
  1-TOP w0.3: R23.2@78.7,36.5 78.7,35.6 79.1,35.2 82.95,35.2 L1.1@84.2,36.45
NetL42_2: L42.2 U29.4 | length 2.9
  1-TOP w0.2: L42.2@34.7,-55.1 35.7,-55.1 36.25,-55.65 U29.4@36.25,-56.765
NetQ1_D: Q1.D R7.1 U2.G | length 3.7
  1-TOP w0.2: R7.1@96.82,50.8 96.75,50.73 U2.G@96.75,49.55 Q1.D@99.2,49.55
NetQ6_D: Q6.D R151.1 U26.19 | length 9.6
  1-TOP w0.2: R151.1@97.3,35.52 97.3,34.7 97.9,34.1 99.8,34.1 100.525,34.825 U26.19@100.525,36.2 100.525,38.275 100.05,38.75 Q6.D@100.05,39.6
NetQ11_D: Q11.D R26.1 | length 2.5
  1-TOP w0.2: Q11.D@73.8,40 R26.1@76.32,40
NetQ12_D: Q12.D R201.1 | length 2.8
  1-TOP w0.2: R201.1@78.6,-52.92 Q12.D@78.6,-50.09
NetR3_1: R3.1 R6.1 | length 1.1
  1-TOP w0.2: R6.1@49.1,43.98 R3.1@50.2,43.98
NetR8_1: R8.1 U2.S | length 2.1
  1-TOP w0.2: R8.1@93.604,48.5 94.6,48.5 94.85,48.75 U2.S@94.85,49.55
NetR9_1: R9.1 U1.7 U2.D | length 5.8
  1-TOP w0.2: R9.1@93.98,44.4 R9.1@94,44.42 ; U1.7@95.4,44.2 94.8,44.2 94.6,44.4 94.02,44.4 R9.1@94,44.42 ; U2.D@95.8,47.25 94.55,47.25 94,46.7 R9.1@94,44.42
NetR10_1: R10.1 U1.4 | length 2.9
  1-TOP w0.2: U1.4@98.28,44.2 98.9,44.2 100,45.3 R10.1@100.682,45.3
NetR11_1: R11.1 SW3.7 | length 2.2
  1-TOP w0.2: SW3.7@118.6,35.57 120.79,35.57 R11.1@120.82,35.6
NetR19_1: R19.1 R21.2 U3.4 | length 3.5
  1-TOP w0.3: R21.2@89.3,55.4 R19.1@89.3,53.8 89.45,53.95 U3.4@91.12,53.95
NetR20_1: R20.1 R22.1 U4.3 | length 2.9
  1-TOP w0.2: U4.3@88.55,50.35 89.55,50.35 90.015,49.885 R22.1@90.3,49.885 R20.1@90.3,50.82
NetR25_1: R25.1 R26.2 U6.9 | length 4.9
  1-TOP w0.2: R25.1@77.28,39.1 77.3,39.12 77.3,40.1 U6.9@81.2,40.1
NetR27_1: R27.1 R31.2 U6.4 | length 4
  1-TOP w0.2: U6.4@82.8,40.6 83.3,40.6 84.1,41.4 R31.2@84.1,42.72 R27.1@85.1,42.72
NetR28_1: R28.1 R32.2 U6.7 | length 3.5
  1-TOP w0.2: R32.2@80.2,43.8 80.2,41.5 80.6,41.1 U6.7@81.2,41.1
NetR30_2: R30.2 U6.5 | length 1.6
  1-TOP w0.2: U6.5@83,41.1 R30.2@83,42.72
NetR36_2: R36.2 U7.AJ10 | length 31.2
  1-TOP w0.3: U7.AJ10@15.24,-6.35 v1(15.875,-6.985) ; v1(43.9,-4.8) 44.78,-4.8 R36.2@44.8,-4.78
  3-INTOP w0.3: v1(15.875,-6.985) 16.49,-7.6 41.1,-7.6 v1(43.9,-4.8)
NetR37_2: R37.2 U7.AH7 | length 29.4
  1-TOP w0.2: U7.AH7@13.97,-10.16 v1(14.605,-10.795)
  1-TOP w0.3: R37.2@16.1,-37.24 16.2,-37.14 v1(16.2,-36.4)
  6-INBOT w0.3: v1(14.605,-10.795) 15.2,-11.39 15.2,-18.5 16.5,-19.8 16.5,-23.7 14.9,-25.3 14.9,-34.1 16.2,-35.4 v1(16.2,-36.4)
NetR38_2: R38.2 U7.F20 | length 49.9
  1-TOP w0.2: v1(-14.605,6.985) U7.F20@-13.97,6.35
  1-TOP w0.3: v1(-11,-37.4) R38.2@-9.9,-37.4
  6-INBOT w0.3: v1(-15.8,-22.5) -15.8,-32.6 v1(-11,-37.4)
  8-BOTTOM w0.3: v1(-15.8,-22.5) -16.5,-21.8 -16.5,-21.6 -16.5,4.8 -16.2,5.1 -15.5,5.1 -15.2,5.4 -15.2,6.39 v1(-14.605,6.985)
NetR39_2: R39.2 R40.2 U7.N1 | length 19.6
  1-TOP w0.4: R39.2@-6,-36.42 R40.2@-5,-36.42 ; R40.2@-5.08,-36.42 U7.N1@-5.08,-17.78
NetR41_2: R41.2 U7.E14 | length 30.2
  1-TOP w0.2: R41.2@-44.5,-1.06 -44.46,-1.1 v1(-43.7,-1.1) ; v1(-15.875,-0.635) U7.E14@-15.24,-1.27
  3-INTOP w0.2: v1(-43.7,-1.1) -30.7,-1.1 -29.7,-0.1 -17.68,-0.1 -17.145,-0.635 v1(-15.875,-0.635)
NetR42_2: R42.2 U7.AG17 | length 36
  1-TOP w0.3: U7.AG17@12.7,2.54 v1(13.335,3.175) ; v1(44.5,9.1) R42.2@44.5,9.94
  3-INTOP w0.3: v1(13.335,3.175) 14.9,4.74 14.9,5.9 15.3,6.3 41.7,6.3 v1(44.5,9.1)
NetR45_2: R45.2 U7.E5 | length 25.6
  1-TOP w0.2: v1(-15.875,-13.335) U7.E5@-15.24,-12.7
  1-TOP w0.3: R45.2@-15.4,-37.3 v1(-15.4,-36.6)
  6-INBOT w0.3: v1(-15.875,-13.335) -16.5,-13.96 -16.5,-35 -15.4,-36.1 v1(-15.4,-36.6)
NetR52_1: R52.1 U7.D12 | length 29.3
  1-TOP w0.2: R52.1@-44.32,-7.4 v1(-43.6,-7.4) ; v1(-17.145,-4.445) U7.D12@-16.51,-3.81
  3-INTOP w0.2: v1(-43.6,-7.4) -29.85,-7.4 -27.45,-5 -17.7,-5 v1(-17.145,-4.445)
NetR53_1: R53.1 U7.D11 | length 29.4
  1-TOP w0.2: R53.1@-44.32,-8.4 v1(-43.6,-8.4) ; v1(-17.145,-5.715) U7.D11@-16.51,-5.08
  3-INTOP w0.2: v1(-43.6,-8.4) -29.125,-8.4 -26.225,-5.5 -17.36,-5.5 v1(-17.145,-5.715)
NetR54_1: R54.1 U7.D9 | length 29
  1-TOP w0.2: R54.1@-44.32,-9.4 v1(-43.6,-9.4) ; v1(-17.145,-8.255) U7.D9@-16.51,-7.62
  3-INTOP w0.2: v1(-43.6,-9.4) -43.1,-9.9 -21.95,-9.9 -20.305,-8.255 v1(-17.145,-8.255)
NetR55_1: R55.1 U7.D8 | length 30.5
  1-TOP w0.2: R55.1@-44.32,-10.4 v1(-43.6,-10.4) ; v1(-17.145,-9.525) U7.D8@-16.51,-8.89
  3-INTOP w0.2: v1(-43.6,-10.4) -24,-10.4 -22.2,-12.2 -18.8,-12.2 -17.145,-10.545 v1(-17.145,-9.525)
NetR56_1: R56.1 U7.D6 | length 28.9
  1-TOP w0.2: R56.1@-44.32,-11.4 v1(-43.6,-11.4) ; v1(-17.145,-12.065) U7.D6@-16.51,-11.43
  3-INTOP w0.2: v1(-43.6,-11.4) -24.7,-11.4 -23.4,-12.7 -17.78,-12.7 v1(-17.145,-12.065)
NetR57_1: R57.1 U7.D5 | length 28.9
  1-TOP w0.2: R57.1@-44.32,-12.4 v1(-43.6,-12.4) ; v1(-17.145,-13.335) U7.D5@-16.51,-12.7
  3-INTOP w0.2: v1(-43.6,-12.4) -25,-12.4 -23.5,-13.9 -17.71,-13.9 v1(-17.145,-13.335)
NetR61_1: R61.1 U7.E13 | length 29.9
  1-TOP w0.2: R61.1@-44.32,-3.4 v1(-43.6,-3.4) ; v1(-15.875,-3.175) U7.E13@-15.24,-2.54
  3-INTOP w0.2: v1(-43.6,-3.4) -29.4,-3.4 -28.6,-2.6 -17.8,-2.6 -17.225,-3.175 v1(-15.875,-3.175)
NetR62_1: R62.1 U7.E12 | length 29.9
  1-TOP w0.2: R62.1@-44.32,-4.4 v1(-43.6,-4.4) ; v1(-15.875,-4.445) U7.E12@-15.24,-3.81
  3-INTOP w0.2: v1(-43.6,-4.4) -28.95,-4.4 -28.35,-3.8 -16.52,-3.8 v1(-15.875,-4.445)
NetR63_1: R63.1 U7.F12 | length 37.3
  1-TOP w0.2: R63.1@-44.32,-5.4 v1(-43.6,-5.4) ; v1(-14.605,-4.445) U7.F12@-13.97,-3.81
  3-INTOP w0.2: v1(-43.6,-5.4) -44.2,-5.4 -44.4,-5.2 -44.4,-3.2 -43.9,-2.7 -30.475,-2.7 -28.975,-1.2 -16.5,-1.2 -15.2,-2.5 -15.2,-3.85 v1(-14.605,-4.445)
NetR64_1: R64.1 U7.F11 | length 36.1
  1-TOP w0.2: R64.1@-44.32,-6.4 v1(-43.6,-6.4) ; v1(-14.605,-5.715) U7.F11@-13.97,-5.08
  3-INTOP w0.2: v1(-43.6,-6.4) -44.1,-6.4 -44.5,-6.8 -44.5,-8.4 -44.05,-8.85 -42.55,-8.85 -42.3,-9.1 -28.3,-9.1 -25.3,-6.1 -17.8,-6.1 -17.5,-6.4 -15.29,-6.4 v1(-14.605,-5.715)
NetR65_1: R65.1 U8.5 | length 1.5
  1-TOP w0.2: U8.5@8.495,48.17 8.545,48.22 R65.1@10,48.22
NetR68_2: R68.2 U9.23 | length 12.7
  1-TOP w0.2: R68.2@-45.92,56.1 -45.92,58.38 -45.6,58.7 -42.1,58.7 -41.3,57.9 -41.3,53.7 -41.75,53.25 U9.23@-41.75,52.75
NetR69_2: R69.2 U9.1 | length 4.5
  1-TOP w0.2: R69.2@-45.92,54.9 -45.92,54.32 -43.7,52.1 U9.1@-42.9,52.1
NetR72_1: R72.1 U9.9 | length 1.3
  1-TOP w0.2: R72.1@-41.25,47.68 U9.9@-41.25,48.95
NetR75_1: R75.1 U10.5 | length 1.5
  1-TOP w0.2: U10.5@16.41,48.14 16.49,48.22 R75.1@17.9,48.22
NetR76_1: R76.1 R79.2 U11.4 | length 3.4
  1-TOP w0.2: R79.2@-42.6,45.2 -42.7,45.1 R76.1@-42.7,43.8 -42.45,44.05 U11.4@-40.88,44.05
NetR82_1: R82.1 R83.2 U12.4 | length 3.8
  1-TOP w0.3: R83.2@60.27,-6.2 60.18,-6.11 U12.4@60.18,-4.75 61.45,-4.75 61.8,-4.4 R82.1@61.8,-3.88
NetR84_1: R84.1 R87.1 R90.2 R91.1 R92.2 | length 13.5
  1-TOP w0.3: v2(-27.1,-50.9) R90.2@-27.1,-50.08 ; v2(-25.8,-50.9) R91.1@-25.8,-50.08 ; v2(-24.5,-50.9) R92.2@-24.5,-50.08
  1-TOP w0.5: v2(-18.6,-51.7) -18.6,-52.68 R87.1@-18.58,-52.7 R84.1@-18.58,-53.9
  8-BOTTOM w0.5: v2(-27.1,-50.9) v2(-25.8,-50.9) v2(-24.5,-50.9) -19.4,-50.9 v2(-18.6,-51.7)
NetR101_2: R101.2 R102.2 U13.15 | length 4.4
  1-TOP w0.2: R102.2@-75.7,-38.3 R101.2@-75.7,-39.8 -75.6,-39.9 -73.6,-39.9 -73.4,-39.7 U13.15@-73.4,-39.2
NetR106_2: R106.2 U13.30 | length 2.7
  1-TOP w0.2: U13.30@-66.15,-37.95 -65.65,-37.95 -65.5,-38.1 R106.2@-65.5,-40.12
NetR110_2: R110.2 R111.2 U14.15 | length 4.7
  1-TOP w0.2: R111.2@-56.9,-38.4 R110.2@-56.9,-40 -54.7,-40 -54.45,-39.75 U14.15@-54.45,-39.2
NetR114_2: R114.2 U14.30 | length 2.7
  1-TOP w0.2: U14.30@-47.2,-37.95 -46.55,-37.95 -46.4,-38.1 R114.2@-46.4,-39.92
NetR121_2: R121.2 U17.14 | length 1.7
  1-TOP w0.2: R121.2@44.805,-37.52 44.805,-37.1 45.005,-36.9 U17.14@45.995,-36.9
NetR124_1: R124.1 U17.13 | length 3.1
  1-TOP w0.2: R124.1@43.705,-37.52 43.705,-36.9 44.105,-36.5 U17.13@45.995,-36.5
NetR125_2: R125.2 U17.55 | length 2.4
  1-TOP w0.2: R125.2@49.505,-29.28 50.085,-29.28 50.3,-29.495 U17.55@50.3,-30.995
NetR144_1: R144.1 U20.28 | length 1.9
  1-TOP w0.2: R144.1@103.4,-35.1 103.8,-35.1 104.3,-35.6 U20.28@105.1,-35.6
NetR145_2: R145.2 U20.35 | length 2.8
  1-TOP w0.2: R145.2@103.1,-40.2 103.8,-40.2 104.1,-39.9 104.1,-39.3 104.3,-39.1 U20.35@105.1,-39.1
NetR146_2: R146.2 U20.22 | length 2.6
  1-TOP w0.2: U20.22@108.4,-34.8 108.4,-34.1 108.8,-33.7 109.3,-33.7 109.6,-33.4 R146.2@109.6,-32.98
NetR147_2: R147.2 U20.24 | length 1.9
  1-TOP w0.2: U20.24@107.4,-34.8 107.4,-33.6 107.6,-33.4 R147.2@107.6,-32.98
NetR148_2: R148.2 U20.25 | length 1.9
  1-TOP w0.2: R148.2@106.6,-32.98 106.6,-33.6 106.9,-33.9 U20.25@106.9,-34.8
NetR150_2: R150.2 R199.2 U32.A3 | length 2.5
  1-TOP w0.2: R150.2@80.78,-54.9 R199.2@80.78,-53.9 80.83,-53.85 U32.A3@82.25,-53.85
NetR153_1: R153.1 SW3.8 | length 2.2
  1-TOP w0.2: SW3.8@118.6,38.11 120.79,38.11 R153.1@120.8,38.1
NetR155_1: R155.1 SW3.6 | length 2.2
  1-TOP w0.2: SW3.6@118.6,33.03 120.73,33.03 R155.1@120.8,33.1
NetR156_1: R156.1 SW3.5 | length 2.2
  1-TOP w0.2: SW3.5@118.6,30.49 118.61,30.5 R156.1@120.82,30.5
NetR160_2: R160.2 U27.56 | length 3.7
  1-TOP w0.2: R160.2@-68.6,26.78 -68.6,27.4 -67.03,28.97 U27.56@-67.03,29.8
NetR161_2: R161.2 U27.2 | length 2.5
  1-TOP w0.2: R161.2@-66.5,26.78 -66.5,27.6 -65.8,28.3 U27.2@-65.8,28.97
NetR162_2: R162.2 U27.4 | length 2.4
  1-TOP w0.2: R162.2@-65.5,26.78 -65.5,27.2 -65,27.7 U27.4@-65,28.97
NetR163_2: R163.2 U27.54 | length 3.7
  1-TOP w0.2: R163.2@-70.22,29.3 -69.2,29.3 -67.9,30.6 U27.54@-67.03,30.6
NetR164_2: R164.2 U27.1 | length 2.9
  1-TOP w0.2: R164.2@-67.5,26.78 -67.5,27.5 -66.8,28.2 -66.5,28.2 -66.2,28.5 U27.1@-66.2,28.97
NetR193_1: R193.1 U23.5 | length 2.3
  1-TOP w0.2: R193.1@81.02,-44.6 81.02,-45.12 81.9,-46 U23.5@81.9,-46.55
NetR199_1: R199.1 R201.2 | length 1.2
  1-TOP w0.2: R201.2@78.6,-53.88 78.62,-53.9 R199.1@79.82,-53.9
NetR208_2: R208.2 SW4.3 SW4.4 | length 9
  1-TOP w0.2: R208.2@62.2,43.14 63.56,43.14 64.1,42.6 SW4.3@64.1,41.5 SW4.4@69.9,41.5
NetR209_2: R209.2 SW5.3 SW5.4 | length 9.1
  1-TOP w0.2: R209.2@51.5,43.02 53.08,43.02 53.581,42.519 SW5.3@53.581,41.5 SW5.4@59.381,41.5
NetR215_2: R215.2 U29.8 | length 1
  1-TOP w0.2: U29.8@37.75,-58.635 37.75,-59.47 R215.2@37.9,-59.62
NetR224_1: R224.1 R225.1 R228.2 U30.2 | length 4.5
  1-TOP w0.4: R228.2@80.38,18 R225.1@80.38,19.1 ; R224.1@80.38,20.2 R225.1@80.38,19.1 ; U30.2@82.7,19.1 R225.1@80.38,19.1
NetR229_2: R229.2 U30.8 | length 2
  1-TOP w0.2: U30.8@83.9,20 84.8,20 85,20.2 R229.2@85.82,20.2
NetR232_1: R232.1 R233.2 U31.1 | length 3.4
  1-TOP w0.2: U31.1@20.966,43.289 20.9,43.223 R232.1@20.9,41.18 R233.2@22.2,41.18
NetR234_2: R234.2 U31.2 U31.3 | length 3.4
  1-TOP w0.2: U31.2@22.236,43.289 23.506,43.289 23.506,41.186 R234.2@23.5,41.18
NetR235_2: R235.2 U31.4 | length 2.1
  1-TOP w0.2: U31.4@24.776,43.289 24.776,41.204 R235.2@24.8,41.18
NetTP1_1: TP1.1 U7.AJ11 | length 32.6
  1-TOP w0.2: U7.AJ11@15.24,-5.08 v1(15.875,-5.715) ; v1(43.8,0.1) TP1.1@44.8,0.1
  3-INTOP w0.15: v1(15.875,-5.715) 16.36,-6.2 35.9,-6.2 42.2,0.1 v1(43.8,0.1)
NetTP2_1: TP2.1 U7.AH6 | length 40.4
  1-TOP w0.15: v1(44.7,-8.3) 45.6,-7.4 45.6,-2 TP2.1@44.8,-1.2
  1-TOP w0.2: U7.AH6@13.97,-11.43 v1(14.605,-12.065)
  3-INTOP w0.15: v1(14.605,-12.065) 15.27,-11.4 41.6,-11.4 v1(44.7,-8.3)
NetTP3_1: TP3.1 U7.AH12 | length 33.5
  1-TOP w0.2: U7.AH12@13.97,-3.81 v1(14.605,-4.445) ; v1(43.8,1.4) TP3.1@44.8,1.4
  3-INTOP w0.15: v1(14.605,-4.445) 14.955,-4.445 15.6,-3.8 36.2,-3.8 41.4,1.4 v1(43.8,1.4)
NetTP4_1: TP4.1 U7.AM19 | length 26.7
  1-TOP w0.2: U7.AM19@19.05,5.08 v1(19.685,5.715) ; v1(43.8,4.1) TP4.1@44.8,4.1
  3-INTOP w0.2: v1(19.685,5.715) 20.3,5.1 26.4,5.1 27.4,4.1 v1(43.8,4.1)
NetTP5_1: TP5.1 U7.AL19 | length 28.5
  1-TOP w0.2: U7.AL19@17.78,5.08 v1(18.415,5.715) ; v1(43.8,2.7) TP5.1@44.8,2.7
  3-INTOP w0.2: v1(18.415,5.715) 19.685,4.445 26.355,4.445 28.1,2.7 v1(43.8,2.7)
NetTP6_1: TP6.1 U9.8 | length 131.8
  1-TOP w0.15: TP6.1@44.6,5.6 44.7,5.5 TP6.1@44.8,5.6
  1-TOP w0.2: v1(-42.2,47) -42.2,47.9 -41.75,48.35 U9.8@-41.75,48.95 ; v1(43.8,5.6) TP6.1@44.6,5.6
  3-INTOP w0.2: v1(-42.2,47) -41.6,47 -40.5,45.9 -39.1,44.5 37.1,44.5 39.9,47.3 v1(41.6,47.3)
  6-INBOT w0.2: v1(41.6,47.3) 41.6,7.8 v1(43.8,5.6)
NetTP7_1: TP7.1 U13.9 | length 3.5
  1-TOP w0.2: TP7.1@-77.5,-36.2 -75.9,-36.2 -75.65,-35.95 U13.9@-74.15,-35.95
NetTP10_1: TP10.1 U14.9 | length 3.9
  1-TOP w0.2: TP10.1@-58.9,-36.4 -58.8,-36.3 -57,-36.3 -56.65,-35.95 U14.9@-55.2,-35.95
NetTP18_1: TP18.1 U30.1 | length 1.5
  1-TOP w0.2: TP18.1@81.4,20.6 82,20 U30.1@82.7,20
NetTP19_1: TP19.1 U7.C6 | length 32.2
  1-TOP w0.2: TP19.1@-45.452,-22.3 -35.7,-22.3 -29.7,-16.3 -24.9,-16.3 -20.7,-12.1 -18.45,-12.1 U7.C6@-17.78,-11.43
NetTP20_1: TP20.1 U7.C10 | length 34.1
  1-TOP w0.2: TP20.1@-45.609,-20.191 TP20.1@-45.4,-20.4 -38,-20.4 v1(-25.2,-7.6) ; v1(-18.415,-6.985) U7.C10@-17.78,-6.35
  3-INTOP w0.2: v1(-25.2,-7.6) -23.5,-7.6 -22.5,-6.6 -19.8,-6.6 -19.415,-6.985 v1(-18.415,-6.985)
NX5P3290_EN: U23.16 U32.B4 | length 10.5
  1-TOP w0.2: v1(82.5,-52.5) 82.75,-52.75 U32.B4@82.75,-53.35 ; U23.16@83.95,-47.4 84.7,-47.4 84.9,-47.2 v1(84.9,-46.9)
  8-BOTTOM w0.2: v1(82.5,-52.5) 83.1,-53.1 83.9,-53.1 84.2,-52.8 84.2,-49 84.9,-48.3 v1(84.9,-46.9)
NX5P3290_FRS: U23.1 U32.C4 | length 9.4
  1-TOP w0.2: U32.C4@83.25,-53.35 83.25,-52.85 83.4,-52.7 v1(83.4,-52.3) ; U23.1@83.5,-46.55 v1(83.5,-45.6)
  8-BOTTOM w0.2: v1(83.4,-52.3) 82.7,-51.6 82.7,-49.7 83.5,-48.9 v1(83.5,-45.6)
PCIE_1V5: J19.6 J19.28 J19.48 R81.2 | length 27.6
  1-TOP w0.5: J19.6@52.6,-10.6 52.6,-8.9 54.2,-7.3 64.58,-7.3 R81.2@64.6,-7.28 64.62,-7.3 70.6,-7.3 72.6,-9.3 J19.48@72.6,-10.6 ; J19.28@64.6,-10.6 R81.2@64.6,-7.5
PCIE_I2C_SCL: J19.30 R188.2 | length 32.3
  1-TOP w0.15: J19.30@65.4,-10.6 v1(65.4,-9.1)
  1-TOP w0.2: R188.2@66.2,20.18 v1(66.2,20.8)
  6-INBOT w0.15: v1(65.4,-9.1) 65.4,12.507 65.7,12.807 65.7,17.554 ; 65.7,17.6 66.2,18.1 v1(66.2,20.8)
PCIE_I2C_SDA: J19.32 R190.2 | length 27.7
  1-TOP w0.2: J19.32@66.2,-10.6 v1(66.2,-9.1) ; v1(66.2,16.5) R190.2@66.2,17.12
  6-INBOT w0.15: v1(66.2,-9.1) 66.2,12.6 v1(66.2,16.5)
PCIE_UIM_CLK: J19.12 R86.1 | length 12
  1-TOP w0.2: J19.12@55,-10.6 55,-13.4 57.6,-16 R86.1@57.6,-21.52
PCIE_UIM_DATA: J19.10 R89.1 | length 12.2
  1-TOP w0.2: J19.10@54.2,-10.6 54.2,-13.4 57,-16.2 57,-20.3 56.6,-20.7 R89.1@56.6,-21.52
PCIE_UIM_PWR: C50.2 C51.2 C52.2 C53.2 J19.8 J22.1 | length 70.5
  1-TOP w0.5: J19.8@53.4,-10.6 53.4,-9.3 54.1,-8.6 56.8,-8.6 59.4,-11.2 59.4,-27.2 73,-40.8 C50.2@73,-46.701 ; J22.1@72.78,-66.7 72.78,-62.48 71.8,-61.5 71.8,-57.6 73,-56.4 C53.2@73,-50.781 ; C53.2@72.98,-50.8 C52.2@72.98,-49.8 72.98,-48.52 C51.2@73.1,-48.4 ; C51.2@73,-48.4 C50.2@73,-47
PCIE_UIM_RST: D11.2 J19.14 J22.2 | length 63.5
  1-TOP w0.2: J19.14@55.8,-10.6 55.8,-13.4 58.2,-15.8 58.2,-27.607 70.7,-40.107 70.7,-50.3 70.45,-50.55 D11.2@70.1,-50.55 70.1,-54 69.5,-54.6 69.5,-63.8 70.24,-64.54 J22.2@70.24,-66.92
PCIE_UIM_VPP: D12.2 J19.16 J22.6 | length 56
  1-TOP w0.2: J19.16@56.6,-10.6 56.6,-13.4 58.7,-15.5 58.7,-27.4 71.9,-40.6 71.9,-50.4 71.75,-50.55 D12.2@71.3,-50.55 71.3,-53.7 70.24,-54.76 J22.6@70.24,-59.3
PCM_CLK: J44.3 R161.1 U7.G13 | length 158.2
  1-TOP w0.15: v1(-25.2,55.3) -25.2,59.3 -25.24,59.34 J44.3@-24.04,60.54
  1-TOP w0.2: v1(-66.5,25.18) R161.1@-66.5,25.82 ; v1(-13.335,-3.175) U7.G13@-12.7,-2.54
  3-INTOP w0.15: v1(-65,12.9) -46,12.9 -39.65,6.55 -26.977,6.55 -26.902,6.55 -26.814,6.638 -26.814,6.982 -26.744,7.052 -26.534,7.052 -26.464,6.982 -26.464,6.556 -26.394,6.486 -26.184,6.486 -26.114,6.556 -26.114,6.982 -26.044,7.052 -25.834,7.052 -25.764,6.982 -25.764,6.556 -25.694,6.486 -25.484,6.486 -25.414,6.556 -25.414,6.982 -25.344,7.052 -25.134,7.052 -25.064,6.982 -25.064,6.556 -24.994,6.486 -24.784,6.486 -24.714,6.556 -24.714,6.982 -24.644,7.052 -24.434,7.052 -24.364,6.982 -24.364,6.556 -24.294,6.486 -24.084,6.486 -24.014,6.556 -24.014,6.982 -23.944,7.052 -23.734,7.052 -23.664,6.982 -23.664,6.556 -23.594,6.486 -23.384,6.486 -23.314,6.556 -23.314,6.982 -23.244,7.052 -23.034,7.052 -22.964,6.982 -22.964,6.556 -22.894,6.486 -22.684,6.486 -22.614,6.556 -22.614,6.982 -22.544,7.052 -22.334,7.052 -22.264,6.982 -22.264,6.556 -22.194,6.486 -21.984,6.486 -21.914,6.556 -21.914,6.982 -21.844,7.052 -21.634,7.052 -21.564,6.982 -21.564,6.556 -21.494,6.486 -21.284,6.486 -21.214,6.556 -21.214,6.794 -21.144,6.864 -20.934,6.864 -20.864,6.794 -20.864,6.638 -20.776,6.55 -20.6,6.55 -12.895,6.55 -12.5,6.155 -12.5,-2.34 v1(-13.335,-3.175)
  6-INBOT w0.15: v1(-65,12.9) -65,21.6 -66.5,23.1 v1(-66.5,25.18) -67,25.68 -67,36.607 -68.2,37.807 -68.2,40.007 -67.407,40.8 -54.3,40.8 -46.9,48.2 -34.3,48.2 -27.2,55.3 v1(-25.2,55.3)
PCM_IN: J44.5 R164.1 U7.G14 | length 160.3
  1-TOP w0.15: v1(-22.8,55.8) -22.8,59.24 J44.5@-21.5,60.54
  1-TOP w0.2: v1(-67.5,25.18) R164.1@-67.5,25.82 ; v1(-13.335,-1.905) U7.G14@-12.7,-1.27
  3-INTOP w0.15: v1(-65.5,12.4) -46.1,12.4 -39.875,6.175 -28.032,6.175 -27.607,6.175 -27.519,6.087 -27.519,5.745 -27.449,5.675 -27.239,5.675 -27.169,5.745 -27.169,6.125 -27.099,6.195 -26.889,6.195 -26.819,6.125 -26.819,5.745 -26.749,5.675 -26.539,5.675 -26.469,5.745 -26.469,6.125 -26.399,6.195 -26.189,6.195 -26.119,6.125 -26.119,5.745 -26.049,5.675 -25.839,5.675 -25.769,5.745 -25.769,6.125 -25.699,6.195 -25.489,6.195 -25.419,6.125 -25.419,5.745 -25.349,5.675 -25.139,5.675 -25.069,5.745 -25.069,6.125 -24.999,6.195 -24.789,6.195 -24.719,6.125 -24.719,5.745 -24.649,5.675 -24.439,5.675 -24.369,5.745 -24.369,6.125 -24.299,6.195 -24.089,6.195 -24.019,6.125 -24.019,5.745 -23.949,5.675 -23.739,5.675 -23.669,5.745 -23.669,6.125 -23.599,6.195 -23.389,6.195 -23.319,6.125 -23.319,5.745 -23.249,5.675 -23.039,5.675 -22.969,5.745 -22.969,6.125 -22.899,6.195 -22.689,6.195 -22.619,6.125 -22.619,5.745 -22.549,5.675 -22.339,5.675 -22.269,5.745 -22.269,6.125 -22.199,6.195 -21.989,6.195 -21.919,6.125 -21.919,5.745 -21.849,5.675 -21.639,5.675 -21.569,5.745 -21.569,6.125 -21.499,6.195 -21.289,6.195 -21.219,6.125 -21.219,5.765 -21.149,5.695 -20.939,5.695 -20.869,5.765 -20.869,6.087 -20.781,6.175 -20.635,6.175 -20.575,6.175 -13.05,6.175 -12.875,6 -12.875,-1.445 v1(-13.335,-1.905)
  6-INBOT w0.15: v1(-65.5,12.4) -65.5,21.5 -67.5,23.5 v1(-67.5,25.18) -67.5,36.4 -68.7,37.6 -68.7,40.214 -67.614,41.3 -54.5,41.3 -47.1,48.7 -39.8,48.7 -39.195,49.305 -33.795,49.305 -27.3,55.8 v1(-22.8,55.8)
PCM_MCLK: J44.1 U7.A26 | length 51.5
  1-TOP w0.2: J44.1@-26.56,60.54 -28.06,60.54 -28.3,60.3 -28.3,56.5 -21.3,49.5 v1(-21.3,38.2) ; v1(-20.955,14.605) U7.A26@-20.32,13.97
  6-INBOT w0.2: v1(-21.3,38.2) -21.3,14.95 v1(-20.955,14.605)
PCM_OUT: J44.7 R163.1 U7.F13 | length 158.5
  1-TOP w0.2: v1(-71.82,29.3) R163.1@-71.18,29.3 ; v1(-14.605,-3.175) U7.F13@-13.97,-2.54
  3-INTOP w0.15: v1(-66,10) -44.3,10 -39.575,5.275 -14.23,5.275 -13.775,4.82 -13.775,-2.345 v1(-14.605,-3.175)
  6-INBOT w0.15: v1(-66,10) -66,21.4 -72.3,27.7 -72.3,28.82 v1(-71.82,29.3) -70.1,31.02 -70.1,39.5 -67.8,41.8 -54.7,41.8 -47.3,49.2 -40,49.2 -39.4,49.8 -33.9,49.8 -27.4,56.3 -20.9,56.3 -20.22,56.98 -20.22,59.28 J44.7@-18.96,60.54
PCM_SYNC: J44.9 R162.1 U7.F14 | length 164.4
  1-TOP w0.2: v1(-65.5,25.18) R162.1@-65.5,25.82 ; v1(-14.605,-1.905) U7.F14@-13.97,-1.27
  3-INTOP w0.15: v1(-64.5,9.5) -44.4,9.5 -39.825,4.925 -30.094,4.925 -29.669,4.925 -29.581,4.837 -29.581,4.517 -29.511,4.447 -29.301,4.447 -29.231,4.517 -29.231,4.884 -29.161,4.954 -28.951,4.954 -28.881,4.884 -28.881,4.517 -28.811,4.447 -28.601,4.447 -28.531,4.517 -28.531,4.884 -28.461,4.954 -28.251,4.954 -28.181,4.884 -28.181,4.517 -28.111,4.447 -27.901,4.447 -27.831,4.517 -27.831,4.884 -27.761,4.954 -27.551,4.954 -27.481,4.884 -27.481,4.517 -27.411,4.447 -27.201,4.447 -27.131,4.517 -27.131,4.884 -27.061,4.954 -26.851,4.954 -26.781,4.884 -26.781,4.517 -26.711,4.447 -26.501,4.447 -26.431,4.517 -26.431,4.884 -26.361,4.954 -26.151,4.954 -26.081,4.884 -26.081,4.517 -26.011,4.447 -25.801,4.447 -25.731,4.517 -25.731,4.884 -25.661,4.954 -25.451,4.954 -25.381,4.884 -25.381,4.517 -25.311,4.447 -25.101,4.447 -25.031,4.517 -25.031,4.884 -24.961,4.954 -24.751,4.954 -24.681,4.884 -24.681,4.517 -24.611,4.447 -24.401,4.447 -24.331,4.517 -24.331,4.884 -24.261,4.954 -24.051,4.954 -23.981,4.884 -23.981,4.517 -23.911,4.447 -23.701,4.447 -23.631,4.517 -23.631,4.884 -23.561,4.954 -23.351,4.954 -23.281,4.884 -23.281,4.517 -23.211,4.447 -23.001,4.447 -22.931,4.517 -22.931,4.884 -22.861,4.954 -22.651,4.954 -22.581,4.884 -22.581,4.517 -22.511,4.447 -22.301,4.447 -22.231,4.517 -22.231,4.884 -22.161,4.954 -21.951,4.954 -21.881,4.884 -21.881,4.517 -21.811,4.447 -21.601,4.447 -21.531,4.517 -21.531,4.884 -21.461,4.954 -21.251,4.954 -21.181,4.884 -21.181,4.554 -21.111,4.484 -20.901,4.484 -20.831,4.554 -20.831,4.837 -20.743,4.925 -20.05,4.925 -14.375,4.925 -14.125,4.675 -14.125,-1.425 v1(-14.605,-1.905)
  6-INBOT w0.15: v1(-64.5,9.5) -64.5,21.7 -65.5,22.7 v1(-65.5,25.18) -66.5,26.18 -66.5,36.814 -67.7,38.014 -67.7,39.8 -67.2,40.3 -54.1,40.3 -46.695,47.705 -34.195,47.705 -27.1,54.8 -20,54.8 -17.7,57.1 -17.7,59.26 J44.9@-16.42,60.54
POR_B: J20.10 R6.2 R152.1 U7.AH10 | length 187.7
  1-TOP w0.2: v1(-17.34,42.9) J20.10@-17.34,44.768 ; U7.AH10@13.97,-6.35 v1(14.605,-6.985) ; v1(26,39.8) 47.7,39.8 v1(49.2,41.3) R6.2@49.2,43.02
  1-TOP w0.3: R152.1@105.4,38.6 v1(106.4,38.6)
  3-INTOP w0.2: v1(-17.34,42.9) -16.64,42.2 -8.8,42.2 -6.4,39.8 v1(26,39.8) ; v1@49.15,41.35 49.1,41.3 v1(49.2,41.3) 52.1,41.3 56.7,45.9 94.8,45.9 95.6,45.1 98.7,45.1 105.2,38.6 v1(106.4,38.6)
  6-INBOT w0.2: v1(14.605,-6.985) 15.2,-6.39 15.2,17 26,27.8 v1(26,39.8)
POWER_BUTTON: J64.1 R2.1 R4.1 SW1.3 SW1.4 | length 22.9
  1-TOP w0.3: R4.1@26.6,42.62 26.6,42 26.873,41.727 SW1.3@28.5,41.727 33.4,41.727 SW1.4@34.3,41.727 ; R2.1@36.4,42.52 36.4,42 36.127,41.727 SW1.4@34.3,41.727 ; J64.1@37.3,52.194 37.3,45.9 34.3,42.9 SW1.4@34.3,41.727
POWER_LED: Q2.G R203.2 R204.1 U7.AG28 | length 141.4
  1-TOP w0.2: U7.AG28@12.7,16.51 v1(13.335,15.875)
  1-TOP w0.3: v1(116.8,40.8) 116.82,40.82 R204.1@117.6,40.82 R203.2@118.7,40.82 119.18,40.82 119.65,40.35 Q2.G@122.55,40.35
  3-INTOP w0.2: v1(13.335,15.875) 19.775,15.875 23.3,19.4 74.5,19.4 79.9,14 115.9,14 118.1,16.2 118.1,38.6 116.8,39.9 v1(116.8,40.8)
PWR_ON: R13.1 U7.AJ12 | length 134.2
  1-TOP w0.2: U7.AJ12@15.24,-3.81 v1(15.875,-4.445) ; v1(103.8,46.6) R13.1@103.8,47.22
  3-INTOP w0.2: v1(15.875,-4.445) 16.53,-5.1 36.1,-5.1 42,0.8 96.3,0.8 97.8,2.3 v1(98.8,2.3)
  6-INBOT w0.2: v1(98.8,2.3) 98.8,32.9 99.6,33.7 99.6,40.9 103.8,45.1 v1(103.8,46.6)
RESET_BUTTON: J64.2 R5.1 SW2.3 SW2.4 | length 15.8
  1-TOP w0.3: SW2.4@39.84,45.8 J64.2@39.84,52.3 ; SW2.4@40.4,45.727 SW2.3@46.2,45.727 47.773,45.727 48.1,45.4 R5.1@48.1,43.98
RS485_A: D19.2 J50.3 R236.1 U31.6 | length 19.3
  1-TOP w0.2: J50.3@13.5,59.5 R236.1@13.5,57.38 14.42,57.38 15.1,56.7 15.1,53.6 15.4,53.3 21,53.3 23.525,50.775 U31.6@23.525,48.17
RS485_B: D20.2 J49.1 J50.2 U31.7 | length 21.6
  1-TOP w0.2: J50.2@10.96,59.5 10.96,54.319 10.96,53.04 11.2,52.8 20.7,52.8 22.255,51.245 22.255,49.8 U31.7@22.255,48.17
RS485_DE/RE: R234.1 U7.M29 | length 51.2
  1-TOP w0.2: U7.M29@-6.4,17.83 -6.3,17.93 v1(-6.3,25) ; v1(22.1,25.3) 22.1,37.6 23.5,39 R234.1@23.5,40.22
  3-INTOP w0.2: v1(-6.3,25) 21.8,25 v1(22.1,25.3)
RS485_RX: J62.1 R233.1 | length 137.9
  1-TOP w0.2: v1(21.6,35) 21.6,38.2 22.2,38.8 R233.1@22.2,40.22
  3-INTOP w0.2: v1@-44.1,35 v1(21.6,35)
  6-INBOT w0.2: J62.1@-59.7,-17.7 -59.7,-16.6 -59.4,-16.3 -46.5,-16.3 -45.1,-14.9 -45.1,0.9 -44.1,1.9 v1(-44.1,34.995)
RS485_TX: J61.1 R235.1 | length 142.2
  1-TOP w0.2: v1(22.6,34.5) 22.6,36.4 24.8,38.6 R235.1@24.8,40.22
  3-INTOP w0.2: v1(-43.5,34.5) v1(22.6,34.5)
  6-INBOT w0.2: J61.1@-59.7,-20.6 -59.7,-19.5 -59.4,-19.2 -46.3,-19.2 -44.5,-17.4 -44.5,-0.4 -43.5,0.6 v1(-43.5,34.5)
RTC_I2C_SCL: R230.2 U30.3 | length 14.9
  1-TOP w0.2: R230.2@69.4,20.18 70.12,20.18 73.1,17.2 81.1,17.2 82.1,18.2 U30.3@82.7,18.2
RTC_I2C_SDA: R231.2 U30.4 | length 14
  1-TOP w0.2: R231.2@69.2,17.1 72.4,17.1 72.9,16.6 81.4,16.6 82.1,17.3 U30.4@82.7,17.3
RTC_INT_N: R228.1 U7.AN4 | length 89.6
  1-TOP w0.2: U7.AN4@20.32,-13.97 21.93,-13.97 v1(22.7,-13.2) ; v1(78.7,18) R228.1@79.42,18
  3-INTOP w0.2: v1(22.7,-13.2) 23.2,-12.7 77.4,-12.7 v1(78.7,-11.4)
  6-INBOT w0.2: v1(78.7,-11.4) v1(78.7,18)
SAI3_MCLK: TP13.1 U7.B24 U27.5 | length 74.6
  1-TOP w0.2: U27.5@-64.6,28.97 -64.6,25 -64.2,24.6 -63.2,24.6 v1(-62.5,25.3) TP13.1@-62.5,26.2 ; v1(-21.2,13.5) -21.2,12.6 -20.665,12.065 -19.685,12.065 U7.B24@-19.05,11.43
  3-INTOP w0.2: v1(-62.5,25.3) -61,26.8 -59.8,26.8 -57.7,28.9 -49.3,28.9 -46.1,32.1 v1(-20.8,32.1)
  8-BOTTOM w0.2: v1(-21.2,13.5) -21.6,13.9 -21.6,16.8 -20.8,17.6 v1(-20.8,32.1)
SAI3_RXD: TP17.1 U7.E21 U27.7 | length 69.1
  1-TOP w0.15: v1(-61.4,25.3) TP17.1@-61.4,26.2
  1-TOP w0.2: U27.7@-63.8,28.97 -63.8,27.9 -62.8,26.9 -62.1,26.9 TP17.1@-61.4,26.2 ; U7.E21@-15.24,7.62 v1(-14.605,8.255)
  3-INTOP w0.15: v1(-64,15.8) -47.6,15.8 -40.7,8.9 -15.25,8.9 v1(-14.605,8.255)
  6-INBOT w0.15: v1(-64,15.8) -64,21.207 -61.4,23.807 v1(-61.4,25.3)
SAI3_TXC: TP14.1 U7.E23 U27.8 | length 75.5
  1-TOP w0.15: v1(-60.3,25.3) TP14.1@-60.3,26.2
  1-TOP w0.2: U27.8@-63.4,28.97 -63.4,28.1 -62.6,27.3 -61.4,27.3 TP14.1@-60.3,26.2 ; v1(-15.875,10.795) U7.E23@-15.24,10.16
  3-INTOP w0.2: v1@-60.4,25.2 -57.2,28.4 -49.1,28.4 -45.9,31.6 v1(-15.9,31.6)
  8-BOTTOM w0.2: v1(-15.9,31.6) -15.9,23.4 -16.5,22.8 -16.5,17.4 -15.3,16.2 -15.3,11.37 v1(-15.875,10.795)
SAI3_TXD: TP16.1 U7.E20 U27.9 | length 71.3
  1-TOP w0.15: v1(-59.2,25.3) TP16.1@-59.2,26.2
  1-TOP w0.2: U27.9@-63,28.97 -63,28.3 -62.4,27.7 -60.7,27.7 TP16.1@-59.2,26.2 ; v1@-15.9,8.3 -15.9,7.01 U7.E20@-15.24,6.35
  3-INTOP w0.15: v1(-63.5,15.3) -47.7,15.3 -40,7.6 -16.53,7.6 v1(-15.875,8.255)
  6-INBOT w0.15: v1(-63.5,15.3) -63.5,21 -60.9,23.6 v1(-59.2,25.3)
SAI3_TXFS: TP15.1 U7.C19 U27.10 | length 74.1
  1-TOP w0.15: v1(-58.1,25.3) TP15.1@-58.1,26.2
  1-TOP w0.2: U27.10@-62.6,28.97 -62.6,28.5 -62.3,28.2 -60.1,28.2 TP15.1@-58.1,26.2 ; v1(-18.415,4.445) U7.C19@-17.78,5.08
  3-INTOP w0.15: v1(-63,6.9) -42.4,6.9 -39.475,3.975 -18.885,3.975 v1(-18.415,4.445)
  6-INBOT w0.15: v1(-63,6.9) -63,20.4 v1(-58.1,25.3)
SD2_CD_B: D24.1 J23.9 J23.10 R91.2 U7.G2 | length 47.3
  1-TOP w0.2: J23.10@-31.5,-52.3 J23.9@-25.8,-52.3 ; J23.9@-26.5,-52 -26.5,-49.4 -26.22,-49.12 R91.2@-25.8,-49.12 D24.1@-25.8,-48.25 -25.5,-48.25 -25.2,-47.95 -25.2,-41.3 -13.335,-29.435 -13.335,-17.145 U7.G2@-12.7,-16.51
SD2_CLK: D30.1 R93.1 U7.L1 | length 42.2
  1-TOP w0.2: R93.1@-19.3,-49.02 D30.1@-19.3,-48.25 -18.95,-48.25 -18.7,-48 -18.7,-38.8 -7.62,-27.72 -7.62,-22.275 -7.503,-22.158 -7.067,-22.158 ; U7.L1@-7.62,-17.78 -7.62,-19.241 -7.503,-19.358 -6.943,-19.358 -6.863,-19.438 -6.863,-19.678 -6.943,-19.758 -7.722,-19.758 -7.802,-19.838 -7.802,-20.078 -7.722,-20.158 -6.983,-20.158 -6.903,-20.238 -6.903,-20.478 -6.983,-20.558 -7.352,-20.558 -7.722,-20.558 -7.802,-20.638 -7.802,-20.878 -7.722,-20.958 -7.023,-20.958 -6.943,-21.038 -6.943,-21.278 -7.023,-21.358 -7.722,-21.358 -7.802,-21.438 -7.802,-21.678 -7.722,-21.758 -7.067,-21.758 ; -7.057,-22.158 -6.977,-22.078 -6.977,-21.838 -7.057,-21.758
SD2_CMD: D28.1 J23.3 R90.1 U7.F1 | length 55.5
  1-TOP w0.2: v1(-27.9,-51.3) -27.9,-49.3 -27.72,-49.12 R90.1@-27.1,-49.12 D28.1@-27.1,-48.25 -26.75,-48.25 -26.5,-48 -26.5,-41.8 -13.97,-29.27 -13.97,-21.892 -13.97,-21.792 -14.087,-21.675 -14.638,-21.675 -14.718,-21.595 -14.718,-21.355 -14.638,-21.275 -13.997,-21.275 -13.917,-21.195 -13.917,-20.955 -13.997,-20.875 -14.638,-20.875 -14.718,-20.795 -14.718,-20.555 -14.638,-20.475 -13.997,-20.475 -13.917,-20.395 -13.917,-20.155 -13.997,-20.075 -14.558,-20.075 -14.638,-19.995 -14.638,-19.755 -14.558,-19.675 -14.087,-19.675 -13.97,-19.558 -13.97,-19 U7.F1@-13.97,-17.78 ; J23.3@-26.8,-62.6 v1(-26.8,-61.5)
  8-BOTTOM w0.2: v1(-27.9,-51.3) -27.9,-60.4 v1(-26.8,-61.5)
SD2_DATA0: D25.1 J23.7 R92.1 U7.G1 | length 58.8
  1-TOP w0.2: J23.7@-31.2,-62.6 -31.2,-60.7 -23.7,-53.2 -23.7,-49.4 -23.98,-49.12 R92.1@-24.5,-49.12 D25.1@-24.5,-48.25 -24.05,-48.25 -23.9,-48.1 -23.9,-40.8 -12.7,-29.6 -12.7,-22.925 -12.7,-22.425 -12.583,-22.308 -12.098,-22.308 -12.018,-22.228 -12.018,-21.988 -12.098,-21.908 -12.694,-21.908 -12.774,-21.828 -12.774,-21.588 -12.694,-21.508 -12.098,-21.508 -12.018,-21.428 -12.018,-21.188 -12.098,-21.108 -12.694,-21.108 -12.774,-21.028 -12.774,-20.788 -12.694,-20.708 -12.098,-20.708 -12.018,-20.628 -12.018,-20.388 -12.098,-20.308 -12.694,-20.308 -12.774,-20.228 -12.774,-19.988 -12.694,-19.908 -12.11,-19.908 -12.03,-19.828 -12.03,-19.588 -12.11,-19.508 -12.583,-19.508 -12.7,-19.391 -12.7,-19.125 U7.G1@-12.7,-17.78
SD2_DATA1: D27.1 J23.8 U7.H1 | length 55.5
  1-TOP w0.2: J23.8@-32.3,-62.6 v1(-32.3,-61.5) ; v1(-23.2,-48.9) D27.1@-23.2,-48.25 -22.85,-48.25 -22.6,-48 -22.6,-40.3 -11.43,-29.13 U7.H1@-11.43,-17.78
  8-BOTTOM w0.2: v1(-32.3,-61.5) -29.1,-58.3 -29.1,-51.6 -27.4,-49.9 -24.2,-49.9 v1(-23.2,-48.9)
SD2_DATA2: D29.1 J23.1 U7.J1 | length 55.5
  1-TOP w0.2: J23.1@-24.6,-62.6 v1(-24.6,-61.5) ; v1(-21.9,-53) D29.1@-21.9,-48.25 -21.55,-48.25 -21.2,-47.9 -21.2,-39.7 -10.16,-28.66 -10.16,-22.5 -10.16,-22.4 -10.277,-22.283 -10.718,-22.283 -10.798,-22.203 -10.798,-21.963 -10.718,-21.883 -10.124,-21.883 -10.044,-21.803 -10.044,-21.563 -10.124,-21.483 -10.718,-21.483 -10.798,-21.403 -10.798,-21.163 -10.718,-21.083 -10.124,-21.083 -10.044,-21.003 -10.044,-20.763 -10.124,-20.683 -10.718,-20.683 -10.798,-20.603 -10.798,-20.363 -10.718,-20.283 -10.124,-20.283 -10.044,-20.203 -10.044,-19.963 -10.124,-19.883 -10.485,-19.883 -10.565,-19.803 -10.565,-19.563 -10.485,-19.483 -10.277,-19.483 -10.16,-19.366 -10.16,-19.151 U7.J1@-10.16,-17.78
  8-BOTTOM w0.2: v1(-24.6,-61.5) -24.6,-55.7 v1(-21.9,-53)
SD2_DATA3: D26.1 J23.2 U7.K1 | length 55.5
  1-TOP w0.2: J23.2@-25.7,-62.2 v1(-25.7,-61.1) ; v1(-20.6,-51.7) D26.1@-20.6,-48.25 -20.15,-48.25 -20,-48.1 -20,-39.3 -8.89,-28.19 -8.89,-22.493 -8.89,-22.393 -9.007,-22.275 -9.31,-22.275 -9.39,-22.195 -9.39,-21.955 -9.31,-21.875 -8.798,-21.875 -8.718,-21.795 -8.718,-21.555 -8.798,-21.475 -9.31,-21.475 -9.39,-21.395 -9.39,-21.155 -9.31,-21.075 -8.798,-21.075 -8.718,-20.995 -8.718,-20.755 -8.798,-20.675 -9.288,-20.675 -9.368,-20.595 -9.368,-20.355 -9.288,-20.275 -8.89,-20.275 -8.81,-20.195 -8.81,-19.955 -8.89,-19.875 -9.007,-19.875 -9.087,-19.795 -9.087,-19.555 -9.007,-19.475 -8.89,-19.358 -8.89,-18.794 U7.K1@-8.89,-17.78
  8-BOTTOM w0.2: v1(-25.7,-61.1) -25.7,-55.96 -21.44,-51.7 v1(-20.6,-51.7)
SD2_VSELECT: U7.AH13 U7.AN5 | length 26
  1-TOP w0.2: U7.AH13@13.97,-2.54 v1(14.605,-3.175) ; U7.AN5@20.32,-12.7 22.2,-12.7 22.8,-12.1 v1(24.9,-12.1)
  3-INTOP w0.2: v1(14.605,-3.175) 15.725,-3.175 16.3,-2.6 20.5,-2.6 20.7,-2.4 v1(24.9,-2.4)
  6-INBOT w0.2: v1(24.9,-12.1) v1(24.9,-2.4)
SHLD: J26.SHLD1 J26.SHLD2 J27.SHLD1 J27.SHLD2 J32.M1 J32.M2 J32.M3 J32.M4 J33.SH1 J33.SH2 J33.SH3 J33.SH4 J63.MT1 J63.MT2 J63.MT3 J63.MT4 R100.2 | length 266.4
  1-TOP w0.5: v2(38.94,-62.61) J32.M4@40.6,-62.61 ; J32.M4@40.65,-62.61 v2(40.65,-60.9) ; v2(40.65,-58.7) J32.M2@40.65,-56.65 ; J32.M3@56.75,-62.61 v2(56.75,-60.95) ; v2(56.75,-58.7) J32.M1@56.75,-56.65 ; J32.M3@56.8,-62.61 v2(58.46,-62.61)
  1-TOP w1: J27.SHLD2@-39.99,-54.752 -37.652,-54.752 -37,-54.1 R100.2@-37,-52.2
  8-BOTTOM w1: J26.SHLD1@-77.17,-54.752 J26.SHLD2@-61.46,-54.752 J27.SHLD1@-55.7,-54.752 -47.845,-54.752 ; J27.SHLD2@-39.99,-54.752 -47.845,-54.752 ; v2(40.65,-58.7) 40.65,-59.8 ; v2(56.75,-58.7) 56.75,-59.9 ; J63.MT1@86.58,-60.345 86.58,-61.5 86.28,-61.8 J63.MT3@86.28,-65.705 ; J63.MT2@95.22,-60.245 95.22,-61.42 95.52,-61.72 J63.MT4@95.52,-65.605 ; J33.SH2@99.36,-51.42 J33.SH1@99.36,-57.1 ; J33.SH4@112.5,-51.42 J33.SH3@112.5,-57.1 J33.SH1@99.36,-57.1 ; -47.845,-54.752 -47.845,-62.455 -43.5,-66.8 37.9,-66.8 38.94,-65.76 v2(38.94,-62.61) v2(40.65,-60.9) 40.65,-59.8 ; 40.65,-59.8 56.65,-59.8 56.75,-59.9 ; 56.75,-59.9 56.75,-60.9 v2(58.46,-62.61) 58.46,-65.36 59.9,-66.8 82.9,-66.8 83.995,-65.705 J63.MT3@86.28,-65.705 ; J63.MT3@86.28,-65.705 J63.MT4@95.52,-65.705 97.995,-65.705 99.36,-64.34 J33.SH1@99.36,-57.1
SPI8_MISO: J39.5 U7.E22 | length 176.5
  1-TOP w0.2: v1(-15.875,9.525) U7.E22@-15.24,8.89 ; J39.5@102.14,-4.725 102.14,15.84 106.4,20.1 v1(106.4,22.4)
  3-INTOP w0.2: v1(-16.5,24) 51.6,24 57,29.4 67.1,29.4 67.5,29 67.5,23.3 68.4,22.4 v1(106.4,22.4)
  6-INBOT w0.2: v1(-16.5,24) -16.5,17.3 -15.2,16 -15.2,10.2 v1(-15.875,9.525)
SPI8_MOSI: J39.6 U7.E18 | length 186.2
  1-TOP w0.2: v1(-15.875,4.445) U7.E18@-15.24,3.81 ; J39.6@99.6,-4.725 99.6,14.7 105.9,21 v1(105.9,22.9)
  3-INTOP w0.2: v1(-18.3,24.5) 51.393,24.5 56.793,29.9 67.8,29.9 68.6,29.1 68.6,23.6 69.3,22.9 v1(105.9,22.9)
  6-INBOT w0.2: v1(-18.3,24.5) -18.3,18.3 -17.8,17.8 -17.8,9.5 -17.18,8.88 -15.58,8.88 -15.2,8.5 -15.2,5.12 v1(-15.875,4.445)
SPI8_SCK: J39.4 U7.D17 | length 166.7
  1-TOP w0.2: v1(-17.145,3.175) U7.D17@-16.51,2.54
  3-INTOP w0.2: v1(-17.9,-25.4) 2.3,-25.4 6.9,-30 41.9,-30 43,-28.9 77.6,-28.9 95.9,-10.6 102.1,-10.6 104.68,-8.02 J39.4@104.68,-4.725
  8-BOTTOM w0.2: v1(-17.9,-25.4) -17.9,2.42 v1(-17.145,3.175)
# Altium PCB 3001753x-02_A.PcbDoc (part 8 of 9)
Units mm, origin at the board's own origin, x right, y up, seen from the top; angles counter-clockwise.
Board outline 210 x 130 mm, 8 copper layers (1-TOP, 2-GND, 3-INTOP, 4-PWR, 5-PWR, 6-INBOT, 7-GND, 8-BOTTOM), stack 1.646 mm thick; 651 components, 607 nets, 2780 pads, 1706 vias.

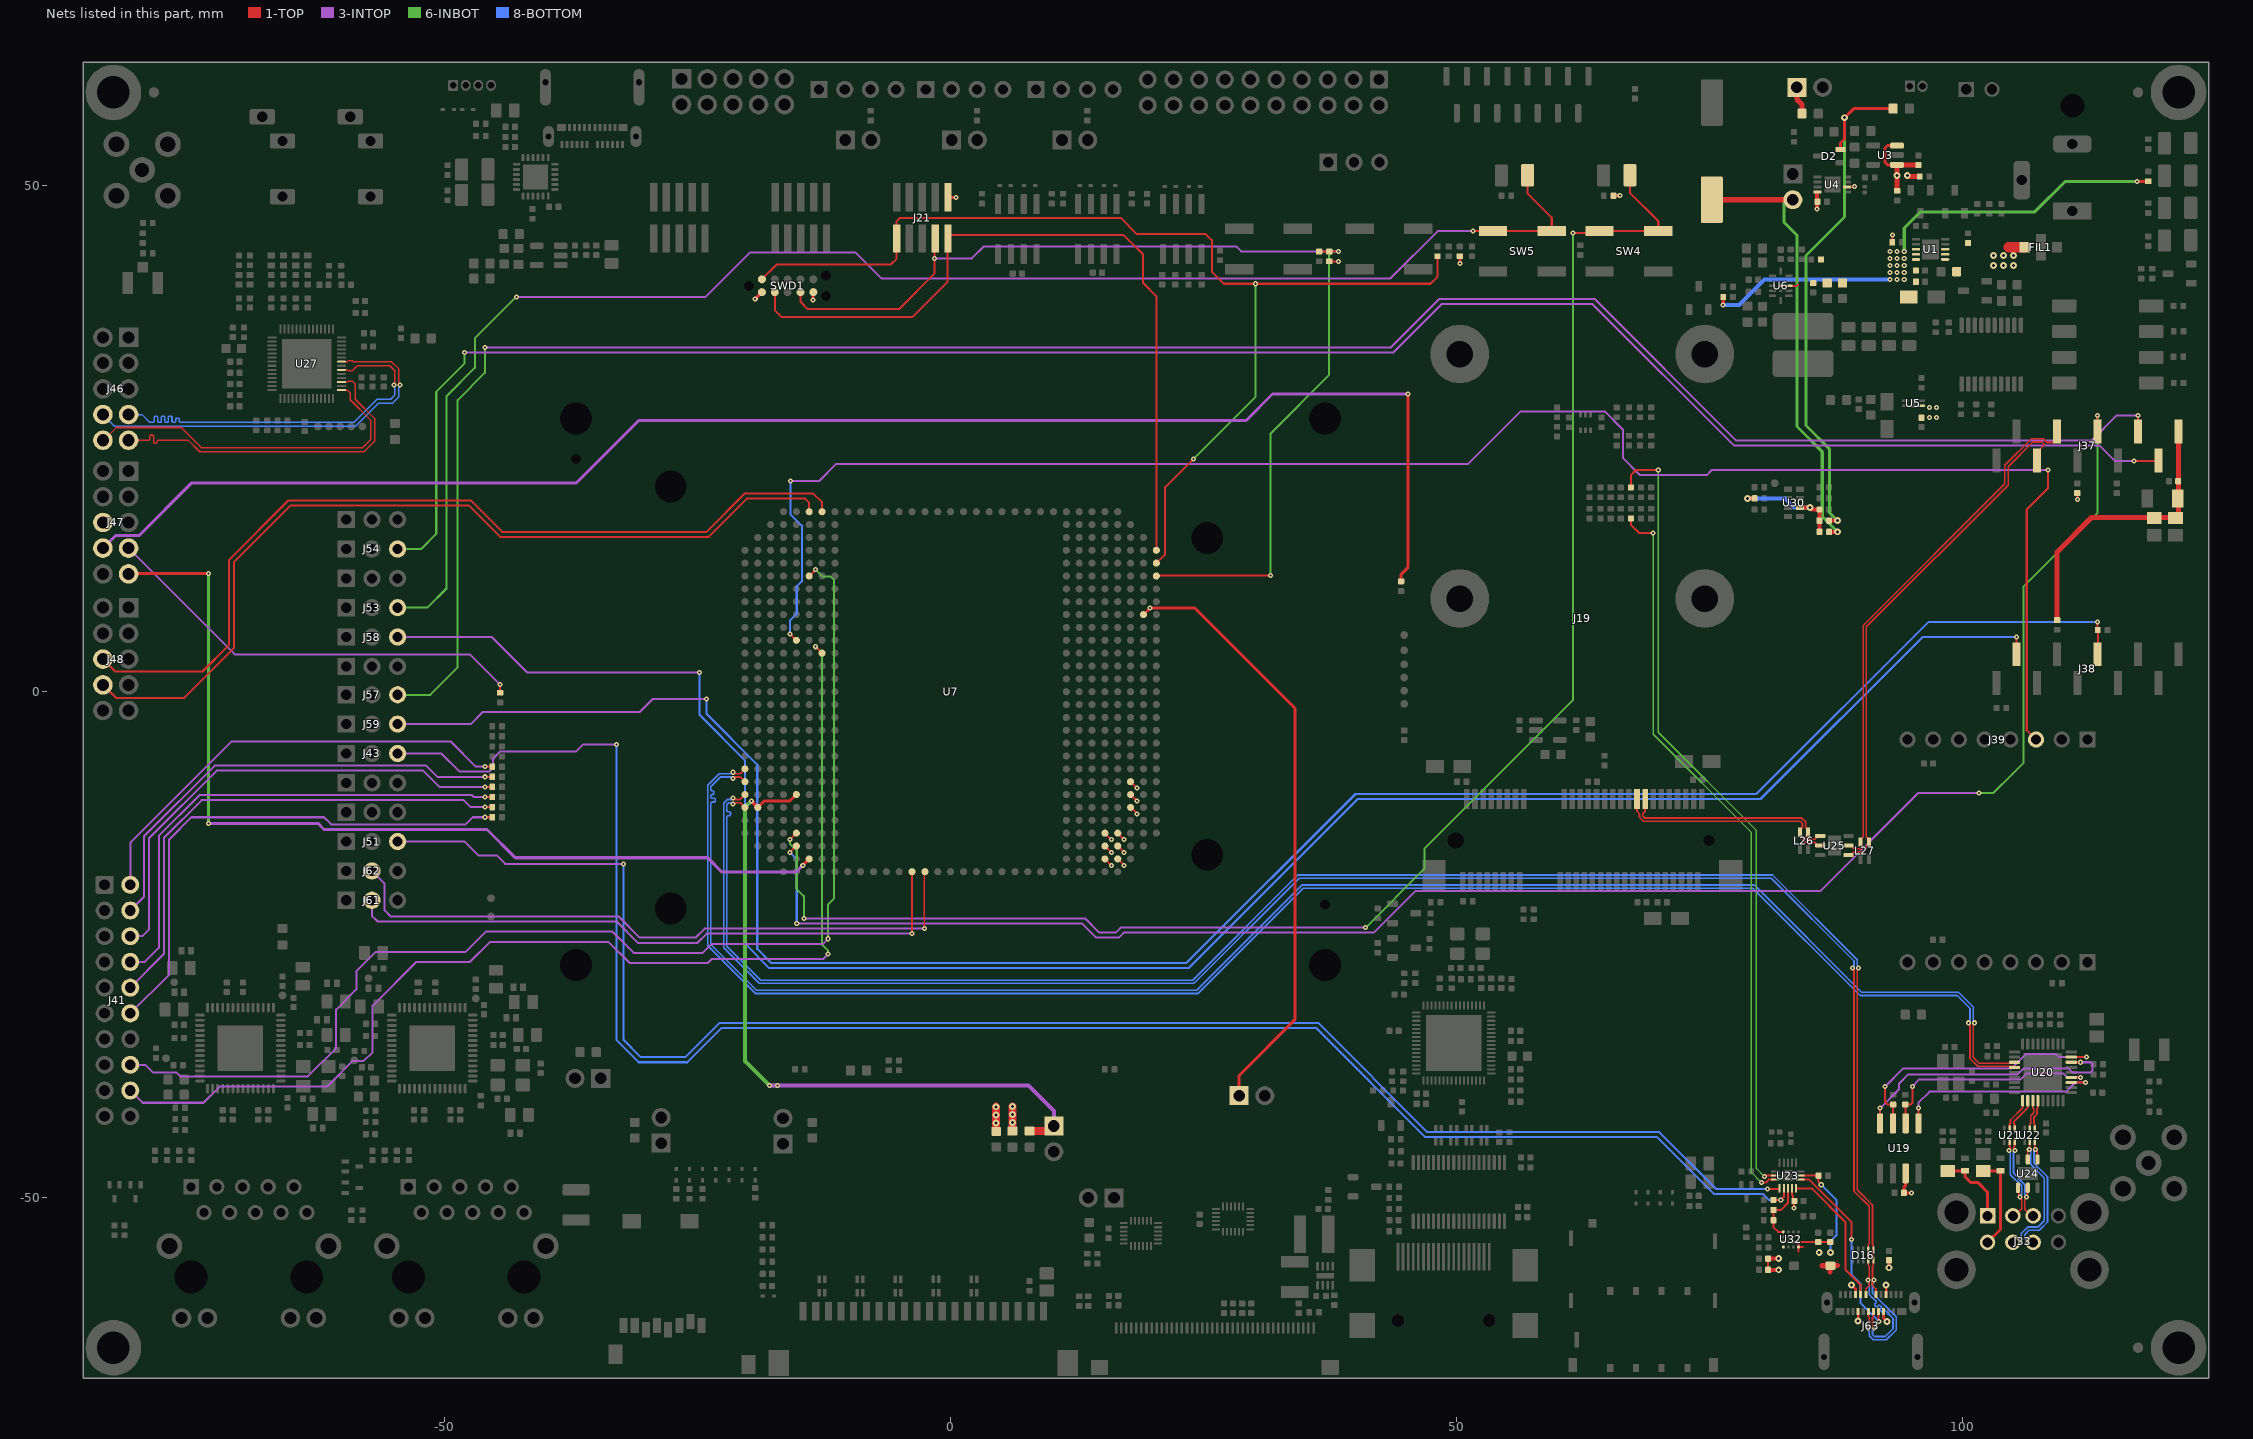
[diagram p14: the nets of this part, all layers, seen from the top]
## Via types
v1: diameter 0.5, hole 0.2, 1-TOP to 8-BOTTOM, 1453 vias
v2: diameter 0.68, hole 0.3, 1-TOP to 8-BOTTOM, 253 vias

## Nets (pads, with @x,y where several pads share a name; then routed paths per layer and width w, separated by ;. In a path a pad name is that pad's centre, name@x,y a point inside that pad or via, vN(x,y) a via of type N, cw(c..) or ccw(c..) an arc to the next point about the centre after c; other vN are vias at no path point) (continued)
SPI8_SS: J39.3 U7.E19 | length 176.3
  1-TOP w0.2: v1(-15.875,5.715) U7.E19@-15.24,5.08 ; J39.3@107.22,-4.725 106.3,-3.805 106.3,18 108.4,20.1 v1(108.4,21.9)
  3-INTOP w0.2: v1(-15.8,20.8) -13,20.8 -11.3,22.5 51.127,22.5 56.327,27.7 64.6,27.7 66.4,25.9 66.4,23.1 68.1,21.4 74.7,21.4 75.2,21.9 v1(108.4,21.9)
  8-BOTTOM w0.2: v1(-15.875,5.715) -15.875,7.025 -15.2,7.7 -15.2,10.4 -14.7,10.9 -14.7,16.4 -15.8,17.5 v1(-15.8,20.8)
SPKL_N: J46.8 U27.22 | length 39.8
  1-TOP w0.15: U27.22@-60.17,32.6 -59.6,32.6 -59.525,32.675 -59.075,32.675 -59,32.6 -55.234,32.6 -54.5,31.866 -54.5,30.4 v1(-54.4,30.3)
  8-BOTTOM w0.15: J46.8@-83.74,27.38 -82.56,26.2 -58.8,26.2 -56.5,28.5 -55.134,28.5 -54.5,29.134 -54.5,30.2 v1(-54.4,30.3)
SPKL_P: J46.7 U27.20 | length 39.8
  1-TOP w0.15: U27.20@-60.17,31.8 -59.6,31.8 -59.525,31.725 -59.075,31.725 -58.8,32 -58.6,32.2 -55.4,32.2 -54.9,31.7 -54.9,30.4 v1(-55,30.3)
  8-BOTTOM w0.15: J46.7@-81.2,27.38 -79.88,27.38 -79.1,26.6 -78.825,26.6 -78.75,26.6 -78.662,26.688 -78.662,27.142 -78.592,27.212 -78.382,27.212 -78.312,27.142 -78.312,26.67 -78.242,26.6 -78.032,26.6 -77.962,26.67 -77.962,27.142 -77.892,27.212 -77.682,27.212 -77.612,27.142 -77.612,26.67 -77.542,26.6 -77.332,26.6 -77.262,26.67 -77.262,27.142 -77.192,27.212 -76.982,27.212 -76.912,27.142 -76.912,26.67 -76.842,26.6 -76.632,26.6 -76.562,26.67 -76.562,26.965 -76.492,27.035 -76.282,27.035 -76.212,26.965 -76.212,26.688 -76.124,26.6 -75.907,26.6 -58.966,26.6 -56.666,28.9 -55.3,28.9 -54.9,29.3 -54.9,30.2 v1(-55,30.3)
SPKR_N: J46.10 U27.15 | length 34.4
  1-TOP w0.15: J46.10@-83.64,24.86 -82.4,26.1 -76,26.1 -74,24.1 -58.1,24.1 -57.3,24.9 -57.3,26.834 -59.3,28.834 -59.3,29.5 -59.525,29.725 -59.6,29.8 U27.15@-60.17,29.8
SPKR_P: J46.9 U27.17 | length 34.4
  1-TOP w0.15: J46.9@-81.1,24.86 -79.25,24.86 -79.175,24.86 -79.087,24.948 -79.087,25.29 -79.017,25.36 -78.807,25.36 -78.737,25.29 -78.737,24.623 -78.667,24.553 -78.457,24.553 -78.387,24.623 -78.387,24.772 -78.299,24.86 -77.875,24.86 -75.326,24.86 -74.166,23.7 -57.934,23.7 -56.9,24.734 -56.9,27 -58.8,28.9 -58.8,30.4 -59.075,30.675 -59.525,30.675 -59.6,30.6 U27.17@-60.17,30.6
SUPERCAP: C9.1 J5.2 R227.2 | length 43
  1-TOP w0.4: R227.2@86.78,15.8 v2(87.6,15.8)
  1-TOP w0.5: C9.1@75.1,48.6 J5.2@82.3,48.6
  6-INBOT w0.3: J5.2@82.3,48.6 82.3,46.4 83.6,45.1 83.6,26.2 86.1,23.7 86.1,17.3 v2(87.6,15.8)
SW_EN: J47.9 U7.F2 | length 94.5
  1-TOP w0.3: J47.9@-81.2,11.64 -81.14,11.7 v1(-73.3,11.7) ; v1(-14.605,-17.145) U7.F2@-13.97,-16.51
  3-INTOP w0.3: v1(-73.3,-13) -62.5,-13 -61.9,-13.6 -45.8,-13.6 -43,-16.4 -24,-16.4 -22.6,-17.8 -15.26,-17.8 v1(-14.605,-17.145)
  6-INBOT w0.3: v1(-73.3,-13) v1(-73.3,11.7)
SWD_CLK/PWR_IO: J21.4 R1.1 R2.2 SWD1.4 U7.AN24 | length 108.3
  1-TOP w0.2: SWD1.4@-14.83,39.465 -14.83,38.53 -14.1,37.8 -5.1,37.8 -1.6,41.3 v1(-1.6,42.8) -1.6,44.698 J21.4@-1.53,44.768 ; U7.AN24@20.32,11.43 20.39,11.5 v1(31.6,11.5) ; R2.2@36.4,43.48 R1.1@37.4,43.48 37.42,43.5 v1(38.3,43.5)
  3-INTOP w0.2: v1(-1.6,42.8) 2.1,42.8 3.3,44 28.2,44 28.7,43.5 v1(38.3,43.5)
  6-INBOT w0.2: v1(31.6,11.5) 31.6,25.5 37.4,31.3 37.4,43.1 37.8,43.5 v1(38.3,43.5)
SWD_DIO: J21.2 SWD1.2 U7.AN26 | length 75.3
  1-TOP w0.2: SWD1.2@-17.37,39.465 -17.37,37.67 -16.7,37 -3.8,37 -0.3,40.5 J21.2@-0.3,44.989 ; J21.2@-0.26,44.768 J21.2@0.072,45.1 ; J21.2@-0.2,45.1 J21.2@0.072,45.1 ; U7.AN26@20.32,13.97 20.32,39.08 19,40.4 19,43.2 17.1,45.1 J21.2@0.072,45.1
SWIN: J47.7 R41.1 | length 43.1
  1-TOP w0.2: R41.1@-44.5,-0.1 v1(-44.5,0.7)
  3-INTOP w0.2: J47.7@-81.2,14.18 -70.72,3.7 -50.5,3.7 -47.5,3.7 v1(-44.5,0.7)
SWOUT: J47.8 R42.1 | length 154
  1-TOP w0.3: R42.1@44.5,10.9 44.5,11.6 45.2,12.3 v1(45.2,29.4)
  3-INTOP w0.3: J47.8@-83.74,14.18 -82.5,15.42 -80.18,15.42 -75,20.6 -37,20.6 -30.8,26.8 29.2,26.8 31.8,29.4 v1(45.2,29.4)
SYS_RESET: J21.10 R5.2 SWD1.10 U7.AN25 | length 112
  1-TOP w0.2: SWD1.10@-18.64,40.735 -17.175,42.2 -5.9,42.2 -5.34,42.76 J21.10@-5.34,44.768 J21.10@-5.34,45.76 ; J21.10@-5.5,43.736 -5.5,45.6 J21.10@-5.34,45.76 ; J21.10@-5.3,45.8 J21.10@-5.34,45.76 ; U7.AN25@20.32,12.7 21.2,13.58 21.2,20.2 v1(24,23) ; R5.2@48.1,43.02 48.1,41 47.4,40.3 v1(30.1,40.3) 27,40.3 25.8,41.5 25.8,44.6 25.2,45.2 18.4,45.2 16.8,46.8 -5,46.8 -5.34,46.46 J21.10@-5.34,45.76
  6-INBOT w0.2: v1(24,23) 30.1,29.1 v1(30.1,40.3)
TAMPER0: J48.6 U7.G29 | length 87.6
  1-TOP w0.2: J48.6@-83.74,3.24 -82.5,2 -73.9,2 -71.3,4.6 -71.3,13.007 -65.407,18.9 -47.4,18.9 -44.3,15.8 -24.107,15.8 -20.307,19.6 -13.6,19.6 -12.7,18.7 U7.G29@-12.7,17.78
TAMPER1: J48.8 U7.F29 | length 87.1
  1-TOP w0.2: J48.8@-83.74,0.7 -82.44,-0.6 -75.7,-0.6 -70.8,4.3 -70.8,12.8 -65.2,18.4 -47.607,18.4 -44.507,15.3 -23.9,15.3 -20.1,19.1 -14.4,19.1 -13.97,18.67 U7.F29@-13.97,17.78
U1_N: U20.1 U21.2 | length 3.3
  1-TOP w0.168: U21.2@104.6,-43.15 104.6,-42.7 104.691,-42.609 104.691,-42.309 105.9,-41.1 U20.1@105.9,-40.4
U1_P: U20.2 U21.1 | length 3.4
  1-TOP w0.168: U21.1@105.1,-43.15 105.1,-42.7 105.009,-42.609 105.009,-42.491 106.4,-41.1 U20.2@106.4,-40.4
U2_N: U20.3 U22.2 | length 2.9
  1-TOP w0.168: U22.2@106.6,-43.15 106.6,-42.7 106.691,-42.609 106.691,-41.9 106.991,-41.6 106.991,-41.191 106.9,-41.1 U20.3@106.9,-40.4
U2_P: U20.4 U22.1 | length 2.9
  1-TOP w0.168: U22.1@107.1,-43.15 107.1,-42.7 107.009,-42.609 107.009,-42.454 107.009,-42.3 107.009,-42.032 107.309,-41.732 107.309,-41.191 107.4,-41.1 U20.4@107.4,-40.4
UART7_RX: J62.2 U7.R1 | length 64.9
  1-TOP w0.15: v1(-2.6,-23.4) -2.6,-17.84 U7.R1@-2.54,-17.78
  3-INTOP w0.2: J62.2@-57.16,-17.7 -55.9,-18.96 -55.9,-21.6 -55.3,-22.2 -32.793,-22.2 -30.693,-24.3 -25.2,-24.3 -24.3,-23.4 v1(-2.6,-23.4)
UART7_TX: J61.2 U7.P1 | length 62.5
  1-TOP w0.2: U7.P1@-3.81,-17.78 -3.81,-23.89 v1(-3.8,-23.9)
  3-INTOP w0.2: J61.2@-57.16,-20.6 -57.16,-22.14 -56.6,-22.7 -33,-22.7 -30.9,-24.8 -25,-24.8 -24.1,-23.9 v1(-3.8,-23.9)
ULED/BUTTON_1: D17.K SW4.1 SW4.2 U7.E4 | length 157.8
  1-TOP w0.2: v1(-15.875,-14.605) U7.E4@-15.24,-13.97 ; v1(61.5,45.3) 63.9,45.3 SW4.1@64.1,45.5 SW4.2@69.9,45.5 69.9,46.5 67.1,49.3 D17.K@67.1,51.025
  3-INTOP w0.2: v1(-14.5,-22.4) 13.3,-22.4 14.7,-23.8 16.3,-23.8 16.8,-23.3 v1(41,-23.3)
  6-INBOT w0.2: v1(-15.875,-14.605) -15.875,-15.025 -15.2,-15.7 -15.2,-19.5 -14.5,-20.2 v1(-14.5,-22.4) ; v1(41,-23.3) 46.8,-17.5 46.8,-15.5 61.5,-0.8 v1(61.5,45.3)
ULED/BUTTON_2: D18.K J53.3 SW5.1 SW5.2 | length 150.9
  1-TOP w0.2: v1(51.6,45.5) SW5.1@53.581,45.5 SW5.2@59.381,45.5 59.381,46.819 57,49.2 D18.K@57,51.025
  3-INTOP w0.2: v1(-42.9,39) -24.2,39 -19.8,43.4 -9.4,43.4 -6.8,40.8 43.4,40.8 48.1,45.5 v1(51.6,45.5)
  6-INBOT w0.2: J53.3@-54.62,8.3 -51.7,8.3 -49.8,10.2 -49.8,29.2 -47,32 -47,34.9 v1(-42.9,39)
USB_HUB_N: U7.A8 U20.30 | length 166
  1-TOP w0.168: v1(-21.5,-8.555) -21.359,-8.414 -20.796,-8.414 U7.A8@-20.32,-8.89 ; v1(101.159,-32.7) 101.018,-32.841 101.018,-36.118 101.591,-36.691 105.009,-36.691 U20.30@105.1,-36.6
  8-BOTTOM w0.168: v1(-21.5,-8.555) -21.641,-8.414 -22.714,-8.414 -23.682,-9.382 -23.682,-9.557 -23.682,-9.687 -23.584,-9.785 -23.467,-9.785 -23.394,-9.859 -23.394,-10.079 -23.467,-10.153 -23.608,-10.153 -23.682,-10.227 -23.682,-10.447 -23.608,-10.521 -23.33,-10.521 -23.256,-10.595 -23.256,-10.815 -23.33,-10.889 -23.584,-10.889 -23.682,-10.987 -23.682,-11.439 -23.682,-24.968 -19.168,-29.482 24.318,-29.482 34.718,-19.082 79.382,-19.082 89.982,-29.682 99.557,-29.682 100.6,-30.725 ; 100.618,-30.743 101.018,-31.143 101.018,-32.559 v1(101.159,-32.7)
USB_HUB_P: U7.A9 U20.31 | length 166
  1-TOP w0.168: v1(-21.5,-7.955) -21.359,-8.096 -20.796,-8.096 U7.A9@-20.32,-7.62 ; v1(100.559,-32.7) 100.7,-32.841 100.7,-36.25 101.459,-37.009 105.009,-37.009 U20.31@105.1,-37.1
  8-BOTTOM w0.168: v1(-21.5,-7.955) -21.641,-8.096 -22.846,-8.096 -24,-9.25 -24,-25.1 -19.3,-29.8 24.45,-29.8 34.85,-19.4 79.25,-19.4 89.85,-30 99.425,-30 100.7,-31.275 100.7,-32.559 v1(100.559,-32.7)
USB_OTG1_N: D16.1 D16.10 J63.A7 J63.B7 U7.A6 | length 183.4
  1-TOP w0.168: v1(-21.5,-11.095) -21.359,-10.954 -20.796,-10.954 U7.A6@-20.32,-11.43 ; v1(89.7,-27.3) 89.559,-27.441 89.559,-49.209 91.059,-50.709 91.059,-54.554 91.15,-54.645 D16.1@91.15,-55.145 D16.10@91.15,-56.15 91.15,-56.65 91.059,-56.741 91.059,-57.959 v1(91.2,-58.1) 91.059,-58.241 91.059,-58.659 91.4,-59 J63.A7@91.4,-59.535 ; v1(90.6,-62.9) 90.741,-62.759 90.741,-61.8 90.65,-61.709 J63.B7@90.65,-61.235
  8-BOTTOM w0.168: v1(-21.5,-11.095) -21.641,-10.954 -21.9,-10.954 -22.1,-11.154 -22.1,-11.772 -22.002,-11.87 -21.81,-11.87 -21.736,-11.944 -21.736,-12.164 -21.81,-12.238 -22.002,-12.238 -22.1,-12.336 -22.1,-25.15 -18.758,-28.492 23.908,-28.492 34.3,-18.1 81.191,-18.1 89.559,-26.468 89.559,-27.159 v1(89.7,-27.3) ; v1(90.6,-62.9) 90.741,-63.041 90.741,-63.632 91.127,-64.018 92.432,-64.018 93.4,-63.05 93.4,-61.75 91.059,-59.409 91.059,-58.241 v1(91.2,-58.1)
USB_OTG1_P: D16.2 D16.9 J63.A6 J63.B6 U7.A7 | length 183.4
  1-TOP w0.168: v1(-21.5,-10.495) -21.359,-10.636 -20.796,-10.636 U7.A7@-20.32,-10.16 ; v1(89.1,-27.3) 89.241,-27.441 89.241,-49.341 90.741,-50.841 90.741,-54.554 90.65,-54.645 D16.2@90.65,-55.145 ; J63.A6@90.4,-59.535 90.4,-59 90.741,-58.659 90.741,-58.241 v1(90.6,-58.1) 90.741,-57.959 90.741,-56.741 90.65,-56.65 D16.9@90.65,-56.15 D16.2@90.65,-55.15 ; J63.B6@91.15,-61.235 91.15,-61.709 91.059,-61.8 91.059,-62.759 v1(91.2,-62.9)
  8-BOTTOM w0.168: v1(-21.5,-10.495) -21.641,-10.636 -22.032,-10.636 -22.418,-11.022 -22.418,-25.282 -18.89,-28.81 24.04,-28.81 34.432,-18.418 81.059,-18.418 89.241,-26.6 89.241,-27.159 v1(89.1,-27.3) ; v1(90.6,-58.1) 90.741,-58.241 90.741,-59.541 91.1,-59.9 91.159,-59.959 91.42,-60.22 91.42,-60.359 91.291,-60.487 91.291,-60.591 91.447,-60.748 91.551,-60.748 91.697,-60.601 91.801,-60.601 91.958,-60.758 91.958,-60.862 91.811,-61.008 91.811,-61.112 91.968,-61.268 92.072,-61.268 92.2,-61.139 92.339,-61.139 92.474,-61.274 92.533,-61.333 93.082,-61.882 93.082,-62.918 92.3,-63.7 91.259,-63.7 91.059,-63.5 91.059,-63.041 v1(91.2,-62.9)
USB_PCIe_D_N: J19.36 L26.3 U25.2 | length 22.1
  1-TOP w0.168: J19.36@67.8,-10.6 67.8,-11.8 68.041,-12.041 68.041,-12.391 68.45,-12.8 83.95,-12.8 84.141,-12.991 84.141,-13.404 84.043,-13.502 84.016,-13.502 83.9,-13.618 83.9,-14.118 84.016,-14.234 84.043,-14.234 84.141,-14.332 84.141,-14.574 84.451,-14.884 85.028,-14.884 85.386,-14.884 85.484,-14.982 85.484,-15.084 85.6,-15.2 U25.2@85.9,-15.2
USB_PCIe_D_P: J19.38 L26.2 U25.1 | length 21.6
  1-TOP w0.168: J19.38@68.6,-10.6 68.6,-11.8 68.359,-12.041 68.359,-12.259 68.582,-12.482 84.082,-12.482 84.459,-12.859 84.459,-13.404 84.557,-13.502 84.584,-13.502 84.7,-13.618 84.7,-14.118 84.584,-14.234 84.579,-14.234 84.485,-14.328 84.485,-14.468 84.583,-14.566 85.16,-14.566 85.386,-14.566 85.484,-14.468 85.484,-14.366 85.6,-14.25 U25.1@85.9,-14.25
USBC_ALERT_N: J43.3 R51.2 U23.10 | length 179.6
  1-TOP w0.2: R51.2@81.28,-50.2 v1(82,-50.2) 82.3,-49.9 U23.10@82.3,-49.05
  3-INTOP w0.2: J43.3@-54.62,-6.1 -50.3,-6.1 -48.5,-7.9 -45.6,-7.9 -45.2,-7.5 -45.2,-6.6 -44.5,-5.9 -37,-5.9 -36.3,-5.2 v1(-33,-5.2)
  8-BOTTOM w0.2: v1(-33,-5.2) -33,-34.407 -30.807,-36.6 -26,-36.6 -22.6,-33.2 36.093,-33.2 46.893,-44 69.8,-44 75.4,-49.6 80.2,-49.6 80.8,-50.2 v1(82,-50.2)
USBC_CC1: J63.A5 U23.13 | length 14
  1-TOP w0.2: U23.13@83.5,-49.05 85.05,-49.05 88.4,-52.4 88.4,-57.1 89.9,-58.6 J63.A5@89.9,-59.535
USBC_CC2: J63.B5 U23.14 | length 18.7
  1-TOP w0.2: U23.14@83.95,-48.2 84.8,-48.2 89,-52.4 v1(89,-54.1) ; J63.B5@91.65,-61.235 91.65,-62.15 v1(91.7,-62.2)
  8-BOTTOM w0.2: v1(89,-54.1) 89,-57.6 89.9,-58.5 89.9,-60.4 v1(91.7,-62.2)
USBC_FAULT_N: R149.2 R192.2 U23.11 U32.A4 | length 6
  1-TOP w0.2: U32.A4@82.25,-53.35 81.75,-53.35 81.28,-52.88 R149.2@81.28,-52.2 R192.2@81.28,-51.2 82,-51.2 82.7,-50.5 U23.11@82.7,-49.05
USBC_INT_B: J51.3 U23.9 | length 163.8
  1-TOP w0.2: v1(80.7,-49.1) 81.85,-49.1 U23.9@81.9,-49.05
  3-INTOP w0.2: J51.3@-54.62,-14.8 -48,-14.8 -46.6,-16.2 -44.8,-16.2 -44,-17 v1(-32.3,-17)
  8-BOTTOM w0.2: v1(-32.3,-17) -32.3,-34.4 -30.6,-36.1 -26.207,-36.1 -22.807,-32.7 36.3,-32.7 47.1,-43.5 70.007,-43.5 75.607,-49.1 v1(80.7,-49.1)
USBC_SCL: R47.2 U23.8 | length 73.3
  1-TOP w0.2: R47.2@67.2,17.12 67.2,16.5 68,15.7 v1(69.4,15.7) ; v1(80.1,-48.5) 80.5,-48.5 80.8,-48.2 U23.8@81.45,-48.2
  6-INBOT w0.15: v1(69.4,15.7) 69.4,14.3 69.4,-4.207 79.1,-13.907 79.1,-14.007 79.1,-30.704 79.1,-47.5 v1(80.1,-48.5)
USBC_SDA: R46.2 U23.7 | length 79.4
  1-TOP w0.2: R46.2@67.2,20.18 67.2,21.4 67.7,21.9 v1(69.9,21.9) ; v1(80.4,-47.9) 80.5,-47.8 U23.7@81.45,-47.8
  6-INBOT w0.15: v1(69.9,21.9) 69.9,16.6 69.9,11.3 69.9,-4 79.6,-13.7 79.6,-13.8 79.6,-30.4 79.6,-47.1 v1(80.4,-47.9)
USBC_VBUS: C147.2 C188.2 C199.2 C200.2 D21.K J63.A4 J63.A9 J63.B4 J63.B9 U23.15 U32.C2 U32.D1 U32.D2 | length 22.5
  1-TOP w0.2: U32.C2@83.25,-54.35 U32.D2@83.75,-54.35 ; 83.75,-55.3 U32.D1@83.75,-54.85 ; U32.D1@83.75,-54.75 U32.D1@83.75,-54.85 ; U23.15@83.95,-47.8 C188.2@85.74,-47.8 85.74,-48.44 v1(86,-48.7) ; 84.208,-54.85 U32.D1@83.75,-54.85 ; C200.2@86.9,-54.36 86.89,-54.35 U32.D2@83.75,-54.35 ; U32.D1@83.75,-54.85 U32.D2@83.75,-54.35
  1-TOP w0.25: v2(89,-58.6) 89.4,-59 J63.A4@89.4,-59.535 ; v2(89.65,-62.15) J63.B9@89.65,-61.235 ; J63.B4@92.15,-61.235 92.15,-61.85 v2(92.5,-62.2) ; J63.A9@92.4,-59.535 v2(92.4,-58.62)
  1-TOP w0.3: v2(92.7,-56.9) C147.2@92.7,-56.16
  1-TOP w0.5: 86.1,-56.7 D21.K@86.886,-56.7 ; D21.K@86.88,-56.688 D21.K@86.886,-56.688 ; 86.886,-57.3 D21.K@86.886,-56.7 ; 87.6,-56.688 D21.K@86.9,-56.688 ; D21.K@86.886,-56.7 D21.K@86.886,-56.688 ; D21.K@86.886,-56.7 D21.K@86.9,-56.7 D21.K@86.9,-56.688 ; D21.K@86.886,-56.688 D21.K@86.9,-56.688
  8-BOTTOM w0.2: v1(86,-48.7) 87.5,-50.2 87.5,-53.7 86.9,-54.3 v2(86.9,-55.4)
  other v2: 85.8,-55.4
USBH1_D_N: J33.A2 U21.5 U24.1 | length 9.5
  1-TOP w0.168: v1(104.55,-45.3) 104.591,-45.3 104.691,-45.2 104.691,-44.991 104.6,-44.9 U21.5@104.6,-44.45 ; J33.A2@104.93,-51.77 105.098,-51.77 105.796,-51.072 105.796,-50.156 105.63,-49.99 v1(105.63,-49.9) 105.5,-49.77 105.5,-49.02 U24.1@105.48,-49
  8-BOTTOM w0.168: v1(104.55,-45.3) 104.682,-45.432 104.682,-47.702 105.796,-48.816 105.796,-49.644 105.63,-49.81 v1(105.63,-49.9)
USBH1_D_P: J33.A3 U21.6 U24.2 | length 9.5
  1-TOP w0.168: U21.6@105.1,-44.45 105.1,-44.9 105.009,-44.991 105.009,-45.2 105.109,-45.3 v1(105.15,-45.3) ; U24.2@106.43,-49 106.344,-49.086 106.344,-49.836 v1(106.28,-49.9) 106.28,-49.99 106.114,-50.156 106.114,-51.122 106.762,-51.77 J33.A3@106.93,-51.77
  8-BOTTOM w0.168: v1(105.15,-45.3) 105,-45.45 105,-47.57 106.114,-48.684 106.114,-49.644 106.28,-49.81 v1(106.28,-49.9)
USBH1_OC_N: R139.1 U19.2 U20.13 | length 22.4
  1-TOP w0.2: R139.1@94.3,-40.8 94.3,-42.585 U19.2@94.345,-42.63 ; R139.1@94.3,-40.78 94.82,-40.78 95,-40.6 v1(95,-39) ; U20.13@110.7,-38.1 v1(111.6,-38.1)
  3-INTOP w0.2: v1(95,-39) 95.7,-38.3 105.7,-38.3 106.3,-37.7 109.9,-37.7 110.3,-38.1 v1(111.6,-38.1)
USBH1_PWR_EN: U19.1 U20.12 | length 20.8
  1-TOP w0.2: v1(95.6,-41.1) 95.6,-42.615 U19.1@95.615,-42.63 ; U20.12@110.7,-38.6 v1(112.1,-38.6)
  3-INTOP w0.2: v1(95.6,-41.1) 95.6,-40.6 96.7,-39.5 110.2,-39.5 111.1,-38.6 v1(112.1,-38.6)
USBH2_D_N: J33.B2 U22.5 U24.5 | length 13.7
  1-TOP w0.168: U24.5@106.4,-46.2 106.4,-45.35 v1(106.55,-45.2) 106.6,-45.15 U22.5@106.6,-44.45
  8-BOTTOM w0.168: J33.B2@104.93,-54.39 105.297,-54.39 105.652,-54.035 105.673,-54.035 105.771,-53.936 105.771,-53.509 106.398,-52.882 107.398,-52.882 108.03,-52.25 108.03,-48.03 106.691,-46.691 106.691,-45.341 v1(106.55,-45.2)
USBH2_D_P: J33.B3 U22.6 U24.4 | length 13.9
  1-TOP w0.168: v1@107.009,-45.109 v1@107.125,-45.225 ; U22.6@107.1,-44.45 107.1,-45.15 v1(107.15,-45.2) v1@107.125,-45.225 ; U24.4@107.35,-46.2 107.35,-45.45 v1@107.125,-45.225
  8-BOTTOM w0.168: J33.B3@106.93,-54.39 106.563,-54.39 106.208,-54.035 106.187,-54.035 106.089,-53.936 106.089,-53.641 106.53,-53.2 107.53,-53.2 108.348,-52.382 108.348,-47.898 107.009,-46.559 107.009,-45.341 v1(107.15,-45.2)
USBH2_OC_N: R140.1 U19.3 U20.17 | length 27.1
  1-TOP w0.2: v1(92.3,-39) 92.3,-40.5 92.58,-40.78 R140.1@93.1,-40.78 93.075,-40.805 U19.3@93.075,-42.63 ; U20.17@110.7,-36.1 v1(112.2,-36.1)
  3-INTOP w0.2: v1(92.3,-39) 94.1,-37.2 104.8,-37.2 106.2,-35.8 109.2,-35.8 109.5,-36.1 v1(112.2,-36.1)
USBH2_PWR_EN: U19.4 U20.16 | length 27.4
  1-TOP w0.2: v1(91.8,-41.1) 91.805,-41.105 U19.4@91.805,-42.63 ; U20.16@110.7,-36.6 v1(111.6,-36.6)
  3-INTOP w0.2: v1@91.86,-41.08 93.7,-39.24 93.7,-38.7 94.6,-37.8 105.4,-37.8 106,-37.2 110.4,-37.2 110.8,-37.6 112.6,-37.6 112.8,-37.4 112.8,-36.8 112.6,-36.6 v1(111.6,-36.6)
VBACKUP: C192.2 R225.2 R226.1 R227.1 U30.6 | length 11.5
  1-TOP w0.4: v2(78.7,19.1) R225.2@79.42,19.1 ; U30.6@83.9,18.2 v2(84.9,18.2) 85.1,18 C192.2@85.84,18 85.84,15.82 R227.1@85.82,15.8
  8-BOTTOM w0.4: v2(78.7,19.1) 82.4,19.1 83.3,18.2 v2(84.9,18.2)
VCC_MCA: C10.1 J3.1 J9.1 J21.1 J47.6 R1.2 R3.2 R16.2 R206.2 SWD1.1 SWD1.5 U4.2 U4.8 U7.AM21 | length 69.9
  1-TOP w0.2: R1.2@37.4,42.52 38.28,42.52 v1(38.3,42.5) ; U4.8@85.6,49.3 U4.8@85.65,49.35 ; U4.2@88.25,49.85 89.25,49.85 v1(89.3,49.9)
  1-TOP w0.3: v1(-19.3,38.8) -19.3,38.805 SWD1.1@-18.64,39.465 ; v1(-13.6,38.7) -13.6,39.425 SWD1.5@-13.56,39.465 SWD1.5@-13.56,39.446 ; J21.1@-0.04,48.832 v1(0.53,48.832) ; U7.AM21@19.05,7.62 v1(19.685,8.255) 24.145,8.255 34,-1.6 34,-32.4 28.5,-37.9 J9.1@28.5,-39.9 ; v1(50.3,42.3) R3.2@50.3,42.97 ; R206.2@65.485,49 v1(66.1,49)
  1-TOP w0.4: v1(85.6,47.7) U4.8@85.6,49.302
  1-TOP w0.5: J3.1@83.6,59.7 83.6,58.5 84.1,58 R16.2@84.1,57.1
VCC_RTC: D2.2 R17.2 R226.2 | length 51.9
  1-TOP w0.3: D2.2@87.9,53.55 87.9,54.2 88.3,54.6 v2(88.3,56.7) 89.2,57.6 R17.2@93.1,57.6
  1-TOP w0.4: R226.2@86.78,16.9 v2(87.6,16.9)
  6-INBOT w0.3: v2(87.6,16.9) 86.8,17.7 86.8,23.99 84.5,26.29 84.5,43.1 88.3,46.9 v2@88.3,56.658
VCC_USB_A: D22.2 J33.A1 L23.1 | length 7.7
  1-TOP w0.3: L23.1@98.5,-47.326 D22.2@100.2,-47.326 ; D22.2@100.4,-47.326 D22.2@100.2,-47.326 ; J33.A1@102.43,-51.77 102.43,-49.43 101.5,-48.5 100.8,-48.5 100.2,-47.9 D22.2@100.2,-47.326
VCC_USB_B: D23.2 J33.B1 L22.1 | length 9.3
  1-TOP w0.2: L22.1@102,-47.35 102.024,-47.326 L22.1@102.6,-47.326
  1-TOP w0.3: J33.B1@102.43,-54.39 103.7,-53.12 D23.2@103.7,-47.326 L22.1@102.6,-47.326
VIN: C1.2 C8.2 FIL1.3 R7.2 R8.2 R9.2 R10.2 U1.1 U1.2 U1.3 U3.1 U3.3 | length 12
  1-TOP w0.2: R9.2@93.02,44.4 v1(93.02,45.1)
  1-TOP w0.3: U3.1@93.48,52.05 92.55,52.05 92.3,52.3 92.3,53.7 92.55,53.95 U3.3@93.48,53.95
  1-TOP w0.5: U3.1@93.38,52.04 U3.1@93.48,52.04 ; v2@93.48,50.99 U3.1@93.48,52.04 ; U3.1@93.48,52.05 U3.1@93.48,52.04 ; R8.2@93.5,49.48 93.5,50.6 ; v2@94.56,51 v2(94.5,51) 94.6,50.9 R7.2@95.72,50.9 ; C8.2@95.6,52.04 U3.1@93.48,52.04
  1-TOP w1: 104.5,43.9 FIL1.3@106.1,43.9
  other v2: 103,42.1 104,42.1 105,42.1 103,43.1 104,43.1 105,43.1 93.5,51
VIN_PROT: C2.1 C3.2 C4.2 C12.2 C13.2 C14.2 C15.2 C139.1 C187.2 C197.2 C198.2 J6.1 R25.2 R27.2 R33.1 R154.2 R196.1 U1.8 U1.9 U1.10 U5.3 U6.3 U6.14 U7.B6 U7.E7 U19.7 U23.12 U32.A1 U32.A2 | length 125.3
  1-TOP w0.2: J6.1@9.7,-43.4 J6.1@10.2,-42.9 ; C198.2@80.76,-57.1 C197.2@80.76,-56 ; U6.14@82,40.1 U6.3@82.8,40.1 83.6,40.1 83.7,40.2 ; U23.12@83.1,-49.05 83.1,-49.7 83.2,-49.8 83.2,-50.16 C187.2@83.34,-50.3 83.3,-50.34 v1(83.3,-51) ; v1(111.3,19) R196.1@111.3,19.62
  1-TOP w0.3: U7.B6@-19.05,-11.43 -18.42,-10.8 -15.88,-10.8 U7.E7@-15.24,-10.16 ; v1(76.3,38.2) 76.32,38.22 R25.2@76.32,39 R25.2@76.32,39.1 ; U19.7@94.345,-47.57 94.345,-48.755 94.16,-48.94 C139.1@94.16,-49.5 v1(94.9,-49.5) ; v1(117.2,50.4) 117.22,50.42 R154.2@118.3,50.42
  1-TOP w0.4: v1(-19.685,-10.795) U7.B6@-19.05,-11.43 ; C198.2@80.76,-57.1 v2@81.6,-57.1 ; C197.2@80.76,-56 v2@81.6,-56
  1-TOP w0.8: R33.1@7.8,-43.4 J6.1@9.7,-43.4
  3-INTOP w0.4: v1(-17.9,-38.9) v1(-17.1,-38.9) 7.7,-38.9 10.2,-41.4 J6.1@10.2,-42.9
  6-INBOT w0.3: v1(94.2,43.5) 94.2,45.8 95.8,47.4 107.1,47.4 110.1,50.4 v1(117.2,50.4)
  6-INBOT w0.4: v1(-19.685,-10.795) -20.3,-11.41 -20.3,-36.5 v1(-17.9,-38.9) v1(-17.1,-38.9)
  8-BOTTOM w0.4: v1(76.3,38.2) 77.9,38.2 80.4,40.7 v1(92.8,40.7)
  other v1: 96.7,27.08 97.4,27.08 96.7,28.08 97.4,28.08 93.5,40.7 94.2,40.7 92.8,41.4 93.5,41.4 94.2,41.4 92.8,42.1 93.5,42.1 94.2,42.1 92.8,42.8 93.5,42.8 94.2,42.8 92.8,43.5 93.5,43.5
  other v2: 81.8,-57.1 81.8,-56
VSYS: R34.2 U7.AL6 U7.AL7 U7.AL8 | length 5.1
  1-TOP w0.2: U7.AL6@17.78,-11.43 v1(18.415,-12.065) ; U7.AL7@17.78,-10.16 v1(18.415,-10.795) ; U7.AL8@17.78,-8.89 v1(18.415,-9.525)
  1-TOP w0.8: R34.2@6.1,-43.4 v2(6.1,-40.97)
  other v2: 6.1,-42.57 6.1,-41.77
VSYS2: R35.2 U7.AJ2 U7.AJ3 U7.AJ4 U7.AK2 U7.AK3 U7.AK4 | length 7.8
  1-TOP w0.2: U7.AJ2@15.24,-16.51 v1(15.875,-17.145) ; U7.AJ3@15.24,-15.24 v1(15.875,-15.875) ; U7.AJ4@15.24,-13.97 v1(15.875,-14.605) ; U7.AK2@16.51,-16.51 v1(17.145,-17.145) ; U7.AK3@16.51,-15.24 v1(17.145,-15.875) ; U7.AK4@16.51,-13.97 v1(17.145,-14.605)
  1-TOP w0.8: R35.2@4.5,-43.43 v2(4.5,-42.6) v2(4.5,-41.8) v2(4.5,-41)
WL_DEV_WAKE: J41.16 U7.F24 | length 118.9
  1-TOP w0.2: U7.F24@-13.97,11.43 v1(-13.335,12.065)
  3-INTOP w0.2: J41.16@-81.03,-36.85 -79.55,-36.85 -78.8,-37.6 -76.5,-37.6 -76.1,-38 -63.5,-38 -60.7,-35.2 -60.7,-31.4 -58.7,-29.4 -58.7,-27.6 -56.8,-25.7 -47.9,-25.7 -45.9,-23.7 -33.4,-23.7 -31.8,-25.3 -31.3,-25.8 -24.5,-25.8 -23.6,-24.9 -12.6,-24.9 v1(-12.1,-24.4)
  6-INBOT w0.2: v1(-13.335,12.065) -12.67,11.4 -11.9,11.4 -11.5,11 -11.5,-20.4 -12.1,-21 v1(-12.1,-24.4)
WL_HOST_WAKE: J41.18 U7.G18 | length 111.7
  1-TOP w0.2: v1(-13.335,4.445) U7.G18@-12.7,3.81
  3-INTOP w0.2: J41.18@-81.03,-39.39 -79.82,-40.6 -73.8,-40.6 -72.2,-39 -61.6,-39 -59.1,-36.5 -58,-36.5 -57.1,-35.6 -57.1,-31 -52.8,-26.7 -47.486,-26.7 -45.486,-24.7 -33.807,-24.7 -31.707,-26.8 -24,-26.8 -23.6,-26.4 -12.6,-26.4 v1(-12.1,-25.9)
  6-INBOT w0.2: v1(-13.335,4.445) -12.7,3.81 -12.7,-25 -12.1,-25.6 v1(-12.1,-25.9)
WLAN_SD3_CLK: J41.2 R52.2 | length 45.1
  1-TOP w0.2: v1(-46,-7.4) R52.2@-45.28,-7.4
  3-INTOP w0.2: J41.2@-81.03,-19.07 -81.03,-14.93 -71,-4.9 -49.4,-4.9 -46.9,-7.4 v1(-46,-7.4)
WLAN_SD3_CMD: J41.4 R53.2 | length 45.6
  1-TOP w0.2: v1(-46,-8.4) R53.2@-45.28,-8.4
  3-INTOP w0.2: J41.4@-81.03,-21.61 -79.7,-20.28 -79.7,-14.3 -72.7,-7.3 -51.8,-7.3 -50.7,-8.4 v1(-46,-8.4)
WLAN_SD3_D0: J41.6 R54.2 | length 48.5
  1-TOP w0.2: v1(-46,-9.4) R54.2@-45.28,-9.4
  3-INTOP w0.2: J41.6@-81.03,-24.15 -79.85,-24.15 -79.2,-23.5 -79.2,-14.5 -72.5,-7.8 -52.1,-7.8 -50.5,-9.4 v1(-46,-9.4)
WLAN_SD3_D1: J41.8 R55.2 | length 49.2
  1-TOP w0.2: v1(-46,-10.4) R55.2@-45.28,-10.4
  3-INTOP w0.2: J41.8@-81.03,-26.69 -79.59,-26.69 -78.2,-25.3 -78.2,-14.221 -74.179,-10.2 -47.3,-10.2 -47.1,-10.4 v1(-46,-10.4)
WLAN_SD3_D2: J41.10 R56.2 | length 50.4
  1-TOP w0.2: v1(-46,-11.4) R56.2@-45.28,-11.4
  3-INTOP w0.2: J41.10@-81.03,-29.23 -77.7,-25.9 -77.7,-14.421 -73.979,-10.7 -48.1,-10.7 -47.4,-11.4 v1(-46,-11.4)
WLAN_SD3_D3: J41.12 R57.2 | length 52.2
  1-TOP w0.2: v1(-46,-12.4) R57.2@-45.28,-12.4
  3-INTOP w0.2: J41.12@-81.03,-31.77 -77.2,-27.94 -77.2,-14.6 -75,-12.4 -61.9,-12.4 -61.2,-13.1 -47.9,-13.1 -47.2,-12.4 v1(-46,-12.4)
XBEE_RESET_N: J37.5 U7.E3 | length 176.2
  1-TOP w0.2: v1(-15.875,-15.875) U7.E3@-15.24,-15.24 ; J37.5@113.3,25.578 v1(113.3,27.3)
  3-INTOP w0.2: v1(-15.2,-22.9) 13,-22.9 14.4,-24.3 16.6,-24.3 17.1,-23.8 41.8,-23.8 45.9,-19.7 85.9,-19.7 95.6,-10 v1(101.6,-10)
  6-INBOT w0.2: v1(101.6,-10) 103,-10 104.9,-8.1 106,-7 106,-3.9 106,10.4 112.6,17 113.3,17.7 v1(113.3,27.3)
  8-BOTTOM w0.2: v1(-15.875,-15.875) -15.2,-16.55 -15.2,-19.4 v1(-15.2,-22.9)
XBEE_UART_CTS: J38.9 J58.3 | length 201.8
  1-TOP w0.2: J38.9@105.3,3.7 v1(105.3,5.4)
  3-INTOP w0.2: J58.3@-54.62,5.4 -45.3,5.4 -41.8,1.9 v1(-24.8,1.9)
  8-BOTTOM w0.2: v1(-24.8,1.9) -24.8,-2.3 -20.3,-6.8 -20.3,-24.907 -17.907,-27.3 23.5,-27.3 40.2,-10.6 80,-10.6 96,5.4 v1(105.3,5.4)
XBEE_UART_RTS: J38.5 J59.3 R198.2 | length 208.5
  1-TOP w0.2: J38.5@113.3,3.7 113.32,3.72 R198.2@113.32,6.1 113.3,6.12 v1(113.3,6.9)
  3-INTOP w0.2: J59.3@-54.62,-3.2 -47.4,-3.2 -46.2,-2 -30.7,-2 -29.4,-0.7 v1(-24.1,-0.7)
  8-BOTTOM w0.2: v1(-24.1,-0.7) -24.1,-2.2 -19.1,-7.2 -19.1,-25.4 -17.7,-26.8 23.293,-26.8 39.993,-10.1 79.6,-10.1 96.6,6.9 v1(113.3,6.9)
XBEE_UART_RX: J37.2 J54.3 | length 199.3
  1-TOP w0.2: v1(116.9,22.8) 119.15,22.8 119.25,22.9 J37.2@119.3,22.85
  3-INTOP w0.2: v1(-48,33.5) 43.7,33.5 48.5,38.3 63.393,38.3 77.393,24.3 113.5,24.3 115,22.8 v1(116.9,22.8)
  6-INBOT w0.2: J54.3@-54.62,14.1 -52.3,14.1 -50.81,15.59 -50.81,29.618 -48,32.428 v1(-48,33.5)
XBEE_UART_TX: J37.3 J57.3 | length 213.5
  1-TOP w0.2: J37.3@117.3,25.7 v1(117.3,27.3)
  3-INTOP w0.2: v1(-46,34) 43.493,34 48.293,38.8 63.6,38.8 77.6,24.8 112.7,24.8 115.2,27.3 v1(117.3,27.3)
  6-INBOT w0.2: J57.3@-54.62,-0.3 -51.4,-0.3 -48.7,2.4 -48.7,28.8 -46,31.5 v1(-46,34)
XBEE_USB_D_N: J37.8 L27.2 U25.4 | length 52.4
  1-TOP w0.168: U25.4@88.7,-16.15 89,-16.15 89.116,-16.034 89.116,-15.932 89.214,-15.834 89.572,-15.834 90.149,-15.834 90.459,-15.524 90.459,-15.282 90.557,-15.184 90.584,-15.184 90.7,-15.068 L27.2@90.7,-14.85 90.7,-14.568 90.458,-14.326 90.458,-13.292 90.458,6.408 104.459,20.409 104.459,22.234 106.9,24.675 107.811,24.675 108.011,24.475 108.011,24.336 107.3,23.625 J37.8@107.3,22.85
XBEE_USB_D_P: J37.7 L27.3 U25.5 | length 52.7
  1-TOP w0.168: U25.5@88.7,-15.2 89,-15.2 89.116,-15.316 89.116,-15.418 89.214,-15.516 89.44,-15.516 90.017,-15.516 90.115,-15.418 90.115,-15.278 90.021,-15.184 90.016,-15.184 89.9,-15.068 L27.3@89.9,-14.85 89.9,-14.568 90.14,-14.328 ; 90.14,-14.326 90.14,-13.16 90.14,6.54 104.141,20.541 104.141,22.366 106.768,24.993 107.943,24.993 108.327,24.609 108.984,24.609 109.3,24.925 J37.7@109.3,25.7
XBEE_VCC: C185.2 C186.2 J37.1 L38.2 L39.2 R197.2 | length 28.1
  1-TOP w0.5: R197.2@109.3,7.08 109.3,13.8 112.7,17.2 119,17.2 L38.2@121.1,17.2 ; L38.2@121.3,17 121.3,17.2 121.3,19.1 121.3,20.8 J37.1@121.3,25.15
pads on no net: D15.X D16.4 D16.5 D16.6 D16.7 FIDUCIAL1.1 FIDUCIAL2.1 FIDUCIAL3.1 FIDUCIAL4.1 FIDUCIAL5.1 FIDUCIAL6.1 J1.3 J1.4 J12.8 J12.9 J13.A2 J13.A3 J13.A5 J13.A8 J13.A10 J13.A11 J13.B2 J13.B3 J13.B5 J13.B8 J13.B10 J13.B11 J19.0 J19.3 J19.5 J19.7 J19.11 J19.13 J19.17 J19.19 J19.20 J19.22 J19.23 J19.25 J19.31 J19.33 J19.42 J19.44 J19.45 J19.46 J19.47 J19.49 J19.51 J19.H1 J19.H2 J19.MT1 J19.MT2 J20.7 J21.6 J21.7 J21.8 J22.4 J22.8 J22.9 J22.10 J26.MNT1 J26.MNT2 J27.MNT1 J27.MNT2 J29.M1 J29.M2 J30.4 J31.MT1 J31.MT21 J32.14 J32.H1 J32.H2 J37.9 J38.1 J38.2 J38.3 J38.4 J38.6 J38.8 J63.A2 J63.A3 J63.A8 J63.A10 J63.A11 J63.B2 J63.B3 J63.B8 J63.B10 J63.B11 SWD1.6 SWD1.7 SWD1.8 SWD1.9 SWD1.MT1 SWD1.MT2 SWD1.MT3 U7.A12 U7.AA29 U7.AB1 U7.AB29 U7.AC1 U7.AC29 U7.AD1 U7.AD29 U7.AE1 U7.AE29 U7.AG8 U7.AG9 U7.AG10 U7.AG11 U7.AG12 U7.AG13 U7.AG14 U7.AG15 U7.AG19 U7.AG22 U7.AG24 U7.AH9 U7.AH11 U7.AH18 U7.AH20 U7.AH22 U7.AH23 U7.AH24 U7.AH25 U7.AH26 U7.AH29 U7.AJ8 U7.AJ13 U7.AJ21 U7.AJ22 U7.AJ23 U7.AJ24 U7.AJ25 U7.AJ27 U7.AJ28 U7.AJ29 U7.AK21 U7.AK22 U7.AK26 U7.AK27 U7.AK28 U7.AK29 U7.AL28 U7.AM7 U7.AM8 U7.AM9 U7.AM16 U7.AM17 U7.AM22 U7.B7 U7.B9 U7.B10 U7.B12 U7.B13 U7.B16 U7.B17 U7.B23 U7.C3 U7.C7 U7.C8 U7.C9 U7.C11 U7.C27 U7.D1 U7.D7 U7.D10 U7.D13 U7.D14 U7.D15 U7.D19 U7.E16 U7.E24 U7.E25 U7.E26 U7.F3 U7.F9 U7.F10 U7.F19 U7.F23 U7.F25 U7.F26 U7.F27 U7.G3 U7.G4 U7.G6 U7.G7 U7.G9 U7.G10 U7.G20 U7.G21 U7.G23 U7.G24 U7.J29 U7.MH1 U7.MH2 U7.MH3 U7.MH4 U7.MH5 U7.MH6 U7.U1 U9.2 U9.6 U9.7 U9.14 U9.18 U9.19 U9.20 U9.21 U9.22 U13.1 U13.2 U13.4 U13.5 U13.13 U13.29 U13.31 U13.32 U14.1 U14.2 U14.4 U14.5 U14.13 U14.29 U14.31 U14.32 U15.7 U15.24 U16.1 U16.2 U16.7 U16.16 U16.17 U16.22 U16.23 U16.24 U17.15 U17.16 U17.19 U17.20 U17.37 U17.38 U17.39 U17.40 U17.43 U17.44 U17.45 U17.46 U17.47 U17.48 U17.58 U17.59 U17.60 U18.16 U20.18 U20.19 U20.20 U20.21 U21.4 U22.4 U23.2 U24.6 U25.6 U26.1 U26.6 U26.7 U26.8 U26.9 U26.11 U26.12 U26.13 U26.14 U27.11 U27.12 U27.13 U27.14 U27.28 U27.29 U27.40 U27.41 U27.46 U29.3 U29.6

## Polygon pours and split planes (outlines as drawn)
GND on 1-TOP "GND_PLANE" (solid, remove dead copper, pour order 54): -85.7,62.2 124.3,62.2 124.3,-67.8 -85.7,-67.8
5V on 1-TOP "NONET_L06_P-001" (solid, pour order 53): 95.64,-23.1 95.64,-25.1 97.64,-25.1 97.64,-23.1
3V3_ETH1 on 1-TOP "NONET_L06_P-001" (solid, pour order 19): -64.6,-26.4 -64.6,-24.4 -67.4,-24.4 -67.4,-26.4
3V3_ETH2 on 1-TOP "NONET_L06_P-001" (solid, pour order 52): -37.97,-34.2 -37.97,-37 -35.97,-37 -35.97,-34.2
3V3_SOM_EXT on 1-TOP "NONET_L06_P-001" (solid, pour order 51): -33.63,-37 -33.63,-34.2 -35.63,-34.2 -35.63,-37
NetD21_A on 1-TOP "NONET_L06_P-001" (solid, pour order 50): 82.5,-54.7 82.5,-57.6 84.2,-57.6 84.2,-56.2 83.5,-55.5 83.5,-54.7
VIN_PROT on 1-TOP "NONET_L06_P-001" (solid, pour order 49): 82.4,-54.1 82.4,-57.6 80.4,-57.6 80.3,-57.5 80.3,-55.4 81.1,-55.4 81.5,-55 81.5,-54.1
USBC_VBUS on 1-TOP "NONET_L06_P-001" (solid, pour order 48): 85.2,-55.5 85.6,-55.9 85.6,-57.6 87.9,-57.6 87.9,-54.3 87.7,-54.1 83.6,-54.1 83.6,-55.5
5V on 1-TOP "NONET_L06_P-001" (solid, pour order 46): 38.6,-48.1 36.6,-48.1 36.6,-49.82 38.6,-49.82
5V_DBG on 1-TOP "NONET_L06_P-001" (solid, pour order 45): -39.2,43.8 -32.3,43.8 -32.3,45.7 -39.2,45.7
NetC16_1 on 1-TOP "NONET_L06_P-001" (solid, pour order 11): 94.6,28.6 93.9,28.6 93.4,28.1 87.8,28.1 87.8,30.5 94.6,30.5
1V8_PHY_2 on 1-TOP "NONET_L06_P-001" (solid, pour order 24): -46.2,-33.4 -43.5,-33.4 -43.5,-31.4 -44.2,-31.4
3V3_BOARD on 1-TOP "3V3_BOARD" (solid, remove dead copper, pour order 1): 87.5,31.3 87.7,31.1 94.5,31.1 95.9,32.5 95.9,34.9 95.7,35.1 87.7,35.1 87.5,34.9
VIN on 1-TOP "VIN" (solid, remove dead copper, pour order 3): 105.5,46 101.4,46 99.3,43.9 97.9,43.9 97.9,42.5 98.5,41.9 98.5,40.9 98.6,40.8 100.1,40.8 101,41.7 105.5,41.7
VIN_PROT on 1-TOP "VIN_PROT" (solid, remove dead copper, pour order 2): 85.6,42.1 85.6,43.2 86.3,43.9 95.7,43.9 95.9,43.7 95.9,37.9 95.7,37.7 93.2,37.7 90.9,40 84.5,40 83,40 85.1,42.1
1V8 on 1-TOP "NONET_L06_P-001" (solid, pour order 41): -35.1,19.4 -35.8,20.1 -35.1,20.8 -35.1,21.2 -32.9,21.2 -32.9,19.1 -35.1,19.1
1V8_SOM_EXT on 1-TOP "NONET_L06_P-001" (solid, pour order 37): -15.054,-45.47 -12.254,-45.47 -12.254,-43.47 -15.054,-43.47
1V8 on 1-TOP "NONET_L06_P-001" (solid, pour order 40): -12.254,-41.13 -15.054,-41.13 -15.054,-43.13 -12.254,-43.13
3V3_SOM_EXT on 1-TOP "NONET_L06_P-001" (solid, pour order 36): -32.6,-45.47 -29.8,-45.47 -29.8,-43.47 -32.6,-43.47
3V3 on 1-TOP "NONET_L06_P-001" (solid, pour order 35): -29.8,-41.13 -32.6,-41.13 -32.6,-43.13 -29.8,-43.13
NetJ6_2 on 1-TOP "NONET_L06_P-001" (solid, pour order 34): 3.8,-44.4 11.9,-44.4 11.9,-47.2 3.8,-47.2
VIN_PROT on 1-TOP "NONET_L06_P-001" (solid, pour order 12): 95.6,28.4 95.6,26.7 97.8,26.7 97.8,28.4
NetC148_2 on 1-TOP "NONET_L06_P-001" (solid, pour order 32): 114.9,-35.5 114.9,-33.45 111.5,-33.45 111.5,-35.5
3V3_USB on 1-TOP "NONET_L06_P-001" (solid, pour order 31): 111.5,-30.9 111.5,-32.95 114.9,-32.95 114.9,-30.9
3V3_SOM_EXT on 1-TOP "NONET_L06_P-001" (solid, pour order 30): 92.9,-30.5 92.9,-33.3 94.9,-33.3 94.9,-30.5
3V3_USB on 1-TOP "NONET_L06_P-001" (solid, pour order 29): 97.3,-30.5 95.3,-30.5 95.3,-33.3 97.3,-33.3
1V8_SOM_EXT on 1-TOP "NONET_L06_P-001" (solid, pour order 28): -49.9,36.3 -51.9,36.3 -51.9,33.5 -49.9,33.5
3V3_CODEC on 1-TOP "NONET_L06_P-001" (solid, pour order 27): -53.5,27.9 -56.3,27.9 -56.3,25.9 -53.5,25.9
3V3_SOM_EXT on 1-TOP "NONET_L06_P-001" (solid, pour order 26): -53.5,23.5 -53.5,25.5 -56.3,25.5 -56.3,23.5
1V8_PHY_1 on 1-TOP "NONET_L06_P-001" (solid, pour order 25): -65.1,-33.2 -63.4,-31.5 -62.1,-31.5 -62.1,-33.2
3V3_ETH2 on 1-TOP "NONET_L06_P-001" (solid, pour order 23): -41,-43.1 -43,-43.1 -43,-45 -41,-45
3V3_ETH1 on 1-TOP "NONET_L06_P-001" (solid, pour order 22): -60.395,-42.6 -62.395,-42.6 -62.395,-44.6 -60.395,-44.6
3V3_SOM_EXT on 1-TOP "NONET_L06_P-001" (solid, pour order 20): -64.6,-22 -67.4,-22 -67.4,-24 -64.6,-24
CT2 on 1-TOP "AGND" (solid, remove dead copper, pour order 18): -57.845,-45.952 -52.845,-45.952 -52.845,-48.752 -54.245,-48.752 -54.245,-47.952 -54.945,-47.252 -57.345,-47.252 -57.845,-46.752
CT1 on 1-TOP "AGND" (solid, remove dead copper, pour order 17): -79.315,-45.952 -74.315,-45.952 -74.315,-48.752 -75.715,-48.752 -75.715,-47.952 -76.415,-47.252 -78.815,-47.252 -79.315,-46.752
5V on 1-TOP "NONET_L06_P-001" (solid, pour order 15): 8.6,-55.6 8.6,-58.2 11.3,-58.2 11.3,-55.6
5V on 1-TOP "NONET_L06_P-001" (solid, pour order 14): 87.4,30.3 87.4,27.2 85.5,27.2 85.5,30.3
VIN on 1-TOP "NONET_L06_P-001" (solid, pour order 13): 92.8,52.4 96.2,52.4 96.2,50.4 92.8,50.4
3V3 on 1-TOP "NONET_L06_P-001" (solid, pour order 10): -44,39.3 -44,41.4 -46.1,41.4 -46.1,39.3
3V3_DBG on 1-TOP "NONET_L06_P-001" (solid, pour order 9): -48.6,39.3 -46.5,39.3 -46.5,41.4 -48.6,41.4
3V3_DBG on 1-TOP "NONET_L06_P-001" (solid, pour order 8): -48.6,43.8 -48.6,41.7 -46.5,41.7 -46.5,43.8
3V3_DBG on 1-TOP "3V3_DBG" (solid, remove dead copper, pour order 5): -42.65,52.5 -43.3,52.5 -43.3,58.2 -42.2,58.2 -41.6,57.6 -41.6,52.5 -42.05,52.5
NetFIL1_1 on 1-TOP "NONET_L06_P-001" (solid, pour order 4): 98.9,57.4 107.6,48.7 107.6,46.3 108.2,45.7 109.8,45.7 109.8,41.7 113.3,41.7 114.7,43.1 114.7,61.6 98.9,61.6
GND on 8-BOTTOM "GND_PLANE" (solid, remove dead copper, pour order 44): -85.7,62.2 124.3,62.2 124.3,-67.8 -85.7,-67.8
3V3 on 8-BOTTOM "NONET_L06_P-001" (solid, pour order 33): -46.1,41.4 -46.1,39.3 -45.8,39.3 -45.55,39.05 -44.65,39.05 -44.4,39.3 -44,39.3 -44,41.4
GND on 6-INBOT "GND_PLANE" (solid, remove dead copper, pour order 43): -85.7,62.2 124.3,62.2 124.3,-67.8 -85.7,-67.8
1V8 on 6-INBOT "NONET_L06_P-001" (solid, pour order 39): -35.1,21.2 -35.1,19.1 -34.8,19.1 -34.4,18.7 -33.6,18.7 -33.2,19.1 -32.9,19.1 -32.9,21.2
1V8 on 6-INBOT "NONET_L06_P-001" (solid, pour order 38): -18.3,-39.7 -19.05,-40.45 -18.4,-41.1 -18.4,-43.295 -12.206,-43.295 -12.206,-39.7
GND on 3-INTOP "GND_PLANE" (solid, remove dead copper, pour order 42): -85.7,62.2 124.3,62.2 124.3,-67.8 -85.7,-67.8
3V3_ETH1 on 5-PWR (split plane): -59.451,-44.337 -61.563,-46.449 -74.3,-46.449 -74.339,-46.454 -74.376,-46.469 -74.407,-46.493 -80.563,-52.649 -82.837,-52.649 -83.149,-52.337 -83.149,-47.563 -79.193,-43.607 -79.169,-43.576 -79.154,-43.539 -79.149,-43.5 -79.149,-41.6 -79.149,-26.463 -76.937,-24.251 -59.451,-24.251
3V3_ETH2 on 5-PWR (split plane): -33.151,-33.163 -33.151,-42.437 -37.763,-47.049 -54.1,-47.049 -54.139,-47.054 -54.176,-47.069 -54.207,-47.093 -58.013,-50.899 -59.487,-50.899 -60.574,-49.812 -60.574,-47.375 -60.579,-47.336 -60.588,-47.314 -60.594,-47.299 -60.618,-47.268 -61.286,-46.6 -59.193,-44.507 -59.169,-44.476 -59.154,-44.439 -59.149,-44.4 -59.149,-24.251 -42.063,-24.251
1V8_SOM_EXT on 5-PWR (split plane): 171 vertices, not listed, extent -85.198,-67.298 87.449,57.249
NetC72_2 on 5-PWR (split plane): -64.551,-33.763 -64.551,-38.437 -67.063,-40.949 -73.237,-40.949 -75.749,-38.437 -75.749,-35.5 -75.749,-33.263 -74.937,-32.451 -65.863,-32.451
NetC99_2 on 5-PWR (split plane): -45.451,-33.763 -45.451,-38.237 -48.363,-41.149 -54.537,-41.149 -57.049,-38.637 -57.049,-35.7 -57.049,-33.063 -56.237,-32.251 -46.963,-32.251
VCC_MCA on 5-PWR (split plane): 84.749,61.698 84.749,57 84.749,55.5 84.754,55.461 84.769,55.424 84.793,55.393 86.693,53.493 86.724,53.469 86.761,53.454 86.8,53.449 87.637,53.449 89.649,51.437 89.649,48.463 88.693,47.507 82.537,41.351 24,41.351 23.961,41.346 23.924,41.331 23.893,41.307 21.293,38.707 21.269,38.676 21.263,38.661 21.254,38.639 21.249,38.6 21.249,7.493 20.892,7.136 19.748,7.136 18.566,8.318 18.566,35.2 18.561,35.239 18.546,35.276 18.522,35.307 18.491,35.331 18.477,35.336 16.607,37.207 16.576,37.231 16.539,37.246 16.5,37.251 -20.137,37.251 -21.149,38.263 -21.149,41.037 -20.037,42.149 -10.3,42.149 -10.261,42.154 -10.239,42.163 -10.224,42.169 -10.193,42.193 -9.093,43.293 -9.069,43.324 -9.054,43.361 -9.049,43.4 -9.049,48.8 -9.054,48.839 -9.069,48.876 -9.093,48.907 -9.593,49.407 -9.624,49.431 -9.661,49.446 -9.7,49.451 -21.037,49.451 -23.793,52.207 -29.093,57.507 -29.124,57.531 -29.161,57.546 -29.2,57.551 -74,57.551 -74.039,57.546 -74.061,57.537 -74.076,57.531 -74.107,57.507 -77.407,54.207 -77.431,54.176 -77.446,54.139 -77.451,54.1 -77.451,16.363 -79.463,14.351 -85.198,14.351 -85.198,61.698
USBC_VBUS on 5-PWR (split plane): 95.371,-55.554 95.371,-67.298 86.41,-67.298 86.41,-59.78 86.4,-59.731 86.372,-59.689 85.029,-58.346 85.029,-55.254 85.954,-54.329 94.146,-54.329
5V on 5-PWR (split plane): 87.449,-19.8 87.454,-19.839 87.469,-19.876 87.493,-19.907 89.393,-21.807 89.424,-21.831 89.461,-21.846 89.5,-21.851 96.837,-21.851 97.649,-22.663 97.649,-24.437 97.037,-25.049 90.25,-25.049 90.211,-25.054 90.174,-25.069 90.143,-25.093 87.493,-27.743 64.143,-51.093 56.687,-58.549 9.663,-58.549 8.651,-57.537 8.651,-55.463 11.563,-52.551 20.425,-52.551 20.464,-52.546 20.486,-52.537 20.501,-52.531 20.532,-52.507 23.388,-49.651 35.575,-49.651 35.614,-49.646 35.636,-49.637 35.651,-49.631 35.682,-49.607 37.238,-48.051 51.7,-48.051 51.739,-48.046 51.761,-48.037 51.776,-48.031 51.807,-48.007 82.607,-17.207 82.631,-17.176 82.646,-17.139 82.651,-17.1 82.651,29.037 84.063,30.449 87.449,30.449
VIN_PROT on 5-PWR (split plane): 123.798,61.698 123.798,-67.298 95.629,-67.298 95.629,-55.5 95.62,-55.45 95.592,-55.408 94.292,-54.108 94.25,-54.08 94.2,-54.071 85.9,-54.071 85.85,-54.08 85.808,-54.108 84.808,-55.108 84.78,-55.15 84.771,-55.2 84.771,-58.4 84.78,-58.45 84.808,-58.492 86.151,-59.834 86.151,-67.298 3.451,-67.298 3.451,-43.851 6.3,-43.851 6.339,-43.846 6.361,-43.837 6.376,-43.831 6.407,-43.807 6.807,-43.407 10.45,-39.764 11.949,-41.263 11.949,-50.437 11.493,-50.893 11.469,-50.924 11.454,-50.961 11.449,-51 11.449,-52.259 11.424,-52.269 11.393,-52.293 8.393,-55.293 8.369,-55.324 8.354,-55.361 8.349,-55.4 8.349,-57.6 8.354,-57.639 8.369,-57.676 8.393,-57.707 9.493,-58.807 9.524,-58.831 9.561,-58.846 9.6,-58.851 56.75,-58.851 56.789,-58.846 56.826,-58.831 56.857,-58.807 64.357,-51.307 87.707,-27.957 90.313,-25.351 97.1,-25.351 97.139,-25.346 97.161,-25.337 97.176,-25.331 97.207,-25.307 97.907,-24.607 97.931,-24.576 97.946,-24.539 97.951,-24.5 97.951,-22.6 97.946,-22.561 97.937,-22.539 97.931,-22.524 97.907,-22.493 97.007,-21.593 96.976,-21.569 96.961,-21.563 96.939,-21.554 96.9,-21.549 89.563,-21.549 87.751,-19.737 87.751,30.6 87.751,36.2 87.746,36.239 87.731,36.276 87.707,36.307 82.814,41.2 88.907,47.293 89.907,48.293 89.931,48.324 89.946,48.361 89.951,48.4 89.951,51.5 89.946,51.539 89.931,51.576 89.907,51.607 87.807,53.707 87.776,53.731 87.739,53.746 87.7,53.751 86.863,53.751 85.051,55.563 85.051,57 85.051,61.698
5V_DBG on 5-PWR (split plane): -31.251,57.237 -31.251,44.963 -32.163,44.051 -38.337,44.051 -39.569,45.283 -39.569,57.249 -31.263,57.249
VSYS2 on 5-PWR (split plane): 17.649,-26.237 17.37,-26.516 5.193,-38.693 5.169,-38.724 5.163,-38.739 5.154,-38.761 5.149,-38.8 5.149,-43.549 3.363,-43.549 2.351,-42.537 2.351,-31.963 15.307,-19.007 15.331,-18.976 15.346,-18.939 15.351,-18.9 15.351,-14.663 15.963,-14.051 17.649,-14.051
VSYS on 5-PWR (split plane): 21.749,-10.363 21.749,-28.037 6.593,-43.193 6.237,-43.549 5.451,-43.549 5.451,-38.863 17.584,-26.73 17.907,-26.407 17.931,-26.376 17.946,-26.339 17.951,-26.3 17.951,-9.063 18.063,-8.951 20.337,-8.951
1V8_PHY_2 on 4-PWR (split plane): -44.557,-29.007 -43.551,-30.013 -43.551,-35.85 -43.551,-39.187 -44.913,-40.549 -53.5,-40.549 -53.539,-40.554 -53.576,-40.569 -53.607,-40.593 -55.963,-42.949 -58.537,-42.949 -59.949,-41.537 -59.949,-40 -59.949,-30.513 -58.443,-29.007 -57.087,-27.651 -45.913,-27.651
3V3 on 4-PWR (split plane): -31.251,61.698 -31.251,42.6 -31.246,42.561 -31.237,42.539 -31.231,42.524 -31.207,42.493 -25.607,36.893 -18.607,29.893 -18.576,29.869 -18.539,29.854 -18.5,29.849 39.2,29.849 39.239,29.854 39.276,29.869 39.307,29.893 46.263,36.849 49.337,36.849 50.149,36.037 50.149,9.263 34.093,-6.793 34.069,-6.824 34.054,-6.861 34.049,-6.9 34.049,-22.137 13.037,-43.149 -2.2,-43.149 -6.049,-43.149 -6.049,-38.563 0.463,-32.051 3.8,-32.051 3.839,-32.046 3.876,-32.031 3.907,-32.007 15.407,-20.507 15.431,-20.476 15.437,-20.461 15.446,-20.439 15.451,-20.4 15.451,-15.6 15.446,-15.561 15.431,-15.524 15.407,-15.493 15.007,-15.093 14.976,-15.069 14.961,-15.063 14.939,-15.054 14.9,-15.049 13.2,-15.049 13.161,-15.054 13.139,-15.063 13.124,-15.069 13.093,-15.093 12.593,-15.593 12.569,-15.624 12.563,-15.639 12.554,-15.661 12.549,-15.7 12.549,-18.637 6.237,-24.949 -3.9,-24.949 -3.939,-24.954 -3.976,-24.969 -4.007,-24.993 -20.807,-41.793 -20.831,-41.824 -20.846,-41.861 -20.851,-41.9 -20.851,-43.149 -32.537,-43.149 -32.849,-42.837 -32.849,-42 -32.849,-27.5 -32.854,-27.461 -32.869,-27.424 -32.893,-27.393 -36.349,-23.937 -36.349,28.5 -36.354,28.539 -36.369,28.576 -36.393,28.607 -46.249,38.463 -46.249,39 -46.249,40.137 -40.893,45.493 -40.869,45.524 -40.854,45.561 -40.849,45.6 -40.849,57.1 -40.854,57.139 -40.865,57.165 -40.869,57.176 -40.893,57.207 -41.993,58.307 -42.024,58.331 -42.061,58.346 -42.1,58.351 -43.6,58.351 -43.639,58.346 -43.676,58.331 -43.707,58.307 -44.007,58.007 -44.031,57.976 -44.046,57.939 -44.051,57.9 -44.051,54.763 -45.663,53.151 -50.249,53.151 -50.249,61.698
3V3_SOM_EXT on 4-PWR (split plane): 177 vertices, not listed, extent -85.198,-67.298 123.798,61.698
1V8_PHY_1 on 4-PWR (split plane): -75.407,-24.807 -74.551,-25.663 -74.551,-27.5 -74.546,-27.539 -74.537,-27.561 -74.531,-27.576 -74.507,-27.607 -73.907,-28.207 -73.876,-28.231 -73.839,-28.246 -73.8,-28.251 -64.263,-28.251 -63.507,-29.007 -62.751,-29.763 -62.751,-36.1 -62.751,-39.437 -63.763,-40.449 -74,-40.449 -74.039,-40.454 -74.061,-40.463 -74.076,-40.469 -74.107,-40.493 -76.163,-42.549 -77.637,-42.549 -79.049,-41.137 -79.049,-39.7 -79.049,-28.7 -79.049,-26.263 -77.237,-24.451 -75.763,-24.451
3V3_CODEC on 4-PWR (split plane): -52.751,30.037 -52.751,26.563 -53.363,25.951 -68.737,25.951 -70.249,27.463 -70.249,28.5 -70.249,31.437 -69.537,32.149 -54.863,32.149
3V3_DBG on 4-PWR (split plane): -41.151,57.037 -41.151,45.663 -46.507,40.307 -46.531,40.276 -46.546,40.239 -46.551,40.2 -46.551,39.151 -50.249,39.151 -50.249,52.849 -45.6,52.849 -45.561,52.854 -45.524,52.869 -45.493,52.893 -43.793,54.593 -43.769,54.624 -43.754,54.661 -43.749,54.7 -43.749,57.837 -43.537,58.049 -42.163,58.049
1V8 on 4-PWR (split plane): 15.149,-15.663 15.149,-20.337 3.737,-31.749 0.4,-31.749 0.361,-31.754 0.339,-31.763 0.324,-31.769 0.293,-31.793 -6.307,-38.393 -6.331,-38.424 -6.346,-38.461 -6.351,-38.5 -6.351,-43.149 -20.549,-43.149 -20.549,-41.963 -3.837,-25.251 6.3,-25.251 6.339,-25.246 6.361,-25.237 6.376,-25.231 6.407,-25.207 12.807,-18.807 12.831,-18.776 12.837,-18.761 12.846,-18.739 12.851,-18.7 12.851,-15.763 13.263,-15.351 14.837,-15.351
5V_OUT_HDMI on 4-PWR (split plane): 56.349,-49.863 56.349,-54.837 55.437,-55.749 43.163,-55.749 42.151,-54.737 42.151,-49.563 42.663,-49.051 55.537,-49.051
NetC148_2 on 4-PWR (split plane): 115.349,-33.963 115.349,-40.537 113.637,-42.249 105.563,-42.249 103.551,-40.237 103.551,-36.063 104.063,-35.551 106,-35.551 106.039,-35.546 106.061,-35.537 106.076,-35.531 106.107,-35.507 106.507,-35.107 106.531,-35.076 106.535,-35.065 106.546,-35.039 106.551,-35 106.551,-34.063 107.363,-33.251 114.637,-33.251
VIN on 4-PWR (split plane): 105.549,43.377 105.549,41.763 105.337,41.551 101.363,41.551 98.507,44.407 98.476,44.431 98.439,44.446 98.4,44.451 92.863,44.451 91.851,45.463 91.851,51.537 92.163,51.849 97.077,51.849
5V on 4-PWR (split plane): 6.549,61.698 6.549,50.9 6.554,50.861 6.569,50.824 6.593,50.793 10.243,47.143 10.893,46.493 10.924,46.469 10.935,46.465 10.961,46.454 11,46.449 18.437,46.449 19.149,45.737 19.149,40.1 19.154,40.061 19.169,40.024 19.193,39.993 19.593,39.593 19.624,39.569 19.661,39.554 19.7,39.549 20.4,39.549 20.439,39.554 20.476,39.569 20.507,39.593 20.907,39.993 20.931,40.024 20.946,40.061 20.951,40.1 20.951,45.737 21.663,46.449 75.737,46.449 76.649,45.537 76.649,43 76.649,42.7 76.649,41.2 76.654,41.161 76.663,41.139 76.669,41.124 76.693,41.093 87.449,30.337 87.449,26.651 81.413,26.651 71.857,36.207 71.826,36.231 71.811,36.237 71.789,36.246 71.75,36.251 50.363,36.251 49.507,37.107 49.476,37.131 49.439,37.146 49.4,37.151 46.2,37.151 46.161,37.146 46.124,37.131 46.093,37.107 39.137,30.151 -18.437,30.151 -25.393,37.107 -30.949,42.663 -30.949,61.698
3V3_USB on 4-PWR (split plane): 115.449,-30.563 115.449,-32.137 114.637,-32.949 107.3,-32.949 107.261,-32.954 107.235,-32.965 107.224,-32.969 107.193,-32.993 106.293,-33.893 106.269,-33.924 106.263,-33.939 106.254,-33.961 106.249,-34 106.249,-34.937 105.937,-35.249 104,-35.249 103.961,-35.254 103.939,-35.263 103.924,-35.269 103.893,-35.293 103.293,-35.893 103.269,-35.924 103.254,-35.961 103.249,-36 103.249,-40.149 92.263,-40.149 91.951,-39.837 91.951,-37.963 95.207,-34.707 95.231,-34.676 95.246,-34.639 95.251,-34.6 95.251,-30.463 95.763,-29.951 114.837,-29.951
3V3_BOARD on 4-PWR (split plane): 87.193,34.193 87.224,34.169 87.261,34.154 87.3,34.149 94.737,34.149 95.749,33.137 95.749,25.8 95.749,17.8 95.754,17.761 95.763,17.739 95.769,17.724 95.793,17.693 96.793,16.693 96.824,16.669 96.861,16.654 96.9,16.649 113.837,16.649 114.449,16.037 114.449,14.363 113.737,13.651 97,13.651 96.961,13.646 96.924,13.631 96.893,13.607 95.793,12.507 95.769,12.476 95.754,12.439 95.749,12.4 95.749,2.863 91.893,-0.993 91.869,-1.024 91.863,-1.039 91.854,-1.061 91.849,-1.1 91.849,-5.737 73.337,-24.249 54.663,-24.249 50.551,-20.137 50.551,-5.963 54.363,-2.151 78,-2.151 78.039,-2.146 78.076,-2.131 78.107,-2.107 87.707,7.493 87.731,7.524 87.746,7.561 87.751,7.6 87.751,30.4 87.746,30.439 87.735,30.465 87.731,30.476 87.707,30.507 76.951,41.263 76.951,42.849 78.537,42.849
GND on 7-GND (split plane): 123.798,61.698 123.798,-67.298 -85.198,-67.298 -85.198,61.698
GND on 2-GND (split plane): 123.798,61.698 123.798,-67.298 -85.198,-67.298 -85.198,61.698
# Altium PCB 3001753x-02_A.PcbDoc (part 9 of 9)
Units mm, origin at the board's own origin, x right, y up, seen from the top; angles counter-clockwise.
Board outline 210 x 130 mm, 8 copper layers (1-TOP, 2-GND, 3-INTOP, 4-PWR, 5-PWR, 6-INBOT, 7-GND, 8-BOTTOM), stack 1.646 mm thick; 651 components, 607 nets, 2780 pads, 1706 vias.

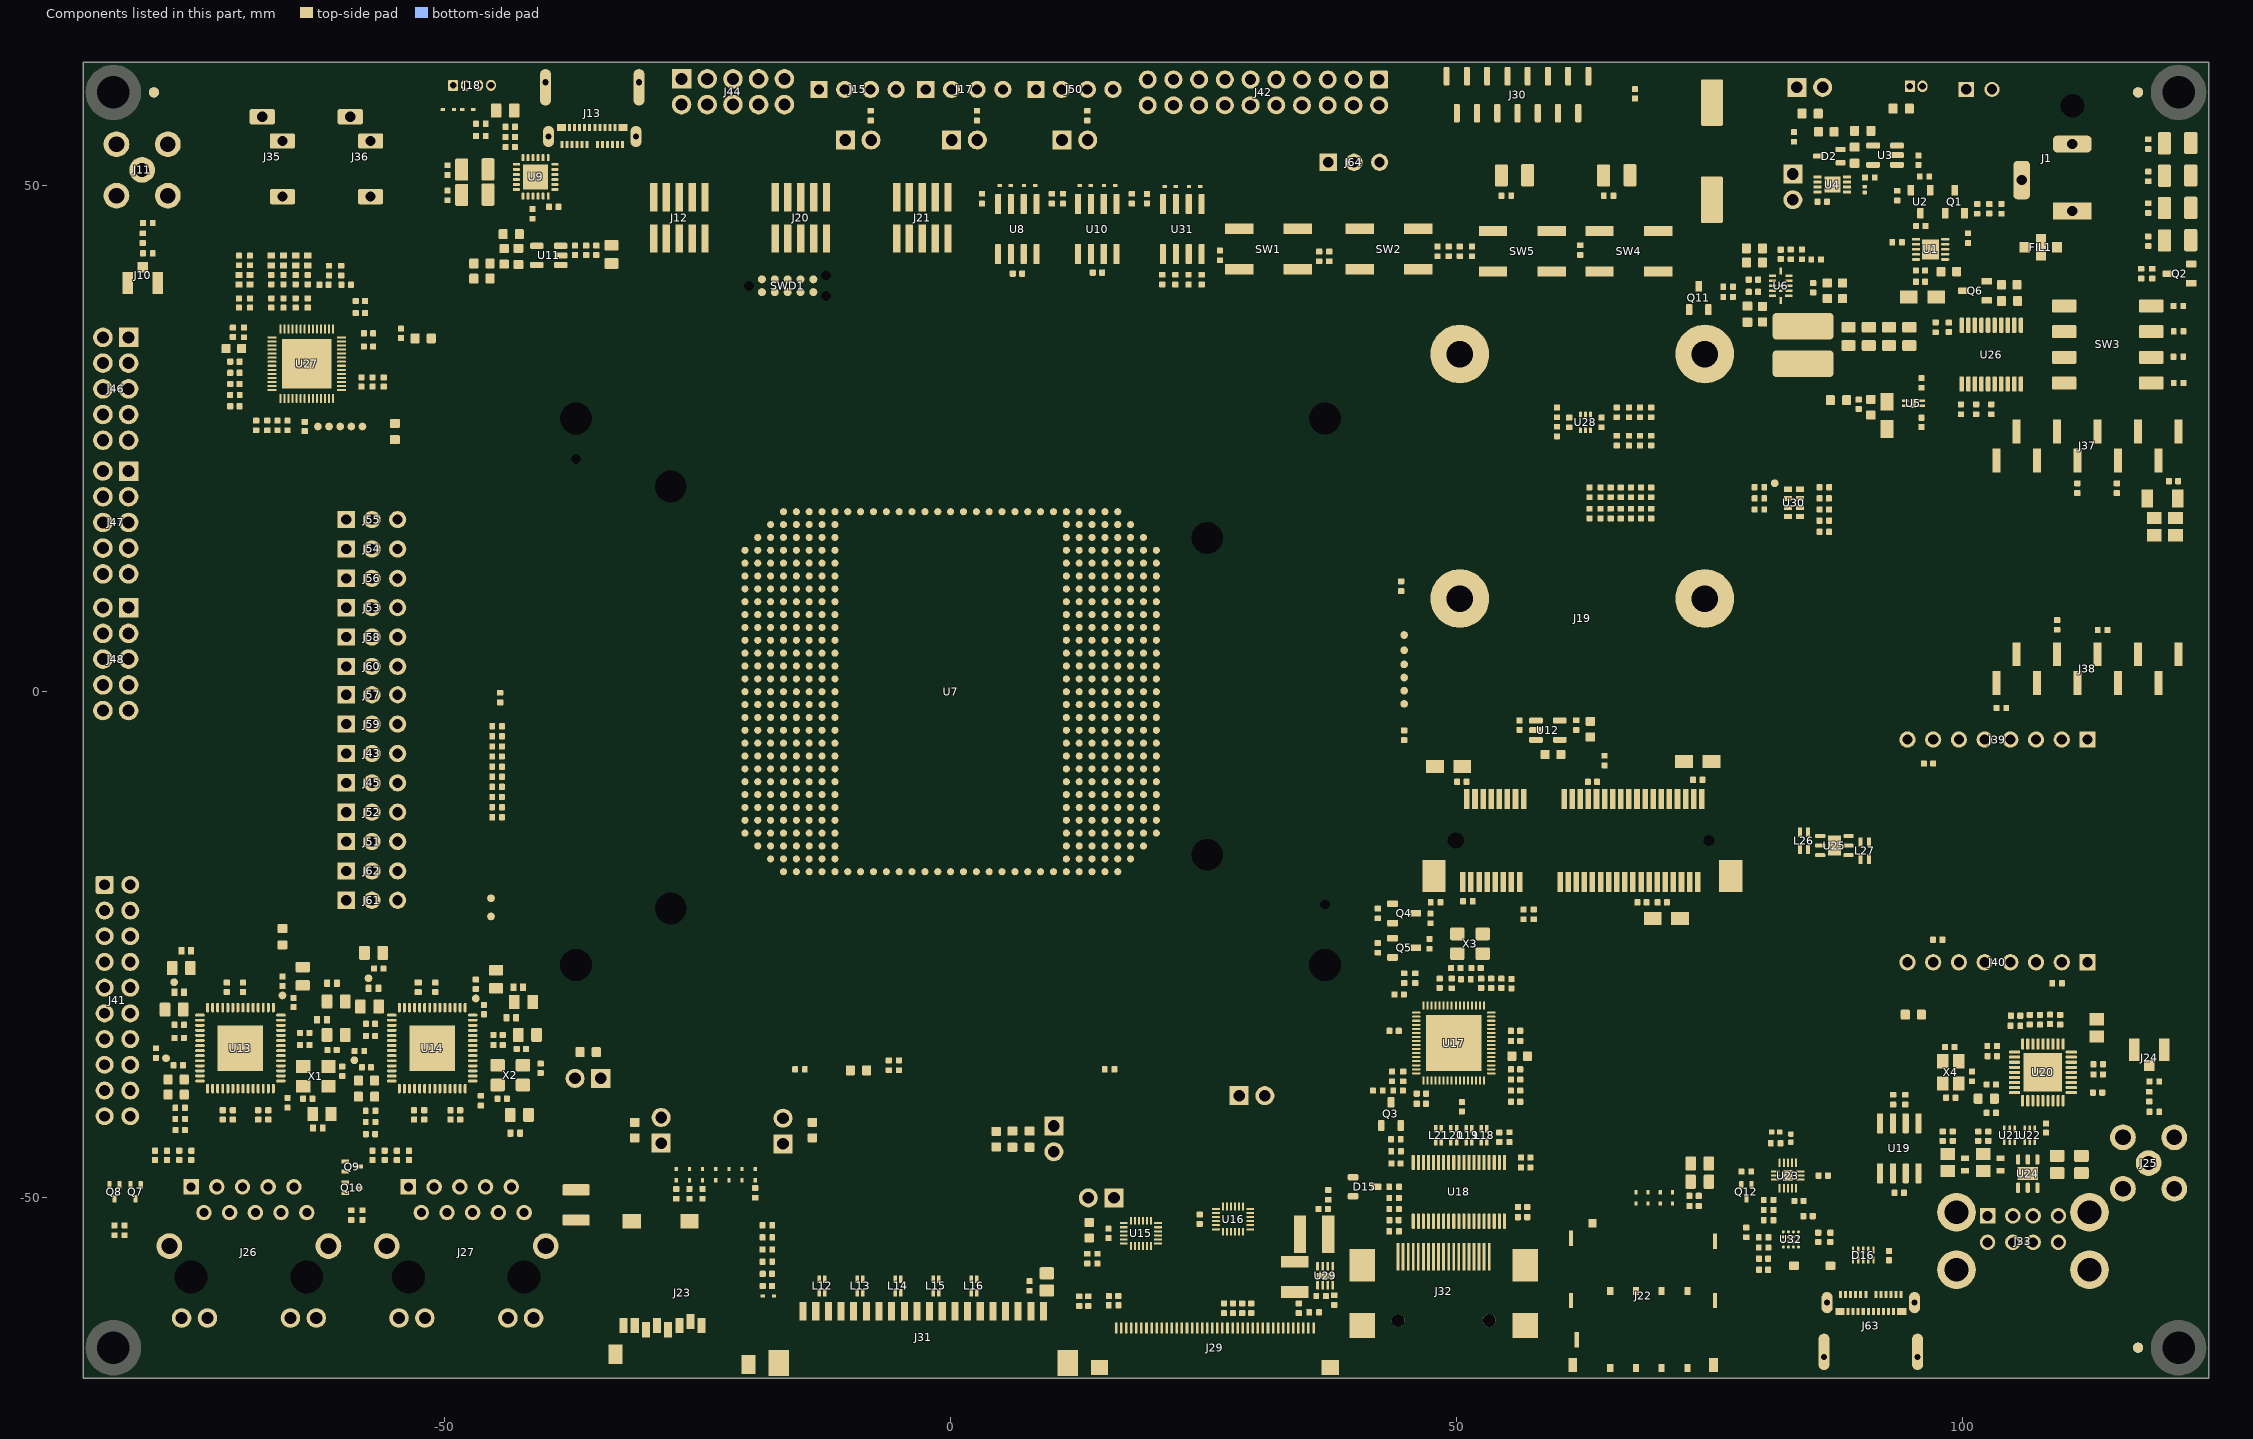
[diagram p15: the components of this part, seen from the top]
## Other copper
1-TOP:
  rectangle net 3V3_BOARD: 86.8,31.3 87.8,33.4
  pour cut-out: -21.7,-14.6 -16.7,-19.6 17.3,-19.6 21.3,-15.6 21.3,14.4 17.3,18.4 -16.7,18.4 -21.7,13.4
  region net CT2: -54.245,-47.752 -54.245,-48.752 -52.845,-48.752 -52.845,-47.752
  region net CT1: -75.715,-47.752 -75.715,-48.752 -74.315,-48.752 -74.315,-47.752
  pour cut-out: 84.9,-58.6 84.9,-67.8 96.9,-67.8 96.9,-58.6
  pour cut-out: -54.845,-47.752 -57.845,-50.752 -57.845,-67.8 -38.345,-67.8 -38.345,-53.252 -42.845,-53.252 -42.845,-47.752
  pour cut-out: -76.315,-47.752 -79.315,-50.752 -79.315,-67.8 -59.815,-67.8 -59.815,-53.252 -64.315,-53.252 -64.315,-47.752
  pour cut-out: 38.15,-53.8 38.15,-67.8 59.15,-67.8 59.15,-53.8
  pour cut-out: 97.1,-49.9 97.1,-67.8 114.8,-67.8 114.8,-50 113.6,-48.8 98.2,-48.8
  region net NetL1_1: 84.6,39.5 84.6,36.6 83.4,36.6 83.4,39.3 83.2,39.5 82,39.5 82,39.7 83.2,39.7 83.3,39.8 84.3,39.8
  text "30017532-02_TOP" at 63.3,-28.95 h1.5
  text ".Layer_Name" at -3,-76.8 h2.54
3-INTOP:
  text ".Layer_Name" at -3,-76.8 h2.54
6-INBOT:
  text ".Layer_Name" at -3,-76.8 h2.54
8-BOTTOM:
  text "30017532-02_BOT" at 85.1,-28.95 h1.5
  text ".Layer_Name" at -3,-76.8 h2.54
2-GND (plane layer: these items are gaps in the copper):
  text "NEGATIVE IMAGE" at -3.625,-66.875 h2.54
  text ".Layer_Name" at -3,-76.8 h2.54
4-PWR (plane layer: these items are gaps in the copper):
  lines w0.3: -20.7,-43.3 -20.7,-41.9 -3.9,-25.1 6.3,-25.1 12.7,-18.7 12.7,-15.7 13.2,-15.2 14.9,-15.2 15.3,-15.6 15.3,-20.4 3.8,-31.9 0.4,-31.9 -6.2,-38.5 -6.2,-43.3 ; -18.4,-43.3 -10.4,-43.3 ; 6.7,62.3 6.7,50.9 10.35,47.25 11,46.6 18.5,46.6 19.3,45.8 19.3,40.1 19.7,39.7 20.4,39.7 20.8,40.1 20.8,45.8 21.6,46.6 75.8,46.6 76.8,45.6 76.8,41.2 87.6,30.4 87.6,7.6 78,-2 54.3,-2 50.4,-5.9 50.4,-20.2 54.6,-24.4 73.4,-24.4 92,-5.8 92,-1.1 95.9,2.8 95.9,12.4 97,13.5 98.1,13.5 113.8,13.5 114.6,14.3 114.6,16.1 113.9,16.8 96.9,16.8 95.9,17.8 95.9,25.8 95.9,33.2 94.8,34.3 87.3,34.3 78.6,43 ; 76.8,42.7 76.8,43 78.6,43 ; 78.4,43 78.6,43 ; 87.6,26.5 81.35,26.5 71.75,36.1 50.3,36.1 ; 93.2,44.3 92.8,44.3 ; -50.4,39 -50.4,62.2 -31.1,62.2 -31.1,42.6 -25.5,37 -18.5,30 39.2,30 46.2,37 49.4,37 50.3,36.1 ; -50.4,39 -46.4,39 ; -50.4,39 -50.4,53 -45.6,53 -43.9,54.7 -43.9,57.9 -43.6,58.2 -42.1,58.2 -41,57.1 -41,45.6 -46.4,40.2 -46.4,39 ; -46.4,39 -46.4,38.4 -36.5,28.5 -36.5,-24 -33,-27.5 -33,-42 -33,-42.9 -32.6,-43.3 -2.2,-43.3 13.1,-43.3 34.2,-22.2 34.2,-6.9 50.3,9.2 50.3,36.1 ; 92.8,44.3 91.7,45.4 91.7,51.6 92.1,52 97.14,52 105.7,43.44 105.7,41.7 105.4,41.4 101.3,41.4 98.4,44.3 94.8,44.3 92.8,44.3 ; 103.4,-40.3 92.2,-40.3 91.8,-39.9 91.8,-37.9 95.1,-34.6 95.1,-30.4 95.7,-29.8 114.9,-29.8 115.6,-30.5 115.6,-32.2 114.7,-33.1 ; 103.4,-40.3 103.4,-36 104,-35.4 106,-35.4 106.4,-35 106.4,-34 107.3,-33.1 114.7,-33.1 ; 103.4,-40.3 105.5,-42.4 113.7,-42.4 115.5,-40.6 115.5,-33.9 114.7,-33.1 ; -79.2,-41.2 -79.2,-39.7 -79.2,-28.7 -79.2,-26.2 -77.3,-24.3 -75.7,-24.3 -75.3,-24.7 -74.4,-25.6 -74.4,-27.5 -73.8,-28.1 -64.2,-28.1 -63.4,-28.9 -62.6,-29.7 -62.6,-36.1 -62.6,-39.5 -63.7,-40.6 -74,-40.6 -76.1,-42.7 -77.7,-42.7 -79.2,-41.2 ; -70.4,27.4 -68.8,25.8 -53.3,25.8 -52.6,26.5 -52.6,30.1 -54.8,32.3 -69.6,32.3 -70.4,31.5 -70.4,28.5 -70.4,27.4 ; -60.1,-41.6 -60.1,-40 -60.1,-30.45 -58.55,-28.9 -57.15,-27.5 -45.85,-27.5 -44.45,-28.9 -43.4,-29.95 -43.4,-35.85 -43.4,-39.25 -44.85,-40.7 -53.5,-40.7 -55.9,-43.1 -58.6,-43.1 -60.1,-41.6 ; 42,-54.8 43.1,-55.9 55.5,-55.9 56.5,-54.9 56.5,-49.8 55.6,-48.9 42.6,-48.9 42,-49.5 42,-54.8
  text ".Layer_Name" at -3,-76.8 h2.54
5-PWR (plane layer: these items are gaps in the copper):
  lines w0.254: 84.1,-67.9 86.28,-67.9 86.28,-59.78 84.9,-58.4 84.9,-55.2 85.9,-54.2 94.2,-54.2 95.5,-55.5 95.5,-67.8
  lines w0.3: -85.7,14.2 -79.4,14.2 -77.3,16.3 -77.3,54.1 -74,57.4 -29.2,57.4 -23.9,52.1 -21.1,49.3 -9.7,49.3 -9.2,48.8 -9.2,43.4 -10.3,42.3 -20.1,42.3 -21.3,41.1 -21.3,38.2 -20.2,37.1 16.5,37.1 18.4,35.2 ; -39.72,57.4 -39.72,45.22 -38.4,43.9 -32.1,43.9 -31.1,44.9 -31.1,57.3 -31.2,57.4 ; 6.7,-43.3 6.3,-43.7 ; 10.5,-39.6 12.1,-41.2 12.1,-50.5 11.6,-51 11.6,-52.3 ; 17.8,-13.9 15.9,-13.9 15.2,-14.6 15.2,-18.9 2.2,-31.9 2.2,-42.6 3.3,-43.7 ; 18.415,35.2 18.415,8.255 19.685,6.985 20.955,6.985 21.4,7.43 21.4,38.6 24,41.2 82.6,41.2 ; 84.9,62.2 84.9,57 84.9,55.5 86.8,53.6 87.7,53.6 89.8,51.5 89.8,48.4 88.8,47.4 82.6,41.2 ; 87.6,30.6 84,30.6 82.5,29.1 82.5,-17.1 51.7,-47.9 37.175,-47.9 35.575,-49.5 23.325,-49.5 20.425,-52.4 11.5,-52.4 8.5,-55.4 8.5,-57.6 9.6,-58.7 56.75,-58.7 64.25,-51.2 87.6,-27.85 90.25,-25.2 97.1,-25.2 97.8,-24.5 97.8,-22.6 96.9,-21.7 89.5,-21.7 87.6,-19.8 87.6,36.2 82.6,41.2 ; -61.5,-46.6 -60.725,-47.375 -60.725,-49.875 -59.55,-51.05 -57.95,-51.05 -54.1,-47.2 -37.7,-47.2 -33,-42.5 -33,-33.1 -42,-24.1 -59.3,-24.1 ; -61.5,-46.6 -74.3,-46.6 -80.5,-52.8 -82.9,-52.8 -83.3,-52.4 -83.3,-47.5 -79.3,-43.5 -79.3,-41.6 -79.3,-26.4 -77,-24.1 -59.3,-24.1 ; -61.5,-46.6 -59.3,-44.4 -59.3,-24.1 ; 3.3,-67.8 3.3,-67.8 ; 3.3,-67.8 3.3,-43.7 ; 3.3,-43.7 5.3,-43.7 ; 5.3,-43.7 6.3,-43.7 ; 5.3,-43.7 5.3,-38.8 17.477,-26.623 17.8,-26.3 17.8,-9 18,-8.8 20.4,-8.8 21.9,-10.3 21.9,-28.1 6.3,-43.7 ; -75.9,-38.5 -75.9,-35.5 -75.9,-33.2 -75,-32.3 -65.8,-32.3 -64.4,-33.7 -64.4,-38.5 -67,-41.1 -72.2,-41.1 -73.3,-41.1 -75.9,-38.5 ; -57.2,-38.7 -54.6,-41.3 -53.5,-41.3 -48.3,-41.3 -45.3,-38.3 -45.3,-33.7 -46.9,-32.1 -56.3,-32.1 -57.2,-33 -57.2,-35.7 -57.2,-38.7
  text ".Layer_Name" at -3,-76.8 h2.54
7-GND (plane layer: these items are gaps in the copper):
  text "NEGATIVE IMAGE" at -3.7,-66.8 h2.54
  text ".Layer_Name" at -3,-76.8 h2.54

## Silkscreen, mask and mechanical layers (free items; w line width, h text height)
Top Overlay:
  drawing of 65 lines, arcs and shapes, not listed
  text "COIN-CELL" at 91.9,55.4 h1
  text "MIPI Camera" at 49.702,53.4 h1.2
  text "CAN1" at -10.8,52.2 h1
  text "CAN2" at -0.2,52.2 h1
  text "RS485" at 10.1,52.1 h1
  text "VIN" at 102.05,51.4 h1
  text "5V" at 102.067,49.9 h1
  text "CONSOLE" at -37.699,49.2 h1.2
  text "HEADPHONE" at -54.765,44.35 h1.1
  text "MIC" at -75.7,44.3 h1.2
  text "POWER" at 28.301,38.9 h1.2
  text "RESET" at 40.201,38.9 h1.2
  text "USER2" at 53.401,38.9 h1.2
  text "USER1" at 64.101,38.9 h1.2
  text "I2C4" at 61.051,28 h1
  text "I2C3" at 64.251,21.2 h1
  text "XBEE" at 108.1,12.9 h1
  text "GND" at 94,-6.8 h1 r270
  text "MOSI" at 99.1,-6.8 h1 r270
  text "MISO" at 101.7,-6.8 h1 r270
  text "SCK" at 104.2,-6.8 h1 r270
  text "CS" at 106.7,-6.8 h1 r270
  text "RST" at 109.3,-6.8 h1 r270
  text "AN" at 111.8,-6.8 h1 r270
  text "+3V3" at 96.7,-7.7 h1 r270
  text "mikro" at 116.68,-15.24 h1 r270
  text "BUS" at 114.8,-15.35 h1.5 r270
  text "+5V" at 96.7,-20.2 h1 r270
  text "GND" at 94,-21.3 h1 r270
  text "SDA" at 99.2,-21.3 h1 r270
  text "SCL" at 101.7,-21.3 h1 r270
  text "PWM" at 111.9,-21.333 h1 r270
  text "INT" at 109.3,-21.5 h1 r270
  text "TX" at 104.2,-22.3 h1 r270
  text "RX" at 106.8,-22.3 h1 r270
  text "ENET1" at -72.399,-46.4 h1.2
  text "ENET2" at -50.899,-46.4 h1.2
  text "SIM" at 61.1,-51.4 h1.2
  text "HDMI" at 38.001,-54.5 h1.2
  text "LVDS Display" at -8.498,-57.2 h1.2
  text "MIPI Display" at 18.602,-59.5 h1.2
  text "MICRO SD" at -34.4,-63.599 h1.2 r90
  text "USB OTG" at 76.701,-65.6 h1.2
Bottom Overlay:
  drawing of 118 lines, arcs and shapes, not listed
  text "J44" at -18.634,54.6 h2
  text "J42" at 33.566,54.2 h2
  text "J44" at -20.2,44.189 h2.05
  text "J42" at 28.3,44.189 h2.05
  text "15.4_SPI_FRM" at -27.351,41.623 h0.82
  text "2" at -24.326,41.623 h0.82
  text "1" at -21.305,41.623 h0.82
  text "PCM_MCLK" at -12.697,41.623 h0.82
  text "MCA_IO14" at 21.149,41.623 h0.82
  text "2" at 24.174,41.623 h0.82
  text "1" at 27.295,41.623 h0.82
  text "MCA_CLKOUT32K" at 39.519,41.623 h0.82
  text "15.4_SPI_INT" at -27.351,39.571 h0.82
  text "4" at -24.326,39.571 h0.82
  text "3" at -21.305,39.571 h0.82
  text "PCM_CLK" at -13.518,39.571 h0.82
  text "MCA_IO15" at 21.149,39.567 h0.82
  text "4" at 24.174,39.571 h0.82
  text "3" at 27.295,39.571 h0.82
  text "MCA_UART_TX" at 37.878,39.573 h0.82
  text "J46" at -57.153,37.772 h2.05
  text "15.4_SPI_RXD" at -27.351,37.518 h0.82
  text "6" at -24.326,37.518 h0.82
  text "5" at -21.305,37.518 h0.82
  text "PCM_IN" at -14.475,37.518 h0.82
  text "MCA_IO16" at 21.149,37.511 h0.82
  text "6" at 24.174,37.518 h0.82
  text "5" at 27.295,37.518 h0.82
  text "MCA_UART_RX" at 37.878,37.523 h0.82
  text "MCA_UART_CTS" at 38.698,35.472 h0.82
  text "15.4_SPI_TXD" at -27.351,35.466 h0.82
  text "8" at -24.326,35.466 h0.82
  text "7" at -21.305,35.466 h0.82
  text "PCM_OUT" at -13.518,35.466 h0.82
  text "MCA_IO17" at 21.149,35.455 h0.82
  text "8" at 24.174,35.466 h0.82
  text "7" at 27.295,35.466 h0.82
  text "2" at -61.279,35.307 h0.82
  text "1" at -58.258,35.307 h0.82
  text "LINE1_IN_L" at -64.43,35.207 h0.82
  text "LINE1_IN_R" at -48.524,35.207 h0.82
  text "15.4_SPI_CLK" at -27.351,33.413 h0.82
  text "10" at -24.326,33.413 h0.82
  text "9" at -21.305,33.413 h0.82
  text "PCM_SYNC" at -12.697,33.413 h0.82
  text "10" at 24.174,33.413 h0.82
  text "9" at 27.295,33.413 h0.82
  text "MCA_UART_RTS" at 38.698,33.422 h0.82
  text "MCA_IO18" at 21.149,33.399 h0.82
  text "4" at -61.279,33.254 h0.82
  text "3" at -58.258,33.254 h0.82
  text "LINE2_IN_L" at -64.43,33.154 h0.82
  text "LINE2_IN_R" at -48.387,33.154 h0.82
  text "12" at 24.174,31.361 h0.82
  text "11" at 27.295,31.361 h0.82
  text "MCA_IO9" at 34.458,31.372 h0.82
  text "GPIO_IO14" at 21.149,31.343 h0.82
  text "6" at -61.279,31.202 h0.82
  text "5" at -58.258,31.202 h0.82
  text "LINE_OUT_L" at -64.43,31.102 h0.82
  text "LINE_OUT_R" at -48.25,31.102 h0.82
  text "MCA_IO10" at 35.142,29.322 h0.82
  text "14" at 24.174,29.308 h0.82
  text "13" at 27.295,29.308 h0.82
  text "GPIO_IO16" at 21.149,29.287 h0.82
  text "8" at -61.279,29.149 h0.82
  text "7" at -58.258,29.149 h0.82
  text "SPKL_N" at -64.43,29.049 h0.82
  text "SPKL_P" at -51.396,29.049 h0.82
  text "MCA_IO11" at 34.868,27.271 h0.82
  text "16" at 24.174,27.256 h0.82
  text "15" at 27.295,27.256 h0.82
  text "J46" at -79.5,27.234 h2 r270
  text "GPIO_IO22" at 21.149,27.23 h0.82
  text "10" at -61.279,27.097 h0.82
  text "9" at -58.258,27.097 h0.82
  text "SPKR_N" at -64.43,26.997 h0.82
  text "SPKR_P" at -51.396,26.997 h0.82
  text "MCA_IO12" at 35.142,25.221 h0.82
  text "18" at 24.174,25.203 h0.82
  text "17" at 27.295,25.203 h0.82
  text "GPIO_IO25" at 21.149,25.174 h0.82
  text "20" at 24.174,23.15 h0.82
  text "19" at 27.295,23.15 h0.82
  text "MCA_IO13" at 35.142,23.171 h0.82
  text "GPIO_IO27" at 21.149,23.118 h0.82
  text "J47" at -36.032,21.546 h2.05
  text "LDO2" at -31.79,19.046 h0.82
  text "2" at -40.047,19.023 h0.82
  text "1" at -37.026,19.023 h0.82
  text "LDO3" at -43.323,18.946 h0.82
  text "4" at -40.047,16.971 h0.82
  text "3" at -37.026,16.971 h0.82
  text "MCA_VREF_OUT" at -43.323,16.946 h0.82
  text "3V3" at -32.611,16.946 h0.82
  text "VCC_MCA" at -43.323,14.946 h0.82
  text "6" at -40.047,14.918 h0.82
  text "5" at -37.026,14.918 h0.82
  text "1V8" at -32.748,14.846 h0.82
  text "J47" at -79.5,14.234 h2 r270
  text "SWIN" at -31.927,12.946 h0.82
  text "8" at -40.047,12.866 h0.82
  text "7" at -37.026,12.866 h0.82
  text "SWOUT" at -43.323,12.846 h0.82
  text "GND" at -43.323,10.846 h0.82
  text "SW_EN" at -30.97,10.846 h0.82
  text "10" at -40.047,10.813 h0.82
  text "9" at -37.026,10.813 h0.82
  text "J48" at -36.032,5.646 h2.05
  text "ADC_IN0" at -29.37,3.146 h0.82
  text "2" at -40.047,3.123 h0.82
  text "1" at -37.026,3.123 h0.82
  text "CLKIN1" at -43.423,2.909 h0.82
  text "SW3 (BOOT)" at 74.6,1.5 h2.55
  text "4" at -40.047,1.071 h0.82
  text "3" at -37.026,1.071 h0.82
  text "ADC_IN1" at -29.643,1.046 h0.82
  text "CLKIN2" at -43.423,0.909 h0.82
  text "J48" at -79.5,0.534 h2 r270
  text "6" at -40.047,-0.982 h0.82
  text "5" at -37.026,-0.982 h0.82
  text "ADC_IN2" at -29.37,-1.054 h0.82
  text "TAMPER0" at -43.423,-1.091 h0.82
  text "SW3.4" at 70.61,-1.58 h2.55
  text "SW3.3" at 76.724,-1.58 h2.55
  text "SW3.2" at 83.093,-1.58 h2.55
  text "SW3.1" at 89.462,-1.58 h2.55
  text "Description" at 63.7,-1.6 h2.55
  text "ADC_IN3" at -29.37,-2.954 h0.82
  text "8" at -40.047,-3.034 h0.82
  text "7" at -37.026,-3.034 h0.82
  text "TAMPER1" at -43.423,-3.191 h0.82
  text "USDHC1 8-bit eMMC 5.1" at 63.8,-4.1 h2.55
  text "X" at 68.2,-4.1 h2.5
  text "OFF" at 75.6,-4.1 h2.55
  text "OFF" at 81.7,-4.1 h2.55
  text "OFF" at 88.3,-4.1 h2.55
  text "MIKROBUS_PWM" at -43.423,-4.917 h0.82
  text "10" at -40.047,-5.087 h0.82
  text "9" at -37.026,-5.087 h0.82
  text "MIKROBUS_ADC" at -25.2,-5.1 h0.82
  text "Infinite Loop" at 63.731,-6.6 h2.55
  text "X" at 68.2,-6.6 h2.5
  text "ON" at 75.6,-6.6 h2.55
  text "OFF" at 81.7,-6.6 h2.55
  text "OFF" at 88.3,-6.6 h2.55
  text "CS" at 106.7,-8.126 h1 r270
  text "AN" at 111.8,-8.126 h1 r270
  text "GND" at 94,-9.125 h1 r270
  text "SCK" at 104.2,-9.125 h1 r270
  text "RST" at 109.3,-9.125 h1 r270
  text "From internal fuses" at 63.7,-9.2 h2.55
  text "X" at 68.2,-9.2 h2.5
  text "OFF" at 75.6,-9.2 h2.55
  text "ON" at 81.7,-9.2 h2.55
  text "OFF" at 88.3,-9.2 h2.55
  text "MOSI" at 99.1,-9.792 h1 r270
  text "MISO" at 101.7,-9.958 h1 r270
  text "+3V3" at 96.6,-10.125 h1 r270
  text "FlexSPI Serial NOR" at 63.7,-11.8 h2.55
  text "X" at 68.2,-11.8 h2.5
  text "ON" at 75.6,-11.8 h2.55
  text "ON" at 81.7,-11.8 h2.55
  text "OFF" at 88.3,-11.8 h2.55
  text "USDHC2 4-bit SD3.0" at 63.7,-14.4 h2.55
  text "X" at 68.2,-14.4 h2.5
  text "OFF" at 75.6,-14.4 h2.55
  text "OFF" at 81.7,-14.4 h2.55
  text "ON" at 88.3,-14.4 h2.55
  text "BUS" at 114.7,-15.35 h1.5 r270
  text "mikro" at 116.58,-15.46 h1 r270
  text "Test Mode" at 63.7,-16.9 h2.55
  text "X" at 68.2,-16.9 h2.5
  text "ON" at 75.6,-16.9 h2.55
  text "OFF" at 81.7,-16.9 h2.55
  text "ON" at 88.3,-16.9 h2.55
  text "Serial Downloader" at 63.7,-19.5 h2.55
  text "X" at 68.2,-19.5 h2.5
  text "OFF" at 75.6,-19.5 h2.55
  text "ON" at 81.7,-19.5 h2.55
  text "ON" at 88.3,-19.5 h2.55
  text "FlexSPI Serial NAND 2K Page" at 63.7,-22 h2.55
  text "X" at 68.2,-22 h2.5
  text "ON" at 75.6,-22 h2.55
  text "ON" at 81.7,-22 h2.55
  text "ON" at 88.3,-22 h2.55
  text "J41" at -57.832,-24.954 h2.05
  text "GND" at 94,-25 h1 r270
  text "+5V" at 96.7,-25 h1 r270
  text "SDA" at 99.2,-25 h1 r270
  text "SCL" at 101.7,-25 h1 r270
  text "TX" at 104.2,-25 h1 r270
  text "RX" at 106.8,-25 h1 r270
  text "INT" at 109.3,-25 h1 r270
  text "PWM" at 111.9,-25 h1 r270
  text "1" at -61.226,-27.377 h0.82
  text "2" at -58.147,-27.377 h0.82
  text "3V3_RF" at -64.5,-27.4 h0.82
  text "WLAN_SD3_CLK" at -46.779,-27.4 h0.82
  text "BT_UART1_TX" at -64.5,-29.4 h0.82
  text "WLAN_SD3_CMD" at -46.779,-29.4 h0.82
  text "3" at -61.226,-29.429 h0.82
  text "4" at -58.147,-29.429 h0.82
  text "5" at -61.226,-31.482 h0.82
  text "6" at -58.147,-31.482 h0.82
  text "BT_UART1_RX" at -64.5,-31.5 h0.82
  text "WLAN_SD3_D0" at -47.6,-31.5 h0.82
  text "J41" at -79.5,-32.733 h2 r270
  text "WLAN_SD3_D1" at -47.874,-33.5 h0.82
  text "7" at -61.226,-33.534 h0.82
  text "8" at -58.147,-33.534 h0.82
  text "BT_UART1_CTS" at -64.5,-33.6 h0.82
  text "BT_UART1_RTS" at -64.5,-35.6 h0.82
  text "9" at -61.226,-35.587 h0.82
  text "10" at -58.147,-35.587 h0.82
  text "WLAN_SD3_D2" at -47.6,-35.6 h0.82
  text "11" at -61.226,-37.639 h0.82
  text "12" at -58.147,-37.639 h0.82
  text "GND" at -64.5,-37.7 h0.82
  text "WLAN_SD3_D3" at -47.6,-37.7 h0.82
  text "13" at -61.226,-39.692 h0.82
  text "14" at -58.147,-39.692 h0.82
  text "BT_HOST_WAKE" at -64.5,-39.7 h0.82
  text "GND" at -54.166,-39.7 h0.82
  text "BT_DEV_WAKE" at -64.5,-41.7 h0.82
  text "WL_DEV_WAKE" at -47.6,-41.7 h0.82
  text "15" at -61.226,-41.744 h0.82
  text "16" at -58.147,-41.744 h0.82
  text "17" at -61.226,-43.797 h0.82
  text "18" at -58.147,-43.797 h0.82
  text "WL_HOST_WAKE" at -46.779,-43.817 h0.82
  text "GND" at -64.5,-43.9 h0.82
  text "GND" at -54.166,-45.8 h0.82
  text "19" at -61.226,-45.85 h0.82
  text "20" at -58.147,-45.85 h0.82
  text "GND" at -64.5,-46 h0.82
Board Outline:
  the board outline again, w0.25
3D:
  lines w0.15: 30.6,7.7 87.75,7.7
Sheet Graphics:
  drawing of 578 lines, arcs and shapes, not listed
  text "1" at 357.623,112.943 h4.57
  text "4" at -60.842,112.308 h4.57
  text "3" at 81.398,112.308 h4.57
  text "2" at 220.463,111.673 h4.57
  text "QUALIFICATION" at 132.05,96.45 h6
  text "1. REFER TO DIGI FAI DOCUMENT 96000656 (LATEST REVISION)/IPC 6011 CLASS 2 FOR QUALIFICATION REQUIREMENTS" at 132.05,82.3 h6
  text "SPECIFICATION" at 132.05,77.25 h6
  text "D" at -121.167,73.573 h7.11
  text "2. FABRICATE IN ACCORDANCE WITH IPC-6012 (LATEST REVISION), CLASS 2" at 132.05,70.6 h6
  text "D" at 424.171,69.128 h7.11
  text "3. WORKMANSHIP TO BE EQUAL TO AND COMPLIANT WITH THE REQUIREMENTS OF IPC-A-600 (LATEST REVISION) CLASS 2 OR HIGHER" at 132.05,58.2 h6
  text "4. DIMENSIONING AND TOLERANCES IN ACCORDANCE WITH IPC-D-356 (LATEST REVISION)" at 132.05,46.7 h6
  text "5. FINISHED ASSEMBLY TO CONFORM TO LATEST REVISION OF EU DIRECTIVES FOR RoHS and REACH AT TIME OF MANUFACTURE" at 132.05,41.8 h6
  text "MATERIAL" at 132.05,36.4 h6
  text "6. IN ACCORDANCE WITH IPC-4101/126, NEMA GRADE FR-4 EPOXY GLASS, COLOR: NATURAL, MIN Tg RATING: 170°C WITH Td 340°C MIN. / DIELECTRIC CONSTANT: 4.42 @ 2GHz / LOSS TANGENT: 0.016 / MATERIAL: IT-180A" at 132.05,10.1 h6
  text "7. BOARD SHALL MEET REQUIREMENTS OF UL976 WITH FLAMMABILITY RATING OF 94V-0. VENDOR SHALL PLACE UL LOGO OR DESIGNATION ON PCB." at 132.05,-4.8 h6
  text "8. TOTAL MATERIAL THICKNESS OVER MASK IS 2mm (+/- 200µm)COPPER WEIGHT: 1/2oz EXTERNAL LAYERS, 1/2oz INTERNAL LAYERS" at 132.05,-17.5 h6
  text "9. MATERIALS AND PROCESSES USED IN THE MANUFACTURE OF THIS BOARD SHALL BE RoHS COMPLIANT WITH EU DIRECTIVE (LATEST REVISIONS)" at 132.05,-28.9 h6
  text "DRILLING" at 132.05,-33.6 h6
  text "C" at -121.167,-35.647 h7.11
  text "C" at 422.901,-35.647 h7.11
  text "10. ALL HOLES ARE FINISHED SIZES. SEE TABLE FOR TOLERANCES." at 132.05,-40.1 h6
  text "11. LAYER TO LAYER REGISTRATION SHALL BE WITHIN 0.005\"" at 132.05,-46.2 h6
  text "12. FOLLOW OUTLINES ON GERBERS FOR BOARD EDGE SLOTS AND CUT-OUTS. TOLERANCE ±0.005\" / SOLDERMASK" at 132.05,-56 h6
  text "SOLDERMASK" at 132.05,-61.3 h6
  text "13. APPLY SOLDERMASK PRS2000 (LPI OR EQUIVALENT) OVER BARE COPPER, BOTH SIDES" at 132.05,-68.5 h6
  text "14. SOLDERMASK MATERIAL PER IPC-SM-840, CLASS 2 SHALL BE USED. COLOR: BLUE" at 132.05,-73.1 h6
  text "15. MINIMUM SOLDERMASK THICKNESS IS NOT BELOW 0.0003\"" at 132.05,-79.8 h6
  text "SILKSCREEN" at 132.05,-85 h6
  text "16. APPLY SILKSCREEN TO TOP AND BOTTOM SIDES OF PCB USING WHITE, NON-CONDUCTIVE EPOXY INK COMPLIANT TO IPC-4781 (LATEST REVISION)" at 132.05,-96.491 h6
  text "FINISH" at 131.55,-103 h6
  text "17. PWB FABRICATOR SHALL COMPENSATE FOR MANUFACTURING PROCESS TOLERANCES BY ADJUSTING ARTWORK" at 131.55,-114.491 h6
  text "18. ALL EXPOSED CONDUCTIVE SURFACES SHALL BE IMMERSION GOLD (6±4 MICROINCHES GOLD OVER 175 ±75 MICROINCHES OF NICKEL) COATED." at 131.6,-125.9 h6
  text "19. FINISHED BOARDS SHALL BE FREE OF NICKS, SCRATCHES, VOIDS, EXPOSED COPPER, POOR PLATING, OR MIS-DRILLED HOLES." at 131.3,-137.4 h6
  text "B" at -121.167,-141.692 h7.11
  text "B" at 422.901,-141.692 h7.11
  text "20. BOW AND TWIST NOT TO EXCEED 0.007 mil/mil ACCORDING TO IPC-A-600 (LATEST REVISION)." at 131.3,-148.3 h6
  text "21. REMOVE ALL BURRS AND BREAK SHARP EDGES 0.015\" MAX" at 131.3,-155.1 h6
  text "ELECTRICAL TEST" at 131.55,-155.9 h6
  text "22. DONE PRIOR TO BUILDING USING SUPPLIED GERBER DATA OR ODB++ DATABASE AND AN IPC-D-356 NETLIST." at 131.55,-166.3 h6
  text "23. ALL PCB's SHALL BE 100% ELECTRICALLY TESTED FOR OPENS AND SHORTS USING SUPPLIED IPC-D-356 NETLIST PER IPC-9252. (LATEST REVISION)" at 131.55,-177.7 h6
  text "24. TEST STAMP IN NON-LEGEND AREA ON THE PRIMARY SIDE OF PCB." at 131.55,-183.8 h6
  text "SOLDERABILITY TEST" at 131.55,-188 h6
  text "25. FINAL FINSH SHALL MEET THE SOLDERABILITY REQUIREMENTS OF J-STD-003 (LATEST REVISION) FOR LEAD-FREE PROCESSES" at 131.55,-201.6 h6
  text "THERMAL STRESS TEST" at 131.55,-206.9 h6
  text "Layer" at -106.031,-210.435 h1.52
  text "Name" at -95.62,-210.435 h1.52
  text "Material" at -72.004,-210.435 h1.52
  text "Thickness" at -56.768,-210.435 h1.52
  text "Constant" at -40.262,-210.435 h1.52
  text "Board Layer Stack" at -25.788,-210.435 h1.52
  text "26. THERMALLY STRESS TEST THE BOARD PER IPC-TM-650 METHOD 2.6.27 (LATEST REVISION) AT 260ºC" at 131.546,-212.662 h6
  text "Top Overlay" at -95.62,-213.483 h1.52
  text "Top Solder" at -95.62,-216.531 h1.52
  text "SM-003" at -72.004,-216.531 h1.52
  text "0,010mm" at -56.768,-216.531 h1.52
  text "4" at -40.262,-216.531 h1.52
  text "1" at -106.031,-219.579 h1.52
  text "1-TOP" at -95.62,-219.579 h1.52
  text "CF-003" at -72.004,-219.579 h1.52
  text "0,018mm" at -56.768,-219.579 h1.52
  text "Dielectric1" at -95.62,-222.627 h1.52
  text "PP-017" at -72.004,-222.627 h1.52
  text "0,120mm" at -56.768,-222.627 h1.52
  text "4.2" at -40.262,-222.627 h1.52
  text "2" at -106.031,-225.675 h1.52
  text "2-GND" at -95.62,-225.675 h1.52
  text "CF-004" at -72.004,-225.675 h1.52
  text "0,035mm" at -56.768,-225.675 h1.52
  text "Dielectric2" at -95.62,-228.723 h1.52
  text "Core-015" at -72.004,-228.723 h1.52
  text "0,300mm" at -56.768,-228.723 h1.52
  text "4.2" at -40.262,-228.723 h1.52
  text "3" at -106.031,-231.771 h1.52
  text "3-INTOP" at -95.62,-231.771 h1.52
  text "CF-004" at -72.004,-231.771 h1.52
  text "0,035mm" at -56.768,-231.771 h1.52
  text "A" at -120.735,-234.402 h7.11
  text "A" at 423.333,-234.402 h7.11
  text "Dielectric3" at -95.62,-234.819 h1.52
  text "PP-017" at -72.004,-234.819 h1.52
  text "0,180mm" at -56.768,-234.819 h1.52
  text "4.2" at -40.262,-234.819 h1.52
  text "4" at -106.031,-237.867 h1.52
  text "4-PWR" at -95.62,-237.867 h1.52
  text "CF-004" at -72.004,-237.867 h1.52
  text "0,035mm" at -56.768,-237.867 h1.52
  text "CAD GENERATED:" at 362.068,-239.482 h1.27
  text "CAD GENERATED:" at 362.068,-239.482 h1.27
  text ".pcb_File_Name_No_Path" at 377.562,-239.482 h2.17
  text "Dielectric6" at -95.62,-240.915 h1.52
  text "Core-036" at -72.004,-240.915 h1.52
  text "0,200mm" at -56.768,-240.915 h1.52
  text "4.2" at -40.262,-240.915 h1.52
  text "EXCEPT AS MAY BE OTHERWISE PROVIDED BY" at 263.008,-243.546 h2.17
  text "5" at -106.031,-243.963 h1.52
  text "5-PWR" at -95.62,-243.963 h1.52
  text "CF-004" at -72.004,-243.963 h1.52
  text "0,035mm" at -56.768,-243.963 h1.52
  text "DIGI INTERNATIONAL INC" at 356.988,-245.07 h2.54
  text "CONTRACT, THIS DOCUMENT IS THE PROPERTY" at 263.008,-245.578 h2.17
  text "Dielectric10" at -95.62,-247.011 h1.52
  text "PP-017" at -72.004,-247.011 h1.52
  text "0,180mm" at -56.768,-247.011 h1.52
  text "4.2" at -40.262,-247.011 h1.52
  text "OF DIGI INTERNATIONAL.  IF RELEASED TO OTHER" at 263.008,-247.61 h2.17
  text "9350 Excelsior Blvd Suite 700" at 356.988,-248.626 h2.54
  text "SOURCES, IT SHALL BE RECEIVED BY SUCH" at 263.008,-249.642 h2.17
  text "6" at -106.031,-250.059 h1.52
  text "6-INBOT" at -95.62,-250.059 h1.52
  text "CF-004" at -72.004,-250.059 h1.52
  text "0,035mm" at -56.768,-250.059 h1.52
  text "SOURCES IN TOTAL CONFIDENCE AND SHALL NOT" at 263.008,-251.674 h2.17
  text "Impedance Control +/- 10% Diferential parirs Top and Bottom Layer" at 8.1,-251.8 h2
  text "Hopkins, MN 55343" at 357.496,-252.182 h2.54
  text "Dielectric 12" at -95.62,-253.107 h1.52
  text "Core-015" at -72.004,-253.107 h1.52
  text "0,300mm" at -56.768,-253.107 h1.52
  text "4.2" at -40.262,-253.107 h1.52
  text "BE RELEASED TO ANY THIRD PARTY OR PARTIES," at 263.008,-253.706 h2.17
  text "Impedance" at 9.4,-255.7 h2
  text "Track Width" at 28.2,-255.7 h2
  text "NOR USED FOR MANUFACTURE OR SALE OF THE" at 263.008,-255.738 h2.17
  text "Dif.Pair Space" at 51.4,-255.8 h2
  text "LAYER" at 79.3,-255.8 h2
  text "Reference Plane" at 91.2,-255.809 h2
  text "7" at -106.031,-256.155 h1.52
  text "7-GND" at -95.62,-256.155 h1.52
  text "CF-004" at -72.004,-256.155 h1.52
  text "0,035mm" at -56.768,-256.155 h1.52
  text "ARTICLES WITHOUT PRIOR WRITTEN" at 263.008,-257.77 h2.17
  text "DIGI INTERNATIONAL" at 346.1,-258.175 h2.54
  text "Dielectric11" at -95.62,-259.203 h1.52
  text "PP-017" at -72.004,-259.203 h1.52
  text "0,120mm" at -56.768,-259.203 h1.52
  text "4.2" at -40.262,-259.203 h1.52
  text "100ohms" at 9.4,-259.8 h2
  text ".150mm" at 28.5,-259.8 h2
  text ".204mm" at 51.7,-259.8 h2
  text "1 & 8" at 80.1,-259.8 h2
  text "2 & 7" at 91.9,-259.8 h2
  text "AUTHORIZATION." at 263.008,-259.802 h2.17
  text "ConnectCore MP1" at 347.5,-262.1 h2.54
  text "8" at -106.031,-262.251 h1.52
  text "8-BOTTOM" at -95.62,-262.251 h1.52
  text "CF-003" at -72.004,-262.251 h1.52
  text "0,018mm" at -56.768,-262.251 h1.52
  text "90ohms" at 9.1,-263.8 h2
  text ".168mm" at 28.5,-263.8 h2
  text ".150mm" at 51.7,-263.8 h2
  text "1 & 8" at 80.1,-263.8 h2
  text "2 & 7" at 91.9,-263.8 h2
  text "Bottom Solder" at -95.62,-265.299 h1.52
  text "SM-003" at -72.004,-265.299 h1.52
  text "0,010mm" at -56.768,-265.299 h1.52
  text "4" at -40.262,-265.299 h1.52
  text "DEVELOPMENT BOARD" at 343.7,-266.3 h2.54
  text "ENGINEER" at 262.5,-266.406 h1.27
  text "JUAN ANZOLA" at 279.874,-267.066 h1.27
  text "85ohms" at 9.1,-267.8 h2
  text ".192mm" at 28.5,-267.8 h2
  text ".150mm" at 51.7,-267.8 h2
  text "1 & 8" at 80.1,-267.8 h2
  text "2 & 7" at 91.9,-267.8 h2
  text "Bottom Overlay" at -95.62,-268.347 h1.52
  text "PCB DESIGNER" at 262.5,-271.486 h1.27
  text "SIZE" at 315.84,-271.486 h1.27
  text "CAGE NO." at 323.968,-271.486 h1.27
  text "PCB NO." at 351.908,-271.486 h1.27
  text "REV." at 413.884,-271.486 h1.27
  text "JUAN ANZOLA" at 279.874,-272.146 h1.27
  text "3001753X-02" at 367.85,-275.55 h2.54
  text "DATE" at 262.5,-276.058 h1.27
  text "C" at 316.348,-276.058 h2.54
  text "A" at 413.884,-276.058 h2.54
  text ".Print_Date" at 279.264,-277.074 h1.27
  text "JIRA EPIC:" at 262.5,-281.138 h1.27
  text ".Print_Scale" at 313.808,-282.662 h1.27
  text "SVN HEAD REV:" at 339.208,-282.662 h1.27
  text ".VersionControl_RevNumber" at 354.956,-282.662 h1.27
  text "SHEET:" at 377.308,-282.662 h1.27
  text "1 OF 1" at 395.85,-282.662 h1.27
  text "1" at 357.623,-292.187 h4.57
  text "4" at -60.842,-292.822 h4.57
  text "3" at 81.398,-292.822 h4.57
  text "2" at 220.463,-293.457 h4.57
Drill Drawing:
  drawing of 184 lines, arcs and shapes, not listed
  text ".Layer_Name" at -107.2,-78.4 h2.54
  text "Symbol" at -105.097,-82.666 h1.83
  text "Count" at -92.248,-82.666 h1.83
  text "Hole Size" at -75.742,-82.666 h1.83
  text "Plated" at -46.033,-82.666 h1.83
  text "Hole Type" at -33.184,-82.666 h1.83
  text "Drill Layer Pair" at -14.545,-82.666 h1.83
  text "Via/Pad" at 15.672,-82.666 h1.83
  text "Pad Shape" at 30.654,-82.666 h1.83
  text "Template" at 58.332,-82.666 h1.83
  text "1" at -92.248,-86.476 h1.52
  text "1,100mm (43,31mil)" at -75.742,-86.476 h1.52
  text "NPTH" at -46.033,-86.476 h1.52
  text "Round" at -33.184,-86.476 h1.52
  text "1-TOP - 8-BOTTOM" at -14.545,-86.476 h1.52
  text "Pad" at 15.672,-86.476 h1.52
  text "Rounded" at 30.654,-86.476 h1.52
  text "c0hn110" at 58.332,-86.476 h1.52
  text "1" at -92.248,-90.286 h1.52
  text "1,600mm (62,99mil)" at -75.742,-90.286 h1.52
  text "NPTH" at -46.033,-90.286 h1.52
  text "Round" at -33.184,-90.286 h1.52
  text "1-TOP - 8-BOTTOM" at -14.545,-90.286 h1.52
  text "Pad" at 15.672,-90.286 h1.52
  text "Rounded" at 30.654,-90.286 h1.52
  text "c0hn160" at 58.332,-90.286 h1.52
  text "1" at -92.248,-94.096 h1.52
  text "2,362mm (93,00mil)" at -75.742,-94.096 h1.52
  text "NPTH" at -46.033,-94.096 h1.52
  text "Round" at -33.184,-94.096 h1.52
  text "1-TOP - 8-BOTTOM" at -14.545,-94.096 h1.52
  text "Pad" at 15.672,-94.096 h1.52
  text "Rounded" at 30.654,-94.096 h1.52
  text "c0hn236" at 58.332,-94.096 h1.52
  text "2" at -92.248,-97.906 h1.52
  text "1,020mm (40,16mil)" at -75.742,-97.906 h1.52
  text "PTH" at -46.033,-97.906 h1.52
  text "Round" at -33.184,-97.906 h1.52
  text "1-TOP - 8-BOTTOM" at -14.545,-97.906 h1.52
  text "Pad" at 15.672,-97.906 h1.52
  text "(Mixed)" at 30.654,-97.906 h1.52
  text "(Mixed)" at 58.332,-97.906 h1.52
  text "C" at -105.836,-98.16 h1.69
  text "2" at -92.248,-101.716 h1.52
  text "1,270mm (50,00mil)" at -75.742,-101.716 h1.52
  text "NPTH" at -46.033,-101.716 h1.52
  text "Round" at -33.184,-101.716 h1.52
  text "1-TOP - 8-BOTTOM" at -14.545,-101.716 h1.52
  text "Pad" at 15.672,-101.716 h1.52
  text "Rounded" at 30.654,-101.716 h1.52
  text "c127hn127" at 58.332,-101.716 h1.52
  text "2" at -92.248,-105.526 h1.52
  text "1,400mm (55,12mil)" at -75.742,-105.526 h1.52
  text "PTH" at -46.033,-105.526 h1.52
  text "Round" at -33.184,-105.526 h1.52
  text "1-TOP - 8-BOTTOM" at -14.545,-105.526 h1.52
  text "Pad" at 15.672,-105.526 h1.52
  text "Rounded" at 30.654,-105.526 h1.52
  text "c254h140" at 58.332,-105.526 h1.52
  text "J" at -105.836,-105.78 h1.69
  text "3" at -92.248,-109.336 h1.52
  text "0,991mm (39,00mil)" at -75.742,-109.336 h1.52
  text "NPTH" at -46.033,-109.336 h1.52
  text "Round" at -33.184,-109.336 h1.52
  text "1-TOP - 8-BOTTOM" at -14.545,-109.336 h1.52
  text "Pad" at 15.672,-109.336 h1.52
  text "Rounded" at 30.654,-109.336 h1.52
  text "c0hn99m109(Tol5-5)" at 58.332,-109.336 h1.52
  text "R" at -105.836,-109.59 h1.69
  text "3" at -92.248,-113.146 h1.52
  text "1,016mm (40,00mil)" at -75.742,-113.146 h1.52
  text "PTH" at -46.033,-113.146 h1.52
  text "Slot" at -33.184,-113.146 h1.52
  text "1-TOP - 8-BOTTOM" at -14.545,-113.146 h1.52
  text "Pad" at 15.672,-113.146 h1.52
  text "Rectangle" at 30.654,-113.146 h1.52
  text "(Mixed)" at 58.332,-113.146 h1.52
  text "A" at -105.836,-113.4 h1.69
  text "4" at -92.248,-116.956 h1.52
  text "0,600mm (23,62mil)" at -75.742,-116.956 h1.52
  text "PTH" at -46.033,-116.956 h1.52
  text "Slot" at -33.184,-116.956 h1.52
  text "1-TOP - 8-BOTTOM" at -14.545,-116.956 h1.52
  text "Pad" at 15.672,-116.956 h1.52
  text "Rounded" at 30.654,-116.956 h1.52
  text "r210_110h60_160r100m215_115(Tol8-8)" at 58.332,-116.956 h1.52
  text "4" at -92.248,-120.766 h1.52
  text "0,600mm (23,62mil)" at -75.742,-120.766 h1.52
  text "PTH" at -46.033,-120.766 h1.52
  text "Slot" at -33.184,-120.766 h1.52
  text "1-TOP - 8-BOTTOM" at -14.545,-120.766 h1.52
  text "Pad" at 15.672,-120.766 h1.52
  text "Rounded" at 30.654,-120.766 h1.52
  text "r360_110h60_210r100o-50_0m365_115(Tol8-8)" at 58.332,-120.766 h1.52
  text "4" at -92.248,-124.576 h1.52
  text "1,600mm (63,00mil)" at -75.742,-124.576 h1.52
  text "PTH" at -46.033,-124.576 h1.52
  text "Round" at -33.184,-124.576 h1.52
  text "1-TOP - 8-BOTTOM" at -14.545,-124.576 h1.52
  text "Pad" at 15.672,-124.576 h1.52
  text "Rounded" at 30.654,-124.576 h1.52
  text "c254h160m264(Tol8-8)" at 58.332,-124.576 h1.52
  text "U" at -105.836,-124.83 h1.69
  text "4" at -92.248,-128.386 h1.52
  text "2,362mm (93,00mil)" at -75.742,-128.386 h1.52
  text "PTH" at -46.033,-128.386 h1.52
  text "Round" at -33.184,-128.386 h1.52
  text "1-TOP - 8-BOTTOM" at -14.545,-128.386 h1.52
  text "Pad" at 15.672,-128.386 h1.52
  text "Rounded" at 30.654,-128.386 h1.52
  text "c381h236" at 58.332,-128.386 h1.52
  text "4" at -92.248,-132.196 h1.52
  text "2,600mm (102,36mil)" at -75.742,-132.196 h1.52
  text "PTH" at -46.033,-132.196 h1.52
  text "Round" at -33.184,-132.196 h1.52
  text "1-TOP - 8-BOTTOM" at -14.545,-132.196 h1.52
  text "Pad" at 15.672,-132.196 h1.52
  text "Rounded" at 30.654,-132.196 h1.52
  text "c580h260" at 58.332,-132.196 h1.52
  text "P" at -105.836,-132.45 h1.69
  text "4" at -92.248,-136.006 h1.52
  text "3,150mm (124,02mil)" at -75.742,-136.006 h1.52
  text "NPTH" at -46.033,-136.006 h1.52
  text "Round" at -33.184,-136.006 h1.52
  text "1-TOP - 8-BOTTOM" at -14.545,-136.006 h1.52
  text "Pad" at 15.672,-136.006 h1.52
  text "Rounded" at 30.654,-136.006 h1.52
  text "c0hn315x600" at 58.332,-136.006 h1.52
  text "4" at -92.248,-139.816 h1.52
  text "3,150mm (124,02mil)" at -75.742,-139.816 h1.52
  text "PTH" at -46.033,-139.816 h1.52
  text "Round" at -33.184,-139.816 h1.52
  text "1-TOP - 8-BOTTOM" at -14.545,-139.816 h1.52
  text "Pad" at 15.672,-139.816 h1.52
  text "Rounded" at 30.654,-139.816 h1.52
  text "c0h315" at 58.332,-139.816 h1.52
  text "B" at -105.836,-140.07 h1.69
  text "4" at -92.248,-143.626 h1.52
  text "3,200mm (125,98mil)" at -75.742,-143.626 h1.52
  text "PTH" at -46.033,-143.626 h1.52
  text "Round" at -33.184,-143.626 h1.52
  text "1-TOP - 8-BOTTOM" at -14.545,-143.626 h1.52
  text "Pad" at 15.672,-143.626 h1.52
  text "Rounded" at 30.654,-143.626 h1.52
  text "c550h320" at 58.332,-143.626 h1.52
  text "O" at -105.836,-143.88 h1.69
  text "4" at -92.248,-147.436 h1.52
  text "3,250mm (127,95mil)" at -75.742,-147.436 h1.52
  text "NPTH" at -46.033,-147.436 h1.52
  text "Round" at -33.184,-147.436 h1.52
  text "1-TOP - 8-BOTTOM" at -14.545,-147.436 h1.52
  text "Pad" at 15.672,-147.436 h1.52
  text "Rounded" at 30.654,-147.436 h1.52
  text "c0hn325m335(Tol5-5)" at 58.332,-147.436 h1.52
  text "V" at -105.836,-147.69 h1.69
  text "6" at -92.248,-151.246 h1.52
  text "0,650mm (25,59mil)" at -75.742,-151.246 h1.52
  text "PTH" at -46.033,-151.246 h1.52
  text "Round" at -33.184,-151.246 h1.52
  text "1-TOP - 8-BOTTOM" at -14.545,-151.246 h1.52
  text "Pad" at 15.672,-151.246 h1.52
  text "(Mixed)" at 30.654,-151.246 h1.52
  text "(Mixed)" at 58.332,-151.246 h1.52
  text "D" at -105.836,-151.5 h1.69
  text "6" at -92.248,-155.056 h1.52
  text "1,000mm (39,37mil)" at -75.742,-155.056 h1.52
  text "PTH" at -46.033,-155.056 h1.52
  text "Slot" at -33.184,-155.056 h1.52
  text "1-TOP - 8-BOTTOM" at -14.545,-155.056 h1.52
  text "Pad" at 15.672,-155.056 h1.52
  text "Rounded Rectangle" at 30.654,-155.056 h1.52
  text "r250_150h100_200r25" at 58.332,-155.056 h1.52
  text "8" at -92.248,-158.866 h1.52
  text "1,194mm (47,00mil)" at -75.742,-158.866 h1.52
  text "PTH" at -46.033,-158.866 h1.52
  text "Round" at -33.184,-158.866 h1.52
  text "1-TOP - 8-BOTTOM" at -14.545,-158.866 h1.52
  text "Pad" at 15.672,-158.866 h1.52
  text "Rounded" at 30.654,-158.866 h1.52
  text "c193h119m203(Tol8-8)" at 58.332,-158.866 h1.52
  text "W" at -105.836,-159.12 h1.69
  text "8" at -92.248,-162.676 h1.52
  text "1,549mm (61,00mil)" at -75.742,-162.676 h1.52
  text "PTH" at -46.033,-162.676 h1.52
  text "Round" at -33.184,-162.676 h1.52
  text "1-TOP - 8-BOTTOM" at -14.545,-162.676 h1.52
  text "Pad" at 15.672,-162.676 h1.52
  text "Rounded" at 30.654,-162.676 h1.52
  text "c254h155" at 58.332,-162.676 h1.52
  text "K" at -105.836,-162.93 h1.69
  text "20" at -92.248,-166.486 h1.52
  text "0,889mm (35,00mil)" at -75.742,-166.486 h1.52
  text "PTH" at -46.033,-166.486 h1.52
  text "Round" at -33.184,-166.486 h1.52
  text "1-TOP - 8-BOTTOM" at -14.545,-166.486 h1.52
  text "Pad" at 15.672,-166.486 h1.52
  text "(Mixed)" at 30.654,-166.486 h1.52
  text "(Mixed)" at 58.332,-166.486 h1.52
  text "T" at -105.836,-166.74 h1.69
  text "22" at -92.248,-170.296 h1.52
  text "1,143mm (45,00mil)" at -75.742,-170.296 h1.52
  text "PTH" at -46.033,-170.296 h1.52
  text "Round" at -33.184,-170.296 h1.52
  text "1-TOP - 8-BOTTOM" at -14.545,-170.296 h1.52
  text "Pad" at 15.672,-170.296 h1.52
  text "(Mixed)" at 30.654,-170.296 h1.52
  text "(Mixed)" at 58.332,-170.296 h1.52
  text "40" at -92.248,-174.106 h1.52
  text "1,067mm (42,00mil)" at -75.742,-174.106 h1.52
  text "PTH" at -46.033,-174.106 h1.52
  text "Round" at -33.184,-174.106 h1.52
  text "1-TOP - 8-BOTTOM" at -14.545,-174.106 h1.52
  text "Pad" at 15.672,-174.106 h1.52
  text "(Mixed)" at 30.654,-174.106 h1.52
  text "(Mixed)" at 58.332,-174.106 h1.52
  text "40" at -92.248,-177.916 h1.52
  text "1,194mm (47,00mil)" at -75.742,-177.916 h1.52
  text "PTH" at -46.033,-177.916 h1.52
  text "Round" at -33.184,-177.916 h1.52
  text "1-TOP - 8-BOTTOM" at -14.545,-177.916 h1.52
  text "Pad" at 15.672,-177.916 h1.52
  text "(Mixed)" at 30.654,-177.916 h1.52
  text "(Mixed)" at 58.332,-177.916 h1.52
  text "83" at -92.248,-181.726 h1.52
  text "1,000mm (39,37mil)" at -75.742,-181.726 h1.52
  text "PTH" at -46.033,-181.726 h1.52
  text "Round" at -33.184,-181.726 h1.52
  text "1-TOP - 8-BOTTOM" at -14.545,-181.726 h1.52
  text "Pad" at 15.672,-181.726 h1.52
  text "(Mixed)" at 30.654,-181.726 h1.52
  text "(Mixed)" at 58.332,-181.726 h1.52
  text "E" at -105.836,-181.98 h1.69
  text "253" at -92.248,-185.536 h1.52
  text "0,300mm (11,81mil)" at -75.742,-185.536 h1.52
  text "PTH" at -46.033,-185.536 h1.52
  text "Round" at -33.184,-185.536 h1.52
  text "1-TOP - 8-BOTTOM" at -14.545,-185.536 h1.52
  text "Via" at 15.672,-185.536 h1.52
  text "Rounded" at 30.654,-185.536 h1.52
  text "v68h30m54" at 58.332,-185.536 h1.52
  text "1453" at -92.248,-189.346 h1.52
  text "0,200mm (7,87mil)" at -75.742,-189.346 h1.52
  text "PTH" at -46.033,-189.346 h1.52
  text "Round" at -33.184,-189.346 h1.52
  text "1-TOP - 8-BOTTOM" at -14.545,-189.346 h1.52
  text "Via" at 15.672,-189.346 h1.52
  text "Rounded" at 30.654,-189.346 h1.52
  text "v50h20m39" at 58.332,-189.346 h1.52
  text "1990 Total" at -92.248,-193.156 h1.52
  text "Slot definitions :" at -105.097,-196.838 h1.52
  text "Routed Path Length" at -78.867,-196.838 h1.52
  text "= Calculated from tool start centre position to tool end centre position." at -50.859,-196.838 h1.52
  text "Hole Length" at -78.867,-199.378 h1.52
  text "= Routed Path Length + Tool Size = Slot length as defined in the PCB layout" at -61.27,-199.378 h1.52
